VERSION 5.8 ;
BUSBITCHARS "[]" ;
DIVIDERCHAR "/" ;
UNITS
    DATABASE MICRONS 1000 ;
END UNITS

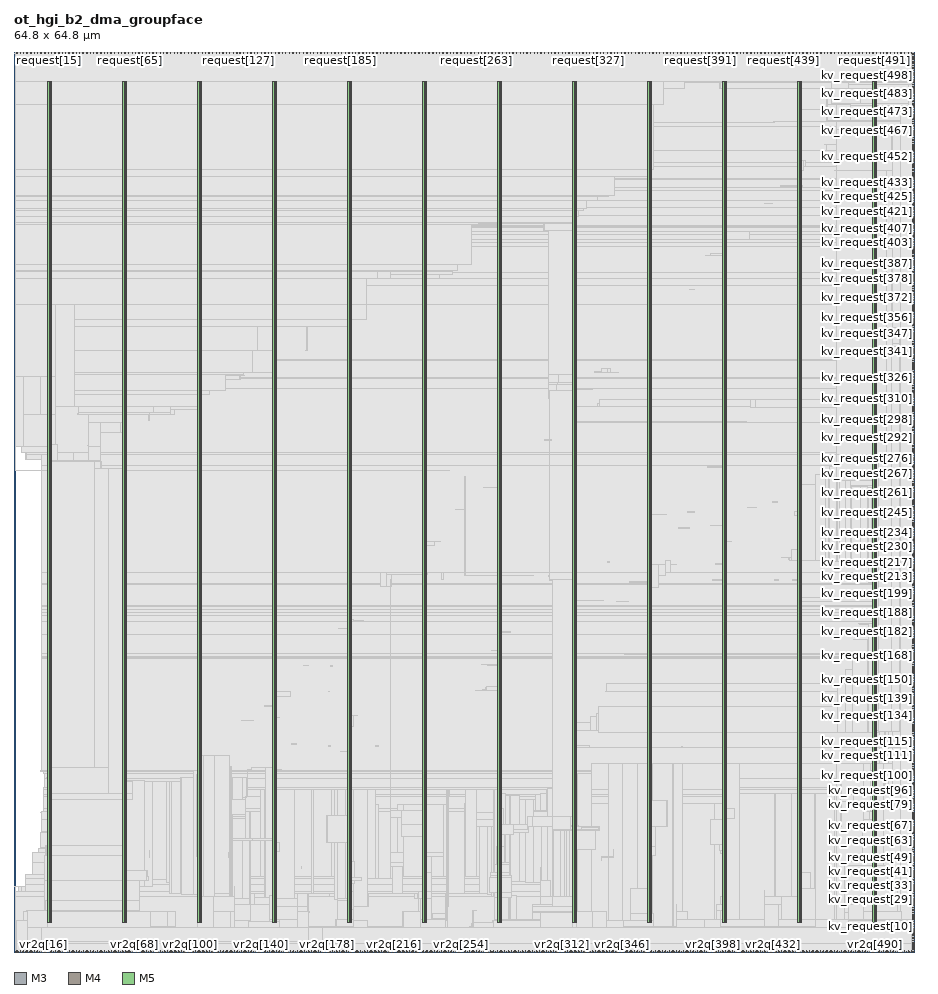
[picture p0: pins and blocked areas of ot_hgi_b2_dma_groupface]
MACRO ot_hgi_b2_dma_groupface
  FOREIGN ot_hgi_b2_dma_groupface 0 0 ;
  CLASS BLOCK ;
  SIZE 64.8 BY 64.8 ;
  PIN clk
    DIRECTION INPUT ;
    USE SIGNAL ;
    PORT
      LAYER M3 ;
        RECT  0.072 64.762 0.09 64.8 ;
    END
  END clk
  PIN kv_request[0]
    DIRECTION INPUT ;
    USE SIGNAL ;
    PORT
      LAYER M4 ;
        RECT  64.716 0.048 64.8 0.072 ;
    END
  END kv_request[0]
  PIN kv_request[100]
    DIRECTION INPUT ;
    USE SIGNAL ;
    PORT
      LAYER M4 ;
        RECT  64.716 12.72 64.8 12.744 ;
    END
  END kv_request[100]
  PIN kv_request[101]
    DIRECTION INPUT ;
    USE SIGNAL ;
    PORT
      LAYER M4 ;
        RECT  64.716 12.816 64.8 12.84 ;
    END
  END kv_request[101]
  PIN kv_request[102]
    DIRECTION INPUT ;
    USE SIGNAL ;
    PORT
      LAYER M4 ;
        RECT  64.716 12.96 64.8 12.984 ;
    END
  END kv_request[102]
  PIN kv_request[103]
    DIRECTION INPUT ;
    USE SIGNAL ;
    PORT
      LAYER M4 ;
        RECT  64.716 13.104 64.8 13.128 ;
    END
  END kv_request[103]
  PIN kv_request[104]
    DIRECTION INPUT ;
    USE SIGNAL ;
    PORT
      LAYER M4 ;
        RECT  64.716 13.2 64.8 13.224 ;
    END
  END kv_request[104]
  PIN kv_request[105]
    DIRECTION INPUT ;
    USE SIGNAL ;
    PORT
      LAYER M4 ;
        RECT  64.716 13.344 64.8 13.368 ;
    END
  END kv_request[105]
  PIN kv_request[106]
    DIRECTION INPUT ;
    USE SIGNAL ;
    PORT
      LAYER M4 ;
        RECT  64.716 13.488 64.8 13.512 ;
    END
  END kv_request[106]
  PIN kv_request[107]
    DIRECTION INPUT ;
    USE SIGNAL ;
    PORT
      LAYER M4 ;
        RECT  64.716 13.584 64.8 13.608 ;
    END
  END kv_request[107]
  PIN kv_request[108]
    DIRECTION INPUT ;
    USE SIGNAL ;
    PORT
      LAYER M4 ;
        RECT  64.716 13.728 64.8 13.752 ;
    END
  END kv_request[108]
  PIN kv_request[109]
    DIRECTION INPUT ;
    USE SIGNAL ;
    PORT
      LAYER M4 ;
        RECT  64.716 13.824 64.8 13.848 ;
    END
  END kv_request[109]
  PIN kv_request[10]
    DIRECTION INPUT ;
    USE SIGNAL ;
    PORT
      LAYER M4 ;
        RECT  64.716 1.296 64.8 1.32 ;
    END
  END kv_request[10]
  PIN kv_request[110]
    DIRECTION INPUT ;
    USE SIGNAL ;
    PORT
      LAYER M4 ;
        RECT  64.716 13.968 64.8 13.992 ;
    END
  END kv_request[110]
  PIN kv_request[111]
    DIRECTION INPUT ;
    USE SIGNAL ;
    PORT
      LAYER M4 ;
        RECT  64.716 14.112 64.8 14.136 ;
    END
  END kv_request[111]
  PIN kv_request[112]
    DIRECTION INPUT ;
    USE SIGNAL ;
    PORT
      LAYER M4 ;
        RECT  64.716 14.208 64.8 14.232 ;
    END
  END kv_request[112]
  PIN kv_request[113]
    DIRECTION INPUT ;
    USE SIGNAL ;
    PORT
      LAYER M4 ;
        RECT  64.716 14.352 64.8 14.376 ;
    END
  END kv_request[113]
  PIN kv_request[114]
    DIRECTION INPUT ;
    USE SIGNAL ;
    PORT
      LAYER M4 ;
        RECT  64.716 14.496 64.8 14.52 ;
    END
  END kv_request[114]
  PIN kv_request[115]
    DIRECTION INPUT ;
    USE SIGNAL ;
    PORT
      LAYER M4 ;
        RECT  64.716 14.592 64.8 14.616 ;
    END
  END kv_request[115]
  PIN kv_request[116]
    DIRECTION INPUT ;
    USE SIGNAL ;
    PORT
      LAYER M4 ;
        RECT  64.716 14.736 64.8 14.76 ;
    END
  END kv_request[116]
  PIN kv_request[117]
    DIRECTION INPUT ;
    USE SIGNAL ;
    PORT
      LAYER M4 ;
        RECT  64.716 14.88 64.8 14.904 ;
    END
  END kv_request[117]
  PIN kv_request[118]
    DIRECTION INPUT ;
    USE SIGNAL ;
    PORT
      LAYER M4 ;
        RECT  64.716 14.976 64.8 15 ;
    END
  END kv_request[118]
  PIN kv_request[119]
    DIRECTION INPUT ;
    USE SIGNAL ;
    PORT
      LAYER M4 ;
        RECT  64.716 15.12 64.8 15.144 ;
    END
  END kv_request[119]
  PIN kv_request[11]
    DIRECTION INPUT ;
    USE SIGNAL ;
    PORT
      LAYER M4 ;
        RECT  64.716 1.44 64.8 1.464 ;
    END
  END kv_request[11]
  PIN kv_request[120]
    DIRECTION INPUT ;
    USE SIGNAL ;
    PORT
      LAYER M4 ;
        RECT  64.716 15.216 64.8 15.24 ;
    END
  END kv_request[120]
  PIN kv_request[121]
    DIRECTION INPUT ;
    USE SIGNAL ;
    PORT
      LAYER M4 ;
        RECT  64.716 15.36 64.8 15.384 ;
    END
  END kv_request[121]
  PIN kv_request[122]
    DIRECTION INPUT ;
    USE SIGNAL ;
    PORT
      LAYER M4 ;
        RECT  64.716 15.504 64.8 15.528 ;
    END
  END kv_request[122]
  PIN kv_request[123]
    DIRECTION INPUT ;
    USE SIGNAL ;
    PORT
      LAYER M4 ;
        RECT  64.716 15.6 64.8 15.624 ;
    END
  END kv_request[123]
  PIN kv_request[124]
    DIRECTION INPUT ;
    USE SIGNAL ;
    PORT
      LAYER M4 ;
        RECT  64.716 15.744 64.8 15.768 ;
    END
  END kv_request[124]
  PIN kv_request[125]
    DIRECTION INPUT ;
    USE SIGNAL ;
    PORT
      LAYER M4 ;
        RECT  64.716 15.888 64.8 15.912 ;
    END
  END kv_request[125]
  PIN kv_request[126]
    DIRECTION INPUT ;
    USE SIGNAL ;
    PORT
      LAYER M4 ;
        RECT  64.716 15.984 64.8 16.008 ;
    END
  END kv_request[126]
  PIN kv_request[127]
    DIRECTION INPUT ;
    USE SIGNAL ;
    PORT
      LAYER M4 ;
        RECT  64.716 16.128 64.8 16.152 ;
    END
  END kv_request[127]
  PIN kv_request[128]
    DIRECTION INPUT ;
    USE SIGNAL ;
    PORT
      LAYER M4 ;
        RECT  64.716 16.272 64.8 16.296 ;
    END
  END kv_request[128]
  PIN kv_request[129]
    DIRECTION INPUT ;
    USE SIGNAL ;
    PORT
      LAYER M4 ;
        RECT  64.716 16.368 64.8 16.392 ;
    END
  END kv_request[129]
  PIN kv_request[12]
    DIRECTION INPUT ;
    USE SIGNAL ;
    PORT
      LAYER M4 ;
        RECT  64.716 1.584 64.8 1.608 ;
    END
  END kv_request[12]
  PIN kv_request[130]
    DIRECTION INPUT ;
    USE SIGNAL ;
    PORT
      LAYER M4 ;
        RECT  64.716 16.512 64.8 16.536 ;
    END
  END kv_request[130]
  PIN kv_request[131]
    DIRECTION INPUT ;
    USE SIGNAL ;
    PORT
      LAYER M4 ;
        RECT  64.716 16.608 64.8 16.632 ;
    END
  END kv_request[131]
  PIN kv_request[132]
    DIRECTION INPUT ;
    USE SIGNAL ;
    PORT
      LAYER M4 ;
        RECT  64.716 16.752 64.8 16.776 ;
    END
  END kv_request[132]
  PIN kv_request[133]
    DIRECTION INPUT ;
    USE SIGNAL ;
    PORT
      LAYER M4 ;
        RECT  64.716 16.896 64.8 16.92 ;
    END
  END kv_request[133]
  PIN kv_request[134]
    DIRECTION INPUT ;
    USE SIGNAL ;
    PORT
      LAYER M4 ;
        RECT  64.716 16.992 64.8 17.016 ;
    END
  END kv_request[134]
  PIN kv_request[135]
    DIRECTION INPUT ;
    USE SIGNAL ;
    PORT
      LAYER M4 ;
        RECT  64.716 17.136 64.8 17.16 ;
    END
  END kv_request[135]
  PIN kv_request[136]
    DIRECTION INPUT ;
    USE SIGNAL ;
    PORT
      LAYER M4 ;
        RECT  64.716 17.28 64.8 17.304 ;
    END
  END kv_request[136]
  PIN kv_request[137]
    DIRECTION INPUT ;
    USE SIGNAL ;
    PORT
      LAYER M4 ;
        RECT  64.716 17.376 64.8 17.4 ;
    END
  END kv_request[137]
  PIN kv_request[138]
    DIRECTION INPUT ;
    USE SIGNAL ;
    PORT
      LAYER M4 ;
        RECT  64.716 17.52 64.8 17.544 ;
    END
  END kv_request[138]
  PIN kv_request[139]
    DIRECTION INPUT ;
    USE SIGNAL ;
    PORT
      LAYER M4 ;
        RECT  64.716 17.664 64.8 17.688 ;
    END
  END kv_request[139]
  PIN kv_request[13]
    DIRECTION INPUT ;
    USE SIGNAL ;
    PORT
      LAYER M4 ;
        RECT  64.716 1.68 64.8 1.704 ;
    END
  END kv_request[13]
  PIN kv_request[140]
    DIRECTION INPUT ;
    USE SIGNAL ;
    PORT
      LAYER M4 ;
        RECT  64.716 17.76 64.8 17.784 ;
    END
  END kv_request[140]
  PIN kv_request[141]
    DIRECTION INPUT ;
    USE SIGNAL ;
    PORT
      LAYER M4 ;
        RECT  64.716 17.904 64.8 17.928 ;
    END
  END kv_request[141]
  PIN kv_request[142]
    DIRECTION INPUT ;
    USE SIGNAL ;
    PORT
      LAYER M4 ;
        RECT  64.716 18 64.8 18.024 ;
    END
  END kv_request[142]
  PIN kv_request[143]
    DIRECTION INPUT ;
    USE SIGNAL ;
    PORT
      LAYER M4 ;
        RECT  64.716 18.144 64.8 18.168 ;
    END
  END kv_request[143]
  PIN kv_request[144]
    DIRECTION INPUT ;
    USE SIGNAL ;
    PORT
      LAYER M4 ;
        RECT  64.716 18.288 64.8 18.312 ;
    END
  END kv_request[144]
  PIN kv_request[145]
    DIRECTION INPUT ;
    USE SIGNAL ;
    PORT
      LAYER M4 ;
        RECT  64.716 18.384 64.8 18.408 ;
    END
  END kv_request[145]
  PIN kv_request[146]
    DIRECTION INPUT ;
    USE SIGNAL ;
    PORT
      LAYER M4 ;
        RECT  64.716 18.528 64.8 18.552 ;
    END
  END kv_request[146]
  PIN kv_request[147]
    DIRECTION INPUT ;
    USE SIGNAL ;
    PORT
      LAYER M4 ;
        RECT  64.716 18.672 64.8 18.696 ;
    END
  END kv_request[147]
  PIN kv_request[148]
    DIRECTION INPUT ;
    USE SIGNAL ;
    PORT
      LAYER M4 ;
        RECT  64.716 18.768 64.8 18.792 ;
    END
  END kv_request[148]
  PIN kv_request[149]
    DIRECTION INPUT ;
    USE SIGNAL ;
    PORT
      LAYER M4 ;
        RECT  64.716 18.912 64.8 18.936 ;
    END
  END kv_request[149]
  PIN kv_request[14]
    DIRECTION INPUT ;
    USE SIGNAL ;
    PORT
      LAYER M4 ;
        RECT  64.716 1.824 64.8 1.848 ;
    END
  END kv_request[14]
  PIN kv_request[150]
    DIRECTION INPUT ;
    USE SIGNAL ;
    PORT
      LAYER M4 ;
        RECT  64.716 19.056 64.8 19.08 ;
    END
  END kv_request[150]
  PIN kv_request[151]
    DIRECTION INPUT ;
    USE SIGNAL ;
    PORT
      LAYER M4 ;
        RECT  64.716 19.152 64.8 19.176 ;
    END
  END kv_request[151]
  PIN kv_request[152]
    DIRECTION INPUT ;
    USE SIGNAL ;
    PORT
      LAYER M4 ;
        RECT  64.716 19.296 64.8 19.32 ;
    END
  END kv_request[152]
  PIN kv_request[153]
    DIRECTION INPUT ;
    USE SIGNAL ;
    PORT
      LAYER M4 ;
        RECT  64.716 19.392 64.8 19.416 ;
    END
  END kv_request[153]
  PIN kv_request[154]
    DIRECTION INPUT ;
    USE SIGNAL ;
    PORT
      LAYER M4 ;
        RECT  64.716 19.536 64.8 19.56 ;
    END
  END kv_request[154]
  PIN kv_request[155]
    DIRECTION INPUT ;
    USE SIGNAL ;
    PORT
      LAYER M4 ;
        RECT  64.716 19.68 64.8 19.704 ;
    END
  END kv_request[155]
  PIN kv_request[156]
    DIRECTION INPUT ;
    USE SIGNAL ;
    PORT
      LAYER M4 ;
        RECT  64.716 19.776 64.8 19.8 ;
    END
  END kv_request[156]
  PIN kv_request[157]
    DIRECTION INPUT ;
    USE SIGNAL ;
    PORT
      LAYER M4 ;
        RECT  64.716 19.92 64.8 19.944 ;
    END
  END kv_request[157]
  PIN kv_request[158]
    DIRECTION INPUT ;
    USE SIGNAL ;
    PORT
      LAYER M4 ;
        RECT  64.716 20.064 64.8 20.088 ;
    END
  END kv_request[158]
  PIN kv_request[159]
    DIRECTION INPUT ;
    USE SIGNAL ;
    PORT
      LAYER M4 ;
        RECT  64.716 20.16 64.8 20.184 ;
    END
  END kv_request[159]
  PIN kv_request[15]
    DIRECTION INPUT ;
    USE SIGNAL ;
    PORT
      LAYER M4 ;
        RECT  64.716 1.968 64.8 1.992 ;
    END
  END kv_request[15]
  PIN kv_request[160]
    DIRECTION INPUT ;
    USE SIGNAL ;
    PORT
      LAYER M4 ;
        RECT  64.716 20.304 64.8 20.328 ;
    END
  END kv_request[160]
  PIN kv_request[161]
    DIRECTION INPUT ;
    USE SIGNAL ;
    PORT
      LAYER M4 ;
        RECT  64.716 20.448 64.8 20.472 ;
    END
  END kv_request[161]
  PIN kv_request[162]
    DIRECTION INPUT ;
    USE SIGNAL ;
    PORT
      LAYER M4 ;
        RECT  64.716 20.544 64.8 20.568 ;
    END
  END kv_request[162]
  PIN kv_request[163]
    DIRECTION INPUT ;
    USE SIGNAL ;
    PORT
      LAYER M4 ;
        RECT  64.716 20.688 64.8 20.712 ;
    END
  END kv_request[163]
  PIN kv_request[164]
    DIRECTION INPUT ;
    USE SIGNAL ;
    PORT
      LAYER M4 ;
        RECT  64.716 20.832 64.8 20.856 ;
    END
  END kv_request[164]
  PIN kv_request[165]
    DIRECTION INPUT ;
    USE SIGNAL ;
    PORT
      LAYER M4 ;
        RECT  64.716 20.928 64.8 20.952 ;
    END
  END kv_request[165]
  PIN kv_request[166]
    DIRECTION INPUT ;
    USE SIGNAL ;
    PORT
      LAYER M4 ;
        RECT  64.716 21.072 64.8 21.096 ;
    END
  END kv_request[166]
  PIN kv_request[167]
    DIRECTION INPUT ;
    USE SIGNAL ;
    PORT
      LAYER M4 ;
        RECT  64.716 21.168 64.8 21.192 ;
    END
  END kv_request[167]
  PIN kv_request[168]
    DIRECTION INPUT ;
    USE SIGNAL ;
    PORT
      LAYER M4 ;
        RECT  64.716 21.312 64.8 21.336 ;
    END
  END kv_request[168]
  PIN kv_request[169]
    DIRECTION INPUT ;
    USE SIGNAL ;
    PORT
      LAYER M4 ;
        RECT  64.716 21.456 64.8 21.48 ;
    END
  END kv_request[169]
  PIN kv_request[16]
    DIRECTION INPUT ;
    USE SIGNAL ;
    PORT
      LAYER M4 ;
        RECT  64.716 2.064 64.8 2.088 ;
    END
  END kv_request[16]
  PIN kv_request[170]
    DIRECTION INPUT ;
    USE SIGNAL ;
    PORT
      LAYER M4 ;
        RECT  64.716 21.552 64.8 21.576 ;
    END
  END kv_request[170]
  PIN kv_request[171]
    DIRECTION INPUT ;
    USE SIGNAL ;
    PORT
      LAYER M4 ;
        RECT  64.716 21.696 64.8 21.72 ;
    END
  END kv_request[171]
  PIN kv_request[172]
    DIRECTION INPUT ;
    USE SIGNAL ;
    PORT
      LAYER M4 ;
        RECT  64.716 21.84 64.8 21.864 ;
    END
  END kv_request[172]
  PIN kv_request[173]
    DIRECTION INPUT ;
    USE SIGNAL ;
    PORT
      LAYER M4 ;
        RECT  64.716 21.936 64.8 21.96 ;
    END
  END kv_request[173]
  PIN kv_request[174]
    DIRECTION INPUT ;
    USE SIGNAL ;
    PORT
      LAYER M4 ;
        RECT  64.716 22.08 64.8 22.104 ;
    END
  END kv_request[174]
  PIN kv_request[175]
    DIRECTION INPUT ;
    USE SIGNAL ;
    PORT
      LAYER M4 ;
        RECT  64.716 22.224 64.8 22.248 ;
    END
  END kv_request[175]
  PIN kv_request[176]
    DIRECTION INPUT ;
    USE SIGNAL ;
    PORT
      LAYER M4 ;
        RECT  64.716 22.32 64.8 22.344 ;
    END
  END kv_request[176]
  PIN kv_request[177]
    DIRECTION INPUT ;
    USE SIGNAL ;
    PORT
      LAYER M4 ;
        RECT  64.716 22.464 64.8 22.488 ;
    END
  END kv_request[177]
  PIN kv_request[178]
    DIRECTION INPUT ;
    USE SIGNAL ;
    PORT
      LAYER M4 ;
        RECT  64.716 22.56 64.8 22.584 ;
    END
  END kv_request[178]
  PIN kv_request[179]
    DIRECTION INPUT ;
    USE SIGNAL ;
    PORT
      LAYER M4 ;
        RECT  64.716 22.704 64.8 22.728 ;
    END
  END kv_request[179]
  PIN kv_request[17]
    DIRECTION INPUT ;
    USE SIGNAL ;
    PORT
      LAYER M4 ;
        RECT  64.716 2.208 64.8 2.232 ;
    END
  END kv_request[17]
  PIN kv_request[180]
    DIRECTION INPUT ;
    USE SIGNAL ;
    PORT
      LAYER M4 ;
        RECT  64.716 22.848 64.8 22.872 ;
    END
  END kv_request[180]
  PIN kv_request[181]
    DIRECTION INPUT ;
    USE SIGNAL ;
    PORT
      LAYER M4 ;
        RECT  64.716 22.944 64.8 22.968 ;
    END
  END kv_request[181]
  PIN kv_request[182]
    DIRECTION INPUT ;
    USE SIGNAL ;
    PORT
      LAYER M4 ;
        RECT  64.716 23.088 64.8 23.112 ;
    END
  END kv_request[182]
  PIN kv_request[183]
    DIRECTION INPUT ;
    USE SIGNAL ;
    PORT
      LAYER M4 ;
        RECT  64.716 23.232 64.8 23.256 ;
    END
  END kv_request[183]
  PIN kv_request[184]
    DIRECTION INPUT ;
    USE SIGNAL ;
    PORT
      LAYER M4 ;
        RECT  64.716 23.328 64.8 23.352 ;
    END
  END kv_request[184]
  PIN kv_request[185]
    DIRECTION INPUT ;
    USE SIGNAL ;
    PORT
      LAYER M4 ;
        RECT  64.716 23.472 64.8 23.496 ;
    END
  END kv_request[185]
  PIN kv_request[186]
    DIRECTION INPUT ;
    USE SIGNAL ;
    PORT
      LAYER M4 ;
        RECT  64.716 23.616 64.8 23.64 ;
    END
  END kv_request[186]
  PIN kv_request[187]
    DIRECTION INPUT ;
    USE SIGNAL ;
    PORT
      LAYER M4 ;
        RECT  64.716 23.712 64.8 23.736 ;
    END
  END kv_request[187]
  PIN kv_request[188]
    DIRECTION INPUT ;
    USE SIGNAL ;
    PORT
      LAYER M4 ;
        RECT  64.716 23.856 64.8 23.88 ;
    END
  END kv_request[188]
  PIN kv_request[189]
    DIRECTION INPUT ;
    USE SIGNAL ;
    PORT
      LAYER M4 ;
        RECT  64.716 23.952 64.8 23.976 ;
    END
  END kv_request[189]
  PIN kv_request[18]
    DIRECTION INPUT ;
    USE SIGNAL ;
    PORT
      LAYER M4 ;
        RECT  64.716 2.352 64.8 2.376 ;
    END
  END kv_request[18]
  PIN kv_request[190]
    DIRECTION INPUT ;
    USE SIGNAL ;
    PORT
      LAYER M4 ;
        RECT  64.716 24.096 64.8 24.12 ;
    END
  END kv_request[190]
  PIN kv_request[191]
    DIRECTION INPUT ;
    USE SIGNAL ;
    PORT
      LAYER M4 ;
        RECT  64.716 24.24 64.8 24.264 ;
    END
  END kv_request[191]
  PIN kv_request[192]
    DIRECTION INPUT ;
    USE SIGNAL ;
    PORT
      LAYER M4 ;
        RECT  64.716 24.336 64.8 24.36 ;
    END
  END kv_request[192]
  PIN kv_request[193]
    DIRECTION INPUT ;
    USE SIGNAL ;
    PORT
      LAYER M4 ;
        RECT  64.716 24.48 64.8 24.504 ;
    END
  END kv_request[193]
  PIN kv_request[194]
    DIRECTION INPUT ;
    USE SIGNAL ;
    PORT
      LAYER M4 ;
        RECT  64.716 24.624 64.8 24.648 ;
    END
  END kv_request[194]
  PIN kv_request[195]
    DIRECTION INPUT ;
    USE SIGNAL ;
    PORT
      LAYER M4 ;
        RECT  64.716 24.72 64.8 24.744 ;
    END
  END kv_request[195]
  PIN kv_request[196]
    DIRECTION INPUT ;
    USE SIGNAL ;
    PORT
      LAYER M4 ;
        RECT  64.716 24.864 64.8 24.888 ;
    END
  END kv_request[196]
  PIN kv_request[197]
    DIRECTION INPUT ;
    USE SIGNAL ;
    PORT
      LAYER M4 ;
        RECT  64.716 25.008 64.8 25.032 ;
    END
  END kv_request[197]
  PIN kv_request[198]
    DIRECTION INPUT ;
    USE SIGNAL ;
    PORT
      LAYER M4 ;
        RECT  64.716 25.104 64.8 25.128 ;
    END
  END kv_request[198]
  PIN kv_request[199]
    DIRECTION INPUT ;
    USE SIGNAL ;
    PORT
      LAYER M4 ;
        RECT  64.716 25.248 64.8 25.272 ;
    END
  END kv_request[199]
  PIN kv_request[19]
    DIRECTION INPUT ;
    USE SIGNAL ;
    PORT
      LAYER M4 ;
        RECT  64.716 2.448 64.8 2.472 ;
    END
  END kv_request[19]
  PIN kv_request[1]
    DIRECTION INPUT ;
    USE SIGNAL ;
    PORT
      LAYER M4 ;
        RECT  64.716 0.192 64.8 0.216 ;
    END
  END kv_request[1]
  PIN kv_request[200]
    DIRECTION INPUT ;
    USE SIGNAL ;
    PORT
      LAYER M4 ;
        RECT  64.716 25.344 64.8 25.368 ;
    END
  END kv_request[200]
  PIN kv_request[201]
    DIRECTION INPUT ;
    USE SIGNAL ;
    PORT
      LAYER M4 ;
        RECT  64.716 25.488 64.8 25.512 ;
    END
  END kv_request[201]
  PIN kv_request[202]
    DIRECTION INPUT ;
    USE SIGNAL ;
    PORT
      LAYER M4 ;
        RECT  64.716 25.632 64.8 25.656 ;
    END
  END kv_request[202]
  PIN kv_request[203]
    DIRECTION INPUT ;
    USE SIGNAL ;
    PORT
      LAYER M4 ;
        RECT  64.716 25.728 64.8 25.752 ;
    END
  END kv_request[203]
  PIN kv_request[204]
    DIRECTION INPUT ;
    USE SIGNAL ;
    PORT
      LAYER M4 ;
        RECT  64.716 25.872 64.8 25.896 ;
    END
  END kv_request[204]
  PIN kv_request[205]
    DIRECTION INPUT ;
    USE SIGNAL ;
    PORT
      LAYER M4 ;
        RECT  64.716 26.016 64.8 26.04 ;
    END
  END kv_request[205]
  PIN kv_request[206]
    DIRECTION INPUT ;
    USE SIGNAL ;
    PORT
      LAYER M4 ;
        RECT  64.716 26.112 64.8 26.136 ;
    END
  END kv_request[206]
  PIN kv_request[207]
    DIRECTION INPUT ;
    USE SIGNAL ;
    PORT
      LAYER M4 ;
        RECT  64.716 26.256 64.8 26.28 ;
    END
  END kv_request[207]
  PIN kv_request[208]
    DIRECTION INPUT ;
    USE SIGNAL ;
    PORT
      LAYER M4 ;
        RECT  64.716 26.4 64.8 26.424 ;
    END
  END kv_request[208]
  PIN kv_request[209]
    DIRECTION INPUT ;
    USE SIGNAL ;
    PORT
      LAYER M4 ;
        RECT  64.716 26.496 64.8 26.52 ;
    END
  END kv_request[209]
  PIN kv_request[20]
    DIRECTION INPUT ;
    USE SIGNAL ;
    PORT
      LAYER M4 ;
        RECT  64.716 2.592 64.8 2.616 ;
    END
  END kv_request[20]
  PIN kv_request[210]
    DIRECTION INPUT ;
    USE SIGNAL ;
    PORT
      LAYER M4 ;
        RECT  64.716 26.64 64.8 26.664 ;
    END
  END kv_request[210]
  PIN kv_request[211]
    DIRECTION INPUT ;
    USE SIGNAL ;
    PORT
      LAYER M4 ;
        RECT  64.716 26.736 64.8 26.76 ;
    END
  END kv_request[211]
  PIN kv_request[212]
    DIRECTION INPUT ;
    USE SIGNAL ;
    PORT
      LAYER M4 ;
        RECT  64.716 26.88 64.8 26.904 ;
    END
  END kv_request[212]
  PIN kv_request[213]
    DIRECTION INPUT ;
    USE SIGNAL ;
    PORT
      LAYER M4 ;
        RECT  64.716 27.024 64.8 27.048 ;
    END
  END kv_request[213]
  PIN kv_request[214]
    DIRECTION INPUT ;
    USE SIGNAL ;
    PORT
      LAYER M4 ;
        RECT  64.716 27.12 64.8 27.144 ;
    END
  END kv_request[214]
  PIN kv_request[215]
    DIRECTION INPUT ;
    USE SIGNAL ;
    PORT
      LAYER M4 ;
        RECT  64.716 27.264 64.8 27.288 ;
    END
  END kv_request[215]
  PIN kv_request[216]
    DIRECTION INPUT ;
    USE SIGNAL ;
    PORT
      LAYER M4 ;
        RECT  64.716 27.408 64.8 27.432 ;
    END
  END kv_request[216]
  PIN kv_request[217]
    DIRECTION INPUT ;
    USE SIGNAL ;
    PORT
      LAYER M4 ;
        RECT  64.716 27.504 64.8 27.528 ;
    END
  END kv_request[217]
  PIN kv_request[218]
    DIRECTION INPUT ;
    USE SIGNAL ;
    PORT
      LAYER M4 ;
        RECT  64.716 27.648 64.8 27.672 ;
    END
  END kv_request[218]
  PIN kv_request[219]
    DIRECTION INPUT ;
    USE SIGNAL ;
    PORT
      LAYER M4 ;
        RECT  64.716 27.792 64.8 27.816 ;
    END
  END kv_request[219]
  PIN kv_request[21]
    DIRECTION INPUT ;
    USE SIGNAL ;
    PORT
      LAYER M4 ;
        RECT  64.716 2.688 64.8 2.712 ;
    END
  END kv_request[21]
  PIN kv_request[220]
    DIRECTION INPUT ;
    USE SIGNAL ;
    PORT
      LAYER M4 ;
        RECT  64.716 27.888 64.8 27.912 ;
    END
  END kv_request[220]
  PIN kv_request[221]
    DIRECTION INPUT ;
    USE SIGNAL ;
    PORT
      LAYER M4 ;
        RECT  64.716 28.032 64.8 28.056 ;
    END
  END kv_request[221]
  PIN kv_request[222]
    DIRECTION INPUT ;
    USE SIGNAL ;
    PORT
      LAYER M4 ;
        RECT  64.716 28.128 64.8 28.152 ;
    END
  END kv_request[222]
  PIN kv_request[223]
    DIRECTION INPUT ;
    USE SIGNAL ;
    PORT
      LAYER M4 ;
        RECT  64.716 28.272 64.8 28.296 ;
    END
  END kv_request[223]
  PIN kv_request[224]
    DIRECTION INPUT ;
    USE SIGNAL ;
    PORT
      LAYER M4 ;
        RECT  64.716 28.416 64.8 28.44 ;
    END
  END kv_request[224]
  PIN kv_request[225]
    DIRECTION INPUT ;
    USE SIGNAL ;
    PORT
      LAYER M4 ;
        RECT  64.716 28.512 64.8 28.536 ;
    END
  END kv_request[225]
  PIN kv_request[226]
    DIRECTION INPUT ;
    USE SIGNAL ;
    PORT
      LAYER M4 ;
        RECT  64.716 28.656 64.8 28.68 ;
    END
  END kv_request[226]
  PIN kv_request[227]
    DIRECTION INPUT ;
    USE SIGNAL ;
    PORT
      LAYER M4 ;
        RECT  64.716 28.8 64.8 28.824 ;
    END
  END kv_request[227]
  PIN kv_request[228]
    DIRECTION INPUT ;
    USE SIGNAL ;
    PORT
      LAYER M4 ;
        RECT  64.716 28.896 64.8 28.92 ;
    END
  END kv_request[228]
  PIN kv_request[229]
    DIRECTION INPUT ;
    USE SIGNAL ;
    PORT
      LAYER M4 ;
        RECT  64.716 29.04 64.8 29.064 ;
    END
  END kv_request[229]
  PIN kv_request[22]
    DIRECTION INPUT ;
    USE SIGNAL ;
    PORT
      LAYER M4 ;
        RECT  64.716 2.832 64.8 2.856 ;
    END
  END kv_request[22]
  PIN kv_request[230]
    DIRECTION INPUT ;
    USE SIGNAL ;
    PORT
      LAYER M4 ;
        RECT  64.716 29.184 64.8 29.208 ;
    END
  END kv_request[230]
  PIN kv_request[231]
    DIRECTION INPUT ;
    USE SIGNAL ;
    PORT
      LAYER M4 ;
        RECT  64.716 29.28 64.8 29.304 ;
    END
  END kv_request[231]
  PIN kv_request[232]
    DIRECTION INPUT ;
    USE SIGNAL ;
    PORT
      LAYER M4 ;
        RECT  64.716 29.424 64.8 29.448 ;
    END
  END kv_request[232]
  PIN kv_request[233]
    DIRECTION INPUT ;
    USE SIGNAL ;
    PORT
      LAYER M4 ;
        RECT  64.716 29.52 64.8 29.544 ;
    END
  END kv_request[233]
  PIN kv_request[234]
    DIRECTION INPUT ;
    USE SIGNAL ;
    PORT
      LAYER M4 ;
        RECT  64.716 29.664 64.8 29.688 ;
    END
  END kv_request[234]
  PIN kv_request[235]
    DIRECTION INPUT ;
    USE SIGNAL ;
    PORT
      LAYER M4 ;
        RECT  64.716 29.808 64.8 29.832 ;
    END
  END kv_request[235]
  PIN kv_request[236]
    DIRECTION INPUT ;
    USE SIGNAL ;
    PORT
      LAYER M4 ;
        RECT  64.716 29.904 64.8 29.928 ;
    END
  END kv_request[236]
  PIN kv_request[237]
    DIRECTION INPUT ;
    USE SIGNAL ;
    PORT
      LAYER M4 ;
        RECT  64.716 30.048 64.8 30.072 ;
    END
  END kv_request[237]
  PIN kv_request[238]
    DIRECTION INPUT ;
    USE SIGNAL ;
    PORT
      LAYER M4 ;
        RECT  64.716 30.192 64.8 30.216 ;
    END
  END kv_request[238]
  PIN kv_request[239]
    DIRECTION INPUT ;
    USE SIGNAL ;
    PORT
      LAYER M4 ;
        RECT  64.716 30.288 64.8 30.312 ;
    END
  END kv_request[239]
  PIN kv_request[23]
    DIRECTION INPUT ;
    USE SIGNAL ;
    PORT
      LAYER M4 ;
        RECT  64.716 2.976 64.8 3 ;
    END
  END kv_request[23]
  PIN kv_request[240]
    DIRECTION INPUT ;
    USE SIGNAL ;
    PORT
      LAYER M4 ;
        RECT  64.716 30.432 64.8 30.456 ;
    END
  END kv_request[240]
  PIN kv_request[241]
    DIRECTION INPUT ;
    USE SIGNAL ;
    PORT
      LAYER M4 ;
        RECT  64.716 30.576 64.8 30.6 ;
    END
  END kv_request[241]
  PIN kv_request[242]
    DIRECTION INPUT ;
    USE SIGNAL ;
    PORT
      LAYER M4 ;
        RECT  64.716 30.672 64.8 30.696 ;
    END
  END kv_request[242]
  PIN kv_request[243]
    DIRECTION INPUT ;
    USE SIGNAL ;
    PORT
      LAYER M4 ;
        RECT  64.716 30.816 64.8 30.84 ;
    END
  END kv_request[243]
  PIN kv_request[244]
    DIRECTION INPUT ;
    USE SIGNAL ;
    PORT
      LAYER M4 ;
        RECT  64.716 30.912 64.8 30.936 ;
    END
  END kv_request[244]
  PIN kv_request[245]
    DIRECTION INPUT ;
    USE SIGNAL ;
    PORT
      LAYER M4 ;
        RECT  64.716 31.056 64.8 31.08 ;
    END
  END kv_request[245]
  PIN kv_request[246]
    DIRECTION INPUT ;
    USE SIGNAL ;
    PORT
      LAYER M4 ;
        RECT  64.716 31.2 64.8 31.224 ;
    END
  END kv_request[246]
  PIN kv_request[247]
    DIRECTION INPUT ;
    USE SIGNAL ;
    PORT
      LAYER M4 ;
        RECT  64.716 31.296 64.8 31.32 ;
    END
  END kv_request[247]
  PIN kv_request[248]
    DIRECTION INPUT ;
    USE SIGNAL ;
    PORT
      LAYER M4 ;
        RECT  64.716 31.44 64.8 31.464 ;
    END
  END kv_request[248]
  PIN kv_request[249]
    DIRECTION INPUT ;
    USE SIGNAL ;
    PORT
      LAYER M4 ;
        RECT  64.716 31.584 64.8 31.608 ;
    END
  END kv_request[249]
  PIN kv_request[24]
    DIRECTION INPUT ;
    USE SIGNAL ;
    PORT
      LAYER M4 ;
        RECT  64.716 3.072 64.8 3.096 ;
    END
  END kv_request[24]
  PIN kv_request[250]
    DIRECTION INPUT ;
    USE SIGNAL ;
    PORT
      LAYER M4 ;
        RECT  64.716 31.68 64.8 31.704 ;
    END
  END kv_request[250]
  PIN kv_request[251]
    DIRECTION INPUT ;
    USE SIGNAL ;
    PORT
      LAYER M4 ;
        RECT  64.716 31.824 64.8 31.848 ;
    END
  END kv_request[251]
  PIN kv_request[252]
    DIRECTION INPUT ;
    USE SIGNAL ;
    PORT
      LAYER M4 ;
        RECT  64.716 31.968 64.8 31.992 ;
    END
  END kv_request[252]
  PIN kv_request[253]
    DIRECTION INPUT ;
    USE SIGNAL ;
    PORT
      LAYER M4 ;
        RECT  64.716 32.064 64.8 32.088 ;
    END
  END kv_request[253]
  PIN kv_request[254]
    DIRECTION INPUT ;
    USE SIGNAL ;
    PORT
      LAYER M4 ;
        RECT  64.716 32.208 64.8 32.232 ;
    END
  END kv_request[254]
  PIN kv_request[255]
    DIRECTION INPUT ;
    USE SIGNAL ;
    PORT
      LAYER M4 ;
        RECT  64.716 32.304 64.8 32.328 ;
    END
  END kv_request[255]
  PIN kv_request[256]
    DIRECTION INPUT ;
    USE SIGNAL ;
    PORT
      LAYER M4 ;
        RECT  64.716 32.448 64.8 32.472 ;
    END
  END kv_request[256]
  PIN kv_request[257]
    DIRECTION INPUT ;
    USE SIGNAL ;
    PORT
      LAYER M4 ;
        RECT  64.716 32.592 64.8 32.616 ;
    END
  END kv_request[257]
  PIN kv_request[258]
    DIRECTION INPUT ;
    USE SIGNAL ;
    PORT
      LAYER M4 ;
        RECT  64.716 32.688 64.8 32.712 ;
    END
  END kv_request[258]
  PIN kv_request[259]
    DIRECTION INPUT ;
    USE SIGNAL ;
    PORT
      LAYER M4 ;
        RECT  64.716 32.832 64.8 32.856 ;
    END
  END kv_request[259]
  PIN kv_request[25]
    DIRECTION INPUT ;
    USE SIGNAL ;
    PORT
      LAYER M4 ;
        RECT  64.716 3.216 64.8 3.24 ;
    END
  END kv_request[25]
  PIN kv_request[260]
    DIRECTION INPUT ;
    USE SIGNAL ;
    PORT
      LAYER M4 ;
        RECT  64.716 32.976 64.8 33 ;
    END
  END kv_request[260]
  PIN kv_request[261]
    DIRECTION INPUT ;
    USE SIGNAL ;
    PORT
      LAYER M4 ;
        RECT  64.716 33.072 64.8 33.096 ;
    END
  END kv_request[261]
  PIN kv_request[262]
    DIRECTION INPUT ;
    USE SIGNAL ;
    PORT
      LAYER M4 ;
        RECT  64.716 33.216 64.8 33.24 ;
    END
  END kv_request[262]
  PIN kv_request[263]
    DIRECTION INPUT ;
    USE SIGNAL ;
    PORT
      LAYER M4 ;
        RECT  64.716 33.36 64.8 33.384 ;
    END
  END kv_request[263]
  PIN kv_request[264]
    DIRECTION INPUT ;
    USE SIGNAL ;
    PORT
      LAYER M4 ;
        RECT  64.716 33.456 64.8 33.48 ;
    END
  END kv_request[264]
  PIN kv_request[265]
    DIRECTION INPUT ;
    USE SIGNAL ;
    PORT
      LAYER M4 ;
        RECT  64.716 33.6 64.8 33.624 ;
    END
  END kv_request[265]
  PIN kv_request[266]
    DIRECTION INPUT ;
    USE SIGNAL ;
    PORT
      LAYER M4 ;
        RECT  64.716 33.696 64.8 33.72 ;
    END
  END kv_request[266]
  PIN kv_request[267]
    DIRECTION INPUT ;
    USE SIGNAL ;
    PORT
      LAYER M4 ;
        RECT  64.716 33.84 64.8 33.864 ;
    END
  END kv_request[267]
  PIN kv_request[268]
    DIRECTION INPUT ;
    USE SIGNAL ;
    PORT
      LAYER M4 ;
        RECT  64.716 33.984 64.8 34.008 ;
    END
  END kv_request[268]
  PIN kv_request[269]
    DIRECTION INPUT ;
    USE SIGNAL ;
    PORT
      LAYER M4 ;
        RECT  64.716 34.08 64.8 34.104 ;
    END
  END kv_request[269]
  PIN kv_request[26]
    DIRECTION INPUT ;
    USE SIGNAL ;
    PORT
      LAYER M4 ;
        RECT  64.716 3.36 64.8 3.384 ;
    END
  END kv_request[26]
  PIN kv_request[270]
    DIRECTION INPUT ;
    USE SIGNAL ;
    PORT
      LAYER M4 ;
        RECT  64.716 34.224 64.8 34.248 ;
    END
  END kv_request[270]
  PIN kv_request[271]
    DIRECTION INPUT ;
    USE SIGNAL ;
    PORT
      LAYER M4 ;
        RECT  64.716 34.368 64.8 34.392 ;
    END
  END kv_request[271]
  PIN kv_request[272]
    DIRECTION INPUT ;
    USE SIGNAL ;
    PORT
      LAYER M4 ;
        RECT  64.716 34.464 64.8 34.488 ;
    END
  END kv_request[272]
  PIN kv_request[273]
    DIRECTION INPUT ;
    USE SIGNAL ;
    PORT
      LAYER M4 ;
        RECT  64.716 34.608 64.8 34.632 ;
    END
  END kv_request[273]
  PIN kv_request[274]
    DIRECTION INPUT ;
    USE SIGNAL ;
    PORT
      LAYER M4 ;
        RECT  64.716 34.752 64.8 34.776 ;
    END
  END kv_request[274]
  PIN kv_request[275]
    DIRECTION INPUT ;
    USE SIGNAL ;
    PORT
      LAYER M4 ;
        RECT  64.716 34.848 64.8 34.872 ;
    END
  END kv_request[275]
  PIN kv_request[276]
    DIRECTION INPUT ;
    USE SIGNAL ;
    PORT
      LAYER M4 ;
        RECT  64.716 34.992 64.8 35.016 ;
    END
  END kv_request[276]
  PIN kv_request[277]
    DIRECTION INPUT ;
    USE SIGNAL ;
    PORT
      LAYER M4 ;
        RECT  64.716 35.088 64.8 35.112 ;
    END
  END kv_request[277]
  PIN kv_request[278]
    DIRECTION INPUT ;
    USE SIGNAL ;
    PORT
      LAYER M4 ;
        RECT  64.716 35.232 64.8 35.256 ;
    END
  END kv_request[278]
  PIN kv_request[279]
    DIRECTION INPUT ;
    USE SIGNAL ;
    PORT
      LAYER M4 ;
        RECT  64.716 35.376 64.8 35.4 ;
    END
  END kv_request[279]
  PIN kv_request[27]
    DIRECTION INPUT ;
    USE SIGNAL ;
    PORT
      LAYER M4 ;
        RECT  64.716 3.456 64.8 3.48 ;
    END
  END kv_request[27]
  PIN kv_request[280]
    DIRECTION INPUT ;
    USE SIGNAL ;
    PORT
      LAYER M4 ;
        RECT  64.716 35.472 64.8 35.496 ;
    END
  END kv_request[280]
  PIN kv_request[281]
    DIRECTION INPUT ;
    USE SIGNAL ;
    PORT
      LAYER M4 ;
        RECT  64.716 35.616 64.8 35.64 ;
    END
  END kv_request[281]
  PIN kv_request[282]
    DIRECTION INPUT ;
    USE SIGNAL ;
    PORT
      LAYER M4 ;
        RECT  64.716 35.76 64.8 35.784 ;
    END
  END kv_request[282]
  PIN kv_request[283]
    DIRECTION INPUT ;
    USE SIGNAL ;
    PORT
      LAYER M4 ;
        RECT  64.716 35.856 64.8 35.88 ;
    END
  END kv_request[283]
  PIN kv_request[284]
    DIRECTION INPUT ;
    USE SIGNAL ;
    PORT
      LAYER M4 ;
        RECT  64.716 36 64.8 36.024 ;
    END
  END kv_request[284]
  PIN kv_request[285]
    DIRECTION INPUT ;
    USE SIGNAL ;
    PORT
      LAYER M4 ;
        RECT  64.716 36.144 64.8 36.168 ;
    END
  END kv_request[285]
  PIN kv_request[286]
    DIRECTION INPUT ;
    USE SIGNAL ;
    PORT
      LAYER M4 ;
        RECT  64.716 36.24 64.8 36.264 ;
    END
  END kv_request[286]
  PIN kv_request[287]
    DIRECTION INPUT ;
    USE SIGNAL ;
    PORT
      LAYER M4 ;
        RECT  64.716 36.384 64.8 36.408 ;
    END
  END kv_request[287]
  PIN kv_request[288]
    DIRECTION INPUT ;
    USE SIGNAL ;
    PORT
      LAYER M4 ;
        RECT  64.716 36.48 64.8 36.504 ;
    END
  END kv_request[288]
  PIN kv_request[289]
    DIRECTION INPUT ;
    USE SIGNAL ;
    PORT
      LAYER M4 ;
        RECT  64.716 36.624 64.8 36.648 ;
    END
  END kv_request[289]
  PIN kv_request[28]
    DIRECTION INPUT ;
    USE SIGNAL ;
    PORT
      LAYER M4 ;
        RECT  64.716 3.6 64.8 3.624 ;
    END
  END kv_request[28]
  PIN kv_request[290]
    DIRECTION INPUT ;
    USE SIGNAL ;
    PORT
      LAYER M4 ;
        RECT  64.716 36.768 64.8 36.792 ;
    END
  END kv_request[290]
  PIN kv_request[291]
    DIRECTION INPUT ;
    USE SIGNAL ;
    PORT
      LAYER M4 ;
        RECT  64.716 36.864 64.8 36.888 ;
    END
  END kv_request[291]
  PIN kv_request[292]
    DIRECTION INPUT ;
    USE SIGNAL ;
    PORT
      LAYER M4 ;
        RECT  64.716 37.008 64.8 37.032 ;
    END
  END kv_request[292]
  PIN kv_request[293]
    DIRECTION INPUT ;
    USE SIGNAL ;
    PORT
      LAYER M4 ;
        RECT  64.716 37.152 64.8 37.176 ;
    END
  END kv_request[293]
  PIN kv_request[294]
    DIRECTION INPUT ;
    USE SIGNAL ;
    PORT
      LAYER M4 ;
        RECT  64.716 37.248 64.8 37.272 ;
    END
  END kv_request[294]
  PIN kv_request[295]
    DIRECTION INPUT ;
    USE SIGNAL ;
    PORT
      LAYER M4 ;
        RECT  64.716 37.392 64.8 37.416 ;
    END
  END kv_request[295]
  PIN kv_request[296]
    DIRECTION INPUT ;
    USE SIGNAL ;
    PORT
      LAYER M4 ;
        RECT  64.716 37.536 64.8 37.56 ;
    END
  END kv_request[296]
  PIN kv_request[297]
    DIRECTION INPUT ;
    USE SIGNAL ;
    PORT
      LAYER M4 ;
        RECT  64.716 37.632 64.8 37.656 ;
    END
  END kv_request[297]
  PIN kv_request[298]
    DIRECTION INPUT ;
    USE SIGNAL ;
    PORT
      LAYER M4 ;
        RECT  64.716 37.776 64.8 37.8 ;
    END
  END kv_request[298]
  PIN kv_request[299]
    DIRECTION INPUT ;
    USE SIGNAL ;
    PORT
      LAYER M4 ;
        RECT  64.716 37.872 64.8 37.896 ;
    END
  END kv_request[299]
  PIN kv_request[29]
    DIRECTION INPUT ;
    USE SIGNAL ;
    PORT
      LAYER M4 ;
        RECT  64.716 3.744 64.8 3.768 ;
    END
  END kv_request[29]
  PIN kv_request[2]
    DIRECTION INPUT ;
    USE SIGNAL ;
    PORT
      LAYER M4 ;
        RECT  64.716 0.288 64.8 0.312 ;
    END
  END kv_request[2]
  PIN kv_request[300]
    DIRECTION INPUT ;
    USE SIGNAL ;
    PORT
      LAYER M4 ;
        RECT  64.716 38.016 64.8 38.04 ;
    END
  END kv_request[300]
  PIN kv_request[301]
    DIRECTION INPUT ;
    USE SIGNAL ;
    PORT
      LAYER M4 ;
        RECT  64.716 38.16 64.8 38.184 ;
    END
  END kv_request[301]
  PIN kv_request[302]
    DIRECTION INPUT ;
    USE SIGNAL ;
    PORT
      LAYER M4 ;
        RECT  64.716 38.256 64.8 38.28 ;
    END
  END kv_request[302]
  PIN kv_request[303]
    DIRECTION INPUT ;
    USE SIGNAL ;
    PORT
      LAYER M4 ;
        RECT  64.716 38.4 64.8 38.424 ;
    END
  END kv_request[303]
  PIN kv_request[304]
    DIRECTION INPUT ;
    USE SIGNAL ;
    PORT
      LAYER M4 ;
        RECT  64.716 38.544 64.8 38.568 ;
    END
  END kv_request[304]
  PIN kv_request[305]
    DIRECTION INPUT ;
    USE SIGNAL ;
    PORT
      LAYER M4 ;
        RECT  64.716 38.64 64.8 38.664 ;
    END
  END kv_request[305]
  PIN kv_request[306]
    DIRECTION INPUT ;
    USE SIGNAL ;
    PORT
      LAYER M4 ;
        RECT  64.716 38.784 64.8 38.808 ;
    END
  END kv_request[306]
  PIN kv_request[307]
    DIRECTION INPUT ;
    USE SIGNAL ;
    PORT
      LAYER M4 ;
        RECT  64.716 38.928 64.8 38.952 ;
    END
  END kv_request[307]
  PIN kv_request[308]
    DIRECTION INPUT ;
    USE SIGNAL ;
    PORT
      LAYER M4 ;
        RECT  64.716 39.024 64.8 39.048 ;
    END
  END kv_request[308]
  PIN kv_request[309]
    DIRECTION INPUT ;
    USE SIGNAL ;
    PORT
      LAYER M4 ;
        RECT  64.716 39.168 64.8 39.192 ;
    END
  END kv_request[309]
  PIN kv_request[30]
    DIRECTION INPUT ;
    USE SIGNAL ;
    PORT
      LAYER M4 ;
        RECT  64.716 3.84 64.8 3.864 ;
    END
  END kv_request[30]
  PIN kv_request[310]
    DIRECTION INPUT ;
    USE SIGNAL ;
    PORT
      LAYER M4 ;
        RECT  64.716 39.264 64.8 39.288 ;
    END
  END kv_request[310]
  PIN kv_request[311]
    DIRECTION INPUT ;
    USE SIGNAL ;
    PORT
      LAYER M4 ;
        RECT  64.716 39.408 64.8 39.432 ;
    END
  END kv_request[311]
  PIN kv_request[312]
    DIRECTION INPUT ;
    USE SIGNAL ;
    PORT
      LAYER M4 ;
        RECT  64.716 39.552 64.8 39.576 ;
    END
  END kv_request[312]
  PIN kv_request[313]
    DIRECTION INPUT ;
    USE SIGNAL ;
    PORT
      LAYER M4 ;
        RECT  64.716 39.648 64.8 39.672 ;
    END
  END kv_request[313]
  PIN kv_request[314]
    DIRECTION INPUT ;
    USE SIGNAL ;
    PORT
      LAYER M4 ;
        RECT  64.716 39.792 64.8 39.816 ;
    END
  END kv_request[314]
  PIN kv_request[315]
    DIRECTION INPUT ;
    USE SIGNAL ;
    PORT
      LAYER M4 ;
        RECT  64.716 39.936 64.8 39.96 ;
    END
  END kv_request[315]
  PIN kv_request[316]
    DIRECTION INPUT ;
    USE SIGNAL ;
    PORT
      LAYER M4 ;
        RECT  64.716 40.032 64.8 40.056 ;
    END
  END kv_request[316]
  PIN kv_request[317]
    DIRECTION INPUT ;
    USE SIGNAL ;
    PORT
      LAYER M4 ;
        RECT  64.716 40.176 64.8 40.2 ;
    END
  END kv_request[317]
  PIN kv_request[318]
    DIRECTION INPUT ;
    USE SIGNAL ;
    PORT
      LAYER M4 ;
        RECT  64.716 40.32 64.8 40.344 ;
    END
  END kv_request[318]
  PIN kv_request[319]
    DIRECTION INPUT ;
    USE SIGNAL ;
    PORT
      LAYER M4 ;
        RECT  64.716 40.416 64.8 40.44 ;
    END
  END kv_request[319]
  PIN kv_request[31]
    DIRECTION INPUT ;
    USE SIGNAL ;
    PORT
      LAYER M4 ;
        RECT  64.716 3.984 64.8 4.008 ;
    END
  END kv_request[31]
  PIN kv_request[320]
    DIRECTION INPUT ;
    USE SIGNAL ;
    PORT
      LAYER M4 ;
        RECT  64.716 40.56 64.8 40.584 ;
    END
  END kv_request[320]
  PIN kv_request[321]
    DIRECTION INPUT ;
    USE SIGNAL ;
    PORT
      LAYER M4 ;
        RECT  64.716 40.656 64.8 40.68 ;
    END
  END kv_request[321]
  PIN kv_request[322]
    DIRECTION INPUT ;
    USE SIGNAL ;
    PORT
      LAYER M4 ;
        RECT  64.716 40.8 64.8 40.824 ;
    END
  END kv_request[322]
  PIN kv_request[323]
    DIRECTION INPUT ;
    USE SIGNAL ;
    PORT
      LAYER M4 ;
        RECT  64.716 40.944 64.8 40.968 ;
    END
  END kv_request[323]
  PIN kv_request[324]
    DIRECTION INPUT ;
    USE SIGNAL ;
    PORT
      LAYER M4 ;
        RECT  64.716 41.04 64.8 41.064 ;
    END
  END kv_request[324]
  PIN kv_request[325]
    DIRECTION INPUT ;
    USE SIGNAL ;
    PORT
      LAYER M4 ;
        RECT  64.716 41.184 64.8 41.208 ;
    END
  END kv_request[325]
  PIN kv_request[326]
    DIRECTION INPUT ;
    USE SIGNAL ;
    PORT
      LAYER M4 ;
        RECT  64.716 41.328 64.8 41.352 ;
    END
  END kv_request[326]
  PIN kv_request[327]
    DIRECTION INPUT ;
    USE SIGNAL ;
    PORT
      LAYER M4 ;
        RECT  64.716 41.424 64.8 41.448 ;
    END
  END kv_request[327]
  PIN kv_request[328]
    DIRECTION INPUT ;
    USE SIGNAL ;
    PORT
      LAYER M4 ;
        RECT  64.716 41.568 64.8 41.592 ;
    END
  END kv_request[328]
  PIN kv_request[329]
    DIRECTION INPUT ;
    USE SIGNAL ;
    PORT
      LAYER M4 ;
        RECT  64.716 41.712 64.8 41.736 ;
    END
  END kv_request[329]
  PIN kv_request[32]
    DIRECTION INPUT ;
    USE SIGNAL ;
    PORT
      LAYER M4 ;
        RECT  64.716 4.08 64.8 4.104 ;
    END
  END kv_request[32]
  PIN kv_request[330]
    DIRECTION INPUT ;
    USE SIGNAL ;
    PORT
      LAYER M4 ;
        RECT  64.716 41.808 64.8 41.832 ;
    END
  END kv_request[330]
  PIN kv_request[331]
    DIRECTION INPUT ;
    USE SIGNAL ;
    PORT
      LAYER M4 ;
        RECT  64.716 41.952 64.8 41.976 ;
    END
  END kv_request[331]
  PIN kv_request[332]
    DIRECTION INPUT ;
    USE SIGNAL ;
    PORT
      LAYER M4 ;
        RECT  64.716 42.048 64.8 42.072 ;
    END
  END kv_request[332]
  PIN kv_request[333]
    DIRECTION INPUT ;
    USE SIGNAL ;
    PORT
      LAYER M4 ;
        RECT  64.716 42.192 64.8 42.216 ;
    END
  END kv_request[333]
  PIN kv_request[334]
    DIRECTION INPUT ;
    USE SIGNAL ;
    PORT
      LAYER M4 ;
        RECT  64.716 42.336 64.8 42.36 ;
    END
  END kv_request[334]
  PIN kv_request[335]
    DIRECTION INPUT ;
    USE SIGNAL ;
    PORT
      LAYER M4 ;
        RECT  64.716 42.432 64.8 42.456 ;
    END
  END kv_request[335]
  PIN kv_request[336]
    DIRECTION INPUT ;
    USE SIGNAL ;
    PORT
      LAYER M4 ;
        RECT  64.716 42.576 64.8 42.6 ;
    END
  END kv_request[336]
  PIN kv_request[337]
    DIRECTION INPUT ;
    USE SIGNAL ;
    PORT
      LAYER M4 ;
        RECT  64.716 42.72 64.8 42.744 ;
    END
  END kv_request[337]
  PIN kv_request[338]
    DIRECTION INPUT ;
    USE SIGNAL ;
    PORT
      LAYER M4 ;
        RECT  64.716 42.816 64.8 42.84 ;
    END
  END kv_request[338]
  PIN kv_request[339]
    DIRECTION INPUT ;
    USE SIGNAL ;
    PORT
      LAYER M4 ;
        RECT  64.716 42.96 64.8 42.984 ;
    END
  END kv_request[339]
  PIN kv_request[33]
    DIRECTION INPUT ;
    USE SIGNAL ;
    PORT
      LAYER M4 ;
        RECT  64.716 4.224 64.8 4.248 ;
    END
  END kv_request[33]
  PIN kv_request[340]
    DIRECTION INPUT ;
    USE SIGNAL ;
    PORT
      LAYER M4 ;
        RECT  64.716 43.104 64.8 43.128 ;
    END
  END kv_request[340]
  PIN kv_request[341]
    DIRECTION INPUT ;
    USE SIGNAL ;
    PORT
      LAYER M4 ;
        RECT  64.716 43.2 64.8 43.224 ;
    END
  END kv_request[341]
  PIN kv_request[342]
    DIRECTION INPUT ;
    USE SIGNAL ;
    PORT
      LAYER M4 ;
        RECT  64.716 43.344 64.8 43.368 ;
    END
  END kv_request[342]
  PIN kv_request[343]
    DIRECTION INPUT ;
    USE SIGNAL ;
    PORT
      LAYER M4 ;
        RECT  64.716 43.44 64.8 43.464 ;
    END
  END kv_request[343]
  PIN kv_request[344]
    DIRECTION INPUT ;
    USE SIGNAL ;
    PORT
      LAYER M4 ;
        RECT  64.716 43.584 64.8 43.608 ;
    END
  END kv_request[344]
  PIN kv_request[345]
    DIRECTION INPUT ;
    USE SIGNAL ;
    PORT
      LAYER M4 ;
        RECT  64.716 43.728 64.8 43.752 ;
    END
  END kv_request[345]
  PIN kv_request[346]
    DIRECTION INPUT ;
    USE SIGNAL ;
    PORT
      LAYER M4 ;
        RECT  64.716 43.824 64.8 43.848 ;
    END
  END kv_request[346]
  PIN kv_request[347]
    DIRECTION INPUT ;
    USE SIGNAL ;
    PORT
      LAYER M4 ;
        RECT  64.716 43.968 64.8 43.992 ;
    END
  END kv_request[347]
  PIN kv_request[348]
    DIRECTION INPUT ;
    USE SIGNAL ;
    PORT
      LAYER M4 ;
        RECT  64.716 44.112 64.8 44.136 ;
    END
  END kv_request[348]
  PIN kv_request[349]
    DIRECTION INPUT ;
    USE SIGNAL ;
    PORT
      LAYER M4 ;
        RECT  64.716 44.208 64.8 44.232 ;
    END
  END kv_request[349]
  PIN kv_request[34]
    DIRECTION INPUT ;
    USE SIGNAL ;
    PORT
      LAYER M4 ;
        RECT  64.716 4.368 64.8 4.392 ;
    END
  END kv_request[34]
  PIN kv_request[350]
    DIRECTION INPUT ;
    USE SIGNAL ;
    PORT
      LAYER M4 ;
        RECT  64.716 44.352 64.8 44.376 ;
    END
  END kv_request[350]
  PIN kv_request[351]
    DIRECTION INPUT ;
    USE SIGNAL ;
    PORT
      LAYER M4 ;
        RECT  64.716 44.496 64.8 44.52 ;
    END
  END kv_request[351]
  PIN kv_request[352]
    DIRECTION INPUT ;
    USE SIGNAL ;
    PORT
      LAYER M4 ;
        RECT  64.716 44.592 64.8 44.616 ;
    END
  END kv_request[352]
  PIN kv_request[353]
    DIRECTION INPUT ;
    USE SIGNAL ;
    PORT
      LAYER M4 ;
        RECT  64.716 44.736 64.8 44.76 ;
    END
  END kv_request[353]
  PIN kv_request[354]
    DIRECTION INPUT ;
    USE SIGNAL ;
    PORT
      LAYER M4 ;
        RECT  64.716 44.832 64.8 44.856 ;
    END
  END kv_request[354]
  PIN kv_request[355]
    DIRECTION INPUT ;
    USE SIGNAL ;
    PORT
      LAYER M4 ;
        RECT  64.716 44.976 64.8 45 ;
    END
  END kv_request[355]
  PIN kv_request[356]
    DIRECTION INPUT ;
    USE SIGNAL ;
    PORT
      LAYER M4 ;
        RECT  64.716 45.12 64.8 45.144 ;
    END
  END kv_request[356]
  PIN kv_request[357]
    DIRECTION INPUT ;
    USE SIGNAL ;
    PORT
      LAYER M4 ;
        RECT  64.716 45.216 64.8 45.24 ;
    END
  END kv_request[357]
  PIN kv_request[358]
    DIRECTION INPUT ;
    USE SIGNAL ;
    PORT
      LAYER M4 ;
        RECT  64.716 45.36 64.8 45.384 ;
    END
  END kv_request[358]
  PIN kv_request[359]
    DIRECTION INPUT ;
    USE SIGNAL ;
    PORT
      LAYER M4 ;
        RECT  64.716 45.504 64.8 45.528 ;
    END
  END kv_request[359]
  PIN kv_request[35]
    DIRECTION INPUT ;
    USE SIGNAL ;
    PORT
      LAYER M4 ;
        RECT  64.716 4.464 64.8 4.488 ;
    END
  END kv_request[35]
  PIN kv_request[360]
    DIRECTION INPUT ;
    USE SIGNAL ;
    PORT
      LAYER M4 ;
        RECT  64.716 45.6 64.8 45.624 ;
    END
  END kv_request[360]
  PIN kv_request[361]
    DIRECTION INPUT ;
    USE SIGNAL ;
    PORT
      LAYER M4 ;
        RECT  64.716 45.744 64.8 45.768 ;
    END
  END kv_request[361]
  PIN kv_request[362]
    DIRECTION INPUT ;
    USE SIGNAL ;
    PORT
      LAYER M4 ;
        RECT  64.716 45.888 64.8 45.912 ;
    END
  END kv_request[362]
  PIN kv_request[363]
    DIRECTION INPUT ;
    USE SIGNAL ;
    PORT
      LAYER M4 ;
        RECT  64.716 45.984 64.8 46.008 ;
    END
  END kv_request[363]
  PIN kv_request[364]
    DIRECTION INPUT ;
    USE SIGNAL ;
    PORT
      LAYER M4 ;
        RECT  64.716 46.128 64.8 46.152 ;
    END
  END kv_request[364]
  PIN kv_request[365]
    DIRECTION INPUT ;
    USE SIGNAL ;
    PORT
      LAYER M4 ;
        RECT  64.716 46.224 64.8 46.248 ;
    END
  END kv_request[365]
  PIN kv_request[366]
    DIRECTION INPUT ;
    USE SIGNAL ;
    PORT
      LAYER M4 ;
        RECT  64.716 46.368 64.8 46.392 ;
    END
  END kv_request[366]
  PIN kv_request[367]
    DIRECTION INPUT ;
    USE SIGNAL ;
    PORT
      LAYER M4 ;
        RECT  64.716 46.512 64.8 46.536 ;
    END
  END kv_request[367]
  PIN kv_request[368]
    DIRECTION INPUT ;
    USE SIGNAL ;
    PORT
      LAYER M4 ;
        RECT  64.716 46.608 64.8 46.632 ;
    END
  END kv_request[368]
  PIN kv_request[369]
    DIRECTION INPUT ;
    USE SIGNAL ;
    PORT
      LAYER M4 ;
        RECT  64.716 46.752 64.8 46.776 ;
    END
  END kv_request[369]
  PIN kv_request[36]
    DIRECTION INPUT ;
    USE SIGNAL ;
    PORT
      LAYER M4 ;
        RECT  64.716 4.608 64.8 4.632 ;
    END
  END kv_request[36]
  PIN kv_request[370]
    DIRECTION INPUT ;
    USE SIGNAL ;
    PORT
      LAYER M4 ;
        RECT  64.716 46.896 64.8 46.92 ;
    END
  END kv_request[370]
  PIN kv_request[371]
    DIRECTION INPUT ;
    USE SIGNAL ;
    PORT
      LAYER M4 ;
        RECT  64.716 46.992 64.8 47.016 ;
    END
  END kv_request[371]
  PIN kv_request[372]
    DIRECTION INPUT ;
    USE SIGNAL ;
    PORT
      LAYER M4 ;
        RECT  64.716 47.136 64.8 47.16 ;
    END
  END kv_request[372]
  PIN kv_request[373]
    DIRECTION INPUT ;
    USE SIGNAL ;
    PORT
      LAYER M4 ;
        RECT  64.716 47.28 64.8 47.304 ;
    END
  END kv_request[373]
  PIN kv_request[374]
    DIRECTION INPUT ;
    USE SIGNAL ;
    PORT
      LAYER M4 ;
        RECT  64.716 47.376 64.8 47.4 ;
    END
  END kv_request[374]
  PIN kv_request[375]
    DIRECTION INPUT ;
    USE SIGNAL ;
    PORT
      LAYER M4 ;
        RECT  64.716 47.52 64.8 47.544 ;
    END
  END kv_request[375]
  PIN kv_request[376]
    DIRECTION INPUT ;
    USE SIGNAL ;
    PORT
      LAYER M4 ;
        RECT  64.716 47.616 64.8 47.64 ;
    END
  END kv_request[376]
  PIN kv_request[377]
    DIRECTION INPUT ;
    USE SIGNAL ;
    PORT
      LAYER M4 ;
        RECT  64.716 47.76 64.8 47.784 ;
    END
  END kv_request[377]
  PIN kv_request[378]
    DIRECTION INPUT ;
    USE SIGNAL ;
    PORT
      LAYER M4 ;
        RECT  64.716 47.904 64.8 47.928 ;
    END
  END kv_request[378]
  PIN kv_request[379]
    DIRECTION INPUT ;
    USE SIGNAL ;
    PORT
      LAYER M4 ;
        RECT  64.716 48 64.8 48.024 ;
    END
  END kv_request[379]
  PIN kv_request[37]
    DIRECTION INPUT ;
    USE SIGNAL ;
    PORT
      LAYER M4 ;
        RECT  64.716 4.752 64.8 4.776 ;
    END
  END kv_request[37]
  PIN kv_request[380]
    DIRECTION INPUT ;
    USE SIGNAL ;
    PORT
      LAYER M4 ;
        RECT  64.716 48.144 64.8 48.168 ;
    END
  END kv_request[380]
  PIN kv_request[381]
    DIRECTION INPUT ;
    USE SIGNAL ;
    PORT
      LAYER M4 ;
        RECT  64.716 48.288 64.8 48.312 ;
    END
  END kv_request[381]
  PIN kv_request[382]
    DIRECTION INPUT ;
    USE SIGNAL ;
    PORT
      LAYER M4 ;
        RECT  64.716 48.384 64.8 48.408 ;
    END
  END kv_request[382]
  PIN kv_request[383]
    DIRECTION INPUT ;
    USE SIGNAL ;
    PORT
      LAYER M4 ;
        RECT  64.716 48.528 64.8 48.552 ;
    END
  END kv_request[383]
  PIN kv_request[384]
    DIRECTION INPUT ;
    USE SIGNAL ;
    PORT
      LAYER M4 ;
        RECT  64.716 48.672 64.8 48.696 ;
    END
  END kv_request[384]
  PIN kv_request[385]
    DIRECTION INPUT ;
    USE SIGNAL ;
    PORT
      LAYER M4 ;
        RECT  64.716 48.768 64.8 48.792 ;
    END
  END kv_request[385]
  PIN kv_request[386]
    DIRECTION INPUT ;
    USE SIGNAL ;
    PORT
      LAYER M4 ;
        RECT  64.716 48.912 64.8 48.936 ;
    END
  END kv_request[386]
  PIN kv_request[387]
    DIRECTION INPUT ;
    USE SIGNAL ;
    PORT
      LAYER M4 ;
        RECT  64.716 49.008 64.8 49.032 ;
    END
  END kv_request[387]
  PIN kv_request[388]
    DIRECTION INPUT ;
    USE SIGNAL ;
    PORT
      LAYER M4 ;
        RECT  64.716 49.152 64.8 49.176 ;
    END
  END kv_request[388]
  PIN kv_request[389]
    DIRECTION INPUT ;
    USE SIGNAL ;
    PORT
      LAYER M4 ;
        RECT  64.716 49.296 64.8 49.32 ;
    END
  END kv_request[389]
  PIN kv_request[38]
    DIRECTION INPUT ;
    USE SIGNAL ;
    PORT
      LAYER M4 ;
        RECT  64.716 4.848 64.8 4.872 ;
    END
  END kv_request[38]
  PIN kv_request[390]
    DIRECTION INPUT ;
    USE SIGNAL ;
    PORT
      LAYER M4 ;
        RECT  64.716 49.392 64.8 49.416 ;
    END
  END kv_request[390]
  PIN kv_request[391]
    DIRECTION INPUT ;
    USE SIGNAL ;
    PORT
      LAYER M4 ;
        RECT  64.716 49.536 64.8 49.56 ;
    END
  END kv_request[391]
  PIN kv_request[392]
    DIRECTION INPUT ;
    USE SIGNAL ;
    PORT
      LAYER M4 ;
        RECT  64.716 49.68 64.8 49.704 ;
    END
  END kv_request[392]
  PIN kv_request[393]
    DIRECTION INPUT ;
    USE SIGNAL ;
    PORT
      LAYER M4 ;
        RECT  64.716 49.776 64.8 49.8 ;
    END
  END kv_request[393]
  PIN kv_request[394]
    DIRECTION INPUT ;
    USE SIGNAL ;
    PORT
      LAYER M4 ;
        RECT  64.716 49.92 64.8 49.944 ;
    END
  END kv_request[394]
  PIN kv_request[395]
    DIRECTION INPUT ;
    USE SIGNAL ;
    PORT
      LAYER M4 ;
        RECT  64.716 50.064 64.8 50.088 ;
    END
  END kv_request[395]
  PIN kv_request[396]
    DIRECTION INPUT ;
    USE SIGNAL ;
    PORT
      LAYER M4 ;
        RECT  64.716 50.16 64.8 50.184 ;
    END
  END kv_request[396]
  PIN kv_request[397]
    DIRECTION INPUT ;
    USE SIGNAL ;
    PORT
      LAYER M4 ;
        RECT  64.716 50.304 64.8 50.328 ;
    END
  END kv_request[397]
  PIN kv_request[398]
    DIRECTION INPUT ;
    USE SIGNAL ;
    PORT
      LAYER M4 ;
        RECT  64.716 50.4 64.8 50.424 ;
    END
  END kv_request[398]
  PIN kv_request[399]
    DIRECTION INPUT ;
    USE SIGNAL ;
    PORT
      LAYER M4 ;
        RECT  64.716 50.544 64.8 50.568 ;
    END
  END kv_request[399]
  PIN kv_request[39]
    DIRECTION INPUT ;
    USE SIGNAL ;
    PORT
      LAYER M4 ;
        RECT  64.716 4.992 64.8 5.016 ;
    END
  END kv_request[39]
  PIN kv_request[3]
    DIRECTION INPUT ;
    USE SIGNAL ;
    PORT
      LAYER M4 ;
        RECT  64.716 0.432 64.8 0.456 ;
    END
  END kv_request[3]
  PIN kv_request[400]
    DIRECTION INPUT ;
    USE SIGNAL ;
    PORT
      LAYER M4 ;
        RECT  64.716 50.688 64.8 50.712 ;
    END
  END kv_request[400]
  PIN kv_request[401]
    DIRECTION INPUT ;
    USE SIGNAL ;
    PORT
      LAYER M4 ;
        RECT  64.716 50.784 64.8 50.808 ;
    END
  END kv_request[401]
  PIN kv_request[402]
    DIRECTION INPUT ;
    USE SIGNAL ;
    PORT
      LAYER M4 ;
        RECT  64.716 50.928 64.8 50.952 ;
    END
  END kv_request[402]
  PIN kv_request[403]
    DIRECTION INPUT ;
    USE SIGNAL ;
    PORT
      LAYER M4 ;
        RECT  64.716 51.072 64.8 51.096 ;
    END
  END kv_request[403]
  PIN kv_request[404]
    DIRECTION INPUT ;
    USE SIGNAL ;
    PORT
      LAYER M4 ;
        RECT  64.716 51.168 64.8 51.192 ;
    END
  END kv_request[404]
  PIN kv_request[405]
    DIRECTION INPUT ;
    USE SIGNAL ;
    PORT
      LAYER M4 ;
        RECT  64.716 51.312 64.8 51.336 ;
    END
  END kv_request[405]
  PIN kv_request[406]
    DIRECTION INPUT ;
    USE SIGNAL ;
    PORT
      LAYER M4 ;
        RECT  64.716 51.456 64.8 51.48 ;
    END
  END kv_request[406]
  PIN kv_request[407]
    DIRECTION INPUT ;
    USE SIGNAL ;
    PORT
      LAYER M4 ;
        RECT  64.716 51.552 64.8 51.576 ;
    END
  END kv_request[407]
  PIN kv_request[408]
    DIRECTION INPUT ;
    USE SIGNAL ;
    PORT
      LAYER M4 ;
        RECT  64.716 51.696 64.8 51.72 ;
    END
  END kv_request[408]
  PIN kv_request[409]
    DIRECTION INPUT ;
    USE SIGNAL ;
    PORT
      LAYER M4 ;
        RECT  64.716 51.792 64.8 51.816 ;
    END
  END kv_request[409]
  PIN kv_request[40]
    DIRECTION INPUT ;
    USE SIGNAL ;
    PORT
      LAYER M4 ;
        RECT  64.716 5.136 64.8 5.16 ;
    END
  END kv_request[40]
  PIN kv_request[410]
    DIRECTION INPUT ;
    USE SIGNAL ;
    PORT
      LAYER M4 ;
        RECT  64.716 51.936 64.8 51.96 ;
    END
  END kv_request[410]
  PIN kv_request[411]
    DIRECTION INPUT ;
    USE SIGNAL ;
    PORT
      LAYER M4 ;
        RECT  64.716 52.08 64.8 52.104 ;
    END
  END kv_request[411]
  PIN kv_request[412]
    DIRECTION INPUT ;
    USE SIGNAL ;
    PORT
      LAYER M4 ;
        RECT  64.716 52.176 64.8 52.2 ;
    END
  END kv_request[412]
  PIN kv_request[413]
    DIRECTION INPUT ;
    USE SIGNAL ;
    PORT
      LAYER M4 ;
        RECT  64.716 52.32 64.8 52.344 ;
    END
  END kv_request[413]
  PIN kv_request[414]
    DIRECTION INPUT ;
    USE SIGNAL ;
    PORT
      LAYER M4 ;
        RECT  64.716 52.464 64.8 52.488 ;
    END
  END kv_request[414]
  PIN kv_request[415]
    DIRECTION INPUT ;
    USE SIGNAL ;
    PORT
      LAYER M4 ;
        RECT  64.716 52.56 64.8 52.584 ;
    END
  END kv_request[415]
  PIN kv_request[416]
    DIRECTION INPUT ;
    USE SIGNAL ;
    PORT
      LAYER M4 ;
        RECT  64.716 52.704 64.8 52.728 ;
    END
  END kv_request[416]
  PIN kv_request[417]
    DIRECTION INPUT ;
    USE SIGNAL ;
    PORT
      LAYER M4 ;
        RECT  64.716 52.848 64.8 52.872 ;
    END
  END kv_request[417]
  PIN kv_request[418]
    DIRECTION INPUT ;
    USE SIGNAL ;
    PORT
      LAYER M4 ;
        RECT  64.716 52.944 64.8 52.968 ;
    END
  END kv_request[418]
  PIN kv_request[419]
    DIRECTION INPUT ;
    USE SIGNAL ;
    PORT
      LAYER M4 ;
        RECT  64.716 53.088 64.8 53.112 ;
    END
  END kv_request[419]
  PIN kv_request[41]
    DIRECTION INPUT ;
    USE SIGNAL ;
    PORT
      LAYER M4 ;
        RECT  64.716 5.232 64.8 5.256 ;
    END
  END kv_request[41]
  PIN kv_request[420]
    DIRECTION INPUT ;
    USE SIGNAL ;
    PORT
      LAYER M4 ;
        RECT  64.716 53.232 64.8 53.256 ;
    END
  END kv_request[420]
  PIN kv_request[421]
    DIRECTION INPUT ;
    USE SIGNAL ;
    PORT
      LAYER M4 ;
        RECT  64.716 53.328 64.8 53.352 ;
    END
  END kv_request[421]
  PIN kv_request[422]
    DIRECTION INPUT ;
    USE SIGNAL ;
    PORT
      LAYER M4 ;
        RECT  64.716 53.472 64.8 53.496 ;
    END
  END kv_request[422]
  PIN kv_request[423]
    DIRECTION INPUT ;
    USE SIGNAL ;
    PORT
      LAYER M4 ;
        RECT  64.716 53.568 64.8 53.592 ;
    END
  END kv_request[423]
  PIN kv_request[424]
    DIRECTION INPUT ;
    USE SIGNAL ;
    PORT
      LAYER M4 ;
        RECT  64.716 53.712 64.8 53.736 ;
    END
  END kv_request[424]
  PIN kv_request[425]
    DIRECTION INPUT ;
    USE SIGNAL ;
    PORT
      LAYER M4 ;
        RECT  64.716 53.856 64.8 53.88 ;
    END
  END kv_request[425]
  PIN kv_request[426]
    DIRECTION INPUT ;
    USE SIGNAL ;
    PORT
      LAYER M4 ;
        RECT  64.716 53.952 64.8 53.976 ;
    END
  END kv_request[426]
  PIN kv_request[427]
    DIRECTION INPUT ;
    USE SIGNAL ;
    PORT
      LAYER M4 ;
        RECT  64.716 54.096 64.8 54.12 ;
    END
  END kv_request[427]
  PIN kv_request[428]
    DIRECTION INPUT ;
    USE SIGNAL ;
    PORT
      LAYER M4 ;
        RECT  64.716 54.24 64.8 54.264 ;
    END
  END kv_request[428]
  PIN kv_request[429]
    DIRECTION INPUT ;
    USE SIGNAL ;
    PORT
      LAYER M4 ;
        RECT  64.716 54.336 64.8 54.36 ;
    END
  END kv_request[429]
  PIN kv_request[42]
    DIRECTION INPUT ;
    USE SIGNAL ;
    PORT
      LAYER M4 ;
        RECT  64.716 5.376 64.8 5.4 ;
    END
  END kv_request[42]
  PIN kv_request[430]
    DIRECTION INPUT ;
    USE SIGNAL ;
    PORT
      LAYER M4 ;
        RECT  64.716 54.48 64.8 54.504 ;
    END
  END kv_request[430]
  PIN kv_request[431]
    DIRECTION INPUT ;
    USE SIGNAL ;
    PORT
      LAYER M4 ;
        RECT  64.716 54.624 64.8 54.648 ;
    END
  END kv_request[431]
  PIN kv_request[432]
    DIRECTION INPUT ;
    USE SIGNAL ;
    PORT
      LAYER M4 ;
        RECT  64.716 54.72 64.8 54.744 ;
    END
  END kv_request[432]
  PIN kv_request[433]
    DIRECTION INPUT ;
    USE SIGNAL ;
    PORT
      LAYER M4 ;
        RECT  64.716 54.864 64.8 54.888 ;
    END
  END kv_request[433]
  PIN kv_request[434]
    DIRECTION INPUT ;
    USE SIGNAL ;
    PORT
      LAYER M4 ;
        RECT  64.716 54.96 64.8 54.984 ;
    END
  END kv_request[434]
  PIN kv_request[435]
    DIRECTION INPUT ;
    USE SIGNAL ;
    PORT
      LAYER M4 ;
        RECT  64.716 55.104 64.8 55.128 ;
    END
  END kv_request[435]
  PIN kv_request[436]
    DIRECTION INPUT ;
    USE SIGNAL ;
    PORT
      LAYER M4 ;
        RECT  64.716 55.248 64.8 55.272 ;
    END
  END kv_request[436]
  PIN kv_request[437]
    DIRECTION INPUT ;
    USE SIGNAL ;
    PORT
      LAYER M4 ;
        RECT  64.716 55.344 64.8 55.368 ;
    END
  END kv_request[437]
  PIN kv_request[438]
    DIRECTION INPUT ;
    USE SIGNAL ;
    PORT
      LAYER M4 ;
        RECT  64.716 55.488 64.8 55.512 ;
    END
  END kv_request[438]
  PIN kv_request[439]
    DIRECTION INPUT ;
    USE SIGNAL ;
    PORT
      LAYER M4 ;
        RECT  64.716 55.632 64.8 55.656 ;
    END
  END kv_request[439]
  PIN kv_request[43]
    DIRECTION INPUT ;
    USE SIGNAL ;
    PORT
      LAYER M4 ;
        RECT  64.716 5.472 64.8 5.496 ;
    END
  END kv_request[43]
  PIN kv_request[440]
    DIRECTION INPUT ;
    USE SIGNAL ;
    PORT
      LAYER M4 ;
        RECT  64.716 55.728 64.8 55.752 ;
    END
  END kv_request[440]
  PIN kv_request[441]
    DIRECTION INPUT ;
    USE SIGNAL ;
    PORT
      LAYER M4 ;
        RECT  64.716 55.872 64.8 55.896 ;
    END
  END kv_request[441]
  PIN kv_request[442]
    DIRECTION INPUT ;
    USE SIGNAL ;
    PORT
      LAYER M4 ;
        RECT  64.716 56.016 64.8 56.04 ;
    END
  END kv_request[442]
  PIN kv_request[443]
    DIRECTION INPUT ;
    USE SIGNAL ;
    PORT
      LAYER M4 ;
        RECT  64.716 56.112 64.8 56.136 ;
    END
  END kv_request[443]
  PIN kv_request[444]
    DIRECTION INPUT ;
    USE SIGNAL ;
    PORT
      LAYER M4 ;
        RECT  64.716 56.256 64.8 56.28 ;
    END
  END kv_request[444]
  PIN kv_request[445]
    DIRECTION INPUT ;
    USE SIGNAL ;
    PORT
      LAYER M4 ;
        RECT  64.716 56.352 64.8 56.376 ;
    END
  END kv_request[445]
  PIN kv_request[446]
    DIRECTION INPUT ;
    USE SIGNAL ;
    PORT
      LAYER M4 ;
        RECT  64.716 56.496 64.8 56.52 ;
    END
  END kv_request[446]
  PIN kv_request[447]
    DIRECTION INPUT ;
    USE SIGNAL ;
    PORT
      LAYER M4 ;
        RECT  64.716 56.64 64.8 56.664 ;
    END
  END kv_request[447]
  PIN kv_request[448]
    DIRECTION INPUT ;
    USE SIGNAL ;
    PORT
      LAYER M4 ;
        RECT  64.716 56.736 64.8 56.76 ;
    END
  END kv_request[448]
  PIN kv_request[449]
    DIRECTION INPUT ;
    USE SIGNAL ;
    PORT
      LAYER M4 ;
        RECT  64.716 56.88 64.8 56.904 ;
    END
  END kv_request[449]
  PIN kv_request[44]
    DIRECTION INPUT ;
    USE SIGNAL ;
    PORT
      LAYER M4 ;
        RECT  64.716 5.616 64.8 5.64 ;
    END
  END kv_request[44]
  PIN kv_request[450]
    DIRECTION INPUT ;
    USE SIGNAL ;
    PORT
      LAYER M4 ;
        RECT  64.716 57.024 64.8 57.048 ;
    END
  END kv_request[450]
  PIN kv_request[451]
    DIRECTION INPUT ;
    USE SIGNAL ;
    PORT
      LAYER M4 ;
        RECT  64.716 57.12 64.8 57.144 ;
    END
  END kv_request[451]
  PIN kv_request[452]
    DIRECTION INPUT ;
    USE SIGNAL ;
    PORT
      LAYER M4 ;
        RECT  64.716 57.264 64.8 57.288 ;
    END
  END kv_request[452]
  PIN kv_request[453]
    DIRECTION INPUT ;
    USE SIGNAL ;
    PORT
      LAYER M4 ;
        RECT  64.716 57.408 64.8 57.432 ;
    END
  END kv_request[453]
  PIN kv_request[454]
    DIRECTION INPUT ;
    USE SIGNAL ;
    PORT
      LAYER M4 ;
        RECT  64.716 57.504 64.8 57.528 ;
    END
  END kv_request[454]
  PIN kv_request[455]
    DIRECTION INPUT ;
    USE SIGNAL ;
    PORT
      LAYER M4 ;
        RECT  64.716 57.648 64.8 57.672 ;
    END
  END kv_request[455]
  PIN kv_request[456]
    DIRECTION INPUT ;
    USE SIGNAL ;
    PORT
      LAYER M4 ;
        RECT  64.716 57.744 64.8 57.768 ;
    END
  END kv_request[456]
  PIN kv_request[457]
    DIRECTION INPUT ;
    USE SIGNAL ;
    PORT
      LAYER M4 ;
        RECT  64.716 57.888 64.8 57.912 ;
    END
  END kv_request[457]
  PIN kv_request[458]
    DIRECTION INPUT ;
    USE SIGNAL ;
    PORT
      LAYER M4 ;
        RECT  64.716 58.032 64.8 58.056 ;
    END
  END kv_request[458]
  PIN kv_request[459]
    DIRECTION INPUT ;
    USE SIGNAL ;
    PORT
      LAYER M4 ;
        RECT  64.716 58.128 64.8 58.152 ;
    END
  END kv_request[459]
  PIN kv_request[45]
    DIRECTION INPUT ;
    USE SIGNAL ;
    PORT
      LAYER M4 ;
        RECT  64.716 5.76 64.8 5.784 ;
    END
  END kv_request[45]
  PIN kv_request[460]
    DIRECTION INPUT ;
    USE SIGNAL ;
    PORT
      LAYER M4 ;
        RECT  64.716 58.272 64.8 58.296 ;
    END
  END kv_request[460]
  PIN kv_request[461]
    DIRECTION INPUT ;
    USE SIGNAL ;
    PORT
      LAYER M4 ;
        RECT  64.716 58.416 64.8 58.44 ;
    END
  END kv_request[461]
  PIN kv_request[462]
    DIRECTION INPUT ;
    USE SIGNAL ;
    PORT
      LAYER M4 ;
        RECT  64.716 58.512 64.8 58.536 ;
    END
  END kv_request[462]
  PIN kv_request[463]
    DIRECTION INPUT ;
    USE SIGNAL ;
    PORT
      LAYER M4 ;
        RECT  64.716 58.656 64.8 58.68 ;
    END
  END kv_request[463]
  PIN kv_request[464]
    DIRECTION INPUT ;
    USE SIGNAL ;
    PORT
      LAYER M4 ;
        RECT  64.716 58.8 64.8 58.824 ;
    END
  END kv_request[464]
  PIN kv_request[465]
    DIRECTION INPUT ;
    USE SIGNAL ;
    PORT
      LAYER M4 ;
        RECT  64.716 58.896 64.8 58.92 ;
    END
  END kv_request[465]
  PIN kv_request[466]
    DIRECTION INPUT ;
    USE SIGNAL ;
    PORT
      LAYER M4 ;
        RECT  64.716 59.04 64.8 59.064 ;
    END
  END kv_request[466]
  PIN kv_request[467]
    DIRECTION INPUT ;
    USE SIGNAL ;
    PORT
      LAYER M4 ;
        RECT  64.716 59.136 64.8 59.16 ;
    END
  END kv_request[467]
  PIN kv_request[468]
    DIRECTION INPUT ;
    USE SIGNAL ;
    PORT
      LAYER M4 ;
        RECT  64.716 59.28 64.8 59.304 ;
    END
  END kv_request[468]
  PIN kv_request[469]
    DIRECTION INPUT ;
    USE SIGNAL ;
    PORT
      LAYER M4 ;
        RECT  64.716 59.424 64.8 59.448 ;
    END
  END kv_request[469]
  PIN kv_request[46]
    DIRECTION INPUT ;
    USE SIGNAL ;
    PORT
      LAYER M4 ;
        RECT  64.716 5.856 64.8 5.88 ;
    END
  END kv_request[46]
  PIN kv_request[470]
    DIRECTION INPUT ;
    USE SIGNAL ;
    PORT
      LAYER M4 ;
        RECT  64.716 59.52 64.8 59.544 ;
    END
  END kv_request[470]
  PIN kv_request[471]
    DIRECTION INPUT ;
    USE SIGNAL ;
    PORT
      LAYER M4 ;
        RECT  64.716 59.664 64.8 59.688 ;
    END
  END kv_request[471]
  PIN kv_request[472]
    DIRECTION INPUT ;
    USE SIGNAL ;
    PORT
      LAYER M4 ;
        RECT  64.716 59.808 64.8 59.832 ;
    END
  END kv_request[472]
  PIN kv_request[473]
    DIRECTION INPUT ;
    USE SIGNAL ;
    PORT
      LAYER M4 ;
        RECT  64.716 59.904 64.8 59.928 ;
    END
  END kv_request[473]
  PIN kv_request[474]
    DIRECTION INPUT ;
    USE SIGNAL ;
    PORT
      LAYER M4 ;
        RECT  64.716 60.048 64.8 60.072 ;
    END
  END kv_request[474]
  PIN kv_request[475]
    DIRECTION INPUT ;
    USE SIGNAL ;
    PORT
      LAYER M4 ;
        RECT  64.716 60.192 64.8 60.216 ;
    END
  END kv_request[475]
  PIN kv_request[476]
    DIRECTION INPUT ;
    USE SIGNAL ;
    PORT
      LAYER M4 ;
        RECT  64.716 60.288 64.8 60.312 ;
    END
  END kv_request[476]
  PIN kv_request[477]
    DIRECTION INPUT ;
    USE SIGNAL ;
    PORT
      LAYER M4 ;
        RECT  64.716 60.432 64.8 60.456 ;
    END
  END kv_request[477]
  PIN kv_request[478]
    DIRECTION INPUT ;
    USE SIGNAL ;
    PORT
      LAYER M4 ;
        RECT  64.716 60.528 64.8 60.552 ;
    END
  END kv_request[478]
  PIN kv_request[479]
    DIRECTION INPUT ;
    USE SIGNAL ;
    PORT
      LAYER M4 ;
        RECT  64.716 60.672 64.8 60.696 ;
    END
  END kv_request[479]
  PIN kv_request[47]
    DIRECTION INPUT ;
    USE SIGNAL ;
    PORT
      LAYER M4 ;
        RECT  64.716 6 64.8 6.024 ;
    END
  END kv_request[47]
  PIN kv_request[480]
    DIRECTION INPUT ;
    USE SIGNAL ;
    PORT
      LAYER M4 ;
        RECT  64.716 60.816 64.8 60.84 ;
    END
  END kv_request[480]
  PIN kv_request[481]
    DIRECTION INPUT ;
    USE SIGNAL ;
    PORT
      LAYER M4 ;
        RECT  64.716 60.912 64.8 60.936 ;
    END
  END kv_request[481]
  PIN kv_request[482]
    DIRECTION INPUT ;
    USE SIGNAL ;
    PORT
      LAYER M4 ;
        RECT  64.716 61.056 64.8 61.08 ;
    END
  END kv_request[482]
  PIN kv_request[483]
    DIRECTION INPUT ;
    USE SIGNAL ;
    PORT
      LAYER M4 ;
        RECT  64.716 61.2 64.8 61.224 ;
    END
  END kv_request[483]
  PIN kv_request[484]
    DIRECTION INPUT ;
    USE SIGNAL ;
    PORT
      LAYER M4 ;
        RECT  64.716 61.296 64.8 61.32 ;
    END
  END kv_request[484]
  PIN kv_request[485]
    DIRECTION INPUT ;
    USE SIGNAL ;
    PORT
      LAYER M4 ;
        RECT  64.716 61.44 64.8 61.464 ;
    END
  END kv_request[485]
  PIN kv_request[486]
    DIRECTION INPUT ;
    USE SIGNAL ;
    PORT
      LAYER M4 ;
        RECT  64.716 61.584 64.8 61.608 ;
    END
  END kv_request[486]
  PIN kv_request[487]
    DIRECTION INPUT ;
    USE SIGNAL ;
    PORT
      LAYER M4 ;
        RECT  64.716 61.68 64.8 61.704 ;
    END
  END kv_request[487]
  PIN kv_request[488]
    DIRECTION INPUT ;
    USE SIGNAL ;
    PORT
      LAYER M4 ;
        RECT  64.716 61.824 64.8 61.848 ;
    END
  END kv_request[488]
  PIN kv_request[489]
    DIRECTION INPUT ;
    USE SIGNAL ;
    PORT
      LAYER M4 ;
        RECT  64.716 61.92 64.8 61.944 ;
    END
  END kv_request[489]
  PIN kv_request[48]
    DIRECTION INPUT ;
    USE SIGNAL ;
    PORT
      LAYER M4 ;
        RECT  64.716 6.144 64.8 6.168 ;
    END
  END kv_request[48]
  PIN kv_request[490]
    DIRECTION INPUT ;
    USE SIGNAL ;
    PORT
      LAYER M4 ;
        RECT  64.716 62.064 64.8 62.088 ;
    END
  END kv_request[490]
  PIN kv_request[491]
    DIRECTION INPUT ;
    USE SIGNAL ;
    PORT
      LAYER M4 ;
        RECT  64.716 62.208 64.8 62.232 ;
    END
  END kv_request[491]
  PIN kv_request[492]
    DIRECTION INPUT ;
    USE SIGNAL ;
    PORT
      LAYER M4 ;
        RECT  64.716 62.304 64.8 62.328 ;
    END
  END kv_request[492]
  PIN kv_request[493]
    DIRECTION INPUT ;
    USE SIGNAL ;
    PORT
      LAYER M4 ;
        RECT  64.716 62.448 64.8 62.472 ;
    END
  END kv_request[493]
  PIN kv_request[494]
    DIRECTION INPUT ;
    USE SIGNAL ;
    PORT
      LAYER M4 ;
        RECT  64.716 62.592 64.8 62.616 ;
    END
  END kv_request[494]
  PIN kv_request[495]
    DIRECTION INPUT ;
    USE SIGNAL ;
    PORT
      LAYER M4 ;
        RECT  64.716 62.688 64.8 62.712 ;
    END
  END kv_request[495]
  PIN kv_request[496]
    DIRECTION INPUT ;
    USE SIGNAL ;
    PORT
      LAYER M4 ;
        RECT  64.716 62.832 64.8 62.856 ;
    END
  END kv_request[496]
  PIN kv_request[497]
    DIRECTION INPUT ;
    USE SIGNAL ;
    PORT
      LAYER M4 ;
        RECT  64.716 62.976 64.8 63 ;
    END
  END kv_request[497]
  PIN kv_request[498]
    DIRECTION INPUT ;
    USE SIGNAL ;
    PORT
      LAYER M4 ;
        RECT  64.716 63.072 64.8 63.096 ;
    END
  END kv_request[498]
  PIN kv_request[499]
    DIRECTION INPUT ;
    USE SIGNAL ;
    PORT
      LAYER M4 ;
        RECT  64.716 63.216 64.8 63.24 ;
    END
  END kv_request[499]
  PIN kv_request[49]
    DIRECTION INPUT ;
    USE SIGNAL ;
    PORT
      LAYER M4 ;
        RECT  64.716 6.24 64.8 6.264 ;
    END
  END kv_request[49]
  PIN kv_request[4]
    DIRECTION INPUT ;
    USE SIGNAL ;
    PORT
      LAYER M4 ;
        RECT  64.716 0.576 64.8 0.6 ;
    END
  END kv_request[4]
  PIN kv_request[500]
    DIRECTION INPUT ;
    USE SIGNAL ;
    PORT
      LAYER M4 ;
        RECT  64.716 63.312 64.8 63.336 ;
    END
  END kv_request[500]
  PIN kv_request[501]
    DIRECTION INPUT ;
    USE SIGNAL ;
    PORT
      LAYER M4 ;
        RECT  64.716 63.456 64.8 63.48 ;
    END
  END kv_request[501]
  PIN kv_request[502]
    DIRECTION INPUT ;
    USE SIGNAL ;
    PORT
      LAYER M4 ;
        RECT  64.716 63.6 64.8 63.624 ;
    END
  END kv_request[502]
  PIN kv_request[503]
    DIRECTION INPUT ;
    USE SIGNAL ;
    PORT
      LAYER M4 ;
        RECT  64.716 63.696 64.8 63.72 ;
    END
  END kv_request[503]
  PIN kv_request[504]
    DIRECTION INPUT ;
    USE SIGNAL ;
    PORT
      LAYER M4 ;
        RECT  64.716 63.84 64.8 63.864 ;
    END
  END kv_request[504]
  PIN kv_request[505]
    DIRECTION INPUT ;
    USE SIGNAL ;
    PORT
      LAYER M4 ;
        RECT  64.716 63.984 64.8 64.008 ;
    END
  END kv_request[505]
  PIN kv_request[506]
    DIRECTION INPUT ;
    USE SIGNAL ;
    PORT
      LAYER M4 ;
        RECT  64.716 64.08 64.8 64.104 ;
    END
  END kv_request[506]
  PIN kv_request[507]
    DIRECTION INPUT ;
    USE SIGNAL ;
    PORT
      LAYER M4 ;
        RECT  64.716 64.224 64.8 64.248 ;
    END
  END kv_request[507]
  PIN kv_request[508]
    DIRECTION INPUT ;
    USE SIGNAL ;
    PORT
      LAYER M4 ;
        RECT  64.716 64.368 64.8 64.392 ;
    END
  END kv_request[508]
  PIN kv_request[509]
    DIRECTION INPUT ;
    USE SIGNAL ;
    PORT
      LAYER M4 ;
        RECT  64.716 64.464 64.8 64.488 ;
    END
  END kv_request[509]
  PIN kv_request[50]
    DIRECTION INPUT ;
    USE SIGNAL ;
    PORT
      LAYER M4 ;
        RECT  64.716 6.384 64.8 6.408 ;
    END
  END kv_request[50]
  PIN kv_request[510]
    DIRECTION INPUT ;
    USE SIGNAL ;
    PORT
      LAYER M4 ;
        RECT  64.716 64.608 64.8 64.632 ;
    END
  END kv_request[510]
  PIN kv_request[511]
    DIRECTION INPUT ;
    USE SIGNAL ;
    PORT
      LAYER M4 ;
        RECT  64.716 64.704 64.8 64.728 ;
    END
  END kv_request[511]
  PIN kv_request[51]
    DIRECTION INPUT ;
    USE SIGNAL ;
    PORT
      LAYER M4 ;
        RECT  64.716 6.528 64.8 6.552 ;
    END
  END kv_request[51]
  PIN kv_request[52]
    DIRECTION INPUT ;
    USE SIGNAL ;
    PORT
      LAYER M4 ;
        RECT  64.716 6.624 64.8 6.648 ;
    END
  END kv_request[52]
  PIN kv_request[53]
    DIRECTION INPUT ;
    USE SIGNAL ;
    PORT
      LAYER M4 ;
        RECT  64.716 6.768 64.8 6.792 ;
    END
  END kv_request[53]
  PIN kv_request[54]
    DIRECTION INPUT ;
    USE SIGNAL ;
    PORT
      LAYER M4 ;
        RECT  64.716 6.864 64.8 6.888 ;
    END
  END kv_request[54]
  PIN kv_request[55]
    DIRECTION INPUT ;
    USE SIGNAL ;
    PORT
      LAYER M4 ;
        RECT  64.716 7.008 64.8 7.032 ;
    END
  END kv_request[55]
  PIN kv_request[56]
    DIRECTION INPUT ;
    USE SIGNAL ;
    PORT
      LAYER M4 ;
        RECT  64.716 7.152 64.8 7.176 ;
    END
  END kv_request[56]
  PIN kv_request[57]
    DIRECTION INPUT ;
    USE SIGNAL ;
    PORT
      LAYER M4 ;
        RECT  64.716 7.248 64.8 7.272 ;
    END
  END kv_request[57]
  PIN kv_request[58]
    DIRECTION INPUT ;
    USE SIGNAL ;
    PORT
      LAYER M4 ;
        RECT  64.716 7.392 64.8 7.416 ;
    END
  END kv_request[58]
  PIN kv_request[59]
    DIRECTION INPUT ;
    USE SIGNAL ;
    PORT
      LAYER M4 ;
        RECT  64.716 7.536 64.8 7.56 ;
    END
  END kv_request[59]
  PIN kv_request[5]
    DIRECTION INPUT ;
    USE SIGNAL ;
    PORT
      LAYER M4 ;
        RECT  64.716 0.672 64.8 0.696 ;
    END
  END kv_request[5]
  PIN kv_request[60]
    DIRECTION INPUT ;
    USE SIGNAL ;
    PORT
      LAYER M4 ;
        RECT  64.716 7.632 64.8 7.656 ;
    END
  END kv_request[60]
  PIN kv_request[61]
    DIRECTION INPUT ;
    USE SIGNAL ;
    PORT
      LAYER M4 ;
        RECT  64.716 7.776 64.8 7.8 ;
    END
  END kv_request[61]
  PIN kv_request[62]
    DIRECTION INPUT ;
    USE SIGNAL ;
    PORT
      LAYER M4 ;
        RECT  64.716 7.92 64.8 7.944 ;
    END
  END kv_request[62]
  PIN kv_request[63]
    DIRECTION INPUT ;
    USE SIGNAL ;
    PORT
      LAYER M4 ;
        RECT  64.716 8.016 64.8 8.04 ;
    END
  END kv_request[63]
  PIN kv_request[64]
    DIRECTION INPUT ;
    USE SIGNAL ;
    PORT
      LAYER M4 ;
        RECT  64.716 8.16 64.8 8.184 ;
    END
  END kv_request[64]
  PIN kv_request[65]
    DIRECTION INPUT ;
    USE SIGNAL ;
    PORT
      LAYER M4 ;
        RECT  64.716 8.256 64.8 8.28 ;
    END
  END kv_request[65]
  PIN kv_request[66]
    DIRECTION INPUT ;
    USE SIGNAL ;
    PORT
      LAYER M4 ;
        RECT  64.716 8.4 64.8 8.424 ;
    END
  END kv_request[66]
  PIN kv_request[67]
    DIRECTION INPUT ;
    USE SIGNAL ;
    PORT
      LAYER M4 ;
        RECT  64.716 8.544 64.8 8.568 ;
    END
  END kv_request[67]
  PIN kv_request[68]
    DIRECTION INPUT ;
    USE SIGNAL ;
    PORT
      LAYER M4 ;
        RECT  64.716 8.64 64.8 8.664 ;
    END
  END kv_request[68]
  PIN kv_request[69]
    DIRECTION INPUT ;
    USE SIGNAL ;
    PORT
      LAYER M4 ;
        RECT  64.716 8.784 64.8 8.808 ;
    END
  END kv_request[69]
  PIN kv_request[6]
    DIRECTION INPUT ;
    USE SIGNAL ;
    PORT
      LAYER M4 ;
        RECT  64.716 0.816 64.8 0.84 ;
    END
  END kv_request[6]
  PIN kv_request[70]
    DIRECTION INPUT ;
    USE SIGNAL ;
    PORT
      LAYER M4 ;
        RECT  64.716 8.928 64.8 8.952 ;
    END
  END kv_request[70]
  PIN kv_request[71]
    DIRECTION INPUT ;
    USE SIGNAL ;
    PORT
      LAYER M4 ;
        RECT  64.716 9.024 64.8 9.048 ;
    END
  END kv_request[71]
  PIN kv_request[72]
    DIRECTION INPUT ;
    USE SIGNAL ;
    PORT
      LAYER M4 ;
        RECT  64.716 9.168 64.8 9.192 ;
    END
  END kv_request[72]
  PIN kv_request[73]
    DIRECTION INPUT ;
    USE SIGNAL ;
    PORT
      LAYER M4 ;
        RECT  64.716 9.312 64.8 9.336 ;
    END
  END kv_request[73]
  PIN kv_request[74]
    DIRECTION INPUT ;
    USE SIGNAL ;
    PORT
      LAYER M4 ;
        RECT  64.716 9.408 64.8 9.432 ;
    END
  END kv_request[74]
  PIN kv_request[75]
    DIRECTION INPUT ;
    USE SIGNAL ;
    PORT
      LAYER M4 ;
        RECT  64.716 9.552 64.8 9.576 ;
    END
  END kv_request[75]
  PIN kv_request[76]
    DIRECTION INPUT ;
    USE SIGNAL ;
    PORT
      LAYER M4 ;
        RECT  64.716 9.648 64.8 9.672 ;
    END
  END kv_request[76]
  PIN kv_request[77]
    DIRECTION INPUT ;
    USE SIGNAL ;
    PORT
      LAYER M4 ;
        RECT  64.716 9.792 64.8 9.816 ;
    END
  END kv_request[77]
  PIN kv_request[78]
    DIRECTION INPUT ;
    USE SIGNAL ;
    PORT
      LAYER M4 ;
        RECT  64.716 9.936 64.8 9.96 ;
    END
  END kv_request[78]
  PIN kv_request[79]
    DIRECTION INPUT ;
    USE SIGNAL ;
    PORT
      LAYER M4 ;
        RECT  64.716 10.032 64.8 10.056 ;
    END
  END kv_request[79]
  PIN kv_request[7]
    DIRECTION INPUT ;
    USE SIGNAL ;
    PORT
      LAYER M4 ;
        RECT  64.716 0.96 64.8 0.984 ;
    END
  END kv_request[7]
  PIN kv_request[80]
    DIRECTION INPUT ;
    USE SIGNAL ;
    PORT
      LAYER M4 ;
        RECT  64.716 10.176 64.8 10.2 ;
    END
  END kv_request[80]
  PIN kv_request[81]
    DIRECTION INPUT ;
    USE SIGNAL ;
    PORT
      LAYER M4 ;
        RECT  64.716 10.32 64.8 10.344 ;
    END
  END kv_request[81]
  PIN kv_request[82]
    DIRECTION INPUT ;
    USE SIGNAL ;
    PORT
      LAYER M4 ;
        RECT  64.716 10.416 64.8 10.44 ;
    END
  END kv_request[82]
  PIN kv_request[83]
    DIRECTION INPUT ;
    USE SIGNAL ;
    PORT
      LAYER M4 ;
        RECT  64.716 10.56 64.8 10.584 ;
    END
  END kv_request[83]
  PIN kv_request[84]
    DIRECTION INPUT ;
    USE SIGNAL ;
    PORT
      LAYER M4 ;
        RECT  64.716 10.704 64.8 10.728 ;
    END
  END kv_request[84]
  PIN kv_request[85]
    DIRECTION INPUT ;
    USE SIGNAL ;
    PORT
      LAYER M4 ;
        RECT  64.716 10.8 64.8 10.824 ;
    END
  END kv_request[85]
  PIN kv_request[86]
    DIRECTION INPUT ;
    USE SIGNAL ;
    PORT
      LAYER M4 ;
        RECT  64.716 10.944 64.8 10.968 ;
    END
  END kv_request[86]
  PIN kv_request[87]
    DIRECTION INPUT ;
    USE SIGNAL ;
    PORT
      LAYER M4 ;
        RECT  64.716 11.04 64.8 11.064 ;
    END
  END kv_request[87]
  PIN kv_request[88]
    DIRECTION INPUT ;
    USE SIGNAL ;
    PORT
      LAYER M4 ;
        RECT  64.716 11.184 64.8 11.208 ;
    END
  END kv_request[88]
  PIN kv_request[89]
    DIRECTION INPUT ;
    USE SIGNAL ;
    PORT
      LAYER M4 ;
        RECT  64.716 11.328 64.8 11.352 ;
    END
  END kv_request[89]
  PIN kv_request[8]
    DIRECTION INPUT ;
    USE SIGNAL ;
    PORT
      LAYER M4 ;
        RECT  64.716 1.056 64.8 1.08 ;
    END
  END kv_request[8]
  PIN kv_request[90]
    DIRECTION INPUT ;
    USE SIGNAL ;
    PORT
      LAYER M4 ;
        RECT  64.716 11.424 64.8 11.448 ;
    END
  END kv_request[90]
  PIN kv_request[91]
    DIRECTION INPUT ;
    USE SIGNAL ;
    PORT
      LAYER M4 ;
        RECT  64.716 11.568 64.8 11.592 ;
    END
  END kv_request[91]
  PIN kv_request[92]
    DIRECTION INPUT ;
    USE SIGNAL ;
    PORT
      LAYER M4 ;
        RECT  64.716 11.712 64.8 11.736 ;
    END
  END kv_request[92]
  PIN kv_request[93]
    DIRECTION INPUT ;
    USE SIGNAL ;
    PORT
      LAYER M4 ;
        RECT  64.716 11.808 64.8 11.832 ;
    END
  END kv_request[93]
  PIN kv_request[94]
    DIRECTION INPUT ;
    USE SIGNAL ;
    PORT
      LAYER M4 ;
        RECT  64.716 11.952 64.8 11.976 ;
    END
  END kv_request[94]
  PIN kv_request[95]
    DIRECTION INPUT ;
    USE SIGNAL ;
    PORT
      LAYER M4 ;
        RECT  64.716 12.096 64.8 12.12 ;
    END
  END kv_request[95]
  PIN kv_request[96]
    DIRECTION INPUT ;
    USE SIGNAL ;
    PORT
      LAYER M4 ;
        RECT  64.716 12.192 64.8 12.216 ;
    END
  END kv_request[96]
  PIN kv_request[97]
    DIRECTION INPUT ;
    USE SIGNAL ;
    PORT
      LAYER M4 ;
        RECT  64.716 12.336 64.8 12.36 ;
    END
  END kv_request[97]
  PIN kv_request[98]
    DIRECTION INPUT ;
    USE SIGNAL ;
    PORT
      LAYER M4 ;
        RECT  64.716 12.432 64.8 12.456 ;
    END
  END kv_request[98]
  PIN kv_request[99]
    DIRECTION INPUT ;
    USE SIGNAL ;
    PORT
      LAYER M4 ;
        RECT  64.716 12.576 64.8 12.6 ;
    END
  END kv_request[99]
  PIN kv_request[9]
    DIRECTION INPUT ;
    USE SIGNAL ;
    PORT
      LAYER M4 ;
        RECT  64.716 1.2 64.8 1.224 ;
    END
  END kv_request[9]
  PIN request[0]
    DIRECTION INPUT ;
    USE SIGNAL ;
    PORT
      LAYER M5 ;
        RECT  0.192 64.716 0.216 64.8 ;
    END
  END request[0]
  PIN request[100]
    DIRECTION INPUT ;
    USE SIGNAL ;
    PORT
      LAYER M5 ;
        RECT  12.768 64.716 12.792 64.8 ;
    END
  END request[100]
  PIN request[101]
    DIRECTION INPUT ;
    USE SIGNAL ;
    PORT
      LAYER M3 ;
        RECT  12.888 64.762 12.906 64.8 ;
    END
  END request[101]
  PIN request[102]
    DIRECTION INPUT ;
    USE SIGNAL ;
    PORT
      LAYER M5 ;
        RECT  13.008 64.716 13.032 64.8 ;
    END
  END request[102]
  PIN request[103]
    DIRECTION INPUT ;
    USE SIGNAL ;
    PORT
      LAYER M3 ;
        RECT  13.14 64.762 13.158 64.8 ;
    END
  END request[103]
  PIN request[104]
    DIRECTION INPUT ;
    USE SIGNAL ;
    PORT
      LAYER M5 ;
        RECT  13.248 64.716 13.272 64.8 ;
    END
  END request[104]
  PIN request[105]
    DIRECTION INPUT ;
    USE SIGNAL ;
    PORT
      LAYER M3 ;
        RECT  13.392 64.762 13.41 64.8 ;
    END
  END request[105]
  PIN request[106]
    DIRECTION INPUT ;
    USE SIGNAL ;
    PORT
      LAYER M5 ;
        RECT  13.536 64.716 13.56 64.8 ;
    END
  END request[106]
  PIN request[107]
    DIRECTION INPUT ;
    USE SIGNAL ;
    PORT
      LAYER M3 ;
        RECT  13.644 64.762 13.662 64.8 ;
    END
  END request[107]
  PIN request[108]
    DIRECTION INPUT ;
    USE SIGNAL ;
    PORT
      LAYER M5 ;
        RECT  13.776 64.716 13.8 64.8 ;
    END
  END request[108]
  PIN request[109]
    DIRECTION INPUT ;
    USE SIGNAL ;
    PORT
      LAYER M3 ;
        RECT  13.896 64.762 13.914 64.8 ;
    END
  END request[109]
  PIN request[10]
    DIRECTION INPUT ;
    USE SIGNAL ;
    PORT
      LAYER M5 ;
        RECT  1.44 64.716 1.464 64.8 ;
    END
  END request[10]
  PIN request[110]
    DIRECTION INPUT ;
    USE SIGNAL ;
    PORT
      LAYER M5 ;
        RECT  14.016 64.716 14.04 64.8 ;
    END
  END request[110]
  PIN request[111]
    DIRECTION INPUT ;
    USE SIGNAL ;
    PORT
      LAYER M3 ;
        RECT  14.148 64.762 14.166 64.8 ;
    END
  END request[111]
  PIN request[112]
    DIRECTION INPUT ;
    USE SIGNAL ;
    PORT
      LAYER M5 ;
        RECT  14.256 64.716 14.28 64.8 ;
    END
  END request[112]
  PIN request[113]
    DIRECTION INPUT ;
    USE SIGNAL ;
    PORT
      LAYER M3 ;
        RECT  14.4 64.762 14.418 64.8 ;
    END
  END request[113]
  PIN request[114]
    DIRECTION INPUT ;
    USE SIGNAL ;
    PORT
      LAYER M5 ;
        RECT  14.544 64.716 14.568 64.8 ;
    END
  END request[114]
  PIN request[115]
    DIRECTION INPUT ;
    USE SIGNAL ;
    PORT
      LAYER M3 ;
        RECT  14.652 64.762 14.67 64.8 ;
    END
  END request[115]
  PIN request[116]
    DIRECTION INPUT ;
    USE SIGNAL ;
    PORT
      LAYER M5 ;
        RECT  14.784 64.716 14.808 64.8 ;
    END
  END request[116]
  PIN request[117]
    DIRECTION INPUT ;
    USE SIGNAL ;
    PORT
      LAYER M3 ;
        RECT  14.904 64.762 14.922 64.8 ;
    END
  END request[117]
  PIN request[118]
    DIRECTION INPUT ;
    USE SIGNAL ;
    PORT
      LAYER M5 ;
        RECT  15.024 64.716 15.048 64.8 ;
    END
  END request[118]
  PIN request[119]
    DIRECTION INPUT ;
    USE SIGNAL ;
    PORT
      LAYER M3 ;
        RECT  15.156 64.762 15.174 64.8 ;
    END
  END request[119]
  PIN request[11]
    DIRECTION INPUT ;
    USE SIGNAL ;
    PORT
      LAYER M3 ;
        RECT  1.548 64.762 1.566 64.8 ;
    END
  END request[11]
  PIN request[120]
    DIRECTION INPUT ;
    USE SIGNAL ;
    PORT
      LAYER M5 ;
        RECT  15.264 64.716 15.288 64.8 ;
    END
  END request[120]
  PIN request[121]
    DIRECTION INPUT ;
    USE SIGNAL ;
    PORT
      LAYER M3 ;
        RECT  15.408 64.762 15.426 64.8 ;
    END
  END request[121]
  PIN request[122]
    DIRECTION INPUT ;
    USE SIGNAL ;
    PORT
      LAYER M5 ;
        RECT  15.504 64.716 15.528 64.8 ;
    END
  END request[122]
  PIN request[123]
    DIRECTION INPUT ;
    USE SIGNAL ;
    PORT
      LAYER M3 ;
        RECT  15.66 64.762 15.678 64.8 ;
    END
  END request[123]
  PIN request[124]
    DIRECTION INPUT ;
    USE SIGNAL ;
    PORT
      LAYER M5 ;
        RECT  15.792 64.716 15.816 64.8 ;
    END
  END request[124]
  PIN request[125]
    DIRECTION INPUT ;
    USE SIGNAL ;
    PORT
      LAYER M3 ;
        RECT  15.912 64.762 15.93 64.8 ;
    END
  END request[125]
  PIN request[126]
    DIRECTION INPUT ;
    USE SIGNAL ;
    PORT
      LAYER M5 ;
        RECT  16.032 64.716 16.056 64.8 ;
    END
  END request[126]
  PIN request[127]
    DIRECTION INPUT ;
    USE SIGNAL ;
    PORT
      LAYER M3 ;
        RECT  16.164 64.762 16.182 64.8 ;
    END
  END request[127]
  PIN request[128]
    DIRECTION INPUT ;
    USE SIGNAL ;
    PORT
      LAYER M5 ;
        RECT  16.272 64.716 16.296 64.8 ;
    END
  END request[128]
  PIN request[129]
    DIRECTION INPUT ;
    USE SIGNAL ;
    PORT
      LAYER M3 ;
        RECT  16.416 64.762 16.434 64.8 ;
    END
  END request[129]
  PIN request[12]
    DIRECTION INPUT ;
    USE SIGNAL ;
    PORT
      LAYER M5 ;
        RECT  1.68 64.716 1.704 64.8 ;
    END
  END request[12]
  PIN request[130]
    DIRECTION INPUT ;
    USE SIGNAL ;
    PORT
      LAYER M5 ;
        RECT  16.512 64.716 16.536 64.8 ;
    END
  END request[130]
  PIN request[131]
    DIRECTION INPUT ;
    USE SIGNAL ;
    PORT
      LAYER M3 ;
        RECT  16.668 64.762 16.686 64.8 ;
    END
  END request[131]
  PIN request[132]
    DIRECTION INPUT ;
    USE SIGNAL ;
    PORT
      LAYER M5 ;
        RECT  16.8 64.716 16.824 64.8 ;
    END
  END request[132]
  PIN request[133]
    DIRECTION INPUT ;
    USE SIGNAL ;
    PORT
      LAYER M3 ;
        RECT  16.92 64.762 16.938 64.8 ;
    END
  END request[133]
  PIN request[134]
    DIRECTION INPUT ;
    USE SIGNAL ;
    PORT
      LAYER M5 ;
        RECT  17.04 64.716 17.064 64.8 ;
    END
  END request[134]
  PIN request[135]
    DIRECTION INPUT ;
    USE SIGNAL ;
    PORT
      LAYER M3 ;
        RECT  17.172 64.762 17.19 64.8 ;
    END
  END request[135]
  PIN request[136]
    DIRECTION INPUT ;
    USE SIGNAL ;
    PORT
      LAYER M5 ;
        RECT  17.28 64.716 17.304 64.8 ;
    END
  END request[136]
  PIN request[137]
    DIRECTION INPUT ;
    USE SIGNAL ;
    PORT
      LAYER M3 ;
        RECT  17.424 64.762 17.442 64.8 ;
    END
  END request[137]
  PIN request[138]
    DIRECTION INPUT ;
    USE SIGNAL ;
    PORT
      LAYER M5 ;
        RECT  17.52 64.716 17.544 64.8 ;
    END
  END request[138]
  PIN request[139]
    DIRECTION INPUT ;
    USE SIGNAL ;
    PORT
      LAYER M3 ;
        RECT  17.676 64.762 17.694 64.8 ;
    END
  END request[139]
  PIN request[13]
    DIRECTION INPUT ;
    USE SIGNAL ;
    PORT
      LAYER M3 ;
        RECT  1.8 64.762 1.818 64.8 ;
    END
  END request[13]
  PIN request[140]
    DIRECTION INPUT ;
    USE SIGNAL ;
    PORT
      LAYER M5 ;
        RECT  17.808 64.716 17.832 64.8 ;
    END
  END request[140]
  PIN request[141]
    DIRECTION INPUT ;
    USE SIGNAL ;
    PORT
      LAYER M3 ;
        RECT  17.928 64.762 17.946 64.8 ;
    END
  END request[141]
  PIN request[142]
    DIRECTION INPUT ;
    USE SIGNAL ;
    PORT
      LAYER M5 ;
        RECT  18.048 64.716 18.072 64.8 ;
    END
  END request[142]
  PIN request[143]
    DIRECTION INPUT ;
    USE SIGNAL ;
    PORT
      LAYER M3 ;
        RECT  18.18 64.762 18.198 64.8 ;
    END
  END request[143]
  PIN request[144]
    DIRECTION INPUT ;
    USE SIGNAL ;
    PORT
      LAYER M5 ;
        RECT  18.288 64.716 18.312 64.8 ;
    END
  END request[144]
  PIN request[145]
    DIRECTION INPUT ;
    USE SIGNAL ;
    PORT
      LAYER M3 ;
        RECT  18.432 64.762 18.45 64.8 ;
    END
  END request[145]
  PIN request[146]
    DIRECTION INPUT ;
    USE SIGNAL ;
    PORT
      LAYER M5 ;
        RECT  18.528 64.716 18.552 64.8 ;
    END
  END request[146]
  PIN request[147]
    DIRECTION INPUT ;
    USE SIGNAL ;
    PORT
      LAYER M3 ;
        RECT  18.684 64.762 18.702 64.8 ;
    END
  END request[147]
  PIN request[148]
    DIRECTION INPUT ;
    USE SIGNAL ;
    PORT
      LAYER M5 ;
        RECT  18.816 64.716 18.84 64.8 ;
    END
  END request[148]
  PIN request[149]
    DIRECTION INPUT ;
    USE SIGNAL ;
    PORT
      LAYER M3 ;
        RECT  18.936 64.762 18.954 64.8 ;
    END
  END request[149]
  PIN request[14]
    DIRECTION INPUT ;
    USE SIGNAL ;
    PORT
      LAYER M5 ;
        RECT  1.92 64.716 1.944 64.8 ;
    END
  END request[14]
  PIN request[150]
    DIRECTION INPUT ;
    USE SIGNAL ;
    PORT
      LAYER M5 ;
        RECT  19.056 64.716 19.08 64.8 ;
    END
  END request[150]
  PIN request[151]
    DIRECTION INPUT ;
    USE SIGNAL ;
    PORT
      LAYER M3 ;
        RECT  19.188 64.762 19.206 64.8 ;
    END
  END request[151]
  PIN request[152]
    DIRECTION INPUT ;
    USE SIGNAL ;
    PORT
      LAYER M5 ;
        RECT  19.296 64.716 19.32 64.8 ;
    END
  END request[152]
  PIN request[153]
    DIRECTION INPUT ;
    USE SIGNAL ;
    PORT
      LAYER M3 ;
        RECT  19.44 64.762 19.458 64.8 ;
    END
  END request[153]
  PIN request[154]
    DIRECTION INPUT ;
    USE SIGNAL ;
    PORT
      LAYER M5 ;
        RECT  19.536 64.716 19.56 64.8 ;
    END
  END request[154]
  PIN request[155]
    DIRECTION INPUT ;
    USE SIGNAL ;
    PORT
      LAYER M3 ;
        RECT  19.692 64.762 19.71 64.8 ;
    END
  END request[155]
  PIN request[156]
    DIRECTION INPUT ;
    USE SIGNAL ;
    PORT
      LAYER M5 ;
        RECT  19.824 64.716 19.848 64.8 ;
    END
  END request[156]
  PIN request[157]
    DIRECTION INPUT ;
    USE SIGNAL ;
    PORT
      LAYER M3 ;
        RECT  19.944 64.762 19.962 64.8 ;
    END
  END request[157]
  PIN request[158]
    DIRECTION INPUT ;
    USE SIGNAL ;
    PORT
      LAYER M5 ;
        RECT  20.064 64.716 20.088 64.8 ;
    END
  END request[158]
  PIN request[159]
    DIRECTION INPUT ;
    USE SIGNAL ;
    PORT
      LAYER M3 ;
        RECT  20.196 64.762 20.214 64.8 ;
    END
  END request[159]
  PIN request[15]
    DIRECTION INPUT ;
    USE SIGNAL ;
    PORT
      LAYER M3 ;
        RECT  2.052 64.762 2.07 64.8 ;
    END
  END request[15]
  PIN request[160]
    DIRECTION INPUT ;
    USE SIGNAL ;
    PORT
      LAYER M5 ;
        RECT  20.304 64.716 20.328 64.8 ;
    END
  END request[160]
  PIN request[161]
    DIRECTION INPUT ;
    USE SIGNAL ;
    PORT
      LAYER M3 ;
        RECT  20.448 64.762 20.466 64.8 ;
    END
  END request[161]
  PIN request[162]
    DIRECTION INPUT ;
    USE SIGNAL ;
    PORT
      LAYER M5 ;
        RECT  20.544 64.716 20.568 64.8 ;
    END
  END request[162]
  PIN request[163]
    DIRECTION INPUT ;
    USE SIGNAL ;
    PORT
      LAYER M3 ;
        RECT  20.7 64.762 20.718 64.8 ;
    END
  END request[163]
  PIN request[164]
    DIRECTION INPUT ;
    USE SIGNAL ;
    PORT
      LAYER M5 ;
        RECT  20.832 64.716 20.856 64.8 ;
    END
  END request[164]
  PIN request[165]
    DIRECTION INPUT ;
    USE SIGNAL ;
    PORT
      LAYER M3 ;
        RECT  20.952 64.762 20.97 64.8 ;
    END
  END request[165]
  PIN request[166]
    DIRECTION INPUT ;
    USE SIGNAL ;
    PORT
      LAYER M5 ;
        RECT  21.072 64.716 21.096 64.8 ;
    END
  END request[166]
  PIN request[167]
    DIRECTION INPUT ;
    USE SIGNAL ;
    PORT
      LAYER M3 ;
        RECT  21.204 64.762 21.222 64.8 ;
    END
  END request[167]
  PIN request[168]
    DIRECTION INPUT ;
    USE SIGNAL ;
    PORT
      LAYER M5 ;
        RECT  21.312 64.716 21.336 64.8 ;
    END
  END request[168]
  PIN request[169]
    DIRECTION INPUT ;
    USE SIGNAL ;
    PORT
      LAYER M3 ;
        RECT  21.456 64.762 21.474 64.8 ;
    END
  END request[169]
  PIN request[16]
    DIRECTION INPUT ;
    USE SIGNAL ;
    PORT
      LAYER M5 ;
        RECT  2.208 64.716 2.232 64.8 ;
    END
  END request[16]
  PIN request[170]
    DIRECTION INPUT ;
    USE SIGNAL ;
    PORT
      LAYER M5 ;
        RECT  21.552 64.716 21.576 64.8 ;
    END
  END request[170]
  PIN request[171]
    DIRECTION INPUT ;
    USE SIGNAL ;
    PORT
      LAYER M3 ;
        RECT  21.708 64.762 21.726 64.8 ;
    END
  END request[171]
  PIN request[172]
    DIRECTION INPUT ;
    USE SIGNAL ;
    PORT
      LAYER M5 ;
        RECT  21.84 64.716 21.864 64.8 ;
    END
  END request[172]
  PIN request[173]
    DIRECTION INPUT ;
    USE SIGNAL ;
    PORT
      LAYER M3 ;
        RECT  21.96 64.762 21.978 64.8 ;
    END
  END request[173]
  PIN request[174]
    DIRECTION INPUT ;
    USE SIGNAL ;
    PORT
      LAYER M5 ;
        RECT  22.08 64.716 22.104 64.8 ;
    END
  END request[174]
  PIN request[175]
    DIRECTION INPUT ;
    USE SIGNAL ;
    PORT
      LAYER M3 ;
        RECT  22.212 64.762 22.23 64.8 ;
    END
  END request[175]
  PIN request[176]
    DIRECTION INPUT ;
    USE SIGNAL ;
    PORT
      LAYER M5 ;
        RECT  22.32 64.716 22.344 64.8 ;
    END
  END request[176]
  PIN request[177]
    DIRECTION INPUT ;
    USE SIGNAL ;
    PORT
      LAYER M3 ;
        RECT  22.464 64.762 22.482 64.8 ;
    END
  END request[177]
  PIN request[178]
    DIRECTION INPUT ;
    USE SIGNAL ;
    PORT
      LAYER M5 ;
        RECT  22.56 64.716 22.584 64.8 ;
    END
  END request[178]
  PIN request[179]
    DIRECTION INPUT ;
    USE SIGNAL ;
    PORT
      LAYER M3 ;
        RECT  22.716 64.762 22.734 64.8 ;
    END
  END request[179]
  PIN request[17]
    DIRECTION INPUT ;
    USE SIGNAL ;
    PORT
      LAYER M3 ;
        RECT  2.304 64.762 2.322 64.8 ;
    END
  END request[17]
  PIN request[180]
    DIRECTION INPUT ;
    USE SIGNAL ;
    PORT
      LAYER M5 ;
        RECT  22.848 64.716 22.872 64.8 ;
    END
  END request[180]
  PIN request[181]
    DIRECTION INPUT ;
    USE SIGNAL ;
    PORT
      LAYER M3 ;
        RECT  22.968 64.762 22.986 64.8 ;
    END
  END request[181]
  PIN request[182]
    DIRECTION INPUT ;
    USE SIGNAL ;
    PORT
      LAYER M5 ;
        RECT  23.088 64.716 23.112 64.8 ;
    END
  END request[182]
  PIN request[183]
    DIRECTION INPUT ;
    USE SIGNAL ;
    PORT
      LAYER M3 ;
        RECT  23.22 64.762 23.238 64.8 ;
    END
  END request[183]
  PIN request[184]
    DIRECTION INPUT ;
    USE SIGNAL ;
    PORT
      LAYER M5 ;
        RECT  23.328 64.716 23.352 64.8 ;
    END
  END request[184]
  PIN request[185]
    DIRECTION INPUT ;
    USE SIGNAL ;
    PORT
      LAYER M3 ;
        RECT  23.472 64.762 23.49 64.8 ;
    END
  END request[185]
  PIN request[186]
    DIRECTION INPUT ;
    USE SIGNAL ;
    PORT
      LAYER M5 ;
        RECT  23.568 64.716 23.592 64.8 ;
    END
  END request[186]
  PIN request[187]
    DIRECTION INPUT ;
    USE SIGNAL ;
    PORT
      LAYER M3 ;
        RECT  23.724 64.762 23.742 64.8 ;
    END
  END request[187]
  PIN request[188]
    DIRECTION INPUT ;
    USE SIGNAL ;
    PORT
      LAYER M5 ;
        RECT  23.856 64.716 23.88 64.8 ;
    END
  END request[188]
  PIN request[189]
    DIRECTION INPUT ;
    USE SIGNAL ;
    PORT
      LAYER M3 ;
        RECT  23.976 64.762 23.994 64.8 ;
    END
  END request[189]
  PIN request[18]
    DIRECTION INPUT ;
    USE SIGNAL ;
    PORT
      LAYER M5 ;
        RECT  2.448 64.716 2.472 64.8 ;
    END
  END request[18]
  PIN request[190]
    DIRECTION INPUT ;
    USE SIGNAL ;
    PORT
      LAYER M5 ;
        RECT  24.096 64.716 24.12 64.8 ;
    END
  END request[190]
  PIN request[191]
    DIRECTION INPUT ;
    USE SIGNAL ;
    PORT
      LAYER M3 ;
        RECT  24.228 64.762 24.246 64.8 ;
    END
  END request[191]
  PIN request[192]
    DIRECTION INPUT ;
    USE SIGNAL ;
    PORT
      LAYER M5 ;
        RECT  24.336 64.716 24.36 64.8 ;
    END
  END request[192]
  PIN request[193]
    DIRECTION INPUT ;
    USE SIGNAL ;
    PORT
      LAYER M3 ;
        RECT  24.48 64.762 24.498 64.8 ;
    END
  END request[193]
  PIN request[194]
    DIRECTION INPUT ;
    USE SIGNAL ;
    PORT
      LAYER M5 ;
        RECT  24.576 64.716 24.6 64.8 ;
    END
  END request[194]
  PIN request[195]
    DIRECTION INPUT ;
    USE SIGNAL ;
    PORT
      LAYER M3 ;
        RECT  24.732 64.762 24.75 64.8 ;
    END
  END request[195]
  PIN request[196]
    DIRECTION INPUT ;
    USE SIGNAL ;
    PORT
      LAYER M5 ;
        RECT  24.816 64.716 24.84 64.8 ;
    END
  END request[196]
  PIN request[197]
    DIRECTION INPUT ;
    USE SIGNAL ;
    PORT
      LAYER M3 ;
        RECT  24.984 64.762 25.002 64.8 ;
    END
  END request[197]
  PIN request[198]
    DIRECTION INPUT ;
    USE SIGNAL ;
    PORT
      LAYER M5 ;
        RECT  25.104 64.716 25.128 64.8 ;
    END
  END request[198]
  PIN request[199]
    DIRECTION INPUT ;
    USE SIGNAL ;
    PORT
      LAYER M3 ;
        RECT  25.236 64.762 25.254 64.8 ;
    END
  END request[199]
  PIN request[19]
    DIRECTION INPUT ;
    USE SIGNAL ;
    PORT
      LAYER M3 ;
        RECT  2.556 64.762 2.574 64.8 ;
    END
  END request[19]
  PIN request[1]
    DIRECTION INPUT ;
    USE SIGNAL ;
    PORT
      LAYER M3 ;
        RECT  0.324 64.762 0.342 64.8 ;
    END
  END request[1]
  PIN request[200]
    DIRECTION INPUT ;
    USE SIGNAL ;
    PORT
      LAYER M5 ;
        RECT  25.344 64.716 25.368 64.8 ;
    END
  END request[200]
  PIN request[201]
    DIRECTION INPUT ;
    USE SIGNAL ;
    PORT
      LAYER M3 ;
        RECT  25.488 64.762 25.506 64.8 ;
    END
  END request[201]
  PIN request[202]
    DIRECTION INPUT ;
    USE SIGNAL ;
    PORT
      LAYER M5 ;
        RECT  25.584 64.716 25.608 64.8 ;
    END
  END request[202]
  PIN request[203]
    DIRECTION INPUT ;
    USE SIGNAL ;
    PORT
      LAYER M3 ;
        RECT  25.74 64.762 25.758 64.8 ;
    END
  END request[203]
  PIN request[204]
    DIRECTION INPUT ;
    USE SIGNAL ;
    PORT
      LAYER M5 ;
        RECT  25.824 64.716 25.848 64.8 ;
    END
  END request[204]
  PIN request[205]
    DIRECTION INPUT ;
    USE SIGNAL ;
    PORT
      LAYER M3 ;
        RECT  25.992 64.762 26.01 64.8 ;
    END
  END request[205]
  PIN request[206]
    DIRECTION INPUT ;
    USE SIGNAL ;
    PORT
      LAYER M5 ;
        RECT  26.112 64.716 26.136 64.8 ;
    END
  END request[206]
  PIN request[207]
    DIRECTION INPUT ;
    USE SIGNAL ;
    PORT
      LAYER M3 ;
        RECT  26.244 64.762 26.262 64.8 ;
    END
  END request[207]
  PIN request[208]
    DIRECTION INPUT ;
    USE SIGNAL ;
    PORT
      LAYER M5 ;
        RECT  26.352 64.716 26.376 64.8 ;
    END
  END request[208]
  PIN request[209]
    DIRECTION INPUT ;
    USE SIGNAL ;
    PORT
      LAYER M3 ;
        RECT  26.46 64.762 26.478 64.8 ;
    END
  END request[209]
  PIN request[20]
    DIRECTION INPUT ;
    USE SIGNAL ;
    PORT
      LAYER M5 ;
        RECT  2.688 64.716 2.712 64.8 ;
    END
  END request[20]
  PIN request[210]
    DIRECTION INPUT ;
    USE SIGNAL ;
    PORT
      LAYER M5 ;
        RECT  26.592 64.716 26.616 64.8 ;
    END
  END request[210]
  PIN request[211]
    DIRECTION INPUT ;
    USE SIGNAL ;
    PORT
      LAYER M3 ;
        RECT  26.712 64.762 26.73 64.8 ;
    END
  END request[211]
  PIN request[212]
    DIRECTION INPUT ;
    USE SIGNAL ;
    PORT
      LAYER M5 ;
        RECT  26.832 64.716 26.856 64.8 ;
    END
  END request[212]
  PIN request[213]
    DIRECTION INPUT ;
    USE SIGNAL ;
    PORT
      LAYER M3 ;
        RECT  26.964 64.762 26.982 64.8 ;
    END
  END request[213]
  PIN request[214]
    DIRECTION INPUT ;
    USE SIGNAL ;
    PORT
      LAYER M5 ;
        RECT  27.12 64.716 27.144 64.8 ;
    END
  END request[214]
  PIN request[215]
    DIRECTION INPUT ;
    USE SIGNAL ;
    PORT
      LAYER M3 ;
        RECT  27.216 64.762 27.234 64.8 ;
    END
  END request[215]
  PIN request[216]
    DIRECTION INPUT ;
    USE SIGNAL ;
    PORT
      LAYER M5 ;
        RECT  27.36 64.716 27.384 64.8 ;
    END
  END request[216]
  PIN request[217]
    DIRECTION INPUT ;
    USE SIGNAL ;
    PORT
      LAYER M3 ;
        RECT  27.468 64.762 27.486 64.8 ;
    END
  END request[217]
  PIN request[218]
    DIRECTION INPUT ;
    USE SIGNAL ;
    PORT
      LAYER M5 ;
        RECT  27.6 64.716 27.624 64.8 ;
    END
  END request[218]
  PIN request[219]
    DIRECTION INPUT ;
    USE SIGNAL ;
    PORT
      LAYER M3 ;
        RECT  27.72 64.762 27.738 64.8 ;
    END
  END request[219]
  PIN request[21]
    DIRECTION INPUT ;
    USE SIGNAL ;
    PORT
      LAYER M3 ;
        RECT  2.808 64.762 2.826 64.8 ;
    END
  END request[21]
  PIN request[220]
    DIRECTION INPUT ;
    USE SIGNAL ;
    PORT
      LAYER M5 ;
        RECT  27.84 64.716 27.864 64.8 ;
    END
  END request[220]
  PIN request[221]
    DIRECTION INPUT ;
    USE SIGNAL ;
    PORT
      LAYER M3 ;
        RECT  27.972 64.762 27.99 64.8 ;
    END
  END request[221]
  PIN request[222]
    DIRECTION INPUT ;
    USE SIGNAL ;
    PORT
      LAYER M5 ;
        RECT  28.128 64.716 28.152 64.8 ;
    END
  END request[222]
  PIN request[223]
    DIRECTION INPUT ;
    USE SIGNAL ;
    PORT
      LAYER M3 ;
        RECT  28.224 64.762 28.242 64.8 ;
    END
  END request[223]
  PIN request[224]
    DIRECTION INPUT ;
    USE SIGNAL ;
    PORT
      LAYER M5 ;
        RECT  28.368 64.716 28.392 64.8 ;
    END
  END request[224]
  PIN request[225]
    DIRECTION INPUT ;
    USE SIGNAL ;
    PORT
      LAYER M3 ;
        RECT  28.476 64.762 28.494 64.8 ;
    END
  END request[225]
  PIN request[226]
    DIRECTION INPUT ;
    USE SIGNAL ;
    PORT
      LAYER M5 ;
        RECT  28.608 64.716 28.632 64.8 ;
    END
  END request[226]
  PIN request[227]
    DIRECTION INPUT ;
    USE SIGNAL ;
    PORT
      LAYER M3 ;
        RECT  28.728 64.762 28.746 64.8 ;
    END
  END request[227]
  PIN request[228]
    DIRECTION INPUT ;
    USE SIGNAL ;
    PORT
      LAYER M5 ;
        RECT  28.848 64.716 28.872 64.8 ;
    END
  END request[228]
  PIN request[229]
    DIRECTION INPUT ;
    USE SIGNAL ;
    PORT
      LAYER M3 ;
        RECT  28.98 64.762 28.998 64.8 ;
    END
  END request[229]
  PIN request[22]
    DIRECTION INPUT ;
    USE SIGNAL ;
    PORT
      LAYER M5 ;
        RECT  2.928 64.716 2.952 64.8 ;
    END
  END request[22]
  PIN request[230]
    DIRECTION INPUT ;
    USE SIGNAL ;
    PORT
      LAYER M5 ;
        RECT  29.136 64.716 29.16 64.8 ;
    END
  END request[230]
  PIN request[231]
    DIRECTION INPUT ;
    USE SIGNAL ;
    PORT
      LAYER M3 ;
        RECT  29.232 64.762 29.25 64.8 ;
    END
  END request[231]
  PIN request[232]
    DIRECTION INPUT ;
    USE SIGNAL ;
    PORT
      LAYER M5 ;
        RECT  29.376 64.716 29.4 64.8 ;
    END
  END request[232]
  PIN request[233]
    DIRECTION INPUT ;
    USE SIGNAL ;
    PORT
      LAYER M3 ;
        RECT  29.484 64.762 29.502 64.8 ;
    END
  END request[233]
  PIN request[234]
    DIRECTION INPUT ;
    USE SIGNAL ;
    PORT
      LAYER M5 ;
        RECT  29.616 64.716 29.64 64.8 ;
    END
  END request[234]
  PIN request[235]
    DIRECTION INPUT ;
    USE SIGNAL ;
    PORT
      LAYER M3 ;
        RECT  29.736 64.762 29.754 64.8 ;
    END
  END request[235]
  PIN request[236]
    DIRECTION INPUT ;
    USE SIGNAL ;
    PORT
      LAYER M5 ;
        RECT  29.856 64.716 29.88 64.8 ;
    END
  END request[236]
  PIN request[237]
    DIRECTION INPUT ;
    USE SIGNAL ;
    PORT
      LAYER M3 ;
        RECT  29.988 64.762 30.006 64.8 ;
    END
  END request[237]
  PIN request[238]
    DIRECTION INPUT ;
    USE SIGNAL ;
    PORT
      LAYER M5 ;
        RECT  30.144 64.716 30.168 64.8 ;
    END
  END request[238]
  PIN request[239]
    DIRECTION INPUT ;
    USE SIGNAL ;
    PORT
      LAYER M3 ;
        RECT  30.24 64.762 30.258 64.8 ;
    END
  END request[239]
  PIN request[23]
    DIRECTION INPUT ;
    USE SIGNAL ;
    PORT
      LAYER M3 ;
        RECT  3.06 64.762 3.078 64.8 ;
    END
  END request[23]
  PIN request[240]
    DIRECTION INPUT ;
    USE SIGNAL ;
    PORT
      LAYER M5 ;
        RECT  30.384 64.716 30.408 64.8 ;
    END
  END request[240]
  PIN request[241]
    DIRECTION INPUT ;
    USE SIGNAL ;
    PORT
      LAYER M3 ;
        RECT  30.492 64.762 30.51 64.8 ;
    END
  END request[241]
  PIN request[242]
    DIRECTION INPUT ;
    USE SIGNAL ;
    PORT
      LAYER M5 ;
        RECT  30.624 64.716 30.648 64.8 ;
    END
  END request[242]
  PIN request[243]
    DIRECTION INPUT ;
    USE SIGNAL ;
    PORT
      LAYER M3 ;
        RECT  30.744 64.762 30.762 64.8 ;
    END
  END request[243]
  PIN request[244]
    DIRECTION INPUT ;
    USE SIGNAL ;
    PORT
      LAYER M5 ;
        RECT  30.864 64.716 30.888 64.8 ;
    END
  END request[244]
  PIN request[245]
    DIRECTION INPUT ;
    USE SIGNAL ;
    PORT
      LAYER M3 ;
        RECT  30.996 64.762 31.014 64.8 ;
    END
  END request[245]
  PIN request[246]
    DIRECTION INPUT ;
    USE SIGNAL ;
    PORT
      LAYER M5 ;
        RECT  31.152 64.716 31.176 64.8 ;
    END
  END request[246]
  PIN request[247]
    DIRECTION INPUT ;
    USE SIGNAL ;
    PORT
      LAYER M3 ;
        RECT  31.248 64.762 31.266 64.8 ;
    END
  END request[247]
  PIN request[248]
    DIRECTION INPUT ;
    USE SIGNAL ;
    PORT
      LAYER M5 ;
        RECT  31.392 64.716 31.416 64.8 ;
    END
  END request[248]
  PIN request[249]
    DIRECTION INPUT ;
    USE SIGNAL ;
    PORT
      LAYER M3 ;
        RECT  31.5 64.762 31.518 64.8 ;
    END
  END request[249]
  PIN request[24]
    DIRECTION INPUT ;
    USE SIGNAL ;
    PORT
      LAYER M5 ;
        RECT  3.216 64.716 3.24 64.8 ;
    END
  END request[24]
  PIN request[250]
    DIRECTION INPUT ;
    USE SIGNAL ;
    PORT
      LAYER M5 ;
        RECT  31.632 64.716 31.656 64.8 ;
    END
  END request[250]
  PIN request[251]
    DIRECTION INPUT ;
    USE SIGNAL ;
    PORT
      LAYER M3 ;
        RECT  31.752 64.762 31.77 64.8 ;
    END
  END request[251]
  PIN request[252]
    DIRECTION INPUT ;
    USE SIGNAL ;
    PORT
      LAYER M5 ;
        RECT  31.872 64.716 31.896 64.8 ;
    END
  END request[252]
  PIN request[253]
    DIRECTION INPUT ;
    USE SIGNAL ;
    PORT
      LAYER M3 ;
        RECT  32.004 64.762 32.022 64.8 ;
    END
  END request[253]
  PIN request[254]
    DIRECTION INPUT ;
    USE SIGNAL ;
    PORT
      LAYER M5 ;
        RECT  32.16 64.716 32.184 64.8 ;
    END
  END request[254]
  PIN request[255]
    DIRECTION INPUT ;
    USE SIGNAL ;
    PORT
      LAYER M3 ;
        RECT  32.256 64.762 32.274 64.8 ;
    END
  END request[255]
  PIN request[256]
    DIRECTION INPUT ;
    USE SIGNAL ;
    PORT
      LAYER M5 ;
        RECT  32.4 64.716 32.424 64.8 ;
    END
  END request[256]
  PIN request[257]
    DIRECTION INPUT ;
    USE SIGNAL ;
    PORT
      LAYER M3 ;
        RECT  32.508 64.762 32.526 64.8 ;
    END
  END request[257]
  PIN request[258]
    DIRECTION INPUT ;
    USE SIGNAL ;
    PORT
      LAYER M5 ;
        RECT  32.64 64.716 32.664 64.8 ;
    END
  END request[258]
  PIN request[259]
    DIRECTION INPUT ;
    USE SIGNAL ;
    PORT
      LAYER M3 ;
        RECT  32.76 64.762 32.778 64.8 ;
    END
  END request[259]
  PIN request[25]
    DIRECTION INPUT ;
    USE SIGNAL ;
    PORT
      LAYER M3 ;
        RECT  3.312 64.762 3.33 64.8 ;
    END
  END request[25]
  PIN request[260]
    DIRECTION INPUT ;
    USE SIGNAL ;
    PORT
      LAYER M5 ;
        RECT  32.88 64.716 32.904 64.8 ;
    END
  END request[260]
  PIN request[261]
    DIRECTION INPUT ;
    USE SIGNAL ;
    PORT
      LAYER M3 ;
        RECT  33.012 64.762 33.03 64.8 ;
    END
  END request[261]
  PIN request[262]
    DIRECTION INPUT ;
    USE SIGNAL ;
    PORT
      LAYER M5 ;
        RECT  33.12 64.716 33.144 64.8 ;
    END
  END request[262]
  PIN request[263]
    DIRECTION INPUT ;
    USE SIGNAL ;
    PORT
      LAYER M3 ;
        RECT  33.264 64.762 33.282 64.8 ;
    END
  END request[263]
  PIN request[264]
    DIRECTION INPUT ;
    USE SIGNAL ;
    PORT
      LAYER M5 ;
        RECT  33.408 64.716 33.432 64.8 ;
    END
  END request[264]
  PIN request[265]
    DIRECTION INPUT ;
    USE SIGNAL ;
    PORT
      LAYER M3 ;
        RECT  33.516 64.762 33.534 64.8 ;
    END
  END request[265]
  PIN request[266]
    DIRECTION INPUT ;
    USE SIGNAL ;
    PORT
      LAYER M5 ;
        RECT  33.648 64.716 33.672 64.8 ;
    END
  END request[266]
  PIN request[267]
    DIRECTION INPUT ;
    USE SIGNAL ;
    PORT
      LAYER M3 ;
        RECT  33.768 64.762 33.786 64.8 ;
    END
  END request[267]
  PIN request[268]
    DIRECTION INPUT ;
    USE SIGNAL ;
    PORT
      LAYER M5 ;
        RECT  33.888 64.716 33.912 64.8 ;
    END
  END request[268]
  PIN request[269]
    DIRECTION INPUT ;
    USE SIGNAL ;
    PORT
      LAYER M3 ;
        RECT  34.02 64.762 34.038 64.8 ;
    END
  END request[269]
  PIN request[26]
    DIRECTION INPUT ;
    USE SIGNAL ;
    PORT
      LAYER M5 ;
        RECT  3.456 64.716 3.48 64.8 ;
    END
  END request[26]
  PIN request[270]
    DIRECTION INPUT ;
    USE SIGNAL ;
    PORT
      LAYER M5 ;
        RECT  34.128 64.716 34.152 64.8 ;
    END
  END request[270]
  PIN request[271]
    DIRECTION INPUT ;
    USE SIGNAL ;
    PORT
      LAYER M3 ;
        RECT  34.272 64.762 34.29 64.8 ;
    END
  END request[271]
  PIN request[272]
    DIRECTION INPUT ;
    USE SIGNAL ;
    PORT
      LAYER M5 ;
        RECT  34.416 64.716 34.44 64.8 ;
    END
  END request[272]
  PIN request[273]
    DIRECTION INPUT ;
    USE SIGNAL ;
    PORT
      LAYER M3 ;
        RECT  34.524 64.762 34.542 64.8 ;
    END
  END request[273]
  PIN request[274]
    DIRECTION INPUT ;
    USE SIGNAL ;
    PORT
      LAYER M5 ;
        RECT  34.656 64.716 34.68 64.8 ;
    END
  END request[274]
  PIN request[275]
    DIRECTION INPUT ;
    USE SIGNAL ;
    PORT
      LAYER M3 ;
        RECT  34.776 64.762 34.794 64.8 ;
    END
  END request[275]
  PIN request[276]
    DIRECTION INPUT ;
    USE SIGNAL ;
    PORT
      LAYER M5 ;
        RECT  34.896 64.716 34.92 64.8 ;
    END
  END request[276]
  PIN request[277]
    DIRECTION INPUT ;
    USE SIGNAL ;
    PORT
      LAYER M3 ;
        RECT  35.028 64.762 35.046 64.8 ;
    END
  END request[277]
  PIN request[278]
    DIRECTION INPUT ;
    USE SIGNAL ;
    PORT
      LAYER M5 ;
        RECT  35.136 64.716 35.16 64.8 ;
    END
  END request[278]
  PIN request[279]
    DIRECTION INPUT ;
    USE SIGNAL ;
    PORT
      LAYER M3 ;
        RECT  35.28 64.762 35.298 64.8 ;
    END
  END request[279]
  PIN request[27]
    DIRECTION INPUT ;
    USE SIGNAL ;
    PORT
      LAYER M3 ;
        RECT  3.564 64.762 3.582 64.8 ;
    END
  END request[27]
  PIN request[280]
    DIRECTION INPUT ;
    USE SIGNAL ;
    PORT
      LAYER M5 ;
        RECT  35.424 64.716 35.448 64.8 ;
    END
  END request[280]
  PIN request[281]
    DIRECTION INPUT ;
    USE SIGNAL ;
    PORT
      LAYER M3 ;
        RECT  35.532 64.762 35.55 64.8 ;
    END
  END request[281]
  PIN request[282]
    DIRECTION INPUT ;
    USE SIGNAL ;
    PORT
      LAYER M5 ;
        RECT  35.664 64.716 35.688 64.8 ;
    END
  END request[282]
  PIN request[283]
    DIRECTION INPUT ;
    USE SIGNAL ;
    PORT
      LAYER M3 ;
        RECT  35.784 64.762 35.802 64.8 ;
    END
  END request[283]
  PIN request[284]
    DIRECTION INPUT ;
    USE SIGNAL ;
    PORT
      LAYER M5 ;
        RECT  35.904 64.716 35.928 64.8 ;
    END
  END request[284]
  PIN request[285]
    DIRECTION INPUT ;
    USE SIGNAL ;
    PORT
      LAYER M3 ;
        RECT  36.036 64.762 36.054 64.8 ;
    END
  END request[285]
  PIN request[286]
    DIRECTION INPUT ;
    USE SIGNAL ;
    PORT
      LAYER M5 ;
        RECT  36.144 64.716 36.168 64.8 ;
    END
  END request[286]
  PIN request[287]
    DIRECTION INPUT ;
    USE SIGNAL ;
    PORT
      LAYER M3 ;
        RECT  36.288 64.762 36.306 64.8 ;
    END
  END request[287]
  PIN request[288]
    DIRECTION INPUT ;
    USE SIGNAL ;
    PORT
      LAYER M5 ;
        RECT  36.432 64.716 36.456 64.8 ;
    END
  END request[288]
  PIN request[289]
    DIRECTION INPUT ;
    USE SIGNAL ;
    PORT
      LAYER M3 ;
        RECT  36.54 64.762 36.558 64.8 ;
    END
  END request[289]
  PIN request[28]
    DIRECTION INPUT ;
    USE SIGNAL ;
    PORT
      LAYER M5 ;
        RECT  3.696 64.716 3.72 64.8 ;
    END
  END request[28]
  PIN request[290]
    DIRECTION INPUT ;
    USE SIGNAL ;
    PORT
      LAYER M5 ;
        RECT  36.672 64.716 36.696 64.8 ;
    END
  END request[290]
  PIN request[291]
    DIRECTION INPUT ;
    USE SIGNAL ;
    PORT
      LAYER M3 ;
        RECT  36.792 64.762 36.81 64.8 ;
    END
  END request[291]
  PIN request[292]
    DIRECTION INPUT ;
    USE SIGNAL ;
    PORT
      LAYER M5 ;
        RECT  36.912 64.716 36.936 64.8 ;
    END
  END request[292]
  PIN request[293]
    DIRECTION INPUT ;
    USE SIGNAL ;
    PORT
      LAYER M3 ;
        RECT  37.044 64.762 37.062 64.8 ;
    END
  END request[293]
  PIN request[294]
    DIRECTION INPUT ;
    USE SIGNAL ;
    PORT
      LAYER M5 ;
        RECT  37.152 64.716 37.176 64.8 ;
    END
  END request[294]
  PIN request[295]
    DIRECTION INPUT ;
    USE SIGNAL ;
    PORT
      LAYER M3 ;
        RECT  37.296 64.762 37.314 64.8 ;
    END
  END request[295]
  PIN request[296]
    DIRECTION INPUT ;
    USE SIGNAL ;
    PORT
      LAYER M5 ;
        RECT  37.44 64.716 37.464 64.8 ;
    END
  END request[296]
  PIN request[297]
    DIRECTION INPUT ;
    USE SIGNAL ;
    PORT
      LAYER M3 ;
        RECT  37.548 64.762 37.566 64.8 ;
    END
  END request[297]
  PIN request[298]
    DIRECTION INPUT ;
    USE SIGNAL ;
    PORT
      LAYER M5 ;
        RECT  37.68 64.716 37.704 64.8 ;
    END
  END request[298]
  PIN request[299]
    DIRECTION INPUT ;
    USE SIGNAL ;
    PORT
      LAYER M3 ;
        RECT  37.8 64.762 37.818 64.8 ;
    END
  END request[299]
  PIN request[29]
    DIRECTION INPUT ;
    USE SIGNAL ;
    PORT
      LAYER M3 ;
        RECT  3.816 64.762 3.834 64.8 ;
    END
  END request[29]
  PIN request[2]
    DIRECTION INPUT ;
    USE SIGNAL ;
    PORT
      LAYER M5 ;
        RECT  0.432 64.716 0.456 64.8 ;
    END
  END request[2]
  PIN request[300]
    DIRECTION INPUT ;
    USE SIGNAL ;
    PORT
      LAYER M5 ;
        RECT  37.92 64.716 37.944 64.8 ;
    END
  END request[300]
  PIN request[301]
    DIRECTION INPUT ;
    USE SIGNAL ;
    PORT
      LAYER M3 ;
        RECT  38.052 64.762 38.07 64.8 ;
    END
  END request[301]
  PIN request[302]
    DIRECTION INPUT ;
    USE SIGNAL ;
    PORT
      LAYER M5 ;
        RECT  38.16 64.716 38.184 64.8 ;
    END
  END request[302]
  PIN request[303]
    DIRECTION INPUT ;
    USE SIGNAL ;
    PORT
      LAYER M3 ;
        RECT  38.304 64.762 38.322 64.8 ;
    END
  END request[303]
  PIN request[304]
    DIRECTION INPUT ;
    USE SIGNAL ;
    PORT
      LAYER M5 ;
        RECT  38.448 64.716 38.472 64.8 ;
    END
  END request[304]
  PIN request[305]
    DIRECTION INPUT ;
    USE SIGNAL ;
    PORT
      LAYER M3 ;
        RECT  38.556 64.762 38.574 64.8 ;
    END
  END request[305]
  PIN request[306]
    DIRECTION INPUT ;
    USE SIGNAL ;
    PORT
      LAYER M5 ;
        RECT  38.688 64.716 38.712 64.8 ;
    END
  END request[306]
  PIN request[307]
    DIRECTION INPUT ;
    USE SIGNAL ;
    PORT
      LAYER M3 ;
        RECT  38.808 64.762 38.826 64.8 ;
    END
  END request[307]
  PIN request[308]
    DIRECTION INPUT ;
    USE SIGNAL ;
    PORT
      LAYER M5 ;
        RECT  38.928 64.716 38.952 64.8 ;
    END
  END request[308]
  PIN request[309]
    DIRECTION INPUT ;
    USE SIGNAL ;
    PORT
      LAYER M3 ;
        RECT  39.06 64.762 39.078 64.8 ;
    END
  END request[309]
  PIN request[30]
    DIRECTION INPUT ;
    USE SIGNAL ;
    PORT
      LAYER M5 ;
        RECT  3.936 64.716 3.96 64.8 ;
    END
  END request[30]
  PIN request[310]
    DIRECTION INPUT ;
    USE SIGNAL ;
    PORT
      LAYER M5 ;
        RECT  39.168 64.716 39.192 64.8 ;
    END
  END request[310]
  PIN request[311]
    DIRECTION INPUT ;
    USE SIGNAL ;
    PORT
      LAYER M3 ;
        RECT  39.312 64.762 39.33 64.8 ;
    END
  END request[311]
  PIN request[312]
    DIRECTION INPUT ;
    USE SIGNAL ;
    PORT
      LAYER M5 ;
        RECT  39.456 64.716 39.48 64.8 ;
    END
  END request[312]
  PIN request[313]
    DIRECTION INPUT ;
    USE SIGNAL ;
    PORT
      LAYER M3 ;
        RECT  39.564 64.762 39.582 64.8 ;
    END
  END request[313]
  PIN request[314]
    DIRECTION INPUT ;
    USE SIGNAL ;
    PORT
      LAYER M5 ;
        RECT  39.696 64.716 39.72 64.8 ;
    END
  END request[314]
  PIN request[315]
    DIRECTION INPUT ;
    USE SIGNAL ;
    PORT
      LAYER M3 ;
        RECT  39.816 64.762 39.834 64.8 ;
    END
  END request[315]
  PIN request[316]
    DIRECTION INPUT ;
    USE SIGNAL ;
    PORT
      LAYER M5 ;
        RECT  39.936 64.716 39.96 64.8 ;
    END
  END request[316]
  PIN request[317]
    DIRECTION INPUT ;
    USE SIGNAL ;
    PORT
      LAYER M3 ;
        RECT  40.068 64.762 40.086 64.8 ;
    END
  END request[317]
  PIN request[318]
    DIRECTION INPUT ;
    USE SIGNAL ;
    PORT
      LAYER M5 ;
        RECT  40.176 64.716 40.2 64.8 ;
    END
  END request[318]
  PIN request[319]
    DIRECTION INPUT ;
    USE SIGNAL ;
    PORT
      LAYER M3 ;
        RECT  40.32 64.762 40.338 64.8 ;
    END
  END request[319]
  PIN request[31]
    DIRECTION INPUT ;
    USE SIGNAL ;
    PORT
      LAYER M3 ;
        RECT  4.068 64.762 4.086 64.8 ;
    END
  END request[31]
  PIN request[320]
    DIRECTION INPUT ;
    USE SIGNAL ;
    PORT
      LAYER M5 ;
        RECT  40.464 64.716 40.488 64.8 ;
    END
  END request[320]
  PIN request[321]
    DIRECTION INPUT ;
    USE SIGNAL ;
    PORT
      LAYER M3 ;
        RECT  40.572 64.762 40.59 64.8 ;
    END
  END request[321]
  PIN request[322]
    DIRECTION INPUT ;
    USE SIGNAL ;
    PORT
      LAYER M5 ;
        RECT  40.704 64.716 40.728 64.8 ;
    END
  END request[322]
  PIN request[323]
    DIRECTION INPUT ;
    USE SIGNAL ;
    PORT
      LAYER M3 ;
        RECT  40.824 64.762 40.842 64.8 ;
    END
  END request[323]
  PIN request[324]
    DIRECTION INPUT ;
    USE SIGNAL ;
    PORT
      LAYER M5 ;
        RECT  40.944 64.716 40.968 64.8 ;
    END
  END request[324]
  PIN request[325]
    DIRECTION INPUT ;
    USE SIGNAL ;
    PORT
      LAYER M3 ;
        RECT  41.076 64.762 41.094 64.8 ;
    END
  END request[325]
  PIN request[326]
    DIRECTION INPUT ;
    USE SIGNAL ;
    PORT
      LAYER M5 ;
        RECT  41.184 64.716 41.208 64.8 ;
    END
  END request[326]
  PIN request[327]
    DIRECTION INPUT ;
    USE SIGNAL ;
    PORT
      LAYER M3 ;
        RECT  41.328 64.762 41.346 64.8 ;
    END
  END request[327]
  PIN request[328]
    DIRECTION INPUT ;
    USE SIGNAL ;
    PORT
      LAYER M5 ;
        RECT  41.424 64.716 41.448 64.8 ;
    END
  END request[328]
  PIN request[329]
    DIRECTION INPUT ;
    USE SIGNAL ;
    PORT
      LAYER M3 ;
        RECT  41.58 64.762 41.598 64.8 ;
    END
  END request[329]
  PIN request[32]
    DIRECTION INPUT ;
    USE SIGNAL ;
    PORT
      LAYER M5 ;
        RECT  4.224 64.716 4.248 64.8 ;
    END
  END request[32]
  PIN request[330]
    DIRECTION INPUT ;
    USE SIGNAL ;
    PORT
      LAYER M5 ;
        RECT  41.712 64.716 41.736 64.8 ;
    END
  END request[330]
  PIN request[331]
    DIRECTION INPUT ;
    USE SIGNAL ;
    PORT
      LAYER M3 ;
        RECT  41.832 64.762 41.85 64.8 ;
    END
  END request[331]
  PIN request[332]
    DIRECTION INPUT ;
    USE SIGNAL ;
    PORT
      LAYER M5 ;
        RECT  41.952 64.716 41.976 64.8 ;
    END
  END request[332]
  PIN request[333]
    DIRECTION INPUT ;
    USE SIGNAL ;
    PORT
      LAYER M3 ;
        RECT  42.084 64.762 42.102 64.8 ;
    END
  END request[333]
  PIN request[334]
    DIRECTION INPUT ;
    USE SIGNAL ;
    PORT
      LAYER M5 ;
        RECT  42.192 64.716 42.216 64.8 ;
    END
  END request[334]
  PIN request[335]
    DIRECTION INPUT ;
    USE SIGNAL ;
    PORT
      LAYER M3 ;
        RECT  42.336 64.762 42.354 64.8 ;
    END
  END request[335]
  PIN request[336]
    DIRECTION INPUT ;
    USE SIGNAL ;
    PORT
      LAYER M5 ;
        RECT  42.432 64.716 42.456 64.8 ;
    END
  END request[336]
  PIN request[337]
    DIRECTION INPUT ;
    USE SIGNAL ;
    PORT
      LAYER M3 ;
        RECT  42.588 64.762 42.606 64.8 ;
    END
  END request[337]
  PIN request[338]
    DIRECTION INPUT ;
    USE SIGNAL ;
    PORT
      LAYER M5 ;
        RECT  42.72 64.716 42.744 64.8 ;
    END
  END request[338]
  PIN request[339]
    DIRECTION INPUT ;
    USE SIGNAL ;
    PORT
      LAYER M3 ;
        RECT  42.84 64.762 42.858 64.8 ;
    END
  END request[339]
  PIN request[33]
    DIRECTION INPUT ;
    USE SIGNAL ;
    PORT
      LAYER M3 ;
        RECT  4.32 64.762 4.338 64.8 ;
    END
  END request[33]
  PIN request[340]
    DIRECTION INPUT ;
    USE SIGNAL ;
    PORT
      LAYER M5 ;
        RECT  42.96 64.716 42.984 64.8 ;
    END
  END request[340]
  PIN request[341]
    DIRECTION INPUT ;
    USE SIGNAL ;
    PORT
      LAYER M3 ;
        RECT  43.092 64.762 43.11 64.8 ;
    END
  END request[341]
  PIN request[342]
    DIRECTION INPUT ;
    USE SIGNAL ;
    PORT
      LAYER M5 ;
        RECT  43.2 64.716 43.224 64.8 ;
    END
  END request[342]
  PIN request[343]
    DIRECTION INPUT ;
    USE SIGNAL ;
    PORT
      LAYER M3 ;
        RECT  43.344 64.762 43.362 64.8 ;
    END
  END request[343]
  PIN request[344]
    DIRECTION INPUT ;
    USE SIGNAL ;
    PORT
      LAYER M5 ;
        RECT  43.44 64.716 43.464 64.8 ;
    END
  END request[344]
  PIN request[345]
    DIRECTION INPUT ;
    USE SIGNAL ;
    PORT
      LAYER M3 ;
        RECT  43.596 64.762 43.614 64.8 ;
    END
  END request[345]
  PIN request[346]
    DIRECTION INPUT ;
    USE SIGNAL ;
    PORT
      LAYER M5 ;
        RECT  43.728 64.716 43.752 64.8 ;
    END
  END request[346]
  PIN request[347]
    DIRECTION INPUT ;
    USE SIGNAL ;
    PORT
      LAYER M3 ;
        RECT  43.848 64.762 43.866 64.8 ;
    END
  END request[347]
  PIN request[348]
    DIRECTION INPUT ;
    USE SIGNAL ;
    PORT
      LAYER M5 ;
        RECT  43.968 64.716 43.992 64.8 ;
    END
  END request[348]
  PIN request[349]
    DIRECTION INPUT ;
    USE SIGNAL ;
    PORT
      LAYER M3 ;
        RECT  44.1 64.762 44.118 64.8 ;
    END
  END request[349]
  PIN request[34]
    DIRECTION INPUT ;
    USE SIGNAL ;
    PORT
      LAYER M5 ;
        RECT  4.464 64.716 4.488 64.8 ;
    END
  END request[34]
  PIN request[350]
    DIRECTION INPUT ;
    USE SIGNAL ;
    PORT
      LAYER M5 ;
        RECT  44.208 64.716 44.232 64.8 ;
    END
  END request[350]
  PIN request[351]
    DIRECTION INPUT ;
    USE SIGNAL ;
    PORT
      LAYER M3 ;
        RECT  44.352 64.762 44.37 64.8 ;
    END
  END request[351]
  PIN request[352]
    DIRECTION INPUT ;
    USE SIGNAL ;
    PORT
      LAYER M5 ;
        RECT  44.448 64.716 44.472 64.8 ;
    END
  END request[352]
  PIN request[353]
    DIRECTION INPUT ;
    USE SIGNAL ;
    PORT
      LAYER M3 ;
        RECT  44.604 64.762 44.622 64.8 ;
    END
  END request[353]
  PIN request[354]
    DIRECTION INPUT ;
    USE SIGNAL ;
    PORT
      LAYER M5 ;
        RECT  44.736 64.716 44.76 64.8 ;
    END
  END request[354]
  PIN request[355]
    DIRECTION INPUT ;
    USE SIGNAL ;
    PORT
      LAYER M3 ;
        RECT  44.856 64.762 44.874 64.8 ;
    END
  END request[355]
  PIN request[356]
    DIRECTION INPUT ;
    USE SIGNAL ;
    PORT
      LAYER M5 ;
        RECT  44.976 64.716 45 64.8 ;
    END
  END request[356]
  PIN request[357]
    DIRECTION INPUT ;
    USE SIGNAL ;
    PORT
      LAYER M3 ;
        RECT  45.108 64.762 45.126 64.8 ;
    END
  END request[357]
  PIN request[358]
    DIRECTION INPUT ;
    USE SIGNAL ;
    PORT
      LAYER M5 ;
        RECT  45.216 64.716 45.24 64.8 ;
    END
  END request[358]
  PIN request[359]
    DIRECTION INPUT ;
    USE SIGNAL ;
    PORT
      LAYER M3 ;
        RECT  45.36 64.762 45.378 64.8 ;
    END
  END request[359]
  PIN request[35]
    DIRECTION INPUT ;
    USE SIGNAL ;
    PORT
      LAYER M3 ;
        RECT  4.572 64.762 4.59 64.8 ;
    END
  END request[35]
  PIN request[360]
    DIRECTION INPUT ;
    USE SIGNAL ;
    PORT
      LAYER M5 ;
        RECT  45.456 64.716 45.48 64.8 ;
    END
  END request[360]
  PIN request[361]
    DIRECTION INPUT ;
    USE SIGNAL ;
    PORT
      LAYER M3 ;
        RECT  45.612 64.762 45.63 64.8 ;
    END
  END request[361]
  PIN request[362]
    DIRECTION INPUT ;
    USE SIGNAL ;
    PORT
      LAYER M5 ;
        RECT  45.744 64.716 45.768 64.8 ;
    END
  END request[362]
  PIN request[363]
    DIRECTION INPUT ;
    USE SIGNAL ;
    PORT
      LAYER M3 ;
        RECT  45.864 64.762 45.882 64.8 ;
    END
  END request[363]
  PIN request[364]
    DIRECTION INPUT ;
    USE SIGNAL ;
    PORT
      LAYER M5 ;
        RECT  45.984 64.716 46.008 64.8 ;
    END
  END request[364]
  PIN request[365]
    DIRECTION INPUT ;
    USE SIGNAL ;
    PORT
      LAYER M3 ;
        RECT  46.116 64.762 46.134 64.8 ;
    END
  END request[365]
  PIN request[366]
    DIRECTION INPUT ;
    USE SIGNAL ;
    PORT
      LAYER M5 ;
        RECT  46.224 64.716 46.248 64.8 ;
    END
  END request[366]
  PIN request[367]
    DIRECTION INPUT ;
    USE SIGNAL ;
    PORT
      LAYER M3 ;
        RECT  46.368 64.762 46.386 64.8 ;
    END
  END request[367]
  PIN request[368]
    DIRECTION INPUT ;
    USE SIGNAL ;
    PORT
      LAYER M5 ;
        RECT  46.464 64.716 46.488 64.8 ;
    END
  END request[368]
  PIN request[369]
    DIRECTION INPUT ;
    USE SIGNAL ;
    PORT
      LAYER M3 ;
        RECT  46.62 64.762 46.638 64.8 ;
    END
  END request[369]
  PIN request[36]
    DIRECTION INPUT ;
    USE SIGNAL ;
    PORT
      LAYER M5 ;
        RECT  4.704 64.716 4.728 64.8 ;
    END
  END request[36]
  PIN request[370]
    DIRECTION INPUT ;
    USE SIGNAL ;
    PORT
      LAYER M5 ;
        RECT  46.752 64.716 46.776 64.8 ;
    END
  END request[370]
  PIN request[371]
    DIRECTION INPUT ;
    USE SIGNAL ;
    PORT
      LAYER M3 ;
        RECT  46.872 64.762 46.89 64.8 ;
    END
  END request[371]
  PIN request[372]
    DIRECTION INPUT ;
    USE SIGNAL ;
    PORT
      LAYER M5 ;
        RECT  46.992 64.716 47.016 64.8 ;
    END
  END request[372]
  PIN request[373]
    DIRECTION INPUT ;
    USE SIGNAL ;
    PORT
      LAYER M3 ;
        RECT  47.124 64.762 47.142 64.8 ;
    END
  END request[373]
  PIN request[374]
    DIRECTION INPUT ;
    USE SIGNAL ;
    PORT
      LAYER M5 ;
        RECT  47.232 64.716 47.256 64.8 ;
    END
  END request[374]
  PIN request[375]
    DIRECTION INPUT ;
    USE SIGNAL ;
    PORT
      LAYER M3 ;
        RECT  47.376 64.762 47.394 64.8 ;
    END
  END request[375]
  PIN request[376]
    DIRECTION INPUT ;
    USE SIGNAL ;
    PORT
      LAYER M5 ;
        RECT  47.472 64.716 47.496 64.8 ;
    END
  END request[376]
  PIN request[377]
    DIRECTION INPUT ;
    USE SIGNAL ;
    PORT
      LAYER M3 ;
        RECT  47.628 64.762 47.646 64.8 ;
    END
  END request[377]
  PIN request[378]
    DIRECTION INPUT ;
    USE SIGNAL ;
    PORT
      LAYER M5 ;
        RECT  47.76 64.716 47.784 64.8 ;
    END
  END request[378]
  PIN request[379]
    DIRECTION INPUT ;
    USE SIGNAL ;
    PORT
      LAYER M3 ;
        RECT  47.88 64.762 47.898 64.8 ;
    END
  END request[379]
  PIN request[37]
    DIRECTION INPUT ;
    USE SIGNAL ;
    PORT
      LAYER M3 ;
        RECT  4.824 64.762 4.842 64.8 ;
    END
  END request[37]
  PIN request[380]
    DIRECTION INPUT ;
    USE SIGNAL ;
    PORT
      LAYER M5 ;
        RECT  48 64.716 48.024 64.8 ;
    END
  END request[380]
  PIN request[381]
    DIRECTION INPUT ;
    USE SIGNAL ;
    PORT
      LAYER M3 ;
        RECT  48.132 64.762 48.15 64.8 ;
    END
  END request[381]
  PIN request[382]
    DIRECTION INPUT ;
    USE SIGNAL ;
    PORT
      LAYER M5 ;
        RECT  48.24 64.716 48.264 64.8 ;
    END
  END request[382]
  PIN request[383]
    DIRECTION INPUT ;
    USE SIGNAL ;
    PORT
      LAYER M3 ;
        RECT  48.384 64.762 48.402 64.8 ;
    END
  END request[383]
  PIN request[384]
    DIRECTION INPUT ;
    USE SIGNAL ;
    PORT
      LAYER M5 ;
        RECT  48.48 64.716 48.504 64.8 ;
    END
  END request[384]
  PIN request[385]
    DIRECTION INPUT ;
    USE SIGNAL ;
    PORT
      LAYER M3 ;
        RECT  48.636 64.762 48.654 64.8 ;
    END
  END request[385]
  PIN request[386]
    DIRECTION INPUT ;
    USE SIGNAL ;
    PORT
      LAYER M5 ;
        RECT  48.768 64.716 48.792 64.8 ;
    END
  END request[386]
  PIN request[387]
    DIRECTION INPUT ;
    USE SIGNAL ;
    PORT
      LAYER M3 ;
        RECT  48.888 64.762 48.906 64.8 ;
    END
  END request[387]
  PIN request[388]
    DIRECTION INPUT ;
    USE SIGNAL ;
    PORT
      LAYER M5 ;
        RECT  49.008 64.716 49.032 64.8 ;
    END
  END request[388]
  PIN request[389]
    DIRECTION INPUT ;
    USE SIGNAL ;
    PORT
      LAYER M3 ;
        RECT  49.14 64.762 49.158 64.8 ;
    END
  END request[389]
  PIN request[38]
    DIRECTION INPUT ;
    USE SIGNAL ;
    PORT
      LAYER M5 ;
        RECT  4.944 64.716 4.968 64.8 ;
    END
  END request[38]
  PIN request[390]
    DIRECTION INPUT ;
    USE SIGNAL ;
    PORT
      LAYER M5 ;
        RECT  49.248 64.716 49.272 64.8 ;
    END
  END request[390]
  PIN request[391]
    DIRECTION INPUT ;
    USE SIGNAL ;
    PORT
      LAYER M3 ;
        RECT  49.392 64.762 49.41 64.8 ;
    END
  END request[391]
  PIN request[392]
    DIRECTION INPUT ;
    USE SIGNAL ;
    PORT
      LAYER M5 ;
        RECT  49.488 64.716 49.512 64.8 ;
    END
  END request[392]
  PIN request[393]
    DIRECTION INPUT ;
    USE SIGNAL ;
    PORT
      LAYER M3 ;
        RECT  49.644 64.762 49.662 64.8 ;
    END
  END request[393]
  PIN request[394]
    DIRECTION INPUT ;
    USE SIGNAL ;
    PORT
      LAYER M5 ;
        RECT  49.776 64.716 49.8 64.8 ;
    END
  END request[394]
  PIN request[395]
    DIRECTION INPUT ;
    USE SIGNAL ;
    PORT
      LAYER M3 ;
        RECT  49.896 64.762 49.914 64.8 ;
    END
  END request[395]
  PIN request[396]
    DIRECTION INPUT ;
    USE SIGNAL ;
    PORT
      LAYER M5 ;
        RECT  50.016 64.716 50.04 64.8 ;
    END
  END request[396]
  PIN request[397]
    DIRECTION INPUT ;
    USE SIGNAL ;
    PORT
      LAYER M3 ;
        RECT  50.148 64.762 50.166 64.8 ;
    END
  END request[397]
  PIN request[398]
    DIRECTION INPUT ;
    USE SIGNAL ;
    PORT
      LAYER M5 ;
        RECT  50.256 64.716 50.28 64.8 ;
    END
  END request[398]
  PIN request[399]
    DIRECTION INPUT ;
    USE SIGNAL ;
    PORT
      LAYER M3 ;
        RECT  50.4 64.762 50.418 64.8 ;
    END
  END request[399]
  PIN request[39]
    DIRECTION INPUT ;
    USE SIGNAL ;
    PORT
      LAYER M3 ;
        RECT  5.076 64.762 5.094 64.8 ;
    END
  END request[39]
  PIN request[3]
    DIRECTION INPUT ;
    USE SIGNAL ;
    PORT
      LAYER M3 ;
        RECT  0.54 64.762 0.558 64.8 ;
    END
  END request[3]
  PIN request[400]
    DIRECTION INPUT ;
    USE SIGNAL ;
    PORT
      LAYER M5 ;
        RECT  50.496 64.716 50.52 64.8 ;
    END
  END request[400]
  PIN request[401]
    DIRECTION INPUT ;
    USE SIGNAL ;
    PORT
      LAYER M3 ;
        RECT  50.652 64.762 50.67 64.8 ;
    END
  END request[401]
  PIN request[402]
    DIRECTION INPUT ;
    USE SIGNAL ;
    PORT
      LAYER M5 ;
        RECT  50.736 64.716 50.76 64.8 ;
    END
  END request[402]
  PIN request[403]
    DIRECTION INPUT ;
    USE SIGNAL ;
    PORT
      LAYER M3 ;
        RECT  50.904 64.762 50.922 64.8 ;
    END
  END request[403]
  PIN request[404]
    DIRECTION INPUT ;
    USE SIGNAL ;
    PORT
      LAYER M5 ;
        RECT  51.024 64.716 51.048 64.8 ;
    END
  END request[404]
  PIN request[405]
    DIRECTION INPUT ;
    USE SIGNAL ;
    PORT
      LAYER M3 ;
        RECT  51.156 64.762 51.174 64.8 ;
    END
  END request[405]
  PIN request[406]
    DIRECTION INPUT ;
    USE SIGNAL ;
    PORT
      LAYER M5 ;
        RECT  51.264 64.716 51.288 64.8 ;
    END
  END request[406]
  PIN request[407]
    DIRECTION INPUT ;
    USE SIGNAL ;
    PORT
      LAYER M3 ;
        RECT  51.408 64.762 51.426 64.8 ;
    END
  END request[407]
  PIN request[408]
    DIRECTION INPUT ;
    USE SIGNAL ;
    PORT
      LAYER M5 ;
        RECT  51.504 64.716 51.528 64.8 ;
    END
  END request[408]
  PIN request[409]
    DIRECTION INPUT ;
    USE SIGNAL ;
    PORT
      LAYER M3 ;
        RECT  51.66 64.762 51.678 64.8 ;
    END
  END request[409]
  PIN request[40]
    DIRECTION INPUT ;
    USE SIGNAL ;
    PORT
      LAYER M5 ;
        RECT  5.232 64.716 5.256 64.8 ;
    END
  END request[40]
  PIN request[410]
    DIRECTION INPUT ;
    USE SIGNAL ;
    PORT
      LAYER M5 ;
        RECT  51.744 64.716 51.768 64.8 ;
    END
  END request[410]
  PIN request[411]
    DIRECTION INPUT ;
    USE SIGNAL ;
    PORT
      LAYER M3 ;
        RECT  51.912 64.762 51.93 64.8 ;
    END
  END request[411]
  PIN request[412]
    DIRECTION INPUT ;
    USE SIGNAL ;
    PORT
      LAYER M5 ;
        RECT  52.032 64.716 52.056 64.8 ;
    END
  END request[412]
  PIN request[413]
    DIRECTION INPUT ;
    USE SIGNAL ;
    PORT
      LAYER M3 ;
        RECT  52.164 64.762 52.182 64.8 ;
    END
  END request[413]
  PIN request[414]
    DIRECTION INPUT ;
    USE SIGNAL ;
    PORT
      LAYER M5 ;
        RECT  52.272 64.716 52.296 64.8 ;
    END
  END request[414]
  PIN request[415]
    DIRECTION INPUT ;
    USE SIGNAL ;
    PORT
      LAYER M3 ;
        RECT  52.38 64.762 52.398 64.8 ;
    END
  END request[415]
  PIN request[416]
    DIRECTION INPUT ;
    USE SIGNAL ;
    PORT
      LAYER M5 ;
        RECT  52.512 64.716 52.536 64.8 ;
    END
  END request[416]
  PIN request[417]
    DIRECTION INPUT ;
    USE SIGNAL ;
    PORT
      LAYER M3 ;
        RECT  52.632 64.762 52.65 64.8 ;
    END
  END request[417]
  PIN request[418]
    DIRECTION INPUT ;
    USE SIGNAL ;
    PORT
      LAYER M5 ;
        RECT  52.752 64.716 52.776 64.8 ;
    END
  END request[418]
  PIN request[419]
    DIRECTION INPUT ;
    USE SIGNAL ;
    PORT
      LAYER M3 ;
        RECT  52.884 64.762 52.902 64.8 ;
    END
  END request[419]
  PIN request[41]
    DIRECTION INPUT ;
    USE SIGNAL ;
    PORT
      LAYER M3 ;
        RECT  5.328 64.762 5.346 64.8 ;
    END
  END request[41]
  PIN request[420]
    DIRECTION INPUT ;
    USE SIGNAL ;
    PORT
      LAYER M5 ;
        RECT  53.04 64.716 53.064 64.8 ;
    END
  END request[420]
  PIN request[421]
    DIRECTION INPUT ;
    USE SIGNAL ;
    PORT
      LAYER M3 ;
        RECT  53.136 64.762 53.154 64.8 ;
    END
  END request[421]
  PIN request[422]
    DIRECTION INPUT ;
    USE SIGNAL ;
    PORT
      LAYER M5 ;
        RECT  53.28 64.716 53.304 64.8 ;
    END
  END request[422]
  PIN request[423]
    DIRECTION INPUT ;
    USE SIGNAL ;
    PORT
      LAYER M3 ;
        RECT  53.388 64.762 53.406 64.8 ;
    END
  END request[423]
  PIN request[424]
    DIRECTION INPUT ;
    USE SIGNAL ;
    PORT
      LAYER M5 ;
        RECT  53.52 64.716 53.544 64.8 ;
    END
  END request[424]
  PIN request[425]
    DIRECTION INPUT ;
    USE SIGNAL ;
    PORT
      LAYER M3 ;
        RECT  53.64 64.762 53.658 64.8 ;
    END
  END request[425]
  PIN request[426]
    DIRECTION INPUT ;
    USE SIGNAL ;
    PORT
      LAYER M5 ;
        RECT  53.76 64.716 53.784 64.8 ;
    END
  END request[426]
  PIN request[427]
    DIRECTION INPUT ;
    USE SIGNAL ;
    PORT
      LAYER M3 ;
        RECT  53.892 64.762 53.91 64.8 ;
    END
  END request[427]
  PIN request[428]
    DIRECTION INPUT ;
    USE SIGNAL ;
    PORT
      LAYER M5 ;
        RECT  54.048 64.716 54.072 64.8 ;
    END
  END request[428]
  PIN request[429]
    DIRECTION INPUT ;
    USE SIGNAL ;
    PORT
      LAYER M3 ;
        RECT  54.144 64.762 54.162 64.8 ;
    END
  END request[429]
  PIN request[42]
    DIRECTION INPUT ;
    USE SIGNAL ;
    PORT
      LAYER M5 ;
        RECT  5.472 64.716 5.496 64.8 ;
    END
  END request[42]
  PIN request[430]
    DIRECTION INPUT ;
    USE SIGNAL ;
    PORT
      LAYER M5 ;
        RECT  54.288 64.716 54.312 64.8 ;
    END
  END request[430]
  PIN request[431]
    DIRECTION INPUT ;
    USE SIGNAL ;
    PORT
      LAYER M3 ;
        RECT  54.396 64.762 54.414 64.8 ;
    END
  END request[431]
  PIN request[432]
    DIRECTION INPUT ;
    USE SIGNAL ;
    PORT
      LAYER M5 ;
        RECT  54.528 64.716 54.552 64.8 ;
    END
  END request[432]
  PIN request[433]
    DIRECTION INPUT ;
    USE SIGNAL ;
    PORT
      LAYER M3 ;
        RECT  54.648 64.762 54.666 64.8 ;
    END
  END request[433]
  PIN request[434]
    DIRECTION INPUT ;
    USE SIGNAL ;
    PORT
      LAYER M5 ;
        RECT  54.768 64.716 54.792 64.8 ;
    END
  END request[434]
  PIN request[435]
    DIRECTION INPUT ;
    USE SIGNAL ;
    PORT
      LAYER M3 ;
        RECT  54.9 64.762 54.918 64.8 ;
    END
  END request[435]
  PIN request[436]
    DIRECTION INPUT ;
    USE SIGNAL ;
    PORT
      LAYER M5 ;
        RECT  55.056 64.716 55.08 64.8 ;
    END
  END request[436]
  PIN request[437]
    DIRECTION INPUT ;
    USE SIGNAL ;
    PORT
      LAYER M3 ;
        RECT  55.152 64.762 55.17 64.8 ;
    END
  END request[437]
  PIN request[438]
    DIRECTION INPUT ;
    USE SIGNAL ;
    PORT
      LAYER M5 ;
        RECT  55.296 64.716 55.32 64.8 ;
    END
  END request[438]
  PIN request[439]
    DIRECTION INPUT ;
    USE SIGNAL ;
    PORT
      LAYER M3 ;
        RECT  55.404 64.762 55.422 64.8 ;
    END
  END request[439]
  PIN request[43]
    DIRECTION INPUT ;
    USE SIGNAL ;
    PORT
      LAYER M3 ;
        RECT  5.58 64.762 5.598 64.8 ;
    END
  END request[43]
  PIN request[440]
    DIRECTION INPUT ;
    USE SIGNAL ;
    PORT
      LAYER M5 ;
        RECT  55.536 64.716 55.56 64.8 ;
    END
  END request[440]
  PIN request[441]
    DIRECTION INPUT ;
    USE SIGNAL ;
    PORT
      LAYER M3 ;
        RECT  55.656 64.762 55.674 64.8 ;
    END
  END request[441]
  PIN request[442]
    DIRECTION INPUT ;
    USE SIGNAL ;
    PORT
      LAYER M5 ;
        RECT  55.776 64.716 55.8 64.8 ;
    END
  END request[442]
  PIN request[443]
    DIRECTION INPUT ;
    USE SIGNAL ;
    PORT
      LAYER M3 ;
        RECT  55.908 64.762 55.926 64.8 ;
    END
  END request[443]
  PIN request[444]
    DIRECTION INPUT ;
    USE SIGNAL ;
    PORT
      LAYER M5 ;
        RECT  56.064 64.716 56.088 64.8 ;
    END
  END request[444]
  PIN request[445]
    DIRECTION INPUT ;
    USE SIGNAL ;
    PORT
      LAYER M3 ;
        RECT  56.16 64.762 56.178 64.8 ;
    END
  END request[445]
  PIN request[446]
    DIRECTION INPUT ;
    USE SIGNAL ;
    PORT
      LAYER M5 ;
        RECT  56.304 64.716 56.328 64.8 ;
    END
  END request[446]
  PIN request[447]
    DIRECTION INPUT ;
    USE SIGNAL ;
    PORT
      LAYER M3 ;
        RECT  56.412 64.762 56.43 64.8 ;
    END
  END request[447]
  PIN request[448]
    DIRECTION INPUT ;
    USE SIGNAL ;
    PORT
      LAYER M5 ;
        RECT  56.544 64.716 56.568 64.8 ;
    END
  END request[448]
  PIN request[449]
    DIRECTION INPUT ;
    USE SIGNAL ;
    PORT
      LAYER M3 ;
        RECT  56.664 64.762 56.682 64.8 ;
    END
  END request[449]
  PIN request[44]
    DIRECTION INPUT ;
    USE SIGNAL ;
    PORT
      LAYER M5 ;
        RECT  5.712 64.716 5.736 64.8 ;
    END
  END request[44]
  PIN request[450]
    DIRECTION INPUT ;
    USE SIGNAL ;
    PORT
      LAYER M5 ;
        RECT  56.784 64.716 56.808 64.8 ;
    END
  END request[450]
  PIN request[451]
    DIRECTION INPUT ;
    USE SIGNAL ;
    PORT
      LAYER M3 ;
        RECT  56.916 64.762 56.934 64.8 ;
    END
  END request[451]
  PIN request[452]
    DIRECTION INPUT ;
    USE SIGNAL ;
    PORT
      LAYER M5 ;
        RECT  57.072 64.716 57.096 64.8 ;
    END
  END request[452]
  PIN request[453]
    DIRECTION INPUT ;
    USE SIGNAL ;
    PORT
      LAYER M3 ;
        RECT  57.168 64.762 57.186 64.8 ;
    END
  END request[453]
  PIN request[454]
    DIRECTION INPUT ;
    USE SIGNAL ;
    PORT
      LAYER M5 ;
        RECT  57.312 64.716 57.336 64.8 ;
    END
  END request[454]
  PIN request[455]
    DIRECTION INPUT ;
    USE SIGNAL ;
    PORT
      LAYER M3 ;
        RECT  57.42 64.762 57.438 64.8 ;
    END
  END request[455]
  PIN request[456]
    DIRECTION INPUT ;
    USE SIGNAL ;
    PORT
      LAYER M5 ;
        RECT  57.552 64.716 57.576 64.8 ;
    END
  END request[456]
  PIN request[457]
    DIRECTION INPUT ;
    USE SIGNAL ;
    PORT
      LAYER M3 ;
        RECT  57.672 64.762 57.69 64.8 ;
    END
  END request[457]
  PIN request[458]
    DIRECTION INPUT ;
    USE SIGNAL ;
    PORT
      LAYER M5 ;
        RECT  57.792 64.716 57.816 64.8 ;
    END
  END request[458]
  PIN request[459]
    DIRECTION INPUT ;
    USE SIGNAL ;
    PORT
      LAYER M3 ;
        RECT  57.924 64.762 57.942 64.8 ;
    END
  END request[459]
  PIN request[45]
    DIRECTION INPUT ;
    USE SIGNAL ;
    PORT
      LAYER M3 ;
        RECT  5.832 64.762 5.85 64.8 ;
    END
  END request[45]
  PIN request[460]
    DIRECTION INPUT ;
    USE SIGNAL ;
    PORT
      LAYER M5 ;
        RECT  58.08 64.716 58.104 64.8 ;
    END
  END request[460]
  PIN request[461]
    DIRECTION INPUT ;
    USE SIGNAL ;
    PORT
      LAYER M3 ;
        RECT  58.176 64.762 58.194 64.8 ;
    END
  END request[461]
  PIN request[462]
    DIRECTION INPUT ;
    USE SIGNAL ;
    PORT
      LAYER M5 ;
        RECT  58.32 64.716 58.344 64.8 ;
    END
  END request[462]
  PIN request[463]
    DIRECTION INPUT ;
    USE SIGNAL ;
    PORT
      LAYER M3 ;
        RECT  58.428 64.762 58.446 64.8 ;
    END
  END request[463]
  PIN request[464]
    DIRECTION INPUT ;
    USE SIGNAL ;
    PORT
      LAYER M5 ;
        RECT  58.56 64.716 58.584 64.8 ;
    END
  END request[464]
  PIN request[465]
    DIRECTION INPUT ;
    USE SIGNAL ;
    PORT
      LAYER M3 ;
        RECT  58.68 64.762 58.698 64.8 ;
    END
  END request[465]
  PIN request[466]
    DIRECTION INPUT ;
    USE SIGNAL ;
    PORT
      LAYER M5 ;
        RECT  58.8 64.716 58.824 64.8 ;
    END
  END request[466]
  PIN request[467]
    DIRECTION INPUT ;
    USE SIGNAL ;
    PORT
      LAYER M3 ;
        RECT  58.932 64.762 58.95 64.8 ;
    END
  END request[467]
  PIN request[468]
    DIRECTION INPUT ;
    USE SIGNAL ;
    PORT
      LAYER M5 ;
        RECT  59.04 64.716 59.064 64.8 ;
    END
  END request[468]
  PIN request[469]
    DIRECTION INPUT ;
    USE SIGNAL ;
    PORT
      LAYER M3 ;
        RECT  59.184 64.762 59.202 64.8 ;
    END
  END request[469]
  PIN request[46]
    DIRECTION INPUT ;
    USE SIGNAL ;
    PORT
      LAYER M5 ;
        RECT  5.952 64.716 5.976 64.8 ;
    END
  END request[46]
  PIN request[470]
    DIRECTION INPUT ;
    USE SIGNAL ;
    PORT
      LAYER M5 ;
        RECT  59.328 64.716 59.352 64.8 ;
    END
  END request[470]
  PIN request[471]
    DIRECTION INPUT ;
    USE SIGNAL ;
    PORT
      LAYER M3 ;
        RECT  59.436 64.762 59.454 64.8 ;
    END
  END request[471]
  PIN request[472]
    DIRECTION INPUT ;
    USE SIGNAL ;
    PORT
      LAYER M5 ;
        RECT  59.568 64.716 59.592 64.8 ;
    END
  END request[472]
  PIN request[473]
    DIRECTION INPUT ;
    USE SIGNAL ;
    PORT
      LAYER M3 ;
        RECT  59.688 64.762 59.706 64.8 ;
    END
  END request[473]
  PIN request[474]
    DIRECTION INPUT ;
    USE SIGNAL ;
    PORT
      LAYER M5 ;
        RECT  59.808 64.716 59.832 64.8 ;
    END
  END request[474]
  PIN request[475]
    DIRECTION INPUT ;
    USE SIGNAL ;
    PORT
      LAYER M3 ;
        RECT  59.94 64.762 59.958 64.8 ;
    END
  END request[475]
  PIN request[476]
    DIRECTION INPUT ;
    USE SIGNAL ;
    PORT
      LAYER M5 ;
        RECT  60.048 64.716 60.072 64.8 ;
    END
  END request[476]
  PIN request[477]
    DIRECTION INPUT ;
    USE SIGNAL ;
    PORT
      LAYER M3 ;
        RECT  60.192 64.762 60.21 64.8 ;
    END
  END request[477]
  PIN request[478]
    DIRECTION INPUT ;
    USE SIGNAL ;
    PORT
      LAYER M5 ;
        RECT  60.336 64.716 60.36 64.8 ;
    END
  END request[478]
  PIN request[479]
    DIRECTION INPUT ;
    USE SIGNAL ;
    PORT
      LAYER M3 ;
        RECT  60.444 64.762 60.462 64.8 ;
    END
  END request[479]
  PIN request[47]
    DIRECTION INPUT ;
    USE SIGNAL ;
    PORT
      LAYER M3 ;
        RECT  6.084 64.762 6.102 64.8 ;
    END
  END request[47]
  PIN request[480]
    DIRECTION INPUT ;
    USE SIGNAL ;
    PORT
      LAYER M5 ;
        RECT  60.576 64.716 60.6 64.8 ;
    END
  END request[480]
  PIN request[481]
    DIRECTION INPUT ;
    USE SIGNAL ;
    PORT
      LAYER M3 ;
        RECT  60.696 64.762 60.714 64.8 ;
    END
  END request[481]
  PIN request[482]
    DIRECTION INPUT ;
    USE SIGNAL ;
    PORT
      LAYER M5 ;
        RECT  60.816 64.716 60.84 64.8 ;
    END
  END request[482]
  PIN request[483]
    DIRECTION INPUT ;
    USE SIGNAL ;
    PORT
      LAYER M3 ;
        RECT  60.948 64.762 60.966 64.8 ;
    END
  END request[483]
  PIN request[484]
    DIRECTION INPUT ;
    USE SIGNAL ;
    PORT
      LAYER M5 ;
        RECT  61.056 64.716 61.08 64.8 ;
    END
  END request[484]
  PIN request[485]
    DIRECTION INPUT ;
    USE SIGNAL ;
    PORT
      LAYER M3 ;
        RECT  61.2 64.762 61.218 64.8 ;
    END
  END request[485]
  PIN request[486]
    DIRECTION INPUT ;
    USE SIGNAL ;
    PORT
      LAYER M5 ;
        RECT  61.344 64.716 61.368 64.8 ;
    END
  END request[486]
  PIN request[487]
    DIRECTION INPUT ;
    USE SIGNAL ;
    PORT
      LAYER M3 ;
        RECT  61.452 64.762 61.47 64.8 ;
    END
  END request[487]
  PIN request[488]
    DIRECTION INPUT ;
    USE SIGNAL ;
    PORT
      LAYER M5 ;
        RECT  61.584 64.716 61.608 64.8 ;
    END
  END request[488]
  PIN request[489]
    DIRECTION INPUT ;
    USE SIGNAL ;
    PORT
      LAYER M3 ;
        RECT  61.704 64.762 61.722 64.8 ;
    END
  END request[489]
  PIN request[48]
    DIRECTION INPUT ;
    USE SIGNAL ;
    PORT
      LAYER M5 ;
        RECT  6.24 64.716 6.264 64.8 ;
    END
  END request[48]
  PIN request[490]
    DIRECTION INPUT ;
    USE SIGNAL ;
    PORT
      LAYER M5 ;
        RECT  61.824 64.716 61.848 64.8 ;
    END
  END request[490]
  PIN request[491]
    DIRECTION INPUT ;
    USE SIGNAL ;
    PORT
      LAYER M3 ;
        RECT  61.956 64.762 61.974 64.8 ;
    END
  END request[491]
  PIN request[492]
    DIRECTION INPUT ;
    USE SIGNAL ;
    PORT
      LAYER M5 ;
        RECT  62.064 64.716 62.088 64.8 ;
    END
  END request[492]
  PIN request[493]
    DIRECTION INPUT ;
    USE SIGNAL ;
    PORT
      LAYER M3 ;
        RECT  62.208 64.762 62.226 64.8 ;
    END
  END request[493]
  PIN request[494]
    DIRECTION INPUT ;
    USE SIGNAL ;
    PORT
      LAYER M5 ;
        RECT  62.352 64.716 62.376 64.8 ;
    END
  END request[494]
  PIN request[495]
    DIRECTION INPUT ;
    USE SIGNAL ;
    PORT
      LAYER M3 ;
        RECT  62.46 64.762 62.478 64.8 ;
    END
  END request[495]
  PIN request[496]
    DIRECTION INPUT ;
    USE SIGNAL ;
    PORT
      LAYER M5 ;
        RECT  62.592 64.716 62.616 64.8 ;
    END
  END request[496]
  PIN request[497]
    DIRECTION INPUT ;
    USE SIGNAL ;
    PORT
      LAYER M3 ;
        RECT  62.712 64.762 62.73 64.8 ;
    END
  END request[497]
  PIN request[498]
    DIRECTION INPUT ;
    USE SIGNAL ;
    PORT
      LAYER M5 ;
        RECT  62.832 64.716 62.856 64.8 ;
    END
  END request[498]
  PIN request[499]
    DIRECTION INPUT ;
    USE SIGNAL ;
    PORT
      LAYER M3 ;
        RECT  62.964 64.762 62.982 64.8 ;
    END
  END request[499]
  PIN request[49]
    DIRECTION INPUT ;
    USE SIGNAL ;
    PORT
      LAYER M3 ;
        RECT  6.336 64.762 6.354 64.8 ;
    END
  END request[49]
  PIN request[4]
    DIRECTION INPUT ;
    USE SIGNAL ;
    PORT
      LAYER M5 ;
        RECT  0.672 64.716 0.696 64.8 ;
    END
  END request[4]
  PIN request[500]
    DIRECTION INPUT ;
    USE SIGNAL ;
    PORT
      LAYER M5 ;
        RECT  63.072 64.716 63.096 64.8 ;
    END
  END request[500]
  PIN request[501]
    DIRECTION INPUT ;
    USE SIGNAL ;
    PORT
      LAYER M3 ;
        RECT  63.216 64.762 63.234 64.8 ;
    END
  END request[501]
  PIN request[502]
    DIRECTION INPUT ;
    USE SIGNAL ;
    PORT
      LAYER M5 ;
        RECT  63.36 64.716 63.384 64.8 ;
    END
  END request[502]
  PIN request[503]
    DIRECTION INPUT ;
    USE SIGNAL ;
    PORT
      LAYER M3 ;
        RECT  63.468 64.762 63.486 64.8 ;
    END
  END request[503]
  PIN request[504]
    DIRECTION INPUT ;
    USE SIGNAL ;
    PORT
      LAYER M5 ;
        RECT  63.6 64.716 63.624 64.8 ;
    END
  END request[504]
  PIN request[505]
    DIRECTION INPUT ;
    USE SIGNAL ;
    PORT
      LAYER M3 ;
        RECT  63.72 64.762 63.738 64.8 ;
    END
  END request[505]
  PIN request[506]
    DIRECTION INPUT ;
    USE SIGNAL ;
    PORT
      LAYER M5 ;
        RECT  63.84 64.716 63.864 64.8 ;
    END
  END request[506]
  PIN request[507]
    DIRECTION INPUT ;
    USE SIGNAL ;
    PORT
      LAYER M3 ;
        RECT  63.972 64.762 63.99 64.8 ;
    END
  END request[507]
  PIN request[508]
    DIRECTION INPUT ;
    USE SIGNAL ;
    PORT
      LAYER M5 ;
        RECT  64.08 64.716 64.104 64.8 ;
    END
  END request[508]
  PIN request[509]
    DIRECTION INPUT ;
    USE SIGNAL ;
    PORT
      LAYER M3 ;
        RECT  64.224 64.762 64.242 64.8 ;
    END
  END request[509]
  PIN request[50]
    DIRECTION INPUT ;
    USE SIGNAL ;
    PORT
      LAYER M5 ;
        RECT  6.48 64.716 6.504 64.8 ;
    END
  END request[50]
  PIN request[510]
    DIRECTION INPUT ;
    USE SIGNAL ;
    PORT
      LAYER M5 ;
        RECT  64.368 64.716 64.392 64.8 ;
    END
  END request[510]
  PIN request[511]
    DIRECTION INPUT ;
    USE SIGNAL ;
    PORT
      LAYER M3 ;
        RECT  64.476 64.762 64.494 64.8 ;
    END
  END request[511]
  PIN request[512]
    DIRECTION INPUT ;
    USE SIGNAL ;
    PORT
      LAYER M5 ;
        RECT  64.608 64.716 64.632 64.8 ;
    END
  END request[512]
  PIN request[51]
    DIRECTION INPUT ;
    USE SIGNAL ;
    PORT
      LAYER M3 ;
        RECT  6.588 64.762 6.606 64.8 ;
    END
  END request[51]
  PIN request[52]
    DIRECTION INPUT ;
    USE SIGNAL ;
    PORT
      LAYER M5 ;
        RECT  6.72 64.716 6.744 64.8 ;
    END
  END request[52]
  PIN request[53]
    DIRECTION INPUT ;
    USE SIGNAL ;
    PORT
      LAYER M3 ;
        RECT  6.84 64.762 6.858 64.8 ;
    END
  END request[53]
  PIN request[54]
    DIRECTION INPUT ;
    USE SIGNAL ;
    PORT
      LAYER M5 ;
        RECT  6.96 64.716 6.984 64.8 ;
    END
  END request[54]
  PIN request[55]
    DIRECTION INPUT ;
    USE SIGNAL ;
    PORT
      LAYER M3 ;
        RECT  7.092 64.762 7.11 64.8 ;
    END
  END request[55]
  PIN request[56]
    DIRECTION INPUT ;
    USE SIGNAL ;
    PORT
      LAYER M5 ;
        RECT  7.2 64.716 7.224 64.8 ;
    END
  END request[56]
  PIN request[57]
    DIRECTION INPUT ;
    USE SIGNAL ;
    PORT
      LAYER M3 ;
        RECT  7.344 64.762 7.362 64.8 ;
    END
  END request[57]
  PIN request[58]
    DIRECTION INPUT ;
    USE SIGNAL ;
    PORT
      LAYER M5 ;
        RECT  7.488 64.716 7.512 64.8 ;
    END
  END request[58]
  PIN request[59]
    DIRECTION INPUT ;
    USE SIGNAL ;
    PORT
      LAYER M3 ;
        RECT  7.596 64.762 7.614 64.8 ;
    END
  END request[59]
  PIN request[5]
    DIRECTION INPUT ;
    USE SIGNAL ;
    PORT
      LAYER M3 ;
        RECT  0.792 64.762 0.81 64.8 ;
    END
  END request[5]
  PIN request[60]
    DIRECTION INPUT ;
    USE SIGNAL ;
    PORT
      LAYER M5 ;
        RECT  7.728 64.716 7.752 64.8 ;
    END
  END request[60]
  PIN request[61]
    DIRECTION INPUT ;
    USE SIGNAL ;
    PORT
      LAYER M3 ;
        RECT  7.848 64.762 7.866 64.8 ;
    END
  END request[61]
  PIN request[62]
    DIRECTION INPUT ;
    USE SIGNAL ;
    PORT
      LAYER M5 ;
        RECT  7.968 64.716 7.992 64.8 ;
    END
  END request[62]
  PIN request[63]
    DIRECTION INPUT ;
    USE SIGNAL ;
    PORT
      LAYER M3 ;
        RECT  8.1 64.762 8.118 64.8 ;
    END
  END request[63]
  PIN request[64]
    DIRECTION INPUT ;
    USE SIGNAL ;
    PORT
      LAYER M5 ;
        RECT  8.208 64.716 8.232 64.8 ;
    END
  END request[64]
  PIN request[65]
    DIRECTION INPUT ;
    USE SIGNAL ;
    PORT
      LAYER M3 ;
        RECT  8.352 64.762 8.37 64.8 ;
    END
  END request[65]
  PIN request[66]
    DIRECTION INPUT ;
    USE SIGNAL ;
    PORT
      LAYER M5 ;
        RECT  8.496 64.716 8.52 64.8 ;
    END
  END request[66]
  PIN request[67]
    DIRECTION INPUT ;
    USE SIGNAL ;
    PORT
      LAYER M3 ;
        RECT  8.604 64.762 8.622 64.8 ;
    END
  END request[67]
  PIN request[68]
    DIRECTION INPUT ;
    USE SIGNAL ;
    PORT
      LAYER M5 ;
        RECT  8.736 64.716 8.76 64.8 ;
    END
  END request[68]
  PIN request[69]
    DIRECTION INPUT ;
    USE SIGNAL ;
    PORT
      LAYER M3 ;
        RECT  8.856 64.762 8.874 64.8 ;
    END
  END request[69]
  PIN request[6]
    DIRECTION INPUT ;
    USE SIGNAL ;
    PORT
      LAYER M5 ;
        RECT  0.912 64.716 0.936 64.8 ;
    END
  END request[6]
  PIN request[70]
    DIRECTION INPUT ;
    USE SIGNAL ;
    PORT
      LAYER M5 ;
        RECT  8.976 64.716 9 64.8 ;
    END
  END request[70]
  PIN request[71]
    DIRECTION INPUT ;
    USE SIGNAL ;
    PORT
      LAYER M3 ;
        RECT  9.108 64.762 9.126 64.8 ;
    END
  END request[71]
  PIN request[72]
    DIRECTION INPUT ;
    USE SIGNAL ;
    PORT
      LAYER M5 ;
        RECT  9.216 64.716 9.24 64.8 ;
    END
  END request[72]
  PIN request[73]
    DIRECTION INPUT ;
    USE SIGNAL ;
    PORT
      LAYER M3 ;
        RECT  9.36 64.762 9.378 64.8 ;
    END
  END request[73]
  PIN request[74]
    DIRECTION INPUT ;
    USE SIGNAL ;
    PORT
      LAYER M5 ;
        RECT  9.504 64.716 9.528 64.8 ;
    END
  END request[74]
  PIN request[75]
    DIRECTION INPUT ;
    USE SIGNAL ;
    PORT
      LAYER M3 ;
        RECT  9.612 64.762 9.63 64.8 ;
    END
  END request[75]
  PIN request[76]
    DIRECTION INPUT ;
    USE SIGNAL ;
    PORT
      LAYER M5 ;
        RECT  9.744 64.716 9.768 64.8 ;
    END
  END request[76]
  PIN request[77]
    DIRECTION INPUT ;
    USE SIGNAL ;
    PORT
      LAYER M3 ;
        RECT  9.864 64.762 9.882 64.8 ;
    END
  END request[77]
  PIN request[78]
    DIRECTION INPUT ;
    USE SIGNAL ;
    PORT
      LAYER M5 ;
        RECT  9.984 64.716 10.008 64.8 ;
    END
  END request[78]
  PIN request[79]
    DIRECTION INPUT ;
    USE SIGNAL ;
    PORT
      LAYER M3 ;
        RECT  10.116 64.762 10.134 64.8 ;
    END
  END request[79]
  PIN request[7]
    DIRECTION INPUT ;
    USE SIGNAL ;
    PORT
      LAYER M3 ;
        RECT  1.044 64.762 1.062 64.8 ;
    END
  END request[7]
  PIN request[80]
    DIRECTION INPUT ;
    USE SIGNAL ;
    PORT
      LAYER M5 ;
        RECT  10.224 64.716 10.248 64.8 ;
    END
  END request[80]
  PIN request[81]
    DIRECTION INPUT ;
    USE SIGNAL ;
    PORT
      LAYER M3 ;
        RECT  10.368 64.762 10.386 64.8 ;
    END
  END request[81]
  PIN request[82]
    DIRECTION INPUT ;
    USE SIGNAL ;
    PORT
      LAYER M5 ;
        RECT  10.512 64.716 10.536 64.8 ;
    END
  END request[82]
  PIN request[83]
    DIRECTION INPUT ;
    USE SIGNAL ;
    PORT
      LAYER M3 ;
        RECT  10.62 64.762 10.638 64.8 ;
    END
  END request[83]
  PIN request[84]
    DIRECTION INPUT ;
    USE SIGNAL ;
    PORT
      LAYER M5 ;
        RECT  10.752 64.716 10.776 64.8 ;
    END
  END request[84]
  PIN request[85]
    DIRECTION INPUT ;
    USE SIGNAL ;
    PORT
      LAYER M3 ;
        RECT  10.872 64.762 10.89 64.8 ;
    END
  END request[85]
  PIN request[86]
    DIRECTION INPUT ;
    USE SIGNAL ;
    PORT
      LAYER M5 ;
        RECT  10.992 64.716 11.016 64.8 ;
    END
  END request[86]
  PIN request[87]
    DIRECTION INPUT ;
    USE SIGNAL ;
    PORT
      LAYER M3 ;
        RECT  11.124 64.762 11.142 64.8 ;
    END
  END request[87]
  PIN request[88]
    DIRECTION INPUT ;
    USE SIGNAL ;
    PORT
      LAYER M5 ;
        RECT  11.232 64.716 11.256 64.8 ;
    END
  END request[88]
  PIN request[89]
    DIRECTION INPUT ;
    USE SIGNAL ;
    PORT
      LAYER M3 ;
        RECT  11.376 64.762 11.394 64.8 ;
    END
  END request[89]
  PIN request[8]
    DIRECTION INPUT ;
    USE SIGNAL ;
    PORT
      LAYER M5 ;
        RECT  1.2 64.716 1.224 64.8 ;
    END
  END request[8]
  PIN request[90]
    DIRECTION INPUT ;
    USE SIGNAL ;
    PORT
      LAYER M5 ;
        RECT  11.52 64.716 11.544 64.8 ;
    END
  END request[90]
  PIN request[91]
    DIRECTION INPUT ;
    USE SIGNAL ;
    PORT
      LAYER M3 ;
        RECT  11.628 64.762 11.646 64.8 ;
    END
  END request[91]
  PIN request[92]
    DIRECTION INPUT ;
    USE SIGNAL ;
    PORT
      LAYER M5 ;
        RECT  11.76 64.716 11.784 64.8 ;
    END
  END request[92]
  PIN request[93]
    DIRECTION INPUT ;
    USE SIGNAL ;
    PORT
      LAYER M3 ;
        RECT  11.88 64.762 11.898 64.8 ;
    END
  END request[93]
  PIN request[94]
    DIRECTION INPUT ;
    USE SIGNAL ;
    PORT
      LAYER M5 ;
        RECT  12 64.716 12.024 64.8 ;
    END
  END request[94]
  PIN request[95]
    DIRECTION INPUT ;
    USE SIGNAL ;
    PORT
      LAYER M3 ;
        RECT  12.132 64.762 12.15 64.8 ;
    END
  END request[95]
  PIN request[96]
    DIRECTION INPUT ;
    USE SIGNAL ;
    PORT
      LAYER M5 ;
        RECT  12.24 64.716 12.264 64.8 ;
    END
  END request[96]
  PIN request[97]
    DIRECTION INPUT ;
    USE SIGNAL ;
    PORT
      LAYER M3 ;
        RECT  12.384 64.762 12.402 64.8 ;
    END
  END request[97]
  PIN request[98]
    DIRECTION INPUT ;
    USE SIGNAL ;
    PORT
      LAYER M5 ;
        RECT  12.528 64.716 12.552 64.8 ;
    END
  END request[98]
  PIN request[99]
    DIRECTION INPUT ;
    USE SIGNAL ;
    PORT
      LAYER M3 ;
        RECT  12.636 64.762 12.654 64.8 ;
    END
  END request[99]
  PIN request[9]
    DIRECTION INPUT ;
    USE SIGNAL ;
    PORT
      LAYER M3 ;
        RECT  1.296 64.762 1.314 64.8 ;
    END
  END request[9]
  PIN rst_n
    DIRECTION INPUT ;
    USE SIGNAL ;
    PORT
      LAYER M3 ;
        RECT  64.728 64.762 64.746 64.8 ;
    END
  END rst_n
  PIN vr2q[0]
    DIRECTION OUTPUT ;
    USE SIGNAL ;
    PORT
      LAYER M3 ;
        RECT  0.072 0 0.09 0.038 ;
    END
  END vr2q[0]
  PIN vr2q[100]
    DIRECTION OUTPUT ;
    USE SIGNAL ;
    PORT
      LAYER M3 ;
        RECT  12.672 0 12.69 0.038 ;
    END
  END vr2q[100]
  PIN vr2q[101]
    DIRECTION OUTPUT ;
    USE SIGNAL ;
    PORT
      LAYER M5 ;
        RECT  12.816 0 12.84 0.084 ;
    END
  END vr2q[101]
  PIN vr2q[102]
    DIRECTION OUTPUT ;
    USE SIGNAL ;
    PORT
      LAYER M3 ;
        RECT  12.924 0 12.942 0.038 ;
    END
  END vr2q[102]
  PIN vr2q[103]
    DIRECTION OUTPUT ;
    USE SIGNAL ;
    PORT
      LAYER M5 ;
        RECT  13.056 0 13.08 0.084 ;
    END
  END vr2q[103]
  PIN vr2q[104]
    DIRECTION OUTPUT ;
    USE SIGNAL ;
    PORT
      LAYER M3 ;
        RECT  13.176 0 13.194 0.038 ;
    END
  END vr2q[104]
  PIN vr2q[105]
    DIRECTION OUTPUT ;
    USE SIGNAL ;
    PORT
      LAYER M5 ;
        RECT  13.296 0 13.32 0.084 ;
    END
  END vr2q[105]
  PIN vr2q[106]
    DIRECTION OUTPUT ;
    USE SIGNAL ;
    PORT
      LAYER M3 ;
        RECT  13.428 0 13.446 0.038 ;
    END
  END vr2q[106]
  PIN vr2q[107]
    DIRECTION OUTPUT ;
    USE SIGNAL ;
    PORT
      LAYER M5 ;
        RECT  13.584 0 13.608 0.084 ;
    END
  END vr2q[107]
  PIN vr2q[108]
    DIRECTION OUTPUT ;
    USE SIGNAL ;
    PORT
      LAYER M3 ;
        RECT  13.68 0 13.698 0.038 ;
    END
  END vr2q[108]
  PIN vr2q[109]
    DIRECTION OUTPUT ;
    USE SIGNAL ;
    PORT
      LAYER M5 ;
        RECT  13.824 0 13.848 0.084 ;
    END
  END vr2q[109]
  PIN vr2q[10]
    DIRECTION OUTPUT ;
    USE SIGNAL ;
    PORT
      LAYER M3 ;
        RECT  1.332 0 1.35 0.038 ;
    END
  END vr2q[10]
  PIN vr2q[110]
    DIRECTION OUTPUT ;
    USE SIGNAL ;
    PORT
      LAYER M3 ;
        RECT  13.932 0 13.95 0.038 ;
    END
  END vr2q[110]
  PIN vr2q[111]
    DIRECTION OUTPUT ;
    USE SIGNAL ;
    PORT
      LAYER M5 ;
        RECT  14.064 0 14.088 0.084 ;
    END
  END vr2q[111]
  PIN vr2q[112]
    DIRECTION OUTPUT ;
    USE SIGNAL ;
    PORT
      LAYER M3 ;
        RECT  14.22 0 14.238 0.038 ;
    END
  END vr2q[112]
  PIN vr2q[113]
    DIRECTION OUTPUT ;
    USE SIGNAL ;
    PORT
      LAYER M5 ;
        RECT  14.304 0 14.328 0.084 ;
    END
  END vr2q[113]
  PIN vr2q[114]
    DIRECTION OUTPUT ;
    USE SIGNAL ;
    PORT
      LAYER M3 ;
        RECT  14.472 0 14.49 0.038 ;
    END
  END vr2q[114]
  PIN vr2q[115]
    DIRECTION OUTPUT ;
    USE SIGNAL ;
    PORT
      LAYER M5 ;
        RECT  14.592 0 14.616 0.084 ;
    END
  END vr2q[115]
  PIN vr2q[116]
    DIRECTION OUTPUT ;
    USE SIGNAL ;
    PORT
      LAYER M3 ;
        RECT  14.724 0 14.742 0.038 ;
    END
  END vr2q[116]
  PIN vr2q[117]
    DIRECTION OUTPUT ;
    USE SIGNAL ;
    PORT
      LAYER M5 ;
        RECT  14.832 0 14.856 0.084 ;
    END
  END vr2q[117]
  PIN vr2q[118]
    DIRECTION OUTPUT ;
    USE SIGNAL ;
    PORT
      LAYER M3 ;
        RECT  14.976 0 14.994 0.038 ;
    END
  END vr2q[118]
  PIN vr2q[119]
    DIRECTION OUTPUT ;
    USE SIGNAL ;
    PORT
      LAYER M5 ;
        RECT  15.072 0 15.096 0.084 ;
    END
  END vr2q[119]
  PIN vr2q[11]
    DIRECTION OUTPUT ;
    USE SIGNAL ;
    PORT
      LAYER M5 ;
        RECT  1.44 0 1.464 0.084 ;
    END
  END vr2q[11]
  PIN vr2q[120]
    DIRECTION OUTPUT ;
    USE SIGNAL ;
    PORT
      LAYER M3 ;
        RECT  15.228 0 15.246 0.038 ;
    END
  END vr2q[120]
  PIN vr2q[121]
    DIRECTION OUTPUT ;
    USE SIGNAL ;
    PORT
      LAYER M5 ;
        RECT  15.312 0 15.336 0.084 ;
    END
  END vr2q[121]
  PIN vr2q[122]
    DIRECTION OUTPUT ;
    USE SIGNAL ;
    PORT
      LAYER M3 ;
        RECT  15.48 0 15.498 0.038 ;
    END
  END vr2q[122]
  PIN vr2q[123]
    DIRECTION OUTPUT ;
    USE SIGNAL ;
    PORT
      LAYER M5 ;
        RECT  15.6 0 15.624 0.084 ;
    END
  END vr2q[123]
  PIN vr2q[124]
    DIRECTION OUTPUT ;
    USE SIGNAL ;
    PORT
      LAYER M3 ;
        RECT  15.732 0 15.75 0.038 ;
    END
  END vr2q[124]
  PIN vr2q[125]
    DIRECTION OUTPUT ;
    USE SIGNAL ;
    PORT
      LAYER M5 ;
        RECT  15.84 0 15.864 0.084 ;
    END
  END vr2q[125]
  PIN vr2q[126]
    DIRECTION OUTPUT ;
    USE SIGNAL ;
    PORT
      LAYER M3 ;
        RECT  15.984 0 16.002 0.038 ;
    END
  END vr2q[126]
  PIN vr2q[127]
    DIRECTION OUTPUT ;
    USE SIGNAL ;
    PORT
      LAYER M5 ;
        RECT  16.08 0 16.104 0.084 ;
    END
  END vr2q[127]
  PIN vr2q[128]
    DIRECTION OUTPUT ;
    USE SIGNAL ;
    PORT
      LAYER M3 ;
        RECT  16.236 0 16.254 0.038 ;
    END
  END vr2q[128]
  PIN vr2q[129]
    DIRECTION OUTPUT ;
    USE SIGNAL ;
    PORT
      LAYER M5 ;
        RECT  16.368 0 16.392 0.084 ;
    END
  END vr2q[129]
  PIN vr2q[12]
    DIRECTION OUTPUT ;
    USE SIGNAL ;
    PORT
      LAYER M3 ;
        RECT  1.584 0 1.602 0.038 ;
    END
  END vr2q[12]
  PIN vr2q[130]
    DIRECTION OUTPUT ;
    USE SIGNAL ;
    PORT
      LAYER M3 ;
        RECT  16.488 0 16.506 0.038 ;
    END
  END vr2q[130]
  PIN vr2q[131]
    DIRECTION OUTPUT ;
    USE SIGNAL ;
    PORT
      LAYER M5 ;
        RECT  16.608 0 16.632 0.084 ;
    END
  END vr2q[131]
  PIN vr2q[132]
    DIRECTION OUTPUT ;
    USE SIGNAL ;
    PORT
      LAYER M3 ;
        RECT  16.74 0 16.758 0.038 ;
    END
  END vr2q[132]
  PIN vr2q[133]
    DIRECTION OUTPUT ;
    USE SIGNAL ;
    PORT
      LAYER M5 ;
        RECT  16.848 0 16.872 0.084 ;
    END
  END vr2q[133]
  PIN vr2q[134]
    DIRECTION OUTPUT ;
    USE SIGNAL ;
    PORT
      LAYER M3 ;
        RECT  16.992 0 17.01 0.038 ;
    END
  END vr2q[134]
  PIN vr2q[135]
    DIRECTION OUTPUT ;
    USE SIGNAL ;
    PORT
      LAYER M5 ;
        RECT  17.088 0 17.112 0.084 ;
    END
  END vr2q[135]
  PIN vr2q[136]
    DIRECTION OUTPUT ;
    USE SIGNAL ;
    PORT
      LAYER M3 ;
        RECT  17.244 0 17.262 0.038 ;
    END
  END vr2q[136]
  PIN vr2q[137]
    DIRECTION OUTPUT ;
    USE SIGNAL ;
    PORT
      LAYER M5 ;
        RECT  17.376 0 17.4 0.084 ;
    END
  END vr2q[137]
  PIN vr2q[138]
    DIRECTION OUTPUT ;
    USE SIGNAL ;
    PORT
      LAYER M3 ;
        RECT  17.496 0 17.514 0.038 ;
    END
  END vr2q[138]
  PIN vr2q[139]
    DIRECTION OUTPUT ;
    USE SIGNAL ;
    PORT
      LAYER M5 ;
        RECT  17.616 0 17.64 0.084 ;
    END
  END vr2q[139]
  PIN vr2q[13]
    DIRECTION OUTPUT ;
    USE SIGNAL ;
    PORT
      LAYER M5 ;
        RECT  1.68 0 1.704 0.084 ;
    END
  END vr2q[13]
  PIN vr2q[140]
    DIRECTION OUTPUT ;
    USE SIGNAL ;
    PORT
      LAYER M3 ;
        RECT  17.748 0 17.766 0.038 ;
    END
  END vr2q[140]
  PIN vr2q[141]
    DIRECTION OUTPUT ;
    USE SIGNAL ;
    PORT
      LAYER M5 ;
        RECT  17.856 0 17.88 0.084 ;
    END
  END vr2q[141]
  PIN vr2q[142]
    DIRECTION OUTPUT ;
    USE SIGNAL ;
    PORT
      LAYER M3 ;
        RECT  18 0 18.018 0.038 ;
    END
  END vr2q[142]
  PIN vr2q[143]
    DIRECTION OUTPUT ;
    USE SIGNAL ;
    PORT
      LAYER M5 ;
        RECT  18.096 0 18.12 0.084 ;
    END
  END vr2q[143]
  PIN vr2q[144]
    DIRECTION OUTPUT ;
    USE SIGNAL ;
    PORT
      LAYER M3 ;
        RECT  18.252 0 18.27 0.038 ;
    END
  END vr2q[144]
  PIN vr2q[145]
    DIRECTION OUTPUT ;
    USE SIGNAL ;
    PORT
      LAYER M5 ;
        RECT  18.384 0 18.408 0.084 ;
    END
  END vr2q[145]
  PIN vr2q[146]
    DIRECTION OUTPUT ;
    USE SIGNAL ;
    PORT
      LAYER M3 ;
        RECT  18.504 0 18.522 0.038 ;
    END
  END vr2q[146]
  PIN vr2q[147]
    DIRECTION OUTPUT ;
    USE SIGNAL ;
    PORT
      LAYER M5 ;
        RECT  18.624 0 18.648 0.084 ;
    END
  END vr2q[147]
  PIN vr2q[148]
    DIRECTION OUTPUT ;
    USE SIGNAL ;
    PORT
      LAYER M3 ;
        RECT  18.756 0 18.774 0.038 ;
    END
  END vr2q[148]
  PIN vr2q[149]
    DIRECTION OUTPUT ;
    USE SIGNAL ;
    PORT
      LAYER M5 ;
        RECT  18.864 0 18.888 0.084 ;
    END
  END vr2q[149]
  PIN vr2q[14]
    DIRECTION OUTPUT ;
    USE SIGNAL ;
    PORT
      LAYER M3 ;
        RECT  1.836 0 1.854 0.038 ;
    END
  END vr2q[14]
  PIN vr2q[150]
    DIRECTION OUTPUT ;
    USE SIGNAL ;
    PORT
      LAYER M3 ;
        RECT  19.008 0 19.026 0.038 ;
    END
  END vr2q[150]
  PIN vr2q[151]
    DIRECTION OUTPUT ;
    USE SIGNAL ;
    PORT
      LAYER M5 ;
        RECT  19.104 0 19.128 0.084 ;
    END
  END vr2q[151]
  PIN vr2q[152]
    DIRECTION OUTPUT ;
    USE SIGNAL ;
    PORT
      LAYER M3 ;
        RECT  19.26 0 19.278 0.038 ;
    END
  END vr2q[152]
  PIN vr2q[153]
    DIRECTION OUTPUT ;
    USE SIGNAL ;
    PORT
      LAYER M5 ;
        RECT  19.392 0 19.416 0.084 ;
    END
  END vr2q[153]
  PIN vr2q[154]
    DIRECTION OUTPUT ;
    USE SIGNAL ;
    PORT
      LAYER M3 ;
        RECT  19.512 0 19.53 0.038 ;
    END
  END vr2q[154]
  PIN vr2q[155]
    DIRECTION OUTPUT ;
    USE SIGNAL ;
    PORT
      LAYER M5 ;
        RECT  19.632 0 19.656 0.084 ;
    END
  END vr2q[155]
  PIN vr2q[156]
    DIRECTION OUTPUT ;
    USE SIGNAL ;
    PORT
      LAYER M3 ;
        RECT  19.764 0 19.782 0.038 ;
    END
  END vr2q[156]
  PIN vr2q[157]
    DIRECTION OUTPUT ;
    USE SIGNAL ;
    PORT
      LAYER M5 ;
        RECT  19.872 0 19.896 0.084 ;
    END
  END vr2q[157]
  PIN vr2q[158]
    DIRECTION OUTPUT ;
    USE SIGNAL ;
    PORT
      LAYER M3 ;
        RECT  20.016 0 20.034 0.038 ;
    END
  END vr2q[158]
  PIN vr2q[159]
    DIRECTION OUTPUT ;
    USE SIGNAL ;
    PORT
      LAYER M5 ;
        RECT  20.112 0 20.136 0.084 ;
    END
  END vr2q[159]
  PIN vr2q[15]
    DIRECTION OUTPUT ;
    USE SIGNAL ;
    PORT
      LAYER M5 ;
        RECT  1.968 0 1.992 0.084 ;
    END
  END vr2q[15]
  PIN vr2q[160]
    DIRECTION OUTPUT ;
    USE SIGNAL ;
    PORT
      LAYER M3 ;
        RECT  20.268 0 20.286 0.038 ;
    END
  END vr2q[160]
  PIN vr2q[161]
    DIRECTION OUTPUT ;
    USE SIGNAL ;
    PORT
      LAYER M5 ;
        RECT  20.4 0 20.424 0.084 ;
    END
  END vr2q[161]
  PIN vr2q[162]
    DIRECTION OUTPUT ;
    USE SIGNAL ;
    PORT
      LAYER M3 ;
        RECT  20.52 0 20.538 0.038 ;
    END
  END vr2q[162]
  PIN vr2q[163]
    DIRECTION OUTPUT ;
    USE SIGNAL ;
    PORT
      LAYER M5 ;
        RECT  20.64 0 20.664 0.084 ;
    END
  END vr2q[163]
  PIN vr2q[164]
    DIRECTION OUTPUT ;
    USE SIGNAL ;
    PORT
      LAYER M3 ;
        RECT  20.772 0 20.79 0.038 ;
    END
  END vr2q[164]
  PIN vr2q[165]
    DIRECTION OUTPUT ;
    USE SIGNAL ;
    PORT
      LAYER M5 ;
        RECT  20.88 0 20.904 0.084 ;
    END
  END vr2q[165]
  PIN vr2q[166]
    DIRECTION OUTPUT ;
    USE SIGNAL ;
    PORT
      LAYER M3 ;
        RECT  21.024 0 21.042 0.038 ;
    END
  END vr2q[166]
  PIN vr2q[167]
    DIRECTION OUTPUT ;
    USE SIGNAL ;
    PORT
      LAYER M5 ;
        RECT  21.168 0 21.192 0.084 ;
    END
  END vr2q[167]
  PIN vr2q[168]
    DIRECTION OUTPUT ;
    USE SIGNAL ;
    PORT
      LAYER M3 ;
        RECT  21.276 0 21.294 0.038 ;
    END
  END vr2q[168]
  PIN vr2q[169]
    DIRECTION OUTPUT ;
    USE SIGNAL ;
    PORT
      LAYER M5 ;
        RECT  21.408 0 21.432 0.084 ;
    END
  END vr2q[169]
  PIN vr2q[16]
    DIRECTION OUTPUT ;
    USE SIGNAL ;
    PORT
      LAYER M3 ;
        RECT  2.088 0 2.106 0.038 ;
    END
  END vr2q[16]
  PIN vr2q[170]
    DIRECTION OUTPUT ;
    USE SIGNAL ;
    PORT
      LAYER M3 ;
        RECT  21.528 0 21.546 0.038 ;
    END
  END vr2q[170]
  PIN vr2q[171]
    DIRECTION OUTPUT ;
    USE SIGNAL ;
    PORT
      LAYER M5 ;
        RECT  21.648 0 21.672 0.084 ;
    END
  END vr2q[171]
  PIN vr2q[172]
    DIRECTION OUTPUT ;
    USE SIGNAL ;
    PORT
      LAYER M3 ;
        RECT  21.78 0 21.798 0.038 ;
    END
  END vr2q[172]
  PIN vr2q[173]
    DIRECTION OUTPUT ;
    USE SIGNAL ;
    PORT
      LAYER M5 ;
        RECT  21.888 0 21.912 0.084 ;
    END
  END vr2q[173]
  PIN vr2q[174]
    DIRECTION OUTPUT ;
    USE SIGNAL ;
    PORT
      LAYER M3 ;
        RECT  22.032 0 22.05 0.038 ;
    END
  END vr2q[174]
  PIN vr2q[175]
    DIRECTION OUTPUT ;
    USE SIGNAL ;
    PORT
      LAYER M5 ;
        RECT  22.176 0 22.2 0.084 ;
    END
  END vr2q[175]
  PIN vr2q[176]
    DIRECTION OUTPUT ;
    USE SIGNAL ;
    PORT
      LAYER M3 ;
        RECT  22.284 0 22.302 0.038 ;
    END
  END vr2q[176]
  PIN vr2q[177]
    DIRECTION OUTPUT ;
    USE SIGNAL ;
    PORT
      LAYER M5 ;
        RECT  22.416 0 22.44 0.084 ;
    END
  END vr2q[177]
  PIN vr2q[178]
    DIRECTION OUTPUT ;
    USE SIGNAL ;
    PORT
      LAYER M3 ;
        RECT  22.536 0 22.554 0.038 ;
    END
  END vr2q[178]
  PIN vr2q[179]
    DIRECTION OUTPUT ;
    USE SIGNAL ;
    PORT
      LAYER M5 ;
        RECT  22.656 0 22.68 0.084 ;
    END
  END vr2q[179]
  PIN vr2q[17]
    DIRECTION OUTPUT ;
    USE SIGNAL ;
    PORT
      LAYER M5 ;
        RECT  2.208 0 2.232 0.084 ;
    END
  END vr2q[17]
  PIN vr2q[180]
    DIRECTION OUTPUT ;
    USE SIGNAL ;
    PORT
      LAYER M3 ;
        RECT  22.788 0 22.806 0.038 ;
    END
  END vr2q[180]
  PIN vr2q[181]
    DIRECTION OUTPUT ;
    USE SIGNAL ;
    PORT
      LAYER M5 ;
        RECT  22.896 0 22.92 0.084 ;
    END
  END vr2q[181]
  PIN vr2q[182]
    DIRECTION OUTPUT ;
    USE SIGNAL ;
    PORT
      LAYER M3 ;
        RECT  23.04 0 23.058 0.038 ;
    END
  END vr2q[182]
  PIN vr2q[183]
    DIRECTION OUTPUT ;
    USE SIGNAL ;
    PORT
      LAYER M5 ;
        RECT  23.184 0 23.208 0.084 ;
    END
  END vr2q[183]
  PIN vr2q[184]
    DIRECTION OUTPUT ;
    USE SIGNAL ;
    PORT
      LAYER M3 ;
        RECT  23.292 0 23.31 0.038 ;
    END
  END vr2q[184]
  PIN vr2q[185]
    DIRECTION OUTPUT ;
    USE SIGNAL ;
    PORT
      LAYER M5 ;
        RECT  23.424 0 23.448 0.084 ;
    END
  END vr2q[185]
  PIN vr2q[186]
    DIRECTION OUTPUT ;
    USE SIGNAL ;
    PORT
      LAYER M3 ;
        RECT  23.544 0 23.562 0.038 ;
    END
  END vr2q[186]
  PIN vr2q[187]
    DIRECTION OUTPUT ;
    USE SIGNAL ;
    PORT
      LAYER M5 ;
        RECT  23.664 0 23.688 0.084 ;
    END
  END vr2q[187]
  PIN vr2q[188]
    DIRECTION OUTPUT ;
    USE SIGNAL ;
    PORT
      LAYER M3 ;
        RECT  23.796 0 23.814 0.038 ;
    END
  END vr2q[188]
  PIN vr2q[189]
    DIRECTION OUTPUT ;
    USE SIGNAL ;
    PORT
      LAYER M5 ;
        RECT  23.904 0 23.928 0.084 ;
    END
  END vr2q[189]
  PIN vr2q[18]
    DIRECTION OUTPUT ;
    USE SIGNAL ;
    PORT
      LAYER M3 ;
        RECT  2.34 0 2.358 0.038 ;
    END
  END vr2q[18]
  PIN vr2q[190]
    DIRECTION OUTPUT ;
    USE SIGNAL ;
    PORT
      LAYER M3 ;
        RECT  24.048 0 24.066 0.038 ;
    END
  END vr2q[190]
  PIN vr2q[191]
    DIRECTION OUTPUT ;
    USE SIGNAL ;
    PORT
      LAYER M5 ;
        RECT  24.192 0 24.216 0.084 ;
    END
  END vr2q[191]
  PIN vr2q[192]
    DIRECTION OUTPUT ;
    USE SIGNAL ;
    PORT
      LAYER M3 ;
        RECT  24.3 0 24.318 0.038 ;
    END
  END vr2q[192]
  PIN vr2q[193]
    DIRECTION OUTPUT ;
    USE SIGNAL ;
    PORT
      LAYER M5 ;
        RECT  24.432 0 24.456 0.084 ;
    END
  END vr2q[193]
  PIN vr2q[194]
    DIRECTION OUTPUT ;
    USE SIGNAL ;
    PORT
      LAYER M3 ;
        RECT  24.552 0 24.57 0.038 ;
    END
  END vr2q[194]
  PIN vr2q[195]
    DIRECTION OUTPUT ;
    USE SIGNAL ;
    PORT
      LAYER M5 ;
        RECT  24.672 0 24.696 0.084 ;
    END
  END vr2q[195]
  PIN vr2q[196]
    DIRECTION OUTPUT ;
    USE SIGNAL ;
    PORT
      LAYER M3 ;
        RECT  24.804 0 24.822 0.038 ;
    END
  END vr2q[196]
  PIN vr2q[197]
    DIRECTION OUTPUT ;
    USE SIGNAL ;
    PORT
      LAYER M5 ;
        RECT  24.912 0 24.936 0.084 ;
    END
  END vr2q[197]
  PIN vr2q[198]
    DIRECTION OUTPUT ;
    USE SIGNAL ;
    PORT
      LAYER M3 ;
        RECT  25.056 0 25.074 0.038 ;
    END
  END vr2q[198]
  PIN vr2q[199]
    DIRECTION OUTPUT ;
    USE SIGNAL ;
    PORT
      LAYER M5 ;
        RECT  25.2 0 25.224 0.084 ;
    END
  END vr2q[199]
  PIN vr2q[19]
    DIRECTION OUTPUT ;
    USE SIGNAL ;
    PORT
      LAYER M5 ;
        RECT  2.448 0 2.472 0.084 ;
    END
  END vr2q[19]
  PIN vr2q[1]
    DIRECTION OUTPUT ;
    USE SIGNAL ;
    PORT
      LAYER M5 ;
        RECT  0.192 0 0.216 0.084 ;
    END
  END vr2q[1]
  PIN vr2q[200]
    DIRECTION OUTPUT ;
    USE SIGNAL ;
    PORT
      LAYER M3 ;
        RECT  25.308 0 25.326 0.038 ;
    END
  END vr2q[200]
  PIN vr2q[201]
    DIRECTION OUTPUT ;
    USE SIGNAL ;
    PORT
      LAYER M5 ;
        RECT  25.44 0 25.464 0.084 ;
    END
  END vr2q[201]
  PIN vr2q[202]
    DIRECTION OUTPUT ;
    USE SIGNAL ;
    PORT
      LAYER M3 ;
        RECT  25.56 0 25.578 0.038 ;
    END
  END vr2q[202]
  PIN vr2q[203]
    DIRECTION OUTPUT ;
    USE SIGNAL ;
    PORT
      LAYER M5 ;
        RECT  25.68 0 25.704 0.084 ;
    END
  END vr2q[203]
  PIN vr2q[204]
    DIRECTION OUTPUT ;
    USE SIGNAL ;
    PORT
      LAYER M3 ;
        RECT  25.812 0 25.83 0.038 ;
    END
  END vr2q[204]
  PIN vr2q[205]
    DIRECTION OUTPUT ;
    USE SIGNAL ;
    PORT
      LAYER M5 ;
        RECT  25.968 0 25.992 0.084 ;
    END
  END vr2q[205]
  PIN vr2q[206]
    DIRECTION OUTPUT ;
    USE SIGNAL ;
    PORT
      LAYER M3 ;
        RECT  26.064 0 26.082 0.038 ;
    END
  END vr2q[206]
  PIN vr2q[207]
    DIRECTION OUTPUT ;
    USE SIGNAL ;
    PORT
      LAYER M5 ;
        RECT  26.208 0 26.232 0.084 ;
    END
  END vr2q[207]
  PIN vr2q[208]
    DIRECTION OUTPUT ;
    USE SIGNAL ;
    PORT
      LAYER M3 ;
        RECT  26.316 0 26.334 0.038 ;
    END
  END vr2q[208]
  PIN vr2q[209]
    DIRECTION OUTPUT ;
    USE SIGNAL ;
    PORT
      LAYER M5 ;
        RECT  26.448 0 26.472 0.084 ;
    END
  END vr2q[209]
  PIN vr2q[20]
    DIRECTION OUTPUT ;
    USE SIGNAL ;
    PORT
      LAYER M3 ;
        RECT  2.592 0 2.61 0.038 ;
    END
  END vr2q[20]
  PIN vr2q[210]
    DIRECTION OUTPUT ;
    USE SIGNAL ;
    PORT
      LAYER M3 ;
        RECT  26.568 0 26.586 0.038 ;
    END
  END vr2q[210]
  PIN vr2q[211]
    DIRECTION OUTPUT ;
    USE SIGNAL ;
    PORT
      LAYER M5 ;
        RECT  26.688 0 26.712 0.084 ;
    END
  END vr2q[211]
  PIN vr2q[212]
    DIRECTION OUTPUT ;
    USE SIGNAL ;
    PORT
      LAYER M3 ;
        RECT  26.82 0 26.838 0.038 ;
    END
  END vr2q[212]
  PIN vr2q[213]
    DIRECTION OUTPUT ;
    USE SIGNAL ;
    PORT
      LAYER M5 ;
        RECT  26.976 0 27 0.084 ;
    END
  END vr2q[213]
  PIN vr2q[214]
    DIRECTION OUTPUT ;
    USE SIGNAL ;
    PORT
      LAYER M3 ;
        RECT  27.072 0 27.09 0.038 ;
    END
  END vr2q[214]
  PIN vr2q[215]
    DIRECTION OUTPUT ;
    USE SIGNAL ;
    PORT
      LAYER M5 ;
        RECT  27.216 0 27.24 0.084 ;
    END
  END vr2q[215]
  PIN vr2q[216]
    DIRECTION OUTPUT ;
    USE SIGNAL ;
    PORT
      LAYER M3 ;
        RECT  27.324 0 27.342 0.038 ;
    END
  END vr2q[216]
  PIN vr2q[217]
    DIRECTION OUTPUT ;
    USE SIGNAL ;
    PORT
      LAYER M5 ;
        RECT  27.456 0 27.48 0.084 ;
    END
  END vr2q[217]
  PIN vr2q[218]
    DIRECTION OUTPUT ;
    USE SIGNAL ;
    PORT
      LAYER M3 ;
        RECT  27.576 0 27.594 0.038 ;
    END
  END vr2q[218]
  PIN vr2q[219]
    DIRECTION OUTPUT ;
    USE SIGNAL ;
    PORT
      LAYER M5 ;
        RECT  27.696 0 27.72 0.084 ;
    END
  END vr2q[219]
  PIN vr2q[21]
    DIRECTION OUTPUT ;
    USE SIGNAL ;
    PORT
      LAYER M5 ;
        RECT  2.688 0 2.712 0.084 ;
    END
  END vr2q[21]
  PIN vr2q[220]
    DIRECTION OUTPUT ;
    USE SIGNAL ;
    PORT
      LAYER M3 ;
        RECT  27.828 0 27.846 0.038 ;
    END
  END vr2q[220]
  PIN vr2q[221]
    DIRECTION OUTPUT ;
    USE SIGNAL ;
    PORT
      LAYER M5 ;
        RECT  27.984 0 28.008 0.084 ;
    END
  END vr2q[221]
  PIN vr2q[222]
    DIRECTION OUTPUT ;
    USE SIGNAL ;
    PORT
      LAYER M3 ;
        RECT  28.08 0 28.098 0.038 ;
    END
  END vr2q[222]
  PIN vr2q[223]
    DIRECTION OUTPUT ;
    USE SIGNAL ;
    PORT
      LAYER M5 ;
        RECT  28.224 0 28.248 0.084 ;
    END
  END vr2q[223]
  PIN vr2q[224]
    DIRECTION OUTPUT ;
    USE SIGNAL ;
    PORT
      LAYER M3 ;
        RECT  28.332 0 28.35 0.038 ;
    END
  END vr2q[224]
  PIN vr2q[225]
    DIRECTION OUTPUT ;
    USE SIGNAL ;
    PORT
      LAYER M5 ;
        RECT  28.464 0 28.488 0.084 ;
    END
  END vr2q[225]
  PIN vr2q[226]
    DIRECTION OUTPUT ;
    USE SIGNAL ;
    PORT
      LAYER M3 ;
        RECT  28.62 0 28.638 0.038 ;
    END
  END vr2q[226]
  PIN vr2q[227]
    DIRECTION OUTPUT ;
    USE SIGNAL ;
    PORT
      LAYER M5 ;
        RECT  28.704 0 28.728 0.084 ;
    END
  END vr2q[227]
  PIN vr2q[228]
    DIRECTION OUTPUT ;
    USE SIGNAL ;
    PORT
      LAYER M3 ;
        RECT  28.872 0 28.89 0.038 ;
    END
  END vr2q[228]
  PIN vr2q[229]
    DIRECTION OUTPUT ;
    USE SIGNAL ;
    PORT
      LAYER M5 ;
        RECT  28.992 0 29.016 0.084 ;
    END
  END vr2q[229]
  PIN vr2q[22]
    DIRECTION OUTPUT ;
    USE SIGNAL ;
    PORT
      LAYER M3 ;
        RECT  2.844 0 2.862 0.038 ;
    END
  END vr2q[22]
  PIN vr2q[230]
    DIRECTION OUTPUT ;
    USE SIGNAL ;
    PORT
      LAYER M3 ;
        RECT  29.124 0 29.142 0.038 ;
    END
  END vr2q[230]
  PIN vr2q[231]
    DIRECTION OUTPUT ;
    USE SIGNAL ;
    PORT
      LAYER M5 ;
        RECT  29.232 0 29.256 0.084 ;
    END
  END vr2q[231]
  PIN vr2q[232]
    DIRECTION OUTPUT ;
    USE SIGNAL ;
    PORT
      LAYER M3 ;
        RECT  29.376 0 29.394 0.038 ;
    END
  END vr2q[232]
  PIN vr2q[233]
    DIRECTION OUTPUT ;
    USE SIGNAL ;
    PORT
      LAYER M5 ;
        RECT  29.472 0 29.496 0.084 ;
    END
  END vr2q[233]
  PIN vr2q[234]
    DIRECTION OUTPUT ;
    USE SIGNAL ;
    PORT
      LAYER M3 ;
        RECT  29.628 0 29.646 0.038 ;
    END
  END vr2q[234]
  PIN vr2q[235]
    DIRECTION OUTPUT ;
    USE SIGNAL ;
    PORT
      LAYER M5 ;
        RECT  29.712 0 29.736 0.084 ;
    END
  END vr2q[235]
  PIN vr2q[236]
    DIRECTION OUTPUT ;
    USE SIGNAL ;
    PORT
      LAYER M3 ;
        RECT  29.88 0 29.898 0.038 ;
    END
  END vr2q[236]
  PIN vr2q[237]
    DIRECTION OUTPUT ;
    USE SIGNAL ;
    PORT
      LAYER M5 ;
        RECT  30 0 30.024 0.084 ;
    END
  END vr2q[237]
  PIN vr2q[238]
    DIRECTION OUTPUT ;
    USE SIGNAL ;
    PORT
      LAYER M3 ;
        RECT  30.132 0 30.15 0.038 ;
    END
  END vr2q[238]
  PIN vr2q[239]
    DIRECTION OUTPUT ;
    USE SIGNAL ;
    PORT
      LAYER M5 ;
        RECT  30.24 0 30.264 0.084 ;
    END
  END vr2q[239]
  PIN vr2q[23]
    DIRECTION OUTPUT ;
    USE SIGNAL ;
    PORT
      LAYER M5 ;
        RECT  2.976 0 3 0.084 ;
    END
  END vr2q[23]
  PIN vr2q[240]
    DIRECTION OUTPUT ;
    USE SIGNAL ;
    PORT
      LAYER M3 ;
        RECT  30.384 0 30.402 0.038 ;
    END
  END vr2q[240]
  PIN vr2q[241]
    DIRECTION OUTPUT ;
    USE SIGNAL ;
    PORT
      LAYER M5 ;
        RECT  30.48 0 30.504 0.084 ;
    END
  END vr2q[241]
  PIN vr2q[242]
    DIRECTION OUTPUT ;
    USE SIGNAL ;
    PORT
      LAYER M3 ;
        RECT  30.636 0 30.654 0.038 ;
    END
  END vr2q[242]
  PIN vr2q[243]
    DIRECTION OUTPUT ;
    USE SIGNAL ;
    PORT
      LAYER M5 ;
        RECT  30.768 0 30.792 0.084 ;
    END
  END vr2q[243]
  PIN vr2q[244]
    DIRECTION OUTPUT ;
    USE SIGNAL ;
    PORT
      LAYER M3 ;
        RECT  30.888 0 30.906 0.038 ;
    END
  END vr2q[244]
  PIN vr2q[245]
    DIRECTION OUTPUT ;
    USE SIGNAL ;
    PORT
      LAYER M5 ;
        RECT  31.008 0 31.032 0.084 ;
    END
  END vr2q[245]
  PIN vr2q[246]
    DIRECTION OUTPUT ;
    USE SIGNAL ;
    PORT
      LAYER M3 ;
        RECT  31.14 0 31.158 0.038 ;
    END
  END vr2q[246]
  PIN vr2q[247]
    DIRECTION OUTPUT ;
    USE SIGNAL ;
    PORT
      LAYER M5 ;
        RECT  31.248 0 31.272 0.084 ;
    END
  END vr2q[247]
  PIN vr2q[248]
    DIRECTION OUTPUT ;
    USE SIGNAL ;
    PORT
      LAYER M3 ;
        RECT  31.392 0 31.41 0.038 ;
    END
  END vr2q[248]
  PIN vr2q[249]
    DIRECTION OUTPUT ;
    USE SIGNAL ;
    PORT
      LAYER M5 ;
        RECT  31.488 0 31.512 0.084 ;
    END
  END vr2q[249]
  PIN vr2q[24]
    DIRECTION OUTPUT ;
    USE SIGNAL ;
    PORT
      LAYER M3 ;
        RECT  3.096 0 3.114 0.038 ;
    END
  END vr2q[24]
  PIN vr2q[250]
    DIRECTION OUTPUT ;
    USE SIGNAL ;
    PORT
      LAYER M3 ;
        RECT  31.644 0 31.662 0.038 ;
    END
  END vr2q[250]
  PIN vr2q[251]
    DIRECTION OUTPUT ;
    USE SIGNAL ;
    PORT
      LAYER M5 ;
        RECT  31.776 0 31.8 0.084 ;
    END
  END vr2q[251]
  PIN vr2q[252]
    DIRECTION OUTPUT ;
    USE SIGNAL ;
    PORT
      LAYER M3 ;
        RECT  31.896 0 31.914 0.038 ;
    END
  END vr2q[252]
  PIN vr2q[253]
    DIRECTION OUTPUT ;
    USE SIGNAL ;
    PORT
      LAYER M5 ;
        RECT  32.016 0 32.04 0.084 ;
    END
  END vr2q[253]
  PIN vr2q[254]
    DIRECTION OUTPUT ;
    USE SIGNAL ;
    PORT
      LAYER M3 ;
        RECT  32.148 0 32.166 0.038 ;
    END
  END vr2q[254]
  PIN vr2q[255]
    DIRECTION OUTPUT ;
    USE SIGNAL ;
    PORT
      LAYER M5 ;
        RECT  32.256 0 32.28 0.084 ;
    END
  END vr2q[255]
  PIN vr2q[256]
    DIRECTION OUTPUT ;
    USE SIGNAL ;
    PORT
      LAYER M3 ;
        RECT  32.4 0 32.418 0.038 ;
    END
  END vr2q[256]
  PIN vr2q[257]
    DIRECTION OUTPUT ;
    USE SIGNAL ;
    PORT
      LAYER M5 ;
        RECT  32.496 0 32.52 0.084 ;
    END
  END vr2q[257]
  PIN vr2q[258]
    DIRECTION OUTPUT ;
    USE SIGNAL ;
    PORT
      LAYER M3 ;
        RECT  32.652 0 32.67 0.038 ;
    END
  END vr2q[258]
  PIN vr2q[259]
    DIRECTION OUTPUT ;
    USE SIGNAL ;
    PORT
      LAYER M5 ;
        RECT  32.784 0 32.808 0.084 ;
    END
  END vr2q[259]
  PIN vr2q[25]
    DIRECTION OUTPUT ;
    USE SIGNAL ;
    PORT
      LAYER M5 ;
        RECT  3.216 0 3.24 0.084 ;
    END
  END vr2q[25]
  PIN vr2q[260]
    DIRECTION OUTPUT ;
    USE SIGNAL ;
    PORT
      LAYER M3 ;
        RECT  32.904 0 32.922 0.038 ;
    END
  END vr2q[260]
  PIN vr2q[261]
    DIRECTION OUTPUT ;
    USE SIGNAL ;
    PORT
      LAYER M5 ;
        RECT  33.024 0 33.048 0.084 ;
    END
  END vr2q[261]
  PIN vr2q[262]
    DIRECTION OUTPUT ;
    USE SIGNAL ;
    PORT
      LAYER M3 ;
        RECT  33.156 0 33.174 0.038 ;
    END
  END vr2q[262]
  PIN vr2q[263]
    DIRECTION OUTPUT ;
    USE SIGNAL ;
    PORT
      LAYER M5 ;
        RECT  33.264 0 33.288 0.084 ;
    END
  END vr2q[263]
  PIN vr2q[264]
    DIRECTION OUTPUT ;
    USE SIGNAL ;
    PORT
      LAYER M3 ;
        RECT  33.408 0 33.426 0.038 ;
    END
  END vr2q[264]
  PIN vr2q[265]
    DIRECTION OUTPUT ;
    USE SIGNAL ;
    PORT
      LAYER M5 ;
        RECT  33.504 0 33.528 0.084 ;
    END
  END vr2q[265]
  PIN vr2q[266]
    DIRECTION OUTPUT ;
    USE SIGNAL ;
    PORT
      LAYER M3 ;
        RECT  33.66 0 33.678 0.038 ;
    END
  END vr2q[266]
  PIN vr2q[267]
    DIRECTION OUTPUT ;
    USE SIGNAL ;
    PORT
      LAYER M5 ;
        RECT  33.792 0 33.816 0.084 ;
    END
  END vr2q[267]
  PIN vr2q[268]
    DIRECTION OUTPUT ;
    USE SIGNAL ;
    PORT
      LAYER M3 ;
        RECT  33.912 0 33.93 0.038 ;
    END
  END vr2q[268]
  PIN vr2q[269]
    DIRECTION OUTPUT ;
    USE SIGNAL ;
    PORT
      LAYER M5 ;
        RECT  34.032 0 34.056 0.084 ;
    END
  END vr2q[269]
  PIN vr2q[26]
    DIRECTION OUTPUT ;
    USE SIGNAL ;
    PORT
      LAYER M3 ;
        RECT  3.348 0 3.366 0.038 ;
    END
  END vr2q[26]
  PIN vr2q[270]
    DIRECTION OUTPUT ;
    USE SIGNAL ;
    PORT
      LAYER M3 ;
        RECT  34.164 0 34.182 0.038 ;
    END
  END vr2q[270]
  PIN vr2q[271]
    DIRECTION OUTPUT ;
    USE SIGNAL ;
    PORT
      LAYER M5 ;
        RECT  34.272 0 34.296 0.084 ;
    END
  END vr2q[271]
  PIN vr2q[272]
    DIRECTION OUTPUT ;
    USE SIGNAL ;
    PORT
      LAYER M3 ;
        RECT  34.416 0 34.434 0.038 ;
    END
  END vr2q[272]
  PIN vr2q[273]
    DIRECTION OUTPUT ;
    USE SIGNAL ;
    PORT
      LAYER M5 ;
        RECT  34.512 0 34.536 0.084 ;
    END
  END vr2q[273]
  PIN vr2q[274]
    DIRECTION OUTPUT ;
    USE SIGNAL ;
    PORT
      LAYER M3 ;
        RECT  34.668 0 34.686 0.038 ;
    END
  END vr2q[274]
  PIN vr2q[275]
    DIRECTION OUTPUT ;
    USE SIGNAL ;
    PORT
      LAYER M5 ;
        RECT  34.8 0 34.824 0.084 ;
    END
  END vr2q[275]
  PIN vr2q[276]
    DIRECTION OUTPUT ;
    USE SIGNAL ;
    PORT
      LAYER M3 ;
        RECT  34.92 0 34.938 0.038 ;
    END
  END vr2q[276]
  PIN vr2q[277]
    DIRECTION OUTPUT ;
    USE SIGNAL ;
    PORT
      LAYER M5 ;
        RECT  35.04 0 35.064 0.084 ;
    END
  END vr2q[277]
  PIN vr2q[278]
    DIRECTION OUTPUT ;
    USE SIGNAL ;
    PORT
      LAYER M3 ;
        RECT  35.172 0 35.19 0.038 ;
    END
  END vr2q[278]
  PIN vr2q[279]
    DIRECTION OUTPUT ;
    USE SIGNAL ;
    PORT
      LAYER M5 ;
        RECT  35.28 0 35.304 0.084 ;
    END
  END vr2q[279]
  PIN vr2q[27]
    DIRECTION OUTPUT ;
    USE SIGNAL ;
    PORT
      LAYER M5 ;
        RECT  3.456 0 3.48 0.084 ;
    END
  END vr2q[27]
  PIN vr2q[280]
    DIRECTION OUTPUT ;
    USE SIGNAL ;
    PORT
      LAYER M3 ;
        RECT  35.424 0 35.442 0.038 ;
    END
  END vr2q[280]
  PIN vr2q[281]
    DIRECTION OUTPUT ;
    USE SIGNAL ;
    PORT
      LAYER M5 ;
        RECT  35.568 0 35.592 0.084 ;
    END
  END vr2q[281]
  PIN vr2q[282]
    DIRECTION OUTPUT ;
    USE SIGNAL ;
    PORT
      LAYER M3 ;
        RECT  35.676 0 35.694 0.038 ;
    END
  END vr2q[282]
  PIN vr2q[283]
    DIRECTION OUTPUT ;
    USE SIGNAL ;
    PORT
      LAYER M5 ;
        RECT  35.808 0 35.832 0.084 ;
    END
  END vr2q[283]
  PIN vr2q[284]
    DIRECTION OUTPUT ;
    USE SIGNAL ;
    PORT
      LAYER M3 ;
        RECT  35.928 0 35.946 0.038 ;
    END
  END vr2q[284]
  PIN vr2q[285]
    DIRECTION OUTPUT ;
    USE SIGNAL ;
    PORT
      LAYER M5 ;
        RECT  36.048 0 36.072 0.084 ;
    END
  END vr2q[285]
  PIN vr2q[286]
    DIRECTION OUTPUT ;
    USE SIGNAL ;
    PORT
      LAYER M3 ;
        RECT  36.18 0 36.198 0.038 ;
    END
  END vr2q[286]
  PIN vr2q[287]
    DIRECTION OUTPUT ;
    USE SIGNAL ;
    PORT
      LAYER M5 ;
        RECT  36.288 0 36.312 0.084 ;
    END
  END vr2q[287]
  PIN vr2q[288]
    DIRECTION OUTPUT ;
    USE SIGNAL ;
    PORT
      LAYER M3 ;
        RECT  36.432 0 36.45 0.038 ;
    END
  END vr2q[288]
  PIN vr2q[289]
    DIRECTION OUTPUT ;
    USE SIGNAL ;
    PORT
      LAYER M5 ;
        RECT  36.576 0 36.6 0.084 ;
    END
  END vr2q[289]
  PIN vr2q[28]
    DIRECTION OUTPUT ;
    USE SIGNAL ;
    PORT
      LAYER M3 ;
        RECT  3.6 0 3.618 0.038 ;
    END
  END vr2q[28]
  PIN vr2q[290]
    DIRECTION OUTPUT ;
    USE SIGNAL ;
    PORT
      LAYER M3 ;
        RECT  36.684 0 36.702 0.038 ;
    END
  END vr2q[290]
  PIN vr2q[291]
    DIRECTION OUTPUT ;
    USE SIGNAL ;
    PORT
      LAYER M5 ;
        RECT  36.816 0 36.84 0.084 ;
    END
  END vr2q[291]
  PIN vr2q[292]
    DIRECTION OUTPUT ;
    USE SIGNAL ;
    PORT
      LAYER M3 ;
        RECT  36.936 0 36.954 0.038 ;
    END
  END vr2q[292]
  PIN vr2q[293]
    DIRECTION OUTPUT ;
    USE SIGNAL ;
    PORT
      LAYER M5 ;
        RECT  37.056 0 37.08 0.084 ;
    END
  END vr2q[293]
  PIN vr2q[294]
    DIRECTION OUTPUT ;
    USE SIGNAL ;
    PORT
      LAYER M3 ;
        RECT  37.188 0 37.206 0.038 ;
    END
  END vr2q[294]
  PIN vr2q[295]
    DIRECTION OUTPUT ;
    USE SIGNAL ;
    PORT
      LAYER M5 ;
        RECT  37.296 0 37.32 0.084 ;
    END
  END vr2q[295]
  PIN vr2q[296]
    DIRECTION OUTPUT ;
    USE SIGNAL ;
    PORT
      LAYER M3 ;
        RECT  37.44 0 37.458 0.038 ;
    END
  END vr2q[296]
  PIN vr2q[297]
    DIRECTION OUTPUT ;
    USE SIGNAL ;
    PORT
      LAYER M5 ;
        RECT  37.584 0 37.608 0.084 ;
    END
  END vr2q[297]
  PIN vr2q[298]
    DIRECTION OUTPUT ;
    USE SIGNAL ;
    PORT
      LAYER M3 ;
        RECT  37.692 0 37.71 0.038 ;
    END
  END vr2q[298]
  PIN vr2q[299]
    DIRECTION OUTPUT ;
    USE SIGNAL ;
    PORT
      LAYER M5 ;
        RECT  37.824 0 37.848 0.084 ;
    END
  END vr2q[299]
  PIN vr2q[29]
    DIRECTION OUTPUT ;
    USE SIGNAL ;
    PORT
      LAYER M5 ;
        RECT  3.696 0 3.72 0.084 ;
    END
  END vr2q[29]
  PIN vr2q[2]
    DIRECTION OUTPUT ;
    USE SIGNAL ;
    PORT
      LAYER M3 ;
        RECT  0.324 0 0.342 0.038 ;
    END
  END vr2q[2]
  PIN vr2q[300]
    DIRECTION OUTPUT ;
    USE SIGNAL ;
    PORT
      LAYER M3 ;
        RECT  37.944 0 37.962 0.038 ;
    END
  END vr2q[300]
  PIN vr2q[301]
    DIRECTION OUTPUT ;
    USE SIGNAL ;
    PORT
      LAYER M5 ;
        RECT  38.064 0 38.088 0.084 ;
    END
  END vr2q[301]
  PIN vr2q[302]
    DIRECTION OUTPUT ;
    USE SIGNAL ;
    PORT
      LAYER M3 ;
        RECT  38.196 0 38.214 0.038 ;
    END
  END vr2q[302]
  PIN vr2q[303]
    DIRECTION OUTPUT ;
    USE SIGNAL ;
    PORT
      LAYER M5 ;
        RECT  38.304 0 38.328 0.084 ;
    END
  END vr2q[303]
  PIN vr2q[304]
    DIRECTION OUTPUT ;
    USE SIGNAL ;
    PORT
      LAYER M3 ;
        RECT  38.448 0 38.466 0.038 ;
    END
  END vr2q[304]
  PIN vr2q[305]
    DIRECTION OUTPUT ;
    USE SIGNAL ;
    PORT
      LAYER M5 ;
        RECT  38.592 0 38.616 0.084 ;
    END
  END vr2q[305]
  PIN vr2q[306]
    DIRECTION OUTPUT ;
    USE SIGNAL ;
    PORT
      LAYER M3 ;
        RECT  38.7 0 38.718 0.038 ;
    END
  END vr2q[306]
  PIN vr2q[307]
    DIRECTION OUTPUT ;
    USE SIGNAL ;
    PORT
      LAYER M5 ;
        RECT  38.832 0 38.856 0.084 ;
    END
  END vr2q[307]
  PIN vr2q[308]
    DIRECTION OUTPUT ;
    USE SIGNAL ;
    PORT
      LAYER M3 ;
        RECT  38.952 0 38.97 0.038 ;
    END
  END vr2q[308]
  PIN vr2q[309]
    DIRECTION OUTPUT ;
    USE SIGNAL ;
    PORT
      LAYER M5 ;
        RECT  39.072 0 39.096 0.084 ;
    END
  END vr2q[309]
  PIN vr2q[30]
    DIRECTION OUTPUT ;
    USE SIGNAL ;
    PORT
      LAYER M3 ;
        RECT  3.852 0 3.87 0.038 ;
    END
  END vr2q[30]
  PIN vr2q[310]
    DIRECTION OUTPUT ;
    USE SIGNAL ;
    PORT
      LAYER M3 ;
        RECT  39.204 0 39.222 0.038 ;
    END
  END vr2q[310]
  PIN vr2q[311]
    DIRECTION OUTPUT ;
    USE SIGNAL ;
    PORT
      LAYER M5 ;
        RECT  39.312 0 39.336 0.084 ;
    END
  END vr2q[311]
  PIN vr2q[312]
    DIRECTION OUTPUT ;
    USE SIGNAL ;
    PORT
      LAYER M3 ;
        RECT  39.456 0 39.474 0.038 ;
    END
  END vr2q[312]
  PIN vr2q[313]
    DIRECTION OUTPUT ;
    USE SIGNAL ;
    PORT
      LAYER M5 ;
        RECT  39.6 0 39.624 0.084 ;
    END
  END vr2q[313]
  PIN vr2q[314]
    DIRECTION OUTPUT ;
    USE SIGNAL ;
    PORT
      LAYER M3 ;
        RECT  39.708 0 39.726 0.038 ;
    END
  END vr2q[314]
  PIN vr2q[315]
    DIRECTION OUTPUT ;
    USE SIGNAL ;
    PORT
      LAYER M5 ;
        RECT  39.84 0 39.864 0.084 ;
    END
  END vr2q[315]
  PIN vr2q[316]
    DIRECTION OUTPUT ;
    USE SIGNAL ;
    PORT
      LAYER M3 ;
        RECT  39.96 0 39.978 0.038 ;
    END
  END vr2q[316]
  PIN vr2q[317]
    DIRECTION OUTPUT ;
    USE SIGNAL ;
    PORT
      LAYER M5 ;
        RECT  40.08 0 40.104 0.084 ;
    END
  END vr2q[317]
  PIN vr2q[318]
    DIRECTION OUTPUT ;
    USE SIGNAL ;
    PORT
      LAYER M3 ;
        RECT  40.212 0 40.23 0.038 ;
    END
  END vr2q[318]
  PIN vr2q[319]
    DIRECTION OUTPUT ;
    USE SIGNAL ;
    PORT
      LAYER M5 ;
        RECT  40.368 0 40.392 0.084 ;
    END
  END vr2q[319]
  PIN vr2q[31]
    DIRECTION OUTPUT ;
    USE SIGNAL ;
    PORT
      LAYER M5 ;
        RECT  3.984 0 4.008 0.084 ;
    END
  END vr2q[31]
  PIN vr2q[320]
    DIRECTION OUTPUT ;
    USE SIGNAL ;
    PORT
      LAYER M3 ;
        RECT  40.464 0 40.482 0.038 ;
    END
  END vr2q[320]
  PIN vr2q[321]
    DIRECTION OUTPUT ;
    USE SIGNAL ;
    PORT
      LAYER M5 ;
        RECT  40.608 0 40.632 0.084 ;
    END
  END vr2q[321]
  PIN vr2q[322]
    DIRECTION OUTPUT ;
    USE SIGNAL ;
    PORT
      LAYER M3 ;
        RECT  40.716 0 40.734 0.038 ;
    END
  END vr2q[322]
  PIN vr2q[323]
    DIRECTION OUTPUT ;
    USE SIGNAL ;
    PORT
      LAYER M5 ;
        RECT  40.848 0 40.872 0.084 ;
    END
  END vr2q[323]
  PIN vr2q[324]
    DIRECTION OUTPUT ;
    USE SIGNAL ;
    PORT
      LAYER M3 ;
        RECT  40.968 0 40.986 0.038 ;
    END
  END vr2q[324]
  PIN vr2q[325]
    DIRECTION OUTPUT ;
    USE SIGNAL ;
    PORT
      LAYER M5 ;
        RECT  41.088 0 41.112 0.084 ;
    END
  END vr2q[325]
  PIN vr2q[326]
    DIRECTION OUTPUT ;
    USE SIGNAL ;
    PORT
      LAYER M3 ;
        RECT  41.22 0 41.238 0.038 ;
    END
  END vr2q[326]
  PIN vr2q[327]
    DIRECTION OUTPUT ;
    USE SIGNAL ;
    PORT
      LAYER M5 ;
        RECT  41.376 0 41.4 0.084 ;
    END
  END vr2q[327]
  PIN vr2q[328]
    DIRECTION OUTPUT ;
    USE SIGNAL ;
    PORT
      LAYER M3 ;
        RECT  41.472 0 41.49 0.038 ;
    END
  END vr2q[328]
  PIN vr2q[329]
    DIRECTION OUTPUT ;
    USE SIGNAL ;
    PORT
      LAYER M5 ;
        RECT  41.616 0 41.64 0.084 ;
    END
  END vr2q[329]
  PIN vr2q[32]
    DIRECTION OUTPUT ;
    USE SIGNAL ;
    PORT
      LAYER M3 ;
        RECT  4.104 0 4.122 0.038 ;
    END
  END vr2q[32]
  PIN vr2q[330]
    DIRECTION OUTPUT ;
    USE SIGNAL ;
    PORT
      LAYER M3 ;
        RECT  41.724 0 41.742 0.038 ;
    END
  END vr2q[330]
  PIN vr2q[331]
    DIRECTION OUTPUT ;
    USE SIGNAL ;
    PORT
      LAYER M5 ;
        RECT  41.856 0 41.88 0.084 ;
    END
  END vr2q[331]
  PIN vr2q[332]
    DIRECTION OUTPUT ;
    USE SIGNAL ;
    PORT
      LAYER M3 ;
        RECT  41.976 0 41.994 0.038 ;
    END
  END vr2q[332]
  PIN vr2q[333]
    DIRECTION OUTPUT ;
    USE SIGNAL ;
    PORT
      LAYER M5 ;
        RECT  42.096 0 42.12 0.084 ;
    END
  END vr2q[333]
  PIN vr2q[334]
    DIRECTION OUTPUT ;
    USE SIGNAL ;
    PORT
      LAYER M3 ;
        RECT  42.228 0 42.246 0.038 ;
    END
  END vr2q[334]
  PIN vr2q[335]
    DIRECTION OUTPUT ;
    USE SIGNAL ;
    PORT
      LAYER M5 ;
        RECT  42.384 0 42.408 0.084 ;
    END
  END vr2q[335]
  PIN vr2q[336]
    DIRECTION OUTPUT ;
    USE SIGNAL ;
    PORT
      LAYER M3 ;
        RECT  42.48 0 42.498 0.038 ;
    END
  END vr2q[336]
  PIN vr2q[337]
    DIRECTION OUTPUT ;
    USE SIGNAL ;
    PORT
      LAYER M5 ;
        RECT  42.624 0 42.648 0.084 ;
    END
  END vr2q[337]
  PIN vr2q[338]
    DIRECTION OUTPUT ;
    USE SIGNAL ;
    PORT
      LAYER M3 ;
        RECT  42.732 0 42.75 0.038 ;
    END
  END vr2q[338]
  PIN vr2q[339]
    DIRECTION OUTPUT ;
    USE SIGNAL ;
    PORT
      LAYER M5 ;
        RECT  42.864 0 42.888 0.084 ;
    END
  END vr2q[339]
  PIN vr2q[33]
    DIRECTION OUTPUT ;
    USE SIGNAL ;
    PORT
      LAYER M5 ;
        RECT  4.224 0 4.248 0.084 ;
    END
  END vr2q[33]
  PIN vr2q[340]
    DIRECTION OUTPUT ;
    USE SIGNAL ;
    PORT
      LAYER M3 ;
        RECT  43.02 0 43.038 0.038 ;
    END
  END vr2q[340]
  PIN vr2q[341]
    DIRECTION OUTPUT ;
    USE SIGNAL ;
    PORT
      LAYER M5 ;
        RECT  43.104 0 43.128 0.084 ;
    END
  END vr2q[341]
  PIN vr2q[342]
    DIRECTION OUTPUT ;
    USE SIGNAL ;
    PORT
      LAYER M3 ;
        RECT  43.272 0 43.29 0.038 ;
    END
  END vr2q[342]
  PIN vr2q[343]
    DIRECTION OUTPUT ;
    USE SIGNAL ;
    PORT
      LAYER M5 ;
        RECT  43.392 0 43.416 0.084 ;
    END
  END vr2q[343]
  PIN vr2q[344]
    DIRECTION OUTPUT ;
    USE SIGNAL ;
    PORT
      LAYER M3 ;
        RECT  43.524 0 43.542 0.038 ;
    END
  END vr2q[344]
  PIN vr2q[345]
    DIRECTION OUTPUT ;
    USE SIGNAL ;
    PORT
      LAYER M5 ;
        RECT  43.632 0 43.656 0.084 ;
    END
  END vr2q[345]
  PIN vr2q[346]
    DIRECTION OUTPUT ;
    USE SIGNAL ;
    PORT
      LAYER M3 ;
        RECT  43.776 0 43.794 0.038 ;
    END
  END vr2q[346]
  PIN vr2q[347]
    DIRECTION OUTPUT ;
    USE SIGNAL ;
    PORT
      LAYER M5 ;
        RECT  43.872 0 43.896 0.084 ;
    END
  END vr2q[347]
  PIN vr2q[348]
    DIRECTION OUTPUT ;
    USE SIGNAL ;
    PORT
      LAYER M3 ;
        RECT  44.028 0 44.046 0.038 ;
    END
  END vr2q[348]
  PIN vr2q[349]
    DIRECTION OUTPUT ;
    USE SIGNAL ;
    PORT
      LAYER M5 ;
        RECT  44.112 0 44.136 0.084 ;
    END
  END vr2q[349]
  PIN vr2q[34]
    DIRECTION OUTPUT ;
    USE SIGNAL ;
    PORT
      LAYER M3 ;
        RECT  4.356 0 4.374 0.038 ;
    END
  END vr2q[34]
  PIN vr2q[350]
    DIRECTION OUTPUT ;
    USE SIGNAL ;
    PORT
      LAYER M3 ;
        RECT  44.28 0 44.298 0.038 ;
    END
  END vr2q[350]
  PIN vr2q[351]
    DIRECTION OUTPUT ;
    USE SIGNAL ;
    PORT
      LAYER M5 ;
        RECT  44.4 0 44.424 0.084 ;
    END
  END vr2q[351]
  PIN vr2q[352]
    DIRECTION OUTPUT ;
    USE SIGNAL ;
    PORT
      LAYER M3 ;
        RECT  44.532 0 44.55 0.038 ;
    END
  END vr2q[352]
  PIN vr2q[353]
    DIRECTION OUTPUT ;
    USE SIGNAL ;
    PORT
      LAYER M5 ;
        RECT  44.64 0 44.664 0.084 ;
    END
  END vr2q[353]
  PIN vr2q[354]
    DIRECTION OUTPUT ;
    USE SIGNAL ;
    PORT
      LAYER M3 ;
        RECT  44.784 0 44.802 0.038 ;
    END
  END vr2q[354]
  PIN vr2q[355]
    DIRECTION OUTPUT ;
    USE SIGNAL ;
    PORT
      LAYER M5 ;
        RECT  44.88 0 44.904 0.084 ;
    END
  END vr2q[355]
  PIN vr2q[356]
    DIRECTION OUTPUT ;
    USE SIGNAL ;
    PORT
      LAYER M3 ;
        RECT  45.036 0 45.054 0.038 ;
    END
  END vr2q[356]
  PIN vr2q[357]
    DIRECTION OUTPUT ;
    USE SIGNAL ;
    PORT
      LAYER M5 ;
        RECT  45.168 0 45.192 0.084 ;
    END
  END vr2q[357]
  PIN vr2q[358]
    DIRECTION OUTPUT ;
    USE SIGNAL ;
    PORT
      LAYER M3 ;
        RECT  45.288 0 45.306 0.038 ;
    END
  END vr2q[358]
  PIN vr2q[359]
    DIRECTION OUTPUT ;
    USE SIGNAL ;
    PORT
      LAYER M5 ;
        RECT  45.408 0 45.432 0.084 ;
    END
  END vr2q[359]
  PIN vr2q[35]
    DIRECTION OUTPUT ;
    USE SIGNAL ;
    PORT
      LAYER M5 ;
        RECT  4.464 0 4.488 0.084 ;
    END
  END vr2q[35]
  PIN vr2q[360]
    DIRECTION OUTPUT ;
    USE SIGNAL ;
    PORT
      LAYER M3 ;
        RECT  45.54 0 45.558 0.038 ;
    END
  END vr2q[360]
  PIN vr2q[361]
    DIRECTION OUTPUT ;
    USE SIGNAL ;
    PORT
      LAYER M5 ;
        RECT  45.648 0 45.672 0.084 ;
    END
  END vr2q[361]
  PIN vr2q[362]
    DIRECTION OUTPUT ;
    USE SIGNAL ;
    PORT
      LAYER M3 ;
        RECT  45.792 0 45.81 0.038 ;
    END
  END vr2q[362]
  PIN vr2q[363]
    DIRECTION OUTPUT ;
    USE SIGNAL ;
    PORT
      LAYER M5 ;
        RECT  45.888 0 45.912 0.084 ;
    END
  END vr2q[363]
  PIN vr2q[364]
    DIRECTION OUTPUT ;
    USE SIGNAL ;
    PORT
      LAYER M3 ;
        RECT  46.044 0 46.062 0.038 ;
    END
  END vr2q[364]
  PIN vr2q[365]
    DIRECTION OUTPUT ;
    USE SIGNAL ;
    PORT
      LAYER M5 ;
        RECT  46.176 0 46.2 0.084 ;
    END
  END vr2q[365]
  PIN vr2q[366]
    DIRECTION OUTPUT ;
    USE SIGNAL ;
    PORT
      LAYER M3 ;
        RECT  46.296 0 46.314 0.038 ;
    END
  END vr2q[366]
  PIN vr2q[367]
    DIRECTION OUTPUT ;
    USE SIGNAL ;
    PORT
      LAYER M5 ;
        RECT  46.416 0 46.44 0.084 ;
    END
  END vr2q[367]
  PIN vr2q[368]
    DIRECTION OUTPUT ;
    USE SIGNAL ;
    PORT
      LAYER M3 ;
        RECT  46.548 0 46.566 0.038 ;
    END
  END vr2q[368]
  PIN vr2q[369]
    DIRECTION OUTPUT ;
    USE SIGNAL ;
    PORT
      LAYER M5 ;
        RECT  46.656 0 46.68 0.084 ;
    END
  END vr2q[369]
  PIN vr2q[36]
    DIRECTION OUTPUT ;
    USE SIGNAL ;
    PORT
      LAYER M3 ;
        RECT  4.608 0 4.626 0.038 ;
    END
  END vr2q[36]
  PIN vr2q[370]
    DIRECTION OUTPUT ;
    USE SIGNAL ;
    PORT
      LAYER M3 ;
        RECT  46.8 0 46.818 0.038 ;
    END
  END vr2q[370]
  PIN vr2q[371]
    DIRECTION OUTPUT ;
    USE SIGNAL ;
    PORT
      LAYER M5 ;
        RECT  46.896 0 46.92 0.084 ;
    END
  END vr2q[371]
  PIN vr2q[372]
    DIRECTION OUTPUT ;
    USE SIGNAL ;
    PORT
      LAYER M3 ;
        RECT  47.052 0 47.07 0.038 ;
    END
  END vr2q[372]
  PIN vr2q[373]
    DIRECTION OUTPUT ;
    USE SIGNAL ;
    PORT
      LAYER M5 ;
        RECT  47.184 0 47.208 0.084 ;
    END
  END vr2q[373]
  PIN vr2q[374]
    DIRECTION OUTPUT ;
    USE SIGNAL ;
    PORT
      LAYER M3 ;
        RECT  47.304 0 47.322 0.038 ;
    END
  END vr2q[374]
  PIN vr2q[375]
    DIRECTION OUTPUT ;
    USE SIGNAL ;
    PORT
      LAYER M5 ;
        RECT  47.424 0 47.448 0.084 ;
    END
  END vr2q[375]
  PIN vr2q[376]
    DIRECTION OUTPUT ;
    USE SIGNAL ;
    PORT
      LAYER M3 ;
        RECT  47.556 0 47.574 0.038 ;
    END
  END vr2q[376]
  PIN vr2q[377]
    DIRECTION OUTPUT ;
    USE SIGNAL ;
    PORT
      LAYER M5 ;
        RECT  47.664 0 47.688 0.084 ;
    END
  END vr2q[377]
  PIN vr2q[378]
    DIRECTION OUTPUT ;
    USE SIGNAL ;
    PORT
      LAYER M3 ;
        RECT  47.808 0 47.826 0.038 ;
    END
  END vr2q[378]
  PIN vr2q[379]
    DIRECTION OUTPUT ;
    USE SIGNAL ;
    PORT
      LAYER M5 ;
        RECT  47.904 0 47.928 0.084 ;
    END
  END vr2q[379]
  PIN vr2q[37]
    DIRECTION OUTPUT ;
    USE SIGNAL ;
    PORT
      LAYER M5 ;
        RECT  4.704 0 4.728 0.084 ;
    END
  END vr2q[37]
  PIN vr2q[380]
    DIRECTION OUTPUT ;
    USE SIGNAL ;
    PORT
      LAYER M3 ;
        RECT  48.06 0 48.078 0.038 ;
    END
  END vr2q[380]
  PIN vr2q[381]
    DIRECTION OUTPUT ;
    USE SIGNAL ;
    PORT
      LAYER M5 ;
        RECT  48.192 0 48.216 0.084 ;
    END
  END vr2q[381]
  PIN vr2q[382]
    DIRECTION OUTPUT ;
    USE SIGNAL ;
    PORT
      LAYER M3 ;
        RECT  48.312 0 48.33 0.038 ;
    END
  END vr2q[382]
  PIN vr2q[383]
    DIRECTION OUTPUT ;
    USE SIGNAL ;
    PORT
      LAYER M5 ;
        RECT  48.432 0 48.456 0.084 ;
    END
  END vr2q[383]
  PIN vr2q[384]
    DIRECTION OUTPUT ;
    USE SIGNAL ;
    PORT
      LAYER M3 ;
        RECT  48.564 0 48.582 0.038 ;
    END
  END vr2q[384]
  PIN vr2q[385]
    DIRECTION OUTPUT ;
    USE SIGNAL ;
    PORT
      LAYER M5 ;
        RECT  48.672 0 48.696 0.084 ;
    END
  END vr2q[385]
  PIN vr2q[386]
    DIRECTION OUTPUT ;
    USE SIGNAL ;
    PORT
      LAYER M3 ;
        RECT  48.816 0 48.834 0.038 ;
    END
  END vr2q[386]
  PIN vr2q[387]
    DIRECTION OUTPUT ;
    USE SIGNAL ;
    PORT
      LAYER M5 ;
        RECT  48.912 0 48.936 0.084 ;
    END
  END vr2q[387]
  PIN vr2q[388]
    DIRECTION OUTPUT ;
    USE SIGNAL ;
    PORT
      LAYER M3 ;
        RECT  49.068 0 49.086 0.038 ;
    END
  END vr2q[388]
  PIN vr2q[389]
    DIRECTION OUTPUT ;
    USE SIGNAL ;
    PORT
      LAYER M5 ;
        RECT  49.2 0 49.224 0.084 ;
    END
  END vr2q[389]
  PIN vr2q[38]
    DIRECTION OUTPUT ;
    USE SIGNAL ;
    PORT
      LAYER M3 ;
        RECT  4.86 0 4.878 0.038 ;
    END
  END vr2q[38]
  PIN vr2q[390]
    DIRECTION OUTPUT ;
    USE SIGNAL ;
    PORT
      LAYER M3 ;
        RECT  49.32 0 49.338 0.038 ;
    END
  END vr2q[390]
  PIN vr2q[391]
    DIRECTION OUTPUT ;
    USE SIGNAL ;
    PORT
      LAYER M5 ;
        RECT  49.44 0 49.464 0.084 ;
    END
  END vr2q[391]
  PIN vr2q[392]
    DIRECTION OUTPUT ;
    USE SIGNAL ;
    PORT
      LAYER M3 ;
        RECT  49.572 0 49.59 0.038 ;
    END
  END vr2q[392]
  PIN vr2q[393]
    DIRECTION OUTPUT ;
    USE SIGNAL ;
    PORT
      LAYER M5 ;
        RECT  49.68 0 49.704 0.084 ;
    END
  END vr2q[393]
  PIN vr2q[394]
    DIRECTION OUTPUT ;
    USE SIGNAL ;
    PORT
      LAYER M3 ;
        RECT  49.824 0 49.842 0.038 ;
    END
  END vr2q[394]
  PIN vr2q[395]
    DIRECTION OUTPUT ;
    USE SIGNAL ;
    PORT
      LAYER M5 ;
        RECT  49.968 0 49.992 0.084 ;
    END
  END vr2q[395]
  PIN vr2q[396]
    DIRECTION OUTPUT ;
    USE SIGNAL ;
    PORT
      LAYER M3 ;
        RECT  50.076 0 50.094 0.038 ;
    END
  END vr2q[396]
  PIN vr2q[397]
    DIRECTION OUTPUT ;
    USE SIGNAL ;
    PORT
      LAYER M5 ;
        RECT  50.208 0 50.232 0.084 ;
    END
  END vr2q[397]
  PIN vr2q[398]
    DIRECTION OUTPUT ;
    USE SIGNAL ;
    PORT
      LAYER M3 ;
        RECT  50.328 0 50.346 0.038 ;
    END
  END vr2q[398]
  PIN vr2q[399]
    DIRECTION OUTPUT ;
    USE SIGNAL ;
    PORT
      LAYER M5 ;
        RECT  50.448 0 50.472 0.084 ;
    END
  END vr2q[399]
  PIN vr2q[39]
    DIRECTION OUTPUT ;
    USE SIGNAL ;
    PORT
      LAYER M5 ;
        RECT  4.992 0 5.016 0.084 ;
    END
  END vr2q[39]
  PIN vr2q[3]
    DIRECTION OUTPUT ;
    USE SIGNAL ;
    PORT
      LAYER M5 ;
        RECT  0.432 0 0.456 0.084 ;
    END
  END vr2q[3]
  PIN vr2q[400]
    DIRECTION OUTPUT ;
    USE SIGNAL ;
    PORT
      LAYER M3 ;
        RECT  50.58 0 50.598 0.038 ;
    END
  END vr2q[400]
  PIN vr2q[401]
    DIRECTION OUTPUT ;
    USE SIGNAL ;
    PORT
      LAYER M5 ;
        RECT  50.688 0 50.712 0.084 ;
    END
  END vr2q[401]
  PIN vr2q[402]
    DIRECTION OUTPUT ;
    USE SIGNAL ;
    PORT
      LAYER M3 ;
        RECT  50.832 0 50.85 0.038 ;
    END
  END vr2q[402]
  PIN vr2q[403]
    DIRECTION OUTPUT ;
    USE SIGNAL ;
    PORT
      LAYER M5 ;
        RECT  50.976 0 51 0.084 ;
    END
  END vr2q[403]
  PIN vr2q[404]
    DIRECTION OUTPUT ;
    USE SIGNAL ;
    PORT
      LAYER M3 ;
        RECT  51.084 0 51.102 0.038 ;
    END
  END vr2q[404]
  PIN vr2q[405]
    DIRECTION OUTPUT ;
    USE SIGNAL ;
    PORT
      LAYER M5 ;
        RECT  51.216 0 51.24 0.084 ;
    END
  END vr2q[405]
  PIN vr2q[406]
    DIRECTION OUTPUT ;
    USE SIGNAL ;
    PORT
      LAYER M3 ;
        RECT  51.336 0 51.354 0.038 ;
    END
  END vr2q[406]
  PIN vr2q[407]
    DIRECTION OUTPUT ;
    USE SIGNAL ;
    PORT
      LAYER M5 ;
        RECT  51.456 0 51.48 0.084 ;
    END
  END vr2q[407]
  PIN vr2q[408]
    DIRECTION OUTPUT ;
    USE SIGNAL ;
    PORT
      LAYER M3 ;
        RECT  51.588 0 51.606 0.038 ;
    END
  END vr2q[408]
  PIN vr2q[409]
    DIRECTION OUTPUT ;
    USE SIGNAL ;
    PORT
      LAYER M5 ;
        RECT  51.696 0 51.72 0.084 ;
    END
  END vr2q[409]
  PIN vr2q[40]
    DIRECTION OUTPUT ;
    USE SIGNAL ;
    PORT
      LAYER M3 ;
        RECT  5.112 0 5.13 0.038 ;
    END
  END vr2q[40]
  PIN vr2q[410]
    DIRECTION OUTPUT ;
    USE SIGNAL ;
    PORT
      LAYER M3 ;
        RECT  51.84 0 51.858 0.038 ;
    END
  END vr2q[410]
  PIN vr2q[411]
    DIRECTION OUTPUT ;
    USE SIGNAL ;
    PORT
      LAYER M5 ;
        RECT  51.984 0 52.008 0.084 ;
    END
  END vr2q[411]
  PIN vr2q[412]
    DIRECTION OUTPUT ;
    USE SIGNAL ;
    PORT
      LAYER M3 ;
        RECT  52.092 0 52.11 0.038 ;
    END
  END vr2q[412]
  PIN vr2q[413]
    DIRECTION OUTPUT ;
    USE SIGNAL ;
    PORT
      LAYER M5 ;
        RECT  52.224 0 52.248 0.084 ;
    END
  END vr2q[413]
  PIN vr2q[414]
    DIRECTION OUTPUT ;
    USE SIGNAL ;
    PORT
      LAYER M3 ;
        RECT  52.344 0 52.362 0.038 ;
    END
  END vr2q[414]
  PIN vr2q[415]
    DIRECTION OUTPUT ;
    USE SIGNAL ;
    PORT
      LAYER M5 ;
        RECT  52.464 0 52.488 0.084 ;
    END
  END vr2q[415]
  PIN vr2q[416]
    DIRECTION OUTPUT ;
    USE SIGNAL ;
    PORT
      LAYER M3 ;
        RECT  52.596 0 52.614 0.038 ;
    END
  END vr2q[416]
  PIN vr2q[417]
    DIRECTION OUTPUT ;
    USE SIGNAL ;
    PORT
      LAYER M5 ;
        RECT  52.704 0 52.728 0.084 ;
    END
  END vr2q[417]
  PIN vr2q[418]
    DIRECTION OUTPUT ;
    USE SIGNAL ;
    PORT
      LAYER M3 ;
        RECT  52.848 0 52.866 0.038 ;
    END
  END vr2q[418]
  PIN vr2q[419]
    DIRECTION OUTPUT ;
    USE SIGNAL ;
    PORT
      LAYER M5 ;
        RECT  52.992 0 53.016 0.084 ;
    END
  END vr2q[419]
  PIN vr2q[41]
    DIRECTION OUTPUT ;
    USE SIGNAL ;
    PORT
      LAYER M5 ;
        RECT  5.232 0 5.256 0.084 ;
    END
  END vr2q[41]
  PIN vr2q[420]
    DIRECTION OUTPUT ;
    USE SIGNAL ;
    PORT
      LAYER M3 ;
        RECT  53.1 0 53.118 0.038 ;
    END
  END vr2q[420]
  PIN vr2q[421]
    DIRECTION OUTPUT ;
    USE SIGNAL ;
    PORT
      LAYER M5 ;
        RECT  53.232 0 53.256 0.084 ;
    END
  END vr2q[421]
  PIN vr2q[422]
    DIRECTION OUTPUT ;
    USE SIGNAL ;
    PORT
      LAYER M3 ;
        RECT  53.352 0 53.37 0.038 ;
    END
  END vr2q[422]
  PIN vr2q[423]
    DIRECTION OUTPUT ;
    USE SIGNAL ;
    PORT
      LAYER M5 ;
        RECT  53.472 0 53.496 0.084 ;
    END
  END vr2q[423]
  PIN vr2q[424]
    DIRECTION OUTPUT ;
    USE SIGNAL ;
    PORT
      LAYER M3 ;
        RECT  53.604 0 53.622 0.038 ;
    END
  END vr2q[424]
  PIN vr2q[425]
    DIRECTION OUTPUT ;
    USE SIGNAL ;
    PORT
      LAYER M5 ;
        RECT  53.712 0 53.736 0.084 ;
    END
  END vr2q[425]
  PIN vr2q[426]
    DIRECTION OUTPUT ;
    USE SIGNAL ;
    PORT
      LAYER M3 ;
        RECT  53.856 0 53.874 0.038 ;
    END
  END vr2q[426]
  PIN vr2q[427]
    DIRECTION OUTPUT ;
    USE SIGNAL ;
    PORT
      LAYER M5 ;
        RECT  54 0 54.024 0.084 ;
    END
  END vr2q[427]
  PIN vr2q[428]
    DIRECTION OUTPUT ;
    USE SIGNAL ;
    PORT
      LAYER M3 ;
        RECT  54.108 0 54.126 0.038 ;
    END
  END vr2q[428]
  PIN vr2q[429]
    DIRECTION OUTPUT ;
    USE SIGNAL ;
    PORT
      LAYER M5 ;
        RECT  54.24 0 54.264 0.084 ;
    END
  END vr2q[429]
  PIN vr2q[42]
    DIRECTION OUTPUT ;
    USE SIGNAL ;
    PORT
      LAYER M3 ;
        RECT  5.364 0 5.382 0.038 ;
    END
  END vr2q[42]
  PIN vr2q[430]
    DIRECTION OUTPUT ;
    USE SIGNAL ;
    PORT
      LAYER M3 ;
        RECT  54.36 0 54.378 0.038 ;
    END
  END vr2q[430]
  PIN vr2q[431]
    DIRECTION OUTPUT ;
    USE SIGNAL ;
    PORT
      LAYER M5 ;
        RECT  54.48 0 54.504 0.084 ;
    END
  END vr2q[431]
  PIN vr2q[432]
    DIRECTION OUTPUT ;
    USE SIGNAL ;
    PORT
      LAYER M3 ;
        RECT  54.612 0 54.63 0.038 ;
    END
  END vr2q[432]
  PIN vr2q[433]
    DIRECTION OUTPUT ;
    USE SIGNAL ;
    PORT
      LAYER M5 ;
        RECT  54.768 0 54.792 0.084 ;
    END
  END vr2q[433]
  PIN vr2q[434]
    DIRECTION OUTPUT ;
    USE SIGNAL ;
    PORT
      LAYER M3 ;
        RECT  54.864 0 54.882 0.038 ;
    END
  END vr2q[434]
  PIN vr2q[435]
    DIRECTION OUTPUT ;
    USE SIGNAL ;
    PORT
      LAYER M5 ;
        RECT  55.008 0 55.032 0.084 ;
    END
  END vr2q[435]
  PIN vr2q[436]
    DIRECTION OUTPUT ;
    USE SIGNAL ;
    PORT
      LAYER M3 ;
        RECT  55.116 0 55.134 0.038 ;
    END
  END vr2q[436]
  PIN vr2q[437]
    DIRECTION OUTPUT ;
    USE SIGNAL ;
    PORT
      LAYER M5 ;
        RECT  55.248 0 55.272 0.084 ;
    END
  END vr2q[437]
  PIN vr2q[438]
    DIRECTION OUTPUT ;
    USE SIGNAL ;
    PORT
      LAYER M3 ;
        RECT  55.368 0 55.386 0.038 ;
    END
  END vr2q[438]
  PIN vr2q[439]
    DIRECTION OUTPUT ;
    USE SIGNAL ;
    PORT
      LAYER M5 ;
        RECT  55.488 0 55.512 0.084 ;
    END
  END vr2q[439]
  PIN vr2q[43]
    DIRECTION OUTPUT ;
    USE SIGNAL ;
    PORT
      LAYER M5 ;
        RECT  5.472 0 5.496 0.084 ;
    END
  END vr2q[43]
  PIN vr2q[440]
    DIRECTION OUTPUT ;
    USE SIGNAL ;
    PORT
      LAYER M3 ;
        RECT  55.62 0 55.638 0.038 ;
    END
  END vr2q[440]
  PIN vr2q[441]
    DIRECTION OUTPUT ;
    USE SIGNAL ;
    PORT
      LAYER M5 ;
        RECT  55.776 0 55.8 0.084 ;
    END
  END vr2q[441]
  PIN vr2q[442]
    DIRECTION OUTPUT ;
    USE SIGNAL ;
    PORT
      LAYER M3 ;
        RECT  55.872 0 55.89 0.038 ;
    END
  END vr2q[442]
  PIN vr2q[443]
    DIRECTION OUTPUT ;
    USE SIGNAL ;
    PORT
      LAYER M5 ;
        RECT  56.016 0 56.04 0.084 ;
    END
  END vr2q[443]
  PIN vr2q[444]
    DIRECTION OUTPUT ;
    USE SIGNAL ;
    PORT
      LAYER M3 ;
        RECT  56.124 0 56.142 0.038 ;
    END
  END vr2q[444]
  PIN vr2q[445]
    DIRECTION OUTPUT ;
    USE SIGNAL ;
    PORT
      LAYER M5 ;
        RECT  56.256 0 56.28 0.084 ;
    END
  END vr2q[445]
  PIN vr2q[446]
    DIRECTION OUTPUT ;
    USE SIGNAL ;
    PORT
      LAYER M3 ;
        RECT  56.376 0 56.394 0.038 ;
    END
  END vr2q[446]
  PIN vr2q[447]
    DIRECTION OUTPUT ;
    USE SIGNAL ;
    PORT
      LAYER M5 ;
        RECT  56.496 0 56.52 0.084 ;
    END
  END vr2q[447]
  PIN vr2q[448]
    DIRECTION OUTPUT ;
    USE SIGNAL ;
    PORT
      LAYER M3 ;
        RECT  56.628 0 56.646 0.038 ;
    END
  END vr2q[448]
  PIN vr2q[449]
    DIRECTION OUTPUT ;
    USE SIGNAL ;
    PORT
      LAYER M5 ;
        RECT  56.784 0 56.808 0.084 ;
    END
  END vr2q[449]
  PIN vr2q[44]
    DIRECTION OUTPUT ;
    USE SIGNAL ;
    PORT
      LAYER M3 ;
        RECT  5.616 0 5.634 0.038 ;
    END
  END vr2q[44]
  PIN vr2q[450]
    DIRECTION OUTPUT ;
    USE SIGNAL ;
    PORT
      LAYER M3 ;
        RECT  56.88 0 56.898 0.038 ;
    END
  END vr2q[450]
  PIN vr2q[451]
    DIRECTION OUTPUT ;
    USE SIGNAL ;
    PORT
      LAYER M5 ;
        RECT  57.024 0 57.048 0.084 ;
    END
  END vr2q[451]
  PIN vr2q[452]
    DIRECTION OUTPUT ;
    USE SIGNAL ;
    PORT
      LAYER M3 ;
        RECT  57.132 0 57.15 0.038 ;
    END
  END vr2q[452]
  PIN vr2q[453]
    DIRECTION OUTPUT ;
    USE SIGNAL ;
    PORT
      LAYER M5 ;
        RECT  57.264 0 57.288 0.084 ;
    END
  END vr2q[453]
  PIN vr2q[454]
    DIRECTION OUTPUT ;
    USE SIGNAL ;
    PORT
      LAYER M3 ;
        RECT  57.42 0 57.438 0.038 ;
    END
  END vr2q[454]
  PIN vr2q[455]
    DIRECTION OUTPUT ;
    USE SIGNAL ;
    PORT
      LAYER M5 ;
        RECT  57.504 0 57.528 0.084 ;
    END
  END vr2q[455]
  PIN vr2q[456]
    DIRECTION OUTPUT ;
    USE SIGNAL ;
    PORT
      LAYER M3 ;
        RECT  57.672 0 57.69 0.038 ;
    END
  END vr2q[456]
  PIN vr2q[457]
    DIRECTION OUTPUT ;
    USE SIGNAL ;
    PORT
      LAYER M5 ;
        RECT  57.792 0 57.816 0.084 ;
    END
  END vr2q[457]
  PIN vr2q[458]
    DIRECTION OUTPUT ;
    USE SIGNAL ;
    PORT
      LAYER M3 ;
        RECT  57.924 0 57.942 0.038 ;
    END
  END vr2q[458]
  PIN vr2q[459]
    DIRECTION OUTPUT ;
    USE SIGNAL ;
    PORT
      LAYER M5 ;
        RECT  58.032 0 58.056 0.084 ;
    END
  END vr2q[459]
  PIN vr2q[45]
    DIRECTION OUTPUT ;
    USE SIGNAL ;
    PORT
      LAYER M5 ;
        RECT  5.712 0 5.736 0.084 ;
    END
  END vr2q[45]
  PIN vr2q[460]
    DIRECTION OUTPUT ;
    USE SIGNAL ;
    PORT
      LAYER M3 ;
        RECT  58.176 0 58.194 0.038 ;
    END
  END vr2q[460]
  PIN vr2q[461]
    DIRECTION OUTPUT ;
    USE SIGNAL ;
    PORT
      LAYER M5 ;
        RECT  58.272 0 58.296 0.084 ;
    END
  END vr2q[461]
  PIN vr2q[462]
    DIRECTION OUTPUT ;
    USE SIGNAL ;
    PORT
      LAYER M3 ;
        RECT  58.428 0 58.446 0.038 ;
    END
  END vr2q[462]
  PIN vr2q[463]
    DIRECTION OUTPUT ;
    USE SIGNAL ;
    PORT
      LAYER M5 ;
        RECT  58.512 0 58.536 0.084 ;
    END
  END vr2q[463]
  PIN vr2q[464]
    DIRECTION OUTPUT ;
    USE SIGNAL ;
    PORT
      LAYER M3 ;
        RECT  58.68 0 58.698 0.038 ;
    END
  END vr2q[464]
  PIN vr2q[465]
    DIRECTION OUTPUT ;
    USE SIGNAL ;
    PORT
      LAYER M5 ;
        RECT  58.8 0 58.824 0.084 ;
    END
  END vr2q[465]
  PIN vr2q[466]
    DIRECTION OUTPUT ;
    USE SIGNAL ;
    PORT
      LAYER M3 ;
        RECT  58.932 0 58.95 0.038 ;
    END
  END vr2q[466]
  PIN vr2q[467]
    DIRECTION OUTPUT ;
    USE SIGNAL ;
    PORT
      LAYER M5 ;
        RECT  59.04 0 59.064 0.084 ;
    END
  END vr2q[467]
  PIN vr2q[468]
    DIRECTION OUTPUT ;
    USE SIGNAL ;
    PORT
      LAYER M3 ;
        RECT  59.184 0 59.202 0.038 ;
    END
  END vr2q[468]
  PIN vr2q[469]
    DIRECTION OUTPUT ;
    USE SIGNAL ;
    PORT
      LAYER M5 ;
        RECT  59.28 0 59.304 0.084 ;
    END
  END vr2q[469]
  PIN vr2q[46]
    DIRECTION OUTPUT ;
    USE SIGNAL ;
    PORT
      LAYER M3 ;
        RECT  5.868 0 5.886 0.038 ;
    END
  END vr2q[46]
  PIN vr2q[470]
    DIRECTION OUTPUT ;
    USE SIGNAL ;
    PORT
      LAYER M3 ;
        RECT  59.436 0 59.454 0.038 ;
    END
  END vr2q[470]
  PIN vr2q[471]
    DIRECTION OUTPUT ;
    USE SIGNAL ;
    PORT
      LAYER M5 ;
        RECT  59.568 0 59.592 0.084 ;
    END
  END vr2q[471]
  PIN vr2q[472]
    DIRECTION OUTPUT ;
    USE SIGNAL ;
    PORT
      LAYER M3 ;
        RECT  59.688 0 59.706 0.038 ;
    END
  END vr2q[472]
  PIN vr2q[473]
    DIRECTION OUTPUT ;
    USE SIGNAL ;
    PORT
      LAYER M5 ;
        RECT  59.808 0 59.832 0.084 ;
    END
  END vr2q[473]
  PIN vr2q[474]
    DIRECTION OUTPUT ;
    USE SIGNAL ;
    PORT
      LAYER M3 ;
        RECT  59.94 0 59.958 0.038 ;
    END
  END vr2q[474]
  PIN vr2q[475]
    DIRECTION OUTPUT ;
    USE SIGNAL ;
    PORT
      LAYER M5 ;
        RECT  60.048 0 60.072 0.084 ;
    END
  END vr2q[475]
  PIN vr2q[476]
    DIRECTION OUTPUT ;
    USE SIGNAL ;
    PORT
      LAYER M3 ;
        RECT  60.192 0 60.21 0.038 ;
    END
  END vr2q[476]
  PIN vr2q[477]
    DIRECTION OUTPUT ;
    USE SIGNAL ;
    PORT
      LAYER M5 ;
        RECT  60.288 0 60.312 0.084 ;
    END
  END vr2q[477]
  PIN vr2q[478]
    DIRECTION OUTPUT ;
    USE SIGNAL ;
    PORT
      LAYER M3 ;
        RECT  60.444 0 60.462 0.038 ;
    END
  END vr2q[478]
  PIN vr2q[479]
    DIRECTION OUTPUT ;
    USE SIGNAL ;
    PORT
      LAYER M5 ;
        RECT  60.576 0 60.6 0.084 ;
    END
  END vr2q[479]
  PIN vr2q[47]
    DIRECTION OUTPUT ;
    USE SIGNAL ;
    PORT
      LAYER M5 ;
        RECT  6 0 6.024 0.084 ;
    END
  END vr2q[47]
  PIN vr2q[480]
    DIRECTION OUTPUT ;
    USE SIGNAL ;
    PORT
      LAYER M3 ;
        RECT  60.696 0 60.714 0.038 ;
    END
  END vr2q[480]
  PIN vr2q[481]
    DIRECTION OUTPUT ;
    USE SIGNAL ;
    PORT
      LAYER M5 ;
        RECT  60.816 0 60.84 0.084 ;
    END
  END vr2q[481]
  PIN vr2q[482]
    DIRECTION OUTPUT ;
    USE SIGNAL ;
    PORT
      LAYER M3 ;
        RECT  60.948 0 60.966 0.038 ;
    END
  END vr2q[482]
  PIN vr2q[483]
    DIRECTION OUTPUT ;
    USE SIGNAL ;
    PORT
      LAYER M5 ;
        RECT  61.056 0 61.08 0.084 ;
    END
  END vr2q[483]
  PIN vr2q[484]
    DIRECTION OUTPUT ;
    USE SIGNAL ;
    PORT
      LAYER M3 ;
        RECT  61.2 0 61.218 0.038 ;
    END
  END vr2q[484]
  PIN vr2q[485]
    DIRECTION OUTPUT ;
    USE SIGNAL ;
    PORT
      LAYER M5 ;
        RECT  61.296 0 61.32 0.084 ;
    END
  END vr2q[485]
  PIN vr2q[486]
    DIRECTION OUTPUT ;
    USE SIGNAL ;
    PORT
      LAYER M3 ;
        RECT  61.452 0 61.47 0.038 ;
    END
  END vr2q[486]
  PIN vr2q[487]
    DIRECTION OUTPUT ;
    USE SIGNAL ;
    PORT
      LAYER M5 ;
        RECT  61.584 0 61.608 0.084 ;
    END
  END vr2q[487]
  PIN vr2q[488]
    DIRECTION OUTPUT ;
    USE SIGNAL ;
    PORT
      LAYER M3 ;
        RECT  61.704 0 61.722 0.038 ;
    END
  END vr2q[488]
  PIN vr2q[489]
    DIRECTION OUTPUT ;
    USE SIGNAL ;
    PORT
      LAYER M5 ;
        RECT  61.824 0 61.848 0.084 ;
    END
  END vr2q[489]
  PIN vr2q[48]
    DIRECTION OUTPUT ;
    USE SIGNAL ;
    PORT
      LAYER M3 ;
        RECT  6.12 0 6.138 0.038 ;
    END
  END vr2q[48]
  PIN vr2q[490]
    DIRECTION OUTPUT ;
    USE SIGNAL ;
    PORT
      LAYER M3 ;
        RECT  61.956 0 61.974 0.038 ;
    END
  END vr2q[490]
  PIN vr2q[491]
    DIRECTION OUTPUT ;
    USE SIGNAL ;
    PORT
      LAYER M5 ;
        RECT  62.064 0 62.088 0.084 ;
    END
  END vr2q[491]
  PIN vr2q[492]
    DIRECTION OUTPUT ;
    USE SIGNAL ;
    PORT
      LAYER M3 ;
        RECT  62.208 0 62.226 0.038 ;
    END
  END vr2q[492]
  PIN vr2q[493]
    DIRECTION OUTPUT ;
    USE SIGNAL ;
    PORT
      LAYER M5 ;
        RECT  62.304 0 62.328 0.084 ;
    END
  END vr2q[493]
  PIN vr2q[494]
    DIRECTION OUTPUT ;
    USE SIGNAL ;
    PORT
      LAYER M3 ;
        RECT  62.46 0 62.478 0.038 ;
    END
  END vr2q[494]
  PIN vr2q[495]
    DIRECTION OUTPUT ;
    USE SIGNAL ;
    PORT
      LAYER M5 ;
        RECT  62.592 0 62.616 0.084 ;
    END
  END vr2q[495]
  PIN vr2q[496]
    DIRECTION OUTPUT ;
    USE SIGNAL ;
    PORT
      LAYER M3 ;
        RECT  62.712 0 62.73 0.038 ;
    END
  END vr2q[496]
  PIN vr2q[497]
    DIRECTION OUTPUT ;
    USE SIGNAL ;
    PORT
      LAYER M5 ;
        RECT  62.832 0 62.856 0.084 ;
    END
  END vr2q[497]
  PIN vr2q[498]
    DIRECTION OUTPUT ;
    USE SIGNAL ;
    PORT
      LAYER M3 ;
        RECT  62.964 0 62.982 0.038 ;
    END
  END vr2q[498]
  PIN vr2q[499]
    DIRECTION OUTPUT ;
    USE SIGNAL ;
    PORT
      LAYER M5 ;
        RECT  63.072 0 63.096 0.084 ;
    END
  END vr2q[499]
  PIN vr2q[49]
    DIRECTION OUTPUT ;
    USE SIGNAL ;
    PORT
      LAYER M5 ;
        RECT  6.24 0 6.264 0.084 ;
    END
  END vr2q[49]
  PIN vr2q[4]
    DIRECTION OUTPUT ;
    USE SIGNAL ;
    PORT
      LAYER M3 ;
        RECT  0.576 0 0.594 0.038 ;
    END
  END vr2q[4]
  PIN vr2q[500]
    DIRECTION OUTPUT ;
    USE SIGNAL ;
    PORT
      LAYER M3 ;
        RECT  63.216 0 63.234 0.038 ;
    END
  END vr2q[500]
  PIN vr2q[501]
    DIRECTION OUTPUT ;
    USE SIGNAL ;
    PORT
      LAYER M5 ;
        RECT  63.312 0 63.336 0.084 ;
    END
  END vr2q[501]
  PIN vr2q[502]
    DIRECTION OUTPUT ;
    USE SIGNAL ;
    PORT
      LAYER M3 ;
        RECT  63.468 0 63.486 0.038 ;
    END
  END vr2q[502]
  PIN vr2q[503]
    DIRECTION OUTPUT ;
    USE SIGNAL ;
    PORT
      LAYER M5 ;
        RECT  63.6 0 63.624 0.084 ;
    END
  END vr2q[503]
  PIN vr2q[504]
    DIRECTION OUTPUT ;
    USE SIGNAL ;
    PORT
      LAYER M3 ;
        RECT  63.72 0 63.738 0.038 ;
    END
  END vr2q[504]
  PIN vr2q[505]
    DIRECTION OUTPUT ;
    USE SIGNAL ;
    PORT
      LAYER M5 ;
        RECT  63.84 0 63.864 0.084 ;
    END
  END vr2q[505]
  PIN vr2q[506]
    DIRECTION OUTPUT ;
    USE SIGNAL ;
    PORT
      LAYER M3 ;
        RECT  63.972 0 63.99 0.038 ;
    END
  END vr2q[506]
  PIN vr2q[507]
    DIRECTION OUTPUT ;
    USE SIGNAL ;
    PORT
      LAYER M5 ;
        RECT  64.08 0 64.104 0.084 ;
    END
  END vr2q[507]
  PIN vr2q[508]
    DIRECTION OUTPUT ;
    USE SIGNAL ;
    PORT
      LAYER M3 ;
        RECT  64.224 0 64.242 0.038 ;
    END
  END vr2q[508]
  PIN vr2q[509]
    DIRECTION OUTPUT ;
    USE SIGNAL ;
    PORT
      LAYER M5 ;
        RECT  64.368 0 64.392 0.084 ;
    END
  END vr2q[509]
  PIN vr2q[50]
    DIRECTION OUTPUT ;
    USE SIGNAL ;
    PORT
      LAYER M3 ;
        RECT  6.372 0 6.39 0.038 ;
    END
  END vr2q[50]
  PIN vr2q[510]
    DIRECTION OUTPUT ;
    USE SIGNAL ;
    PORT
      LAYER M3 ;
        RECT  64.476 0 64.494 0.038 ;
    END
  END vr2q[510]
  PIN vr2q[511]
    DIRECTION OUTPUT ;
    USE SIGNAL ;
    PORT
      LAYER M5 ;
        RECT  64.608 0 64.632 0.084 ;
    END
  END vr2q[511]
  PIN vr2q[512]
    DIRECTION OUTPUT ;
    USE SIGNAL ;
    PORT
      LAYER M3 ;
        RECT  64.728 0 64.746 0.038 ;
    END
  END vr2q[512]
  PIN vr2q[51]
    DIRECTION OUTPUT ;
    USE SIGNAL ;
    PORT
      LAYER M5 ;
        RECT  6.48 0 6.504 0.084 ;
    END
  END vr2q[51]
  PIN vr2q[52]
    DIRECTION OUTPUT ;
    USE SIGNAL ;
    PORT
      LAYER M3 ;
        RECT  6.624 0 6.642 0.038 ;
    END
  END vr2q[52]
  PIN vr2q[53]
    DIRECTION OUTPUT ;
    USE SIGNAL ;
    PORT
      LAYER M5 ;
        RECT  6.768 0 6.792 0.084 ;
    END
  END vr2q[53]
  PIN vr2q[54]
    DIRECTION OUTPUT ;
    USE SIGNAL ;
    PORT
      LAYER M3 ;
        RECT  6.876 0 6.894 0.038 ;
    END
  END vr2q[54]
  PIN vr2q[55]
    DIRECTION OUTPUT ;
    USE SIGNAL ;
    PORT
      LAYER M5 ;
        RECT  7.008 0 7.032 0.084 ;
    END
  END vr2q[55]
  PIN vr2q[56]
    DIRECTION OUTPUT ;
    USE SIGNAL ;
    PORT
      LAYER M3 ;
        RECT  7.128 0 7.146 0.038 ;
    END
  END vr2q[56]
  PIN vr2q[57]
    DIRECTION OUTPUT ;
    USE SIGNAL ;
    PORT
      LAYER M5 ;
        RECT  7.248 0 7.272 0.084 ;
    END
  END vr2q[57]
  PIN vr2q[58]
    DIRECTION OUTPUT ;
    USE SIGNAL ;
    PORT
      LAYER M3 ;
        RECT  7.38 0 7.398 0.038 ;
    END
  END vr2q[58]
  PIN vr2q[59]
    DIRECTION OUTPUT ;
    USE SIGNAL ;
    PORT
      LAYER M5 ;
        RECT  7.488 0 7.512 0.084 ;
    END
  END vr2q[59]
  PIN vr2q[5]
    DIRECTION OUTPUT ;
    USE SIGNAL ;
    PORT
      LAYER M5 ;
        RECT  0.672 0 0.696 0.084 ;
    END
  END vr2q[5]
  PIN vr2q[60]
    DIRECTION OUTPUT ;
    USE SIGNAL ;
    PORT
      LAYER M3 ;
        RECT  7.632 0 7.65 0.038 ;
    END
  END vr2q[60]
  PIN vr2q[61]
    DIRECTION OUTPUT ;
    USE SIGNAL ;
    PORT
      LAYER M5 ;
        RECT  7.776 0 7.8 0.084 ;
    END
  END vr2q[61]
  PIN vr2q[62]
    DIRECTION OUTPUT ;
    USE SIGNAL ;
    PORT
      LAYER M3 ;
        RECT  7.884 0 7.902 0.038 ;
    END
  END vr2q[62]
  PIN vr2q[63]
    DIRECTION OUTPUT ;
    USE SIGNAL ;
    PORT
      LAYER M5 ;
        RECT  8.016 0 8.04 0.084 ;
    END
  END vr2q[63]
  PIN vr2q[64]
    DIRECTION OUTPUT ;
    USE SIGNAL ;
    PORT
      LAYER M3 ;
        RECT  8.136 0 8.154 0.038 ;
    END
  END vr2q[64]
  PIN vr2q[65]
    DIRECTION OUTPUT ;
    USE SIGNAL ;
    PORT
      LAYER M5 ;
        RECT  8.256 0 8.28 0.084 ;
    END
  END vr2q[65]
  PIN vr2q[66]
    DIRECTION OUTPUT ;
    USE SIGNAL ;
    PORT
      LAYER M3 ;
        RECT  8.388 0 8.406 0.038 ;
    END
  END vr2q[66]
  PIN vr2q[67]
    DIRECTION OUTPUT ;
    USE SIGNAL ;
    PORT
      LAYER M5 ;
        RECT  8.496 0 8.52 0.084 ;
    END
  END vr2q[67]
  PIN vr2q[68]
    DIRECTION OUTPUT ;
    USE SIGNAL ;
    PORT
      LAYER M3 ;
        RECT  8.64 0 8.658 0.038 ;
    END
  END vr2q[68]
  PIN vr2q[69]
    DIRECTION OUTPUT ;
    USE SIGNAL ;
    PORT
      LAYER M5 ;
        RECT  8.784 0 8.808 0.084 ;
    END
  END vr2q[69]
  PIN vr2q[6]
    DIRECTION OUTPUT ;
    USE SIGNAL ;
    PORT
      LAYER M3 ;
        RECT  0.828 0 0.846 0.038 ;
    END
  END vr2q[6]
  PIN vr2q[70]
    DIRECTION OUTPUT ;
    USE SIGNAL ;
    PORT
      LAYER M3 ;
        RECT  8.892 0 8.91 0.038 ;
    END
  END vr2q[70]
  PIN vr2q[71]
    DIRECTION OUTPUT ;
    USE SIGNAL ;
    PORT
      LAYER M5 ;
        RECT  9.024 0 9.048 0.084 ;
    END
  END vr2q[71]
  PIN vr2q[72]
    DIRECTION OUTPUT ;
    USE SIGNAL ;
    PORT
      LAYER M3 ;
        RECT  9.144 0 9.162 0.038 ;
    END
  END vr2q[72]
  PIN vr2q[73]
    DIRECTION OUTPUT ;
    USE SIGNAL ;
    PORT
      LAYER M5 ;
        RECT  9.264 0 9.288 0.084 ;
    END
  END vr2q[73]
  PIN vr2q[74]
    DIRECTION OUTPUT ;
    USE SIGNAL ;
    PORT
      LAYER M3 ;
        RECT  9.396 0 9.414 0.038 ;
    END
  END vr2q[74]
  PIN vr2q[75]
    DIRECTION OUTPUT ;
    USE SIGNAL ;
    PORT
      LAYER M5 ;
        RECT  9.504 0 9.528 0.084 ;
    END
  END vr2q[75]
  PIN vr2q[76]
    DIRECTION OUTPUT ;
    USE SIGNAL ;
    PORT
      LAYER M3 ;
        RECT  9.648 0 9.666 0.038 ;
    END
  END vr2q[76]
  PIN vr2q[77]
    DIRECTION OUTPUT ;
    USE SIGNAL ;
    PORT
      LAYER M5 ;
        RECT  9.792 0 9.816 0.084 ;
    END
  END vr2q[77]
  PIN vr2q[78]
    DIRECTION OUTPUT ;
    USE SIGNAL ;
    PORT
      LAYER M3 ;
        RECT  9.9 0 9.918 0.038 ;
    END
  END vr2q[78]
  PIN vr2q[79]
    DIRECTION OUTPUT ;
    USE SIGNAL ;
    PORT
      LAYER M5 ;
        RECT  10.032 0 10.056 0.084 ;
    END
  END vr2q[79]
  PIN vr2q[7]
    DIRECTION OUTPUT ;
    USE SIGNAL ;
    PORT
      LAYER M5 ;
        RECT  0.912 0 0.936 0.084 ;
    END
  END vr2q[7]
  PIN vr2q[80]
    DIRECTION OUTPUT ;
    USE SIGNAL ;
    PORT
      LAYER M3 ;
        RECT  10.152 0 10.17 0.038 ;
    END
  END vr2q[80]
  PIN vr2q[81]
    DIRECTION OUTPUT ;
    USE SIGNAL ;
    PORT
      LAYER M5 ;
        RECT  10.272 0 10.296 0.084 ;
    END
  END vr2q[81]
  PIN vr2q[82]
    DIRECTION OUTPUT ;
    USE SIGNAL ;
    PORT
      LAYER M3 ;
        RECT  10.404 0 10.422 0.038 ;
    END
  END vr2q[82]
  PIN vr2q[83]
    DIRECTION OUTPUT ;
    USE SIGNAL ;
    PORT
      LAYER M5 ;
        RECT  10.512 0 10.536 0.084 ;
    END
  END vr2q[83]
  PIN vr2q[84]
    DIRECTION OUTPUT ;
    USE SIGNAL ;
    PORT
      LAYER M3 ;
        RECT  10.656 0 10.674 0.038 ;
    END
  END vr2q[84]
  PIN vr2q[85]
    DIRECTION OUTPUT ;
    USE SIGNAL ;
    PORT
      LAYER M5 ;
        RECT  10.8 0 10.824 0.084 ;
    END
  END vr2q[85]
  PIN vr2q[86]
    DIRECTION OUTPUT ;
    USE SIGNAL ;
    PORT
      LAYER M3 ;
        RECT  10.908 0 10.926 0.038 ;
    END
  END vr2q[86]
  PIN vr2q[87]
    DIRECTION OUTPUT ;
    USE SIGNAL ;
    PORT
      LAYER M5 ;
        RECT  11.04 0 11.064 0.084 ;
    END
  END vr2q[87]
  PIN vr2q[88]
    DIRECTION OUTPUT ;
    USE SIGNAL ;
    PORT
      LAYER M3 ;
        RECT  11.16 0 11.178 0.038 ;
    END
  END vr2q[88]
  PIN vr2q[89]
    DIRECTION OUTPUT ;
    USE SIGNAL ;
    PORT
      LAYER M5 ;
        RECT  11.28 0 11.304 0.084 ;
    END
  END vr2q[89]
  PIN vr2q[8]
    DIRECTION OUTPUT ;
    USE SIGNAL ;
    PORT
      LAYER M3 ;
        RECT  1.08 0 1.098 0.038 ;
    END
  END vr2q[8]
  PIN vr2q[90]
    DIRECTION OUTPUT ;
    USE SIGNAL ;
    PORT
      LAYER M3 ;
        RECT  11.412 0 11.43 0.038 ;
    END
  END vr2q[90]
  PIN vr2q[91]
    DIRECTION OUTPUT ;
    USE SIGNAL ;
    PORT
      LAYER M5 ;
        RECT  11.568 0 11.592 0.084 ;
    END
  END vr2q[91]
  PIN vr2q[92]
    DIRECTION OUTPUT ;
    USE SIGNAL ;
    PORT
      LAYER M3 ;
        RECT  11.664 0 11.682 0.038 ;
    END
  END vr2q[92]
  PIN vr2q[93]
    DIRECTION OUTPUT ;
    USE SIGNAL ;
    PORT
      LAYER M5 ;
        RECT  11.808 0 11.832 0.084 ;
    END
  END vr2q[93]
  PIN vr2q[94]
    DIRECTION OUTPUT ;
    USE SIGNAL ;
    PORT
      LAYER M3 ;
        RECT  11.916 0 11.934 0.038 ;
    END
  END vr2q[94]
  PIN vr2q[95]
    DIRECTION OUTPUT ;
    USE SIGNAL ;
    PORT
      LAYER M5 ;
        RECT  12.048 0 12.072 0.084 ;
    END
  END vr2q[95]
  PIN vr2q[96]
    DIRECTION OUTPUT ;
    USE SIGNAL ;
    PORT
      LAYER M3 ;
        RECT  12.168 0 12.186 0.038 ;
    END
  END vr2q[96]
  PIN vr2q[97]
    DIRECTION OUTPUT ;
    USE SIGNAL ;
    PORT
      LAYER M5 ;
        RECT  12.288 0 12.312 0.084 ;
    END
  END vr2q[97]
  PIN vr2q[98]
    DIRECTION OUTPUT ;
    USE SIGNAL ;
    PORT
      LAYER M3 ;
        RECT  12.42 0 12.438 0.038 ;
    END
  END vr2q[98]
  PIN vr2q[99]
    DIRECTION OUTPUT ;
    USE SIGNAL ;
    PORT
      LAYER M5 ;
        RECT  12.576 0 12.6 0.084 ;
    END
  END vr2q[99]
  PIN vr2q[9]
    DIRECTION OUTPUT ;
    USE SIGNAL ;
    PORT
      LAYER M5 ;
        RECT  1.2 0 1.224 0.084 ;
    END
  END vr2q[9]
  PIN VDD
    DIRECTION INOUT ;
    USE POWER ;
    PORT
      LAYER M5 ;
        RECT  61.992 2.151 62.112 62.649 ;
        RECT  56.592 2.151 56.712 62.649 ;
        RECT  51.192 2.151 51.312 62.649 ;
        RECT  45.792 2.151 45.912 62.649 ;
        RECT  40.392 2.151 40.512 62.649 ;
        RECT  34.992 2.151 35.112 62.649 ;
        RECT  29.592 2.151 29.712 62.649 ;
        RECT  24.192 2.151 24.312 62.649 ;
        RECT  18.792 2.151 18.912 62.649 ;
        RECT  13.392 2.151 13.512 62.649 ;
        RECT  7.992 2.151 8.112 62.649 ;
        RECT  2.592 2.151 2.712 62.649 ;
    END
  END VDD
  PIN VSS
    DIRECTION INOUT ;
    USE GROUND ;
    PORT
      LAYER M5 ;
        RECT  61.8 2.137 61.92 62.663 ;
        RECT  56.4 2.137 56.52 62.663 ;
        RECT  51 2.137 51.12 62.663 ;
        RECT  45.6 2.137 45.72 62.663 ;
        RECT  40.2 2.137 40.32 62.663 ;
        RECT  34.8 2.137 34.92 62.663 ;
        RECT  29.4 2.137 29.52 62.663 ;
        RECT  24 2.137 24.12 62.663 ;
        RECT  18.6 2.137 18.72 62.663 ;
        RECT  13.2 2.137 13.32 62.663 ;
        RECT  7.8 2.137 7.92 62.663 ;
        RECT  2.4 2.137 2.52 62.663 ;
    END
  END VSS
  # OT_OBS_CLOSED layer=M5 d_um=1.536 added=98
  OBS
    LAYER RVTN ;
     RECT  2.16 2.16 62.64 2.295 ;
     RECT  2.16 2.565 62.64 2.835 ;
     RECT  2.16 3.105 62.64 3.375 ;
     RECT  2.16 3.645 62.64 3.915 ;
     RECT  2.16 4.185 62.64 4.455 ;
     RECT  2.16 4.725 62.64 4.995 ;
     RECT  2.16 5.265 62.64 5.535 ;
     RECT  2.16 5.805 62.64 6.075 ;
     RECT  2.16 6.345 62.64 6.615 ;
     RECT  2.16 6.885 62.64 7.155 ;
     RECT  2.16 7.425 62.64 7.695 ;
     RECT  2.16 7.965 62.64 8.235 ;
     RECT  2.16 8.505 62.64 8.775 ;
     RECT  2.16 9.045 62.64 9.315 ;
     RECT  2.16 9.585 62.64 9.855 ;
     RECT  2.16 10.125 62.64 10.395 ;
     RECT  2.16 10.665 62.64 10.935 ;
     RECT  2.16 11.205 62.64 11.475 ;
     RECT  2.16 11.745 62.64 12.015 ;
     RECT  2.16 12.285 62.64 12.555 ;
     RECT  2.16 12.825 62.64 13.095 ;
     RECT  2.16 13.365 62.64 13.635 ;
     RECT  2.16 13.905 62.64 14.175 ;
     RECT  2.16 14.445 62.64 14.715 ;
     RECT  2.16 14.985 62.64 15.255 ;
     RECT  2.16 15.525 62.64 15.795 ;
     RECT  2.16 16.065 62.64 16.335 ;
     RECT  2.16 16.605 62.64 16.875 ;
     RECT  2.16 17.145 62.64 17.415 ;
     RECT  2.16 17.685 62.64 17.955 ;
     RECT  2.16 18.225 62.64 18.495 ;
     RECT  2.16 18.765 62.64 19.035 ;
     RECT  2.16 19.305 62.64 19.575 ;
     RECT  2.16 19.845 62.64 20.115 ;
     RECT  2.16 20.385 62.64 20.655 ;
     RECT  2.16 20.925 62.64 21.195 ;
     RECT  2.16 21.465 62.64 21.735 ;
     RECT  2.16 22.005 62.64 22.275 ;
     RECT  2.16 22.545 62.64 22.815 ;
     RECT  2.16 23.085 62.64 23.355 ;
     RECT  2.16 23.625 62.64 23.895 ;
     RECT  2.16 24.165 62.64 24.435 ;
     RECT  2.16 24.705 62.64 24.975 ;
     RECT  2.16 25.245 62.64 25.515 ;
     RECT  2.16 25.785 62.64 26.055 ;
     RECT  2.16 26.325 62.64 26.595 ;
     RECT  2.16 26.865 62.64 27.135 ;
     RECT  2.16 27.405 62.64 27.675 ;
     RECT  2.16 27.945 62.64 28.215 ;
     RECT  2.16 28.485 62.64 28.755 ;
     RECT  2.16 29.025 62.64 29.295 ;
     RECT  2.16 29.565 62.64 29.835 ;
     RECT  2.16 30.105 62.64 30.375 ;
     RECT  2.16 30.645 62.64 30.915 ;
     RECT  2.16 31.185 62.64 31.455 ;
     RECT  2.16 31.725 62.64 31.995 ;
     RECT  2.16 32.265 62.64 32.535 ;
     RECT  2.16 32.805 62.64 33.075 ;
     RECT  2.16 33.345 62.64 33.615 ;
     RECT  2.16 33.885 62.64 34.155 ;
     RECT  2.16 34.425 62.64 34.695 ;
     RECT  2.16 34.965 62.64 35.235 ;
     RECT  2.16 35.505 62.64 35.775 ;
     RECT  2.16 36.045 62.64 36.315 ;
     RECT  2.16 36.585 62.64 36.855 ;
     RECT  2.16 37.125 62.64 37.395 ;
     RECT  2.16 37.665 62.64 37.935 ;
     RECT  2.16 38.205 62.64 38.475 ;
     RECT  2.16 38.745 62.64 39.015 ;
     RECT  2.16 39.285 62.64 39.555 ;
     RECT  2.16 39.825 62.64 40.095 ;
     RECT  2.16 40.365 62.64 40.635 ;
     RECT  2.16 40.905 62.64 41.175 ;
     RECT  2.16 41.445 62.64 41.715 ;
     RECT  2.16 41.985 62.64 42.255 ;
     RECT  2.16 42.525 62.64 42.795 ;
     RECT  2.16 43.065 62.64 43.335 ;
     RECT  2.16 43.605 62.64 43.875 ;
     RECT  2.16 44.145 62.64 44.415 ;
     RECT  2.16 44.685 62.64 44.955 ;
     RECT  2.16 45.225 62.64 45.495 ;
     RECT  2.16 45.765 62.64 46.035 ;
     RECT  2.16 46.305 62.64 46.575 ;
     RECT  2.16 46.845 62.64 47.115 ;
     RECT  2.16 47.385 62.64 47.655 ;
     RECT  2.16 47.925 62.64 48.195 ;
     RECT  2.16 48.465 62.64 48.735 ;
     RECT  2.16 49.005 62.64 49.275 ;
     RECT  2.16 49.545 62.64 49.815 ;
     RECT  2.16 50.085 62.64 50.355 ;
     RECT  2.16 50.625 62.64 50.895 ;
     RECT  2.16 51.165 62.64 51.435 ;
     RECT  2.16 51.705 62.64 51.975 ;
     RECT  2.16 52.245 62.64 52.515 ;
     RECT  2.16 52.785 62.64 53.055 ;
     RECT  2.16 53.325 62.64 53.595 ;
     RECT  2.16 53.865 62.64 54.135 ;
     RECT  2.16 54.405 62.64 54.675 ;
     RECT  2.16 54.945 62.64 55.215 ;
     RECT  2.16 55.485 62.64 55.755 ;
     RECT  2.16 56.025 62.64 56.295 ;
     RECT  2.16 56.565 62.64 56.835 ;
     RECT  2.16 57.105 62.64 57.375 ;
     RECT  2.16 57.645 62.64 57.915 ;
     RECT  2.16 58.185 62.64 58.455 ;
     RECT  2.16 58.725 62.64 58.995 ;
     RECT  2.16 59.265 62.64 59.535 ;
     RECT  2.16 59.805 62.64 60.075 ;
     RECT  2.16 60.345 62.64 60.615 ;
     RECT  2.16 60.885 62.64 61.155 ;
     RECT  2.16 61.425 62.64 61.695 ;
     RECT  2.16 61.965 62.64 62.235 ;
     RECT  2.16 62.505 62.64 62.64 ;
    LAYER RVTP ;
     RECT  2.16 2.295 62.64 2.565 ;
     RECT  2.16 2.835 62.64 3.105 ;
     RECT  2.16 3.375 62.64 3.645 ;
     RECT  2.16 3.915 62.64 4.185 ;
     RECT  2.16 4.455 62.64 4.725 ;
     RECT  2.16 4.995 62.64 5.265 ;
     RECT  2.16 5.535 62.64 5.805 ;
     RECT  2.16 6.075 62.64 6.345 ;
     RECT  2.16 6.615 62.64 6.885 ;
     RECT  2.16 7.155 62.64 7.425 ;
     RECT  2.16 7.695 62.64 7.965 ;
     RECT  2.16 8.235 62.64 8.505 ;
     RECT  2.16 8.775 62.64 9.045 ;
     RECT  2.16 9.315 62.64 9.585 ;
     RECT  2.16 9.855 62.64 10.125 ;
     RECT  2.16 10.395 62.64 10.665 ;
     RECT  2.16 10.935 62.64 11.205 ;
     RECT  2.16 11.475 62.64 11.745 ;
     RECT  2.16 12.015 62.64 12.285 ;
     RECT  2.16 12.555 62.64 12.825 ;
     RECT  2.16 13.095 62.64 13.365 ;
     RECT  2.16 13.635 62.64 13.905 ;
     RECT  2.16 14.175 62.64 14.445 ;
     RECT  2.16 14.715 62.64 14.985 ;
     RECT  2.16 15.255 62.64 15.525 ;
     RECT  2.16 15.795 62.64 16.065 ;
     RECT  2.16 16.335 62.64 16.605 ;
     RECT  2.16 16.875 62.64 17.145 ;
     RECT  2.16 17.415 62.64 17.685 ;
     RECT  2.16 17.955 62.64 18.225 ;
     RECT  2.16 18.495 62.64 18.765 ;
     RECT  2.16 19.035 62.64 19.305 ;
     RECT  2.16 19.575 62.64 19.845 ;
     RECT  2.16 20.115 62.64 20.385 ;
     RECT  2.16 20.655 62.64 20.925 ;
     RECT  2.16 21.195 62.64 21.465 ;
     RECT  2.16 21.735 62.64 22.005 ;
     RECT  2.16 22.275 62.64 22.545 ;
     RECT  2.16 22.815 62.64 23.085 ;
     RECT  2.16 23.355 62.64 23.625 ;
     RECT  2.16 23.895 62.64 24.165 ;
     RECT  2.16 24.435 62.64 24.705 ;
     RECT  2.16 24.975 62.64 25.245 ;
     RECT  2.16 25.515 62.64 25.785 ;
     RECT  2.16 26.055 62.64 26.325 ;
     RECT  2.16 26.595 62.64 26.865 ;
     RECT  2.16 27.135 62.64 27.405 ;
     RECT  2.16 27.675 62.64 27.945 ;
     RECT  2.16 28.215 62.64 28.485 ;
     RECT  2.16 28.755 62.64 29.025 ;
     RECT  2.16 29.295 62.64 29.565 ;
     RECT  2.16 29.835 62.64 30.105 ;
     RECT  2.16 30.375 62.64 30.645 ;
     RECT  2.16 30.915 62.64 31.185 ;
     RECT  2.16 31.455 62.64 31.725 ;
     RECT  2.16 31.995 62.64 32.265 ;
     RECT  2.16 32.535 62.64 32.805 ;
     RECT  2.16 33.075 62.64 33.345 ;
     RECT  2.16 33.615 62.64 33.885 ;
     RECT  2.16 34.155 62.64 34.425 ;
     RECT  2.16 34.695 62.64 34.965 ;
     RECT  2.16 35.235 62.64 35.505 ;
     RECT  2.16 35.775 62.64 36.045 ;
     RECT  2.16 36.315 62.64 36.585 ;
     RECT  2.16 36.855 62.64 37.125 ;
     RECT  2.16 37.395 62.64 37.665 ;
     RECT  2.16 37.935 62.64 38.205 ;
     RECT  2.16 38.475 62.64 38.745 ;
     RECT  2.16 39.015 62.64 39.285 ;
     RECT  2.16 39.555 62.64 39.825 ;
     RECT  2.16 40.095 62.64 40.365 ;
     RECT  2.16 40.635 62.64 40.905 ;
     RECT  2.16 41.175 62.64 41.445 ;
     RECT  2.16 41.715 62.64 41.985 ;
     RECT  2.16 42.255 62.64 42.525 ;
     RECT  2.16 42.795 62.64 43.065 ;
     RECT  2.16 43.335 62.64 43.605 ;
     RECT  2.16 43.875 62.64 44.145 ;
     RECT  2.16 44.415 62.64 44.685 ;
     RECT  2.16 44.955 62.64 45.225 ;
     RECT  2.16 45.495 62.64 45.765 ;
     RECT  2.16 46.035 62.64 46.305 ;
     RECT  2.16 46.575 62.64 46.845 ;
     RECT  2.16 47.115 62.64 47.385 ;
     RECT  2.16 47.655 62.64 47.925 ;
     RECT  2.16 48.195 62.64 48.465 ;
     RECT  2.16 48.735 62.64 49.005 ;
     RECT  2.16 49.275 62.64 49.545 ;
     RECT  2.16 49.815 62.64 50.085 ;
     RECT  2.16 50.355 62.64 50.625 ;
     RECT  2.16 50.895 62.64 51.165 ;
     RECT  2.16 51.435 62.64 51.705 ;
     RECT  2.16 51.975 62.64 52.245 ;
     RECT  2.16 52.515 62.64 52.785 ;
     RECT  2.16 53.055 62.64 53.325 ;
     RECT  2.16 53.595 62.64 53.865 ;
     RECT  2.16 54.135 62.64 54.405 ;
     RECT  2.16 54.675 62.64 54.945 ;
     RECT  2.16 55.215 62.64 55.485 ;
     RECT  2.16 55.755 62.64 56.025 ;
     RECT  2.16 56.295 62.64 56.565 ;
     RECT  2.16 56.835 62.64 57.105 ;
     RECT  2.16 57.375 62.64 57.645 ;
     RECT  2.16 57.915 62.64 58.185 ;
     RECT  2.16 58.455 62.64 58.725 ;
     RECT  2.16 58.995 62.64 59.265 ;
     RECT  2.16 59.535 62.64 59.805 ;
     RECT  2.16 60.075 62.64 60.345 ;
     RECT  2.16 60.615 62.64 60.885 ;
     RECT  2.16 61.155 62.64 61.425 ;
     RECT  2.16 61.695 62.64 61.965 ;
     RECT  2.16 62.235 62.64 62.505 ;
    LAYER M1 ;
     RECT  2.16 2.151 62.64 62.649 ;
    LAYER M2 ;
     RECT  0.067 4.698 0.319 4.716 ;
     RECT  0.319 4.356 0.571 4.716 ;
     RECT  0.535 35.982 0.823 36 ;
     RECT  0.319 63.864 0.851 63.882 ;
     RECT  0.823 35.982 0.859 36.648 ;
     RECT  0.571 3.618 0.931 4.716 ;
     RECT  0.787 43.65 1.543 43.668 ;
     RECT  1.327 7.128 1.579 7.146 ;
     RECT  1.039 46.782 1.687 46.8 ;
     RECT  0.931 3.186 1.723 4.716 ;
     RECT  0.823 5.544 1.723 5.562 ;
     RECT  1.579 6.516 1.759 7.146 ;
     RECT  1.795 39.6 1.939 39.618 ;
     RECT  1.903 8.586 1.975 8.604 ;
     RECT  1.975 8.586 2.011 8.694 ;
     RECT  1.939 10.062 2.011 10.08 ;
     RECT  1.975 17.658 2.011 17.676 ;
     RECT  1.975 41.526 2.011 41.544 ;
     RECT  1.723 2.646 2.047 5.562 ;
     RECT  1.759 6.516 2.047 7.416 ;
     RECT  2.011 8.586 2.047 10.08 ;
     RECT  1.939 39.024 2.047 39.618 ;
     RECT  2.047 38.556 2.083 39.618 ;
     RECT  1.939 13.032 2.119 13.05 ;
     RECT  2.047 8.478 2.155 10.08 ;
     RECT  2.047 2.196 2.16 7.416 ;
     RECT  2.155 8.478 2.16 10.494 ;
     RECT  2.119 11.826 2.16 11.844 ;
     RECT  2.119 12.87 2.16 13.05 ;
     RECT  2.047 13.95 2.16 13.968 ;
     RECT  2.083 15.03 2.16 15.048 ;
     RECT  2.011 17.658 2.16 18.216 ;
     RECT  0.859 35.442 2.16 36.648 ;
     RECT  2.083 38.556 2.16 40.122 ;
     RECT  2.011 41.526 2.16 41.814 ;
     RECT  1.543 43.308 2.16 43.668 ;
     RECT  1.291 45 2.16 45.018 ;
     RECT  1.687 46.782 2.16 47.448 ;
     RECT  2.083 0.036 2.839 0.054 ;
     RECT  2.803 64.521 2.939 64.539 ;
     RECT  2.839 0.036 3.083 0.126 ;
     RECT  2.16 2.151 3.379 62.649 ;
     RECT  3.379 2.106 3.451 62.649 ;
     RECT  3.451 2.07 3.983 62.649 ;
     RECT  3.983 2.106 4.559 62.649 ;
     RECT  3.083 0.036 4.855 0.054 ;
     RECT  4.855 0.036 5.135 0.198 ;
     RECT  4.819 63.864 5.387 63.882 ;
     RECT  5.135 0.036 5.459 0.054 ;
     RECT  4.559 2.151 6.727 62.649 ;
     RECT  7.447 0.108 7.627 0.126 ;
     RECT  6.727 2.106 7.771 62.649 ;
     RECT  7.771 2.106 7.871 62.73 ;
     RECT  7.627 0.036 7.907 0.126 ;
     RECT  7.871 2.106 8.131 62.649 ;
     RECT  7.907 0.036 8.519 0.054 ;
     RECT  9.391 0.036 9.535 0.054 ;
     RECT  8.131 1.728 9.535 62.649 ;
     RECT  9.535 1.152 9.635 62.649 ;
     RECT  9.535 0.036 9.671 0.126 ;
     RECT  9.635 1.728 9.671 62.649 ;
     RECT  10.471 1.152 10.507 1.17 ;
     RECT  10.507 1.152 10.571 1.242 ;
     RECT  10.571 1.224 10.751 1.242 ;
     RECT  9.671 2.106 11.407 62.649 ;
     RECT  11.407 1.728 11.507 62.649 ;
     RECT  9.671 0.036 11.759 0.054 ;
     RECT  11.507 2.106 11.795 62.649 ;
     RECT  11.731 1.152 11.939 1.206 ;
     RECT  11.939 1.152 13.019 1.17 ;
     RECT  12.811 0.036 13.423 0.054 ;
     RECT  13.423 0.036 13.559 0.126 ;
     RECT  13.559 0.108 13.595 0.126 ;
     RECT  13.639 64.521 13.775 64.539 ;
     RECT  13.855 1.224 13.927 1.242 ;
     RECT  13.927 1.152 14.243 1.242 ;
     RECT  11.795 2.151 14.467 62.649 ;
     RECT  14.467 1.728 14.567 62.649 ;
     RECT  15.223 1.152 15.323 1.17 ;
     RECT  15.907 64.674 16.043 64.692 ;
     RECT  17.563 63.864 17.699 63.882 ;
     RECT  16.591 1.152 17.879 1.17 ;
     RECT  17.923 64.674 18.059 64.692 ;
     RECT  14.567 2.151 18.571 62.649 ;
     RECT  18.571 2.151 18.707 62.73 ;
     RECT  16.231 0.036 18.779 0.054 ;
     RECT  18.707 2.151 19.363 62.649 ;
     RECT  19.507 0.036 19.679 0.054 ;
     RECT  19.759 1.152 19.831 1.242 ;
     RECT  19.363 2.106 19.831 62.649 ;
     RECT  19.831 1.152 20.183 62.649 ;
     RECT  20.183 1.152 20.651 1.17 ;
     RECT  20.183 2.106 21.019 62.649 ;
     RECT  21.019 1.728 21.479 62.649 ;
     RECT  20.515 0.036 21.551 0.054 ;
     RECT  21.479 2.106 21.623 62.649 ;
     RECT  22.675 0.036 23.063 0.054 ;
     RECT  23.791 0.036 24.683 0.054 ;
     RECT  21.623 2.151 25.483 62.649 ;
     RECT  25.807 1.152 26.051 1.17 ;
     RECT  28.111 1.152 28.283 1.17 ;
     RECT  26.311 0.036 28.355 0.054 ;
     RECT  25.483 2.151 28.615 62.73 ;
     RECT  28.615 1.728 29.003 62.73 ;
     RECT  29.191 1.224 29.291 1.242 ;
     RECT  29.003 2.151 29.579 62.73 ;
     RECT  29.767 0.036 30.407 0.054 ;
     RECT  30.055 1.152 30.443 1.17 ;
     RECT  31.135 0.036 31.603 0.054 ;
     RECT  31.603 0.036 31.739 0.126 ;
     RECT  31.739 0.108 31.919 0.126 ;
     RECT  32.503 64.674 32.639 64.692 ;
     RECT  31.495 1.152 32.783 1.17 ;
     RECT  32.647 0.036 33.035 0.054 ;
     RECT  29.579 2.151 33.115 62.649 ;
     RECT  33.115 2.106 33.223 62.649 ;
     RECT  33.223 2.106 33.403 62.73 ;
     RECT  34.015 1.152 34.087 1.17 ;
     RECT  33.403 2.034 34.151 62.73 ;
     RECT  34.087 1.152 34.187 1.242 ;
     RECT  34.187 1.152 34.547 1.17 ;
     RECT  33.907 0.036 34.691 0.054 ;
     RECT  34.151 2.106 34.915 62.73 ;
     RECT  34.915 1.728 35.375 62.73 ;
     RECT  35.375 2.106 35.555 62.73 ;
     RECT  35.555 2.106 35.591 62.649 ;
     RECT  35.671 1.152 35.807 1.17 ;
     RECT  35.591 2.151 36.283 62.649 ;
     RECT  36.283 2.151 36.887 62.73 ;
     RECT  36.887 2.151 37.903 62.649 ;
     RECT  37.795 64.674 37.931 64.692 ;
     RECT  37.903 2.106 38.507 62.649 ;
     RECT  35.419 0.036 39.299 0.054 ;
     RECT  37.111 0.846 39.775 0.864 ;
     RECT  39.775 0.576 39.983 0.864 ;
     RECT  38.507 2.151 40.207 62.649 ;
     RECT  40.207 1.728 40.315 62.649 ;
     RECT  40.315 1.728 40.451 62.73 ;
     RECT  40.451 1.728 40.883 62.649 ;
     RECT  40.459 0.036 41.495 0.054 ;
     RECT  40.883 2.106 42.683 62.649 ;
     RECT  42.583 64.674 42.719 64.692 ;
     RECT  42.683 2.151 44.455 62.649 ;
     RECT  44.455 2.106 45.491 62.649 ;
     RECT  45.491 2.151 45.607 62.649 ;
     RECT  45.607 2.151 46.031 62.73 ;
     RECT  45.031 0.036 46.039 0.054 ;
     RECT  39.983 0.846 46.039 0.864 ;
     RECT  46.039 0.036 46.175 0.864 ;
     RECT  46.175 0.846 46.291 0.864 ;
     RECT  46.291 0.846 46.643 1.17 ;
     RECT  46.643 0.846 48.127 0.864 ;
     RECT  48.127 0.846 48.983 1.17 ;
     RECT  46.031 2.151 49.135 62.649 ;
     RECT  46.175 0.036 50.027 0.054 ;
     RECT  50.827 0.036 50.927 0.054 ;
     RECT  49.135 2.151 51.079 62.73 ;
     RECT  51.079 1.728 51.791 62.73 ;
     RECT  51.791 2.151 52.403 62.73 ;
     RECT  52.403 2.151 53.131 62.649 ;
     RECT  53.131 2.151 53.267 62.766 ;
     RECT  52.591 0.036 53.375 0.054 ;
     RECT  53.267 2.151 54.139 62.73 ;
     RECT  54.139 2.106 54.455 62.73 ;
     RECT  54.455 2.151 56.875 62.73 ;
     RECT  56.623 0.036 56.975 0.054 ;
     RECT  56.875 1.728 57.191 62.73 ;
     RECT  57.191 2.151 58.135 62.73 ;
     RECT  58.135 2.106 58.315 62.73 ;
     RECT  58.171 0.036 58.343 0.054 ;
     RECT  58.315 2.106 58.451 62.802 ;
     RECT  58.451 2.106 58.459 62.73 ;
     RECT  58.459 1.728 58.703 62.73 ;
     RECT  58.703 2.151 59.819 62.73 ;
     RECT  59.359 0.036 60.143 0.054 ;
     RECT  59.819 2.151 60.619 62.694 ;
     RECT  60.619 2.151 60.971 62.73 ;
     RECT  48.983 0.846 61.051 0.864 ;
     RECT  61.051 0.846 61.187 1.17 ;
     RECT  60.971 2.151 61.411 62.649 ;
     RECT  61.411 2.106 61.583 62.649 ;
     RECT  61.627 64.746 61.663 64.764 ;
     RECT  61.583 2.151 61.699 62.649 ;
     RECT  61.051 0.036 61.727 0.054 ;
     RECT  61.663 64.674 61.727 64.764 ;
     RECT  61.727 64.674 61.979 64.692 ;
     RECT  61.699 2.151 62.64 62.694 ;
     RECT  62.64 23.022 62.699 28.278 ;
     RECT  62.64 40.608 62.699 62.694 ;
     RECT  62.699 23.832 62.735 24.93 ;
     RECT  62.64 2.304 62.771 22.23 ;
     RECT  62.771 2.304 62.879 4.374 ;
     RECT  62.455 0.036 62.951 0.054 ;
     RECT  62.771 5.166 62.951 22.23 ;
     RECT  62.735 24.336 63.239 24.93 ;
     RECT  62.64 30.384 63.239 32.022 ;
     RECT  62.879 2.304 63.275 4.248 ;
     RECT  62.951 7.47 63.275 22.23 ;
     RECT  63.239 24.336 63.275 24.894 ;
     RECT  63.239 30.42 63.275 32.022 ;
     RECT  62.699 41.346 63.275 41.904 ;
     RECT  62.699 42.696 63.275 46.53 ;
     RECT  62.699 47.43 63.275 62.694 ;
     RECT  63.275 22.212 63.311 22.23 ;
     RECT  63.275 48.672 63.311 62.694 ;
     RECT  63.311 54.684 63.491 62.694 ;
     RECT  63.491 54.684 63.599 62.568 ;
     RECT  62.951 5.166 63.743 6.642 ;
     RECT  63.599 54.684 63.743 62.496 ;
     RECT  63.499 64.746 63.743 64.764 ;
     RECT  63.275 2.304 63.851 3.744 ;
     RECT  63.275 19.782 63.851 20.88 ;
     RECT  63.275 24.642 63.851 24.66 ;
     RECT  62.699 25.83 63.851 28.278 ;
     RECT  63.275 30.888 63.851 32.022 ;
     RECT  62.64 36.018 63.851 37.116 ;
     RECT  62.64 37.98 63.851 38.97 ;
     RECT  63.275 41.886 63.851 41.904 ;
     RECT  63.275 42.732 63.851 46.53 ;
     RECT  63.311 48.672 63.851 53.928 ;
     RECT  63.743 54.684 63.851 60.948 ;
     RECT  63.275 7.47 63.887 18.72 ;
     RECT  63.851 19.782 63.887 19.8 ;
     RECT  63.851 27.18 63.887 28.044 ;
     RECT  63.851 42.732 63.887 42.75 ;
     RECT  63.851 49.752 63.887 53.928 ;
     RECT  63.851 54.99 63.887 55.512 ;
     RECT  63.851 56.304 63.887 60.678 ;
     RECT  63.887 7.47 63.923 15.822 ;
     RECT  63.923 11.178 63.959 15.822 ;
     RECT  63.887 55.026 63.959 55.044 ;
     RECT  63.887 56.304 63.995 60.372 ;
     RECT  63.743 61.74 63.995 62.496 ;
     RECT  63.995 61.74 64.247 61.758 ;
     RECT  63.851 2.88 64.499 3.744 ;
     RECT  62.64 34.938 64.507 34.956 ;
     RECT  63.851 38.682 64.571 38.97 ;
     RECT  62.64 29.304 64.615 29.556 ;
     RECT  62.64 33.12 64.615 33.138 ;
     RECT  64.507 34.434 64.615 34.956 ;
     RECT  63.851 36.018 64.615 36.036 ;
     RECT  63.995 56.304 64.615 60.03 ;
     RECT  64.499 2.88 64.643 2.898 ;
     RECT  64.543 19.656 64.643 19.674 ;
     RECT  64.499 3.726 64.679 3.744 ;
     RECT  63.923 7.47 64.679 10.152 ;
     RECT  63.959 11.178 64.679 12.384 ;
     RECT  63.959 13.302 64.679 15.822 ;
     RECT  64.615 33.12 64.679 36.036 ;
     RECT  64.507 40.338 64.679 40.356 ;
     RECT  63.887 50.562 64.679 53.928 ;
     RECT  64.615 55.656 64.679 60.03 ;
     RECT  61.187 0.846 64.715 0.864 ;
     RECT  63.743 5.31 64.715 6.642 ;
     RECT  64.679 8.514 64.715 10.152 ;
     RECT  64.679 11.178 64.715 11.574 ;
     RECT  64.679 12.33 64.715 12.348 ;
     RECT  64.679 13.338 64.715 15.75 ;
     RECT  63.887 16.776 64.715 18.72 ;
     RECT  64.615 23.706 64.715 23.724 ;
     RECT  64.615 25.326 64.715 25.344 ;
     RECT  63.851 26.262 64.715 26.28 ;
     RECT  63.887 27.918 64.715 27.936 ;
     RECT  64.615 29.196 64.715 29.556 ;
     RECT  63.851 31.122 64.715 31.14 ;
     RECT  64.679 33.12 64.715 33.714 ;
     RECT  64.679 34.506 64.715 36.036 ;
     RECT  63.851 37.062 64.715 37.08 ;
     RECT  64.571 38.682 64.715 38.7 ;
     RECT  63.851 44.082 64.715 46.53 ;
     RECT  63.275 47.43 64.715 47.448 ;
     RECT  63.851 48.978 64.715 48.996 ;
     RECT  64.679 50.562 64.715 53.892 ;
     RECT  64.679 55.656 64.715 56.862 ;
     RECT  64.679 57.888 64.715 57.978 ;
     RECT  64.679 59.04 64.715 60.03 ;
     RECT  64.715 5.706 64.751 5.724 ;
     RECT  64.715 60.012 64.751 60.03 ;
     RECT  64.687 64.602 64.787 64.62 ;
    LAYER M3 ;
     RECT  0.072 0.012 64.746 3.965 ;
     RECT  0.072 3.965 63.846 4.379 ;
     RECT  0.072 4.379 0.09 4.721 ;
     RECT  0.828 4.379 63.846 4.843 ;
     RECT  64.62 3.965 64.746 4.843 ;
     RECT  0.828 4.843 64.746 5.261 ;
     RECT  0.828 5.261 63.846 5.567 ;
     RECT  64.584 5.261 64.746 5.729 ;
     RECT  64.584 5.729 64.71 6.269 ;
     RECT  1.332 5.567 63.846 6.449 ;
     RECT  64.692 6.269 64.71 7.003 ;
     RECT  64.62 7.003 64.71 7.099 ;
     RECT  1.332 6.449 63.594 7.151 ;
     RECT  1.764 7.151 63.594 7.421 ;
     RECT  1.908 7.421 63.594 7.501 ;
     RECT  64.548 7.099 64.71 7.501 ;
     RECT  1.908 7.501 64.71 8.609 ;
     RECT  1.944 8.609 64.71 8.669 ;
     RECT  64.512 8.669 64.71 8.813 ;
     RECT  1.944 8.669 63.234 9.547 ;
     RECT  1.944 9.547 63.846 10.085 ;
     RECT  64.62 8.813 64.71 10.157 ;
     RECT  2.124 10.085 63.846 10.319 ;
     RECT  63.252 10.319 63.846 10.363 ;
     RECT  64.62 10.157 64.638 10.685 ;
     RECT  63.252 10.363 63.882 10.867 ;
     RECT  2.124 10.319 62.514 11.173 ;
     RECT  63.252 10.867 63.918 11.173 ;
     RECT  2.124 11.173 63.918 11.309 ;
     RECT  63.864 11.309 63.918 11.443 ;
     RECT  64.692 11.173 64.71 11.443 ;
     RECT  2.124 11.309 62.586 11.705 ;
     RECT  2.124 11.705 62.514 11.849 ;
     RECT  63.864 11.443 64.71 12.353 ;
     RECT  2.196 11.849 62.514 12.479 ;
     RECT  63.864 12.353 64.674 12.811 ;
     RECT  2.196 12.479 62.334 12.865 ;
     RECT  63.792 12.811 64.674 12.929 ;
     RECT  63.792 12.929 63.81 12.989 ;
     RECT  2.124 12.865 62.334 13.027 ;
     RECT  64.584 12.929 64.674 13.099 ;
     RECT  1.944 13.027 62.334 13.102 ;
     RECT  64.584 13.099 64.71 13.595 ;
     RECT  63.864 13.675 63.882 14.203 ;
     RECT  63.252 14.203 63.882 14.279 ;
     RECT  64.656 13.595 64.71 15.755 ;
     RECT  64.656 15.755 64.674 15.827 ;
     RECT  63.864 14.279 63.882 16.843 ;
     RECT  64.692 16.747 64.71 16.843 ;
     RECT  63.864 16.843 64.71 17.141 ;
     RECT  64.62 17.141 64.71 17.309 ;
     RECT  63.864 17.141 63.882 17.405 ;
     RECT  64.692 17.309 64.71 18.235 ;
     RECT  64.548 18.235 64.71 18.413 ;
     RECT  64.62 18.413 64.71 18.461 ;
     RECT  64.692 18.461 64.71 18.725 ;
     RECT  63.252 18.907 63.27 19.147 ;
     RECT  63.216 19.147 63.27 19.265 ;
     RECT  63.252 19.265 63.27 19.301 ;
     RECT  64.62 19.387 64.638 19.627 ;
     RECT  64.548 19.627 64.638 19.679 ;
     RECT  64.62 19.679 64.638 19.709 ;
     RECT  63.864 19.777 63.882 20.093 ;
     RECT  63.828 20.155 63.846 20.885 ;
     RECT  63.252 20.923 63.27 21.067 ;
     RECT  1.944 13.102 62.298 21.127 ;
     RECT  1.944 21.127 62.334 21.235 ;
     RECT  1.944 21.235 62.37 21.307 ;
     RECT  63.216 21.067 63.27 21.307 ;
     RECT  1.944 21.307 63.27 21.497 ;
     RECT  63.252 21.497 63.27 21.695 ;
     RECT  64.512 21.835 64.53 21.965 ;
     RECT  63.288 22.207 63.306 22.253 ;
     RECT  1.944 21.497 62.37 22.843 ;
     RECT  64.62 22.507 64.638 23.701 ;
     RECT  64.62 23.701 64.71 23.729 ;
     RECT  64.692 23.729 64.71 23.741 ;
     RECT  1.944 22.843 62.694 23.827 ;
     RECT  1.944 23.827 62.73 24.235 ;
     RECT  1.944 24.235 63.27 24.475 ;
     RECT  1.944 24.475 63.846 24.665 ;
     RECT  1.944 24.665 63.27 24.899 ;
     RECT  1.944 24.899 63.234 24.935 ;
     RECT  64.62 25.291 64.638 25.321 ;
     RECT  64.62 25.321 64.71 25.349 ;
     RECT  64.692 25.349 64.71 25.373 ;
     RECT  63.828 25.723 63.846 25.852 ;
     RECT  64.692 26.107 64.71 26.285 ;
     RECT  1.944 24.935 62.694 26.491 ;
     RECT  63.792 25.852 63.846 26.491 ;
     RECT  1.944 26.491 63.846 26.555 ;
     RECT  63.72 26.555 63.846 26.765 ;
     RECT  63.828 26.765 63.846 26.933 ;
     RECT  1.944 26.555 62.73 27.293 ;
     RECT  64.692 27.787 64.71 27.941 ;
     RECT  63.864 27.175 63.882 28.027 ;
     RECT  63.828 28.027 63.882 28.283 ;
     RECT  63.864 28.283 63.882 28.829 ;
     RECT  64.62 28.891 64.638 29.179 ;
     RECT  64.62 29.179 64.71 29.561 ;
     RECT  64.62 29.561 64.638 29.789 ;
     RECT  63.252 29.899 63.27 30.187 ;
     RECT  63.216 30.187 63.27 30.407 ;
     RECT  63.252 30.407 63.27 30.443 ;
     RECT  64.692 31.051 64.71 31.145 ;
     RECT  63.828 30.667 63.846 31.291 ;
     RECT  63.792 31.291 63.846 31.487 ;
     RECT  63.828 31.487 63.846 32.027 ;
     RECT  64.692 32.827 64.71 33.115 ;
     RECT  64.62 33.115 64.71 33.728 ;
     RECT  64.62 33.728 64.674 34.219 ;
     RECT  64.512 34.219 64.674 34.459 ;
     RECT  64.512 34.459 64.71 34.493 ;
     RECT  64.548 34.493 64.71 34.733 ;
     RECT  1.944 27.293 62.37 34.997 ;
     RECT  0.864 35.437 0.882 35.815 ;
     RECT  1.944 34.997 62.334 35.815 ;
     RECT  0.864 35.815 62.334 35.977 ;
     RECT  64.62 34.733 64.71 36.041 ;
     RECT  63.72 36.139 63.738 36.235 ;
     RECT  63.72 36.235 63.846 36.269 ;
     RECT  63.828 36.269 63.846 36.763 ;
     RECT  64.62 36.041 64.638 36.763 ;
     RECT  63.828 36.763 64.638 36.859 ;
     RECT  63.828 36.859 64.71 36.893 ;
     RECT  64.62 36.893 64.71 37.565 ;
     RECT  63.828 36.893 63.846 38.002 ;
     RECT  63.792 38.002 63.846 38.003 ;
     RECT  63.792 38.003 63.81 38.048 ;
     RECT  64.692 37.565 64.71 38.539 ;
     RECT  64.62 38.539 64.71 38.635 ;
     RECT  64.548 38.635 64.71 38.705 ;
     RECT  64.548 38.705 64.638 39.197 ;
     RECT  64.62 39.197 64.638 40.171 ;
     RECT  64.476 40.171 64.638 40.315 ;
     RECT  64.476 40.315 64.674 40.349 ;
     RECT  64.512 40.349 64.674 40.361 ;
     RECT  64.512 40.361 64.638 40.445 ;
     RECT  0.54 35.977 62.334 40.555 ;
     RECT  0.54 40.555 62.694 41.323 ;
     RECT  0.54 41.323 63.27 41.369 ;
     RECT  63.828 41.803 63.846 41.909 ;
     RECT  0.54 41.369 62.694 42.571 ;
     RECT  0.54 42.571 63.27 42.629 ;
     RECT  63.216 42.629 63.27 42.727 ;
     RECT  63.216 42.727 63.882 42.989 ;
     RECT  63.216 42.989 63.846 43.799 ;
     RECT  64.692 43.819 64.71 44.347 ;
     RECT  64.656 44.347 64.71 44.411 ;
     RECT  63.792 43.799 63.846 44.581 ;
     RECT  63.288 44.581 63.846 44.621 ;
     RECT  63.828 44.621 63.846 44.879 ;
     RECT  64.692 44.411 64.71 45.211 ;
     RECT  64.656 45.211 64.71 45.329 ;
     RECT  63.864 45.427 63.882 46.013 ;
     RECT  64.692 45.329 64.71 46.535 ;
     RECT  0.54 42.629 62.334 46.603 ;
     RECT  64.692 47.275 64.71 47.453 ;
     RECT  0.54 46.603 62.694 47.995 ;
     RECT  0.54 47.995 63.27 48.523 ;
     RECT  0.54 48.523 63.846 48.941 ;
     RECT  64.692 48.973 64.71 49.037 ;
     RECT  63.216 48.941 63.846 49.469 ;
     RECT  63.288 49.469 63.846 49.747 ;
     RECT  63.288 49.747 63.882 50.093 ;
     RECT  63.756 50.093 63.882 50.333 ;
     RECT  63.756 50.333 63.846 50.549 ;
     RECT  0.54 48.941 62.334 50.819 ;
     RECT  63.756 50.549 63.774 50.819 ;
     RECT  64.692 50.539 64.71 51.067 ;
     RECT  12.78 50.819 62.334 51.097 ;
     RECT  12.78 51.097 62.694 51.307 ;
     RECT  64.656 51.067 64.71 51.629 ;
     RECT  12.78 51.307 63.27 51.691 ;
     RECT  0.54 50.819 12.006 51.871 ;
     RECT  12.78 51.691 63.846 51.871 ;
     RECT  0.54 51.871 63.846 52.141 ;
     RECT  0.54 52.141 63.882 52.205 ;
     RECT  0.54 52.205 63.846 52.277 ;
     RECT  64.692 51.629 64.71 52.459 ;
     RECT  0.54 52.277 63.27 53.059 ;
     RECT  0.54 53.059 63.306 53.597 ;
     RECT  39.564 53.597 63.306 53.599 ;
     RECT  64.656 52.459 64.71 53.897 ;
     RECT  64.656 53.897 64.674 53.933 ;
     RECT  39.564 53.599 63.918 54.125 ;
     RECT  64.62 54.379 64.638 54.509 ;
     RECT  39.564 54.125 63.846 54.859 ;
     RECT  39.564 54.859 63.882 55.021 ;
     RECT  39.564 55.021 63.954 55.651 ;
     RECT  64.692 55.627 64.71 55.651 ;
     RECT  39.564 55.651 64.71 55.709 ;
     RECT  39.564 55.709 63.954 56.539 ;
     RECT  64.692 55.709 64.71 56.539 ;
     RECT  39.564 56.539 64.71 56.867 ;
     RECT  39.564 56.867 64.674 57.739 ;
     RECT  39.564 57.739 64.71 59.467 ;
     RECT  0.54 53.597 38.826 63.859 ;
     RECT  0.324 63.859 38.826 64.603 ;
     RECT  39.564 59.467 64.782 64.603 ;
     RECT  0.324 64.603 64.782 64.625 ;
     RECT  0.324 64.625 64.746 64.699 ;
     RECT  0.072 64.699 64.746 64.781 ;
    LAYER M4 ;
     RECT  0.044 64.704 0.131 64.728 ;
     RECT  0.181 2.256 0.421 2.28 ;
     RECT  0.421 2.064 0.661 2.28 ;
     RECT  0.661 2.064 0.881 2.904 ;
     RECT  0.181 46.128 0.892 46.152 ;
     RECT  0.892 46.128 0.893 46.2 ;
     RECT  0.881 2.064 0.965 2.952 ;
     RECT  1.189 0.72 1.429 0.744 ;
     RECT  1.429 41.472 1.669 41.496 ;
     RECT  0.965 2.064 1.925 2.904 ;
     RECT  1.925 1.728 2.009 2.904 ;
     RECT  2.009 2.064 2.197 2.904 ;
     RECT  2.197 2.064 2.245 3.72 ;
     RECT  2.197 6.912 2.285 6.936 ;
     RECT  2.285 6.288 2.293 6.936 ;
     RECT  1.909 38.688 2.293 38.712 ;
     RECT  2.197 40.176 2.293 40.2 ;
     RECT  2.245 2.064 2.408 4.536 ;
     RECT  2.293 6.288 2.408 7.656 ;
     RECT  2.329 12.528 2.408 12.552 ;
     RECT  0.085 34.656 2.408 34.68 ;
     RECT  0.661 36.384 2.408 36.408 ;
     RECT  2.293 38.688 2.408 40.2 ;
     RECT  1.669 41.472 2.408 41.784 ;
     RECT  0.893 46.176 2.408 46.2 ;
     RECT  1.189 47.472 2.408 47.496 ;
     RECT  1.429 0.576 2.437 0.744 ;
     RECT  2.408 2.064 2.512 62.652 ;
     RECT  2.437 0.576 2.677 0.888 ;
     RECT  2.512 2.064 2.704 62.382 ;
     RECT  2.677 0.096 3.041 0.888 ;
     RECT  2.704 2.064 3.041 12.552 ;
     RECT  2.704 34.656 3.155 36.552 ;
     RECT  3.041 0.096 3.341 12.552 ;
     RECT  0.421 64.656 3.445 64.68 ;
     RECT  3.341 0.096 3.521 3.432 ;
     RECT  3.341 4.512 3.521 12.552 ;
     RECT  3.445 64.608 3.635 64.68 ;
     RECT  2.704 49.008 3.673 49.032 ;
     RECT  2.704 13.584 3.733 15.144 ;
     RECT  3.521 9.888 3.877 12.552 ;
     RECT  3.733 13.536 3.877 15.144 ;
     RECT  3.797 31.92 3.881 31.944 ;
     RECT  3.884 47.904 3.971 47.928 ;
     RECT  3.685 46.656 3.989 46.68 ;
     RECT  3.521 0.576 4.025 3.432 ;
     RECT  3.155 34.656 4.237 35.592 ;
     RECT  4.237 34.656 4.321 35.928 ;
     RECT  4.025 0.576 4.355 0.6 ;
     RECT  3.877 9.888 4.385 15.144 ;
     RECT  4.213 31.344 4.385 31.368 ;
     RECT  4.32 39.264 4.429 39.288 ;
     RECT  4.025 1.728 4.46 3.432 ;
     RECT  3.521 4.512 4.46 8.76 ;
     RECT  4.46 1.728 4.561 8.76 ;
     RECT  4.561 1.728 4.741 8.856 ;
     RECT  4.385 9.888 4.741 14.664 ;
     RECT  4.741 1.728 4.787 14.664 ;
     RECT  4.787 1.728 4.828 13.8 ;
     RECT  4.828 2.88 4.883 13.8 ;
     RECT  4.556 38.736 4.979 38.76 ;
     RECT  4.883 3.936 5.105 13.8 ;
     RECT  4.321 34.656 5.365 35.352 ;
     RECT  5.317 36.432 5.365 36.456 ;
     RECT  5.365 34.656 5.401 36.456 ;
     RECT  5.105 3.936 5.459 13.656 ;
     RECT  5.401 34.656 5.465 35.928 ;
     RECT  5.459 3.984 5.507 13.656 ;
     RECT  3.635 64.656 5.569 64.68 ;
     RECT  5.557 50.112 5.643 50.136 ;
     RECT  5.643 50.064 5.644 50.136 ;
     RECT  5.644 50.064 5.653 50.088 ;
     RECT  5.507 5.664 5.681 13.656 ;
     RECT  5.569 64.608 5.701 64.68 ;
     RECT  4.828 1.728 5.893 1.8 ;
     RECT  4.883 2.88 5.893 2.952 ;
     RECT  5.653 49.584 5.933 50.088 ;
     RECT  5.701 64.512 6.131 64.68 ;
     RECT  6.092 55.008 6.133 55.032 ;
     RECT  6.073 37.008 6.157 37.032 ;
     RECT  5.965 44.976 6.179 45 ;
     RECT  6.133 54.72 6.179 55.032 ;
     RECT  5.933 49.584 6.227 49.608 ;
     RECT  5.465 34.656 6.265 35.352 ;
     RECT  6.179 54.72 6.293 54.744 ;
     RECT  5.893 1.728 6.301 2.952 ;
     RECT  5.681 5.664 6.364 13.272 ;
     RECT  5.507 3.984 6.365 4.68 ;
     RECT  6.301 2.832 6.445 2.952 ;
     RECT  6.325 42.048 6.473 42.072 ;
     RECT  6.365 3.984 6.563 4.008 ;
     RECT  6.364 5.664 6.572 12.408 ;
     RECT  6.469 0.096 6.581 0.12 ;
     RECT  6.325 53.04 6.653 53.064 ;
     RECT  6.265 34.656 6.803 34.824 ;
     RECT  6.937 38.16 7.148 38.184 ;
     RECT  6.997 3.408 7.441 3.432 ;
     RECT  6.301 1.728 7.477 1.752 ;
     RECT  7.441 2.832 7.477 3.432 ;
     RECT  7.148 38.16 7.477 38.472 ;
     RECT  7.477 38.16 7.621 39.336 ;
     RECT  7.477 1.728 7.808 3.432 ;
     RECT  6.572 5.088 7.808 12.408 ;
     RECT  6.803 34.656 7.808 34.68 ;
     RECT  7.621 37.44 7.808 39.336 ;
     RECT  7.621 50.832 7.808 50.856 ;
     RECT  7.808 1.728 7.912 62.652 ;
     RECT  6.131 64.656 7.957 64.68 ;
     RECT  7.912 1.728 8.104 62.382 ;
     RECT  8.104 50.832 8.165 52.488 ;
     RECT  8.165 51.264 8.243 52.488 ;
     RECT  7.957 64.416 8.243 64.68 ;
     RECT  8.104 38.736 8.291 39.336 ;
     RECT  8.104 43.152 8.339 43.176 ;
     RECT  8.104 53.568 8.339 54.12 ;
     RECT  8.104 1.728 8.381 3 ;
     RECT  8.339 53.568 8.381 53.592 ;
     RECT  8.381 1.728 8.531 2.904 ;
     RECT  8.104 46.176 8.572 46.2 ;
     RECT  8.104 40.416 8.771 40.44 ;
     RECT  8.243 64.464 8.813 64.68 ;
     RECT  8.243 51.888 8.921 52.488 ;
     RECT  8.813 64.56 9.059 64.68 ;
     RECT  8.921 51.888 9.073 52.44 ;
     RECT  9.059 64.656 9.281 64.68 ;
     RECT  8.104 4.704 9.389 12.36 ;
     RECT  9.073 51.888 9.425 51.912 ;
     RECT  8.291 38.736 9.452 39.048 ;
     RECT  9.452 38.736 9.539 39.096 ;
     RECT  9.539 38.736 9.673 38.856 ;
     RECT  9.673 38.256 9.779 38.856 ;
     RECT  8.531 2.88 9.965 2.904 ;
     RECT  9.389 4.704 10.001 12.264 ;
     RECT  9.779 38.832 10.019 38.856 ;
     RECT  10.213 40.992 10.361 41.016 ;
     RECT  10.261 0.096 10.505 0.12 ;
     RECT  8.531 1.728 10.717 1.752 ;
     RECT  10.709 64.656 10.834 64.68 ;
     RECT  10.717 1.728 10.835 1.848 ;
     RECT  10.501 39.312 10.94 39.336 ;
     RECT  10.925 40.416 10.94 40.44 ;
     RECT  10.001 5.232 10.969 12.264 ;
     RECT  10.933 51.984 10.981 52.008 ;
     RECT  10.834 64.608 10.981 64.68 ;
     RECT  10.94 39.312 11.009 40.44 ;
     RECT  10.933 52.992 11.017 53.016 ;
     RECT  10.981 51.888 11.077 52.008 ;
     RECT  11.009 39.312 11.18 39.912 ;
     RECT  10.969 4.992 11.185 12.264 ;
     RECT  11.185 4.224 11.365 12.264 ;
     RECT  10.981 64.512 11.501 64.68 ;
     RECT  11.077 51.888 11.509 52.44 ;
     RECT  11.501 63.888 11.516 64.68 ;
     RECT  11.18 38.736 11.555 39.912 ;
     RECT  11.029 2.88 11.603 2.904 ;
     RECT  11.516 63.744 11.603 64.68 ;
     RECT  11.603 63.84 11.657 64.68 ;
     RECT  11.509 51.312 11.729 52.44 ;
     RECT  11.657 64.512 11.842 64.68 ;
     RECT  11.842 64.512 11.939 64.728 ;
     RECT  11.365 4.224 11.977 12.312 ;
     RECT  11.977 4.224 12.085 12.552 ;
     RECT  11.939 64.512 12.593 64.68 ;
     RECT  11.555 39.072 12.725 39.912 ;
     RECT  12.085 4.128 12.913 12.552 ;
     RECT  12.725 39.072 13.093 40.056 ;
     RECT  10.835 1.728 13.208 1.752 ;
     RECT  12.913 4.128 13.208 13.08 ;
     RECT  8.104 34.656 13.208 34.68 ;
     RECT  13.093 39.072 13.208 40.2 ;
     RECT  11.729 51.888 13.208 52.44 ;
     RECT  13.208 1.728 13.312 62.652 ;
     RECT  13.312 1.728 13.504 62.382 ;
     RECT  13.504 1.728 13.619 14.136 ;
     RECT  13.619 1.728 13.637 1.8 ;
     RECT  13.619 3.36 13.637 14.136 ;
     RECT  13.504 40.176 14.051 40.2 ;
     RECT  13.637 3.984 14.465 14.136 ;
     RECT  14.605 40.416 14.689 41.016 ;
     RECT  12.037 0.096 14.867 0.12 ;
     RECT  13.637 1.728 15.001 1.752 ;
     RECT  15.001 1.104 15.107 1.752 ;
     RECT  14.689 40.416 15.229 40.44 ;
     RECT  12.593 64.656 15.253 64.68 ;
     RECT  15.107 1.728 15.365 1.752 ;
     RECT  15.253 64.416 15.365 64.68 ;
     RECT  14.465 4.224 15.505 14.136 ;
     RECT  15.505 3.84 15.509 14.136 ;
     RECT  15.509 3.84 15.589 13.368 ;
     RECT  15.589 2.88 15.653 13.368 ;
     RECT  15.577 41.568 15.661 41.592 ;
     RECT  15.653 2.88 15.725 12.552 ;
     RECT  15.365 64.608 16.049 64.68 ;
     RECT  16.124 41.52 16.22 41.544 ;
     RECT  16.22 41.232 16.307 41.544 ;
     RECT  15.725 3.84 16.481 12.552 ;
     RECT  16.307 41.52 16.589 41.544 ;
     RECT  16.069 0.096 16.697 0.12 ;
     RECT  16.357 1.728 16.729 1.752 ;
     RECT  16.481 11.136 16.732 12.552 ;
     RECT  16.732 11.232 16.801 12.552 ;
     RECT  16.801 11.232 16.805 13.128 ;
     RECT  16.049 64.608 16.841 64.632 ;
     RECT  16.729 1.728 16.883 2.28 ;
     RECT  16.883 1.728 16.981 2.184 ;
     RECT  16.481 3.84 16.981 10.104 ;
     RECT  16.981 3.408 17.021 10.104 ;
     RECT  16.988 41.76 17.075 42.072 ;
     RECT  16.805 13.104 17.125 13.128 ;
     RECT  17.075 41.76 17.171 41.784 ;
     RECT  16.369 16.656 17.237 16.68 ;
     RECT  17.021 3.408 17.309 4.248 ;
     RECT  17.021 5.424 17.773 10.104 ;
     RECT  16.805 11.232 17.773 11.736 ;
     RECT  16.981 1.152 17.804 2.184 ;
     RECT  17.804 1.104 17.891 2.184 ;
     RECT  17.309 3.936 18.025 4.248 ;
     RECT  17.773 5.424 18.025 11.736 ;
     RECT  18.025 3.936 18.097 11.736 ;
     RECT  17.125 13.104 18.097 13.32 ;
     RECT  18.017 45.552 18.236 45.576 ;
     RECT  17.891 2.016 18.469 2.184 ;
     RECT  17.125 64.656 18.569 64.68 ;
     RECT  18.469 2.016 18.608 2.808 ;
     RECT  18.097 3.936 18.608 13.32 ;
     RECT  18.025 17.712 18.608 17.736 ;
     RECT  13.504 34.656 18.608 34.68 ;
     RECT  17.509 43.296 18.608 43.32 ;
     RECT  18.236 45.024 18.608 45.576 ;
     RECT  18.608 2.016 18.659 62.652 ;
     RECT  18.659 2.148 18.712 62.652 ;
     RECT  18.712 2.304 18.904 62.382 ;
     RECT  18.805 64.608 19.043 64.632 ;
     RECT  18.853 0.096 19.073 0.12 ;
     RECT  18.904 16.896 19.109 16.92 ;
     RECT  18.904 45.024 19.145 45.576 ;
     RECT  18.904 2.304 19.253 2.328 ;
     RECT  18.904 13.152 19.253 13.176 ;
     RECT  18.904 18.384 19.901 18.792 ;
     RECT  19.349 0.576 19.937 0.6 ;
     RECT  19.853 1.728 20.06 1.752 ;
     RECT  20.06 1.104 20.147 1.752 ;
     RECT  18.904 3.888 20.189 11.736 ;
     RECT  20.005 14.976 20.333 15 ;
     RECT  20.189 3.888 20.389 4.248 ;
     RECT  20.492 58.704 20.579 58.728 ;
     RECT  20.147 1.728 20.869 1.752 ;
     RECT  20.869 1.728 20.981 1.8 ;
     RECT  20.981 1.776 21.089 1.8 ;
     RECT  21.02 43.296 21.107 43.32 ;
     RECT  20.389 3.264 21.157 4.248 ;
     RECT  21.157 2.88 21.233 4.248 ;
     RECT  20.833 20.64 21.233 20.664 ;
     RECT  21.233 2.88 21.305 2.904 ;
     RECT  21.233 4.224 21.409 4.248 ;
     RECT  20.189 5.472 21.409 11.736 ;
     RECT  21.397 0.576 21.521 0.6 ;
     RECT  21.409 4.224 21.557 11.736 ;
     RECT  21.637 0.096 21.845 0.168 ;
     RECT  19.145 45.024 22.057 45.048 ;
     RECT  21.845 0.144 22.097 0.168 ;
     RECT  22.057 45.024 22.595 45.576 ;
     RECT  22.165 1.728 22.645 1.752 ;
     RECT  21.557 4.224 22.741 4.248 ;
     RECT  22.633 18.768 22.745 18.792 ;
     RECT  22.633 14.832 22.781 14.856 ;
     RECT  21.557 5.472 22.885 11.736 ;
     RECT  22.813 20.592 22.961 20.616 ;
     RECT  22.885 0.096 23.069 0.12 ;
     RECT  22.741 3.984 23.101 4.248 ;
     RECT  22.885 5.424 23.101 11.736 ;
     RECT  22.645 1.728 23.173 1.8 ;
     RECT  23.101 3.792 23.269 11.736 ;
     RECT  23.372 0.528 23.459 0.552 ;
     RECT  23.173 1.728 23.857 2.328 ;
     RECT  23.269 3.696 23.857 11.736 ;
     RECT  23.857 1.728 24.008 11.736 ;
     RECT  23.533 14.448 24.008 14.472 ;
     RECT  23.353 23.28 24.008 23.304 ;
     RECT  18.904 34.656 24.008 34.68 ;
     RECT  22.595 45.024 24.008 45.048 ;
     RECT  24.008 1.728 24.304 62.652 ;
     RECT  24.181 0.144 24.419 0.168 ;
     RECT  24.304 3.024 24.419 11.736 ;
     RECT  24.304 16.224 24.437 17.064 ;
     RECT  24.304 23.808 24.437 23.928 ;
     RECT  24.325 62.736 24.437 62.76 ;
     RECT  24.304 48.48 24.467 49.032 ;
     RECT  24.437 23.808 24.473 23.88 ;
     RECT  24.437 17.04 24.761 17.064 ;
     RECT  23.785 64.656 24.947 64.68 ;
     RECT  24.473 23.856 25.193 23.88 ;
     RECT  24.304 1.728 25.369 1.752 ;
     RECT  24.304 45.552 25.379 45.576 ;
     RECT  24.419 3.264 25.445 11.736 ;
     RECT  25.369 1.728 25.475 2.28 ;
     RECT  25.445 3.264 25.517 4.248 ;
     RECT  24.467 49.008 25.532 49.032 ;
     RECT  25.445 5.28 26.057 11.736 ;
     RECT  25.532 48.48 26.147 49.032 ;
     RECT  26.017 14.832 26.237 14.856 ;
     RECT  26.057 5.28 26.273 10.632 ;
     RECT  25.945 27.312 26.413 27.336 ;
     RECT  25.475 1.728 26.677 1.752 ;
     RECT  26.677 1.728 26.777 1.8 ;
     RECT  26.413 26.352 26.813 27.336 ;
     RECT  26.273 5.28 27.101 10.104 ;
     RECT  26.147 49.008 27.109 49.032 ;
     RECT  26.813 26.352 27.209 27.192 ;
     RECT  25.517 4.224 27.277 4.248 ;
     RECT  27.101 5.28 27.277 6.168 ;
     RECT  26.777 1.728 27.353 1.752 ;
     RECT  27.445 1.152 27.533 1.176 ;
     RECT  27.101 7.2 27.601 10.104 ;
     RECT  27.109 48.48 27.649 49.032 ;
     RECT  27.277 4.224 27.965 6.168 ;
     RECT  27.965 5.472 28.069 6.168 ;
     RECT  27.601 7.2 28.069 10.632 ;
     RECT  27.973 2.88 28.109 2.904 ;
     RECT  27.649 48.48 28.837 48.504 ;
     RECT  27.965 4.224 28.861 4.248 ;
     RECT  28.421 1.728 28.897 1.752 ;
     RECT  28.897 1.104 29.027 1.752 ;
     RECT  28.861 3.888 29.081 4.248 ;
     RECT  29.081 3.84 29.113 4.248 ;
     RECT  29.027 1.728 29.269 1.752 ;
     RECT  29.113 3.84 29.269 4.344 ;
     RECT  28.837 48.48 29.269 48.552 ;
     RECT  29.221 64.56 29.269 64.584 ;
     RECT  25.513 0.096 29.297 0.12 ;
     RECT  29.269 1.728 29.408 1.8 ;
     RECT  29.269 3.312 29.408 4.344 ;
     RECT  28.069 5.472 29.408 10.632 ;
     RECT  26.057 11.712 29.408 11.736 ;
     RECT  27.209 27.168 29.408 27.192 ;
     RECT  24.304 34.656 29.408 34.68 ;
     RECT  29.269 48.48 29.408 48.696 ;
     RECT  29.221 52.272 29.408 52.296 ;
     RECT  29.408 1.728 29.512 62.652 ;
     RECT  29.269 64.56 29.651 64.68 ;
     RECT  29.512 1.728 29.704 62.382 ;
     RECT  29.704 27.168 29.801 27.336 ;
     RECT  29.704 3.84 29.837 4.248 ;
     RECT  29.704 61.248 29.873 61.272 ;
     RECT  29.837 3.888 29.945 4.248 ;
     RECT  29.704 1.728 30.125 2.76 ;
     RECT  29.704 29.28 30.269 29.592 ;
     RECT  29.704 48.48 30.457 49.032 ;
     RECT  30.269 29.568 30.701 29.592 ;
     RECT  30.457 48.48 30.737 48.504 ;
     RECT  29.801 27.312 30.805 27.336 ;
     RECT  30.757 0.096 30.899 0.12 ;
     RECT  29.704 5.472 30.949 10.632 ;
     RECT  30.805 26.832 30.953 27.336 ;
     RECT  30.125 2.304 31.057 2.76 ;
     RECT  29.945 4.224 31.057 4.248 ;
     RECT  31.057 2.304 31.165 4.248 ;
     RECT  30.949 5.424 31.165 10.632 ;
     RECT  29.704 11.712 31.165 11.736 ;
     RECT  31.165 2.304 31.229 11.736 ;
     RECT  31.229 1.728 31.241 11.736 ;
     RECT  31.241 3.264 31.313 11.736 ;
     RECT  31.313 11.184 31.385 11.736 ;
     RECT  29.704 34.656 31.385 34.68 ;
     RECT  31.129 49.536 31.484 49.56 ;
     RECT  31.445 0.576 31.529 0.6 ;
     RECT  31.484 48.816 31.571 49.56 ;
     RECT  31.571 49.056 31.907 49.56 ;
     RECT  31.241 1.728 32.245 1.752 ;
     RECT  31.313 4.224 32.425 10.104 ;
     RECT  32.245 1.248 32.429 1.752 ;
     RECT  30.953 27.312 32.437 27.336 ;
     RECT  32.425 4.224 32.465 10.728 ;
     RECT  32.437 27.12 32.483 27.336 ;
     RECT  32.425 34.224 32.509 34.248 ;
     RECT  32.465 5.472 32.533 10.728 ;
     RECT  31.385 11.712 32.533 11.736 ;
     RECT  31.813 31.824 32.537 31.848 ;
     RECT  29.651 64.656 32.645 64.68 ;
     RECT  32.429 1.728 32.773 1.752 ;
     RECT  32.773 1.728 32.929 1.8 ;
     RECT  31.907 49.536 32.941 49.56 ;
     RECT  32.929 1.728 33.037 2.088 ;
     RECT  33.037 1.728 33.059 3 ;
     RECT  33.059 2.976 33.293 3 ;
     RECT  32.533 5.472 33.329 11.736 ;
     RECT  32.569 52.464 33.397 52.488 ;
     RECT  32.465 4.224 33.541 4.248 ;
     RECT  33.329 5.472 33.541 9.048 ;
     RECT  33.397 52.416 33.596 52.488 ;
     RECT  33.596 52.416 33.617 52.536 ;
     RECT  33.253 18.816 33.757 18.84 ;
     RECT  33.617 52.464 33.857 52.536 ;
     RECT  33.757 18.816 33.965 18.936 ;
     RECT  33.757 0.096 34.067 0.12 ;
     RECT  33.541 4.224 34.081 9.048 ;
     RECT  33.685 20.688 34.117 20.712 ;
     RECT  33.059 1.728 34.261 1.752 ;
     RECT  34.081 4.176 34.405 9.048 ;
     RECT  34.261 1.68 34.441 1.752 ;
     RECT  34.405 4.032 34.549 9.048 ;
     RECT  33.329 10.08 34.549 11.736 ;
     RECT  34.549 4.032 34.585 11.736 ;
     RECT  34.585 3.936 34.621 11.736 ;
     RECT  34.441 1.68 34.765 2.28 ;
     RECT  34.765 1.2 34.808 2.28 ;
     RECT  34.621 3.84 34.808 11.736 ;
     RECT  33.965 18.816 34.808 19.08 ;
     RECT  34.117 20.64 34.808 20.712 ;
     RECT  34.405 21.696 34.808 21.72 ;
     RECT  32.483 27.12 34.808 27.144 ;
     RECT  33.829 33.456 34.808 33.48 ;
     RECT  33.857 52.464 34.808 53.016 ;
     RECT  34.808 1.2 34.912 62.652 ;
     RECT  34.912 1.2 35.104 62.382 ;
     RECT  34.885 64.608 35.125 64.632 ;
     RECT  35.125 64.512 35.219 64.632 ;
     RECT  35.219 64.512 35.267 64.536 ;
     RECT  35.104 1.2 35.381 11.4 ;
     RECT  35.381 1.2 35.669 11.304 ;
     RECT  35.104 52.464 35.705 53.016 ;
     RECT  35.669 1.2 35.777 11.256 ;
     RECT  35.104 23.04 35.777 23.064 ;
     RECT  35.777 1.2 36.173 4.056 ;
     RECT  35.777 5.088 36.425 11.256 ;
     RECT  36.565 0.096 36.785 0.12 ;
     RECT  36.425 5.088 36.817 11.016 ;
     RECT  36.817 4.992 37.372 11.016 ;
     RECT  35.104 27.12 37.433 27.144 ;
     RECT  37.372 10.224 37.537 11.016 ;
     RECT  37.537 10.224 37.933 11.352 ;
     RECT  36.173 1.2 38.005 4.008 ;
     RECT  37.372 4.992 38.005 9.24 ;
     RECT  35.705 52.464 38.108 52.488 ;
     RECT  37.933 10.224 38.365 11.4 ;
     RECT  38.005 1.2 38.401 9.24 ;
     RECT  38.365 10.224 38.401 11.688 ;
     RECT  38.108 51.936 38.485 52.488 ;
     RECT  38.492 27.072 38.533 27.096 ;
     RECT  38.485 39.888 38.572 39.912 ;
     RECT  38.533 26.784 38.579 27.096 ;
     RECT  38.485 51.888 38.693 52.488 ;
     RECT  38.693 52.464 38.725 52.488 ;
     RECT  38.221 36.864 38.729 36.888 ;
     RECT  38.579 26.784 38.771 26.808 ;
     RECT  38.401 1.2 38.797 11.784 ;
     RECT  38.797 1.2 38.821 11.832 ;
     RECT  38.725 52.464 38.917 52.536 ;
     RECT  37.669 64.656 39.049 64.68 ;
     RECT  38.684 40.416 39.059 40.44 ;
     RECT  39.077 40.896 39.116 40.92 ;
     RECT  38.917 52.464 39.157 53.016 ;
     RECT  39.049 64.608 39.157 64.68 ;
     RECT  39.116 40.896 39.161 41.016 ;
     RECT  39.161 40.992 39.203 41.016 ;
     RECT  39.157 52.464 39.229 53.064 ;
     RECT  39.157 64.512 39.26 64.68 ;
     RECT  39.26 64.512 39.299 64.728 ;
     RECT  39.299 64.56 39.347 64.728 ;
     RECT  38.821 0.576 39.373 11.832 ;
     RECT  39.373 0.576 39.661 12.264 ;
     RECT  39.337 41.568 39.685 41.592 ;
     RECT  39.661 0.576 39.805 12.888 ;
     RECT  39.805 0.576 40.021 13.608 ;
     RECT  40.021 0.528 40.208 13.608 ;
     RECT  39.625 25.296 40.208 25.32 ;
     RECT  39.685 41.568 40.208 42.36 ;
     RECT  39.229 52.464 40.208 53.592 ;
     RECT  38.533 59.712 40.208 59.736 ;
     RECT  39.347 64.56 40.211 64.68 ;
     RECT  40.208 0.528 40.312 62.652 ;
     RECT  40.312 0.528 40.504 62.382 ;
     RECT  40.504 0.528 40.597 12.888 ;
     RECT  40.504 52.992 40.643 54.168 ;
     RECT  40.211 64.656 40.643 64.68 ;
     RECT  40.643 53.376 40.979 54.168 ;
     RECT  40.979 53.568 41.221 54.168 ;
     RECT  40.504 14.736 41.429 14.856 ;
     RECT  40.504 15.984 41.497 16.536 ;
     RECT  40.504 40.512 41.573 40.584 ;
     RECT  40.597 0.096 41.605 12.888 ;
     RECT  41.605 0.096 41.609 13.608 ;
     RECT  41.221 54.096 41.641 54.168 ;
     RECT  41.641 54.096 41.645 54.216 ;
     RECT  41.573 40.512 41.681 40.536 ;
     RECT  41.497 15.984 41.965 16.968 ;
     RECT  41.645 54.144 42.028 54.216 ;
     RECT  40.504 39.264 42.037 39.288 ;
     RECT  41.965 15.984 42.073 17.208 ;
     RECT  42.037 39.264 42.145 39.528 ;
     RECT  41.785 41.76 42.325 41.784 ;
     RECT  42.253 54.384 42.337 54.696 ;
     RECT  40.504 25.296 42.437 25.32 ;
     RECT  42.577 18.768 42.649 18.792 ;
     RECT  42.325 41.76 42.721 42.024 ;
     RECT  42.181 64.656 42.725 64.68 ;
     RECT  41.609 0.096 42.793 10.728 ;
     RECT  41.609 11.712 42.793 13.608 ;
     RECT  42.337 54.384 42.833 54.504 ;
     RECT  42.757 28.08 42.905 28.104 ;
     RECT  42.721 41.712 42.977 42.024 ;
     RECT  42.833 54.48 43.235 54.504 ;
     RECT  42.949 55.872 43.397 55.896 ;
     RECT  42.977 41.712 43.553 41.736 ;
     RECT  42.793 0.096 43.841 13.608 ;
     RECT  43.405 25.248 44.273 25.272 ;
     RECT  43.841 0.192 44.869 13.608 ;
     RECT  44.869 0.096 45.608 13.608 ;
     RECT  41.429 14.736 45.608 14.76 ;
     RECT  42.073 15.792 45.608 17.688 ;
     RECT  42.649 18.768 45.608 19.32 ;
     RECT  43.945 21.456 45.608 21.48 ;
     RECT  44.341 26.64 45.608 26.664 ;
     RECT  40.504 38.16 45.608 38.184 ;
     RECT  42.145 39.264 45.608 39.816 ;
     RECT  43.397 55.872 45.608 56.424 ;
     RECT  40.504 59.712 45.608 59.736 ;
     RECT  45.445 64.656 45.733 64.68 ;
     RECT  45.608 0.096 45.904 62.652 ;
     RECT  45.904 0.096 45.937 13.608 ;
     RECT  45.904 62.16 46.019 62.652 ;
     RECT  45.904 56.352 46.067 56.376 ;
     RECT  45.733 64.608 46.067 64.68 ;
     RECT  45.904 26.256 46.397 27.912 ;
     RECT  46.067 64.656 46.541 64.68 ;
     RECT  45.904 61.008 46.787 61.032 ;
     RECT  46.397 27.12 46.901 27.912 ;
     RECT  46.901 27.312 46.933 27.912 ;
     RECT  45.904 31.488 46.973 31.512 ;
     RECT  46.933 27.312 47.261 28.2 ;
     RECT  45.937 0.192 47.401 13.608 ;
     RECT  47.401 0.096 47.485 13.608 ;
     RECT  47.261 27.888 47.693 27.912 ;
     RECT  47.869 30.528 47.941 30.552 ;
     RECT  45.904 14.736 48.049 14.76 ;
     RECT  47.485 0.192 48.161 13.608 ;
     RECT  48.049 14.736 48.161 14.808 ;
     RECT  46.205 62.688 48.188 62.712 ;
     RECT  47.941 30.528 48.269 30.6 ;
     RECT  48.188 62.16 48.275 62.712 ;
     RECT  48.269 30.528 48.629 30.552 ;
     RECT  48.275 62.64 48.809 62.712 ;
     RECT  48.481 31.68 49.025 31.704 ;
     RECT  48.661 47.712 49.025 47.736 ;
     RECT  48.956 64.656 49.043 64.68 ;
     RECT  49.813 50.16 50.137 50.184 ;
     RECT  48.161 0.192 50.417 10.728 ;
     RECT  48.809 62.64 50.677 62.664 ;
     RECT  50.677 62.64 50.781 62.712 ;
     RECT  50.781 62.64 50.821 62.664 ;
     RECT  50.821 64.56 50.869 64.584 ;
     RECT  50.417 0.096 51.008 10.728 ;
     RECT  48.161 11.712 51.008 13.608 ;
     RECT  48.161 14.736 51.008 14.76 ;
     RECT  45.904 15.792 51.008 17.688 ;
     RECT  45.904 18.768 51.008 19.32 ;
     RECT  45.904 21.456 51.008 21.48 ;
     RECT  50.281 26.784 51.008 26.808 ;
     RECT  50.533 27.936 51.008 27.96 ;
     RECT  50.137 30.72 51.008 30.744 ;
     RECT  49.957 34.896 51.008 34.92 ;
     RECT  45.904 38.16 51.008 38.184 ;
     RECT  45.904 39.264 51.008 39.816 ;
     RECT  50.137 50.16 51.008 50.28 ;
     RECT  45.904 59.712 51.008 59.736 ;
     RECT  50.821 62.16 51.008 62.664 ;
     RECT  51.008 0.096 51.011 62.664 ;
     RECT  50.869 64.56 51.059 64.68 ;
     RECT  51.059 64.56 51.299 64.584 ;
     RECT  51.011 0.192 51.304 62.664 ;
     RECT  51.304 29.568 51.689 29.592 ;
     RECT  51.304 0.192 52.229 13.608 ;
     RECT  51.304 38.16 52.621 38.184 ;
     RECT  52.621 38.112 52.769 38.184 ;
     RECT  51.304 51.312 52.949 51.912 ;
     RECT  51.304 39.264 53.053 39.816 ;
     RECT  51.304 62.16 53.128 62.664 ;
     RECT  53.128 62.16 53.273 62.76 ;
     RECT  52.949 51.888 53.309 51.912 ;
     RECT  53.053 39.216 53.417 39.816 ;
     RECT  52.801 32.016 53.453 32.04 ;
     RECT  53.273 62.16 54.109 62.664 ;
     RECT  54.025 53.904 54.605 53.928 ;
     RECT  51.304 59.712 54.709 59.736 ;
     RECT  52.229 0.192 54.745 11.4 ;
     RECT  54.709 59.712 54.749 59.832 ;
     RECT  54.745 0.096 54.829 11.4 ;
     RECT  54.601 32.4 54.965 32.424 ;
     RECT  54.781 26.784 55.073 26.808 ;
     RECT  55.244 63.264 55.331 63.288 ;
     RECT  55.285 28.416 55.753 28.44 ;
     RECT  55.753 28.272 55.825 28.44 ;
     RECT  55.825 28.224 55.969 28.44 ;
     RECT  54.829 0.192 56.005 11.4 ;
     RECT  56.185 31.68 56.221 31.704 ;
     RECT  54.109 62.16 56.252 62.184 ;
     RECT  56.252 62.16 56.339 62.664 ;
     RECT  56.005 0.096 56.408 11.4 ;
     RECT  52.229 12.48 56.408 13.608 ;
     RECT  51.304 14.736 56.408 14.76 ;
     RECT  51.304 15.792 56.408 17.688 ;
     RECT  51.304 18.768 56.408 19.32 ;
     RECT  51.304 21.456 56.408 21.48 ;
     RECT  56.077 26.784 56.408 26.808 ;
     RECT  55.969 28.224 56.408 29.016 ;
     RECT  56.221 31.44 56.408 31.704 ;
     RECT  52.769 38.112 56.408 38.136 ;
     RECT  53.417 39.216 56.408 39.768 ;
     RECT  55.213 55.152 56.408 55.176 ;
     RECT  54.749 59.808 56.408 59.832 ;
     RECT  56.339 62.16 56.408 62.652 ;
     RECT  56.408 0.096 56.512 62.652 ;
     RECT  56.512 0.096 56.704 62.616 ;
     RECT  56.704 55.152 56.801 55.176 ;
     RECT  56.533 64.608 56.867 64.632 ;
     RECT  56.704 56.256 56.873 57 ;
     RECT  56.873 56.544 56.981 57 ;
     RECT  56.981 56.544 57.341 56.568 ;
     RECT  56.704 0.096 57.644 11.4 ;
     RECT  56.704 28.224 57.697 33.624 ;
     RECT  57.644 0.048 57.731 11.4 ;
     RECT  56.704 62.16 58.309 62.616 ;
     RECT  58.309 62.16 58.421 62.76 ;
     RECT  57.697 28.224 58.453 34.392 ;
     RECT  58.381 58.128 58.489 58.152 ;
     RECT  56.704 59.808 58.525 60.648 ;
     RECT  58.421 62.16 58.525 62.664 ;
     RECT  58.453 28.224 58.669 34.488 ;
     RECT  58.525 59.808 58.673 62.664 ;
     RECT  58.669 28.128 58.741 34.488 ;
     RECT  58.673 59.808 58.835 61.608 ;
     RECT  58.741 52.368 59.069 52.392 ;
     RECT  57.731 0.096 59.105 11.4 ;
     RECT  59.105 0.192 59.209 11.4 ;
     RECT  56.704 12.48 59.209 13.608 ;
     RECT  58.741 28.128 59.209 34.92 ;
     RECT  59.065 56.256 59.209 56.28 ;
     RECT  59.209 55.968 59.245 56.28 ;
     RECT  58.489 57.696 59.245 58.152 ;
     RECT  56.704 15.792 59.281 17.688 ;
     RECT  56.704 18.768 59.281 19.32 ;
     RECT  59.209 28.128 59.281 35.496 ;
     RECT  59.245 55.968 59.281 58.152 ;
     RECT  58.835 59.808 59.281 61.32 ;
     RECT  59.281 28.128 59.461 35.784 ;
     RECT  58.673 62.64 59.797 62.664 ;
     RECT  59.281 15.792 59.857 19.32 ;
     RECT  59.461 28.128 59.893 36.264 ;
     RECT  56.704 38.112 59.893 38.136 ;
     RECT  56.704 39.216 59.893 39.768 ;
     RECT  59.281 55.968 59.996 61.32 ;
     RECT  59.797 62.592 59.996 62.664 ;
     RECT  59.996 55.968 60.001 62.664 ;
     RECT  59.893 28.128 60.217 36.312 ;
     RECT  60.001 55.248 60.253 62.664 ;
     RECT  60.217 28.128 60.289 36.6 ;
     RECT  60.289 28.128 60.325 36.888 ;
     RECT  59.893 38.112 60.325 39.768 ;
     RECT  59.857 15.792 60.397 20.328 ;
     RECT  56.704 21.456 60.397 21.48 ;
     RECT  60.253 54.816 60.433 62.664 ;
     RECT  60.037 63.84 60.611 63.864 ;
     RECT  60.793 23.664 60.865 23.688 ;
     RECT  60.433 54.72 60.865 62.664 ;
     RECT  60.865 23.616 60.937 23.688 ;
     RECT  60.325 28.128 60.973 39.768 ;
     RECT  60.865 54.336 60.973 62.664 ;
     RECT  60.973 54.096 61.045 62.664 ;
     RECT  59.209 0.192 61.189 13.608 ;
     RECT  61.045 54.096 61.189 62.712 ;
     RECT  61.189 53.52 61.369 62.712 ;
     RECT  60.397 15.792 61.441 21.48 ;
     RECT  60.433 22.512 61.441 22.536 ;
     RECT  60.973 28.128 61.441 40.056 ;
     RECT  61.441 15.792 61.513 22.536 ;
     RECT  60.937 23.568 61.513 23.688 ;
     RECT  60.937 26.88 61.513 26.904 ;
     RECT  61.513 26.64 61.549 26.904 ;
     RECT  61.441 28.128 61.549 40.44 ;
     RECT  60.433 47.616 61.585 47.64 ;
     RECT  61.369 52.8 61.621 62.712 ;
     RECT  61.189 0.096 61.633 13.608 ;
     RECT  61.549 26.64 61.729 40.44 ;
     RECT  61.669 64.656 61.729 64.68 ;
     RECT  61.633 0.192 61.808 13.608 ;
     RECT  56.704 14.736 61.808 14.76 ;
     RECT  61.513 15.792 61.808 23.688 ;
     RECT  56.704 25.248 61.808 25.512 ;
     RECT  61.729 26.64 61.808 40.968 ;
     RECT  61.585 47.616 61.808 47.928 ;
     RECT  61.621 52.8 61.808 63.096 ;
     RECT  61.808 0.192 62.104 63.096 ;
     RECT  62.104 61.056 62.125 63.096 ;
     RECT  61.729 64.08 62.125 64.68 ;
     RECT  62.104 51.936 62.129 60.072 ;
     RECT  62.125 61.056 62.156 64.68 ;
     RECT  62.129 52.944 62.237 60.072 ;
     RECT  62.104 15.792 62.243 42.84 ;
     RECT  62.104 0.192 62.597 13.608 ;
     RECT  62.243 15.888 63.205 42.84 ;
     RECT  62.104 46.128 63.205 48.936 ;
     RECT  62.597 12.48 63.241 13.608 ;
     RECT  62.104 14.736 63.241 14.76 ;
     RECT  62.104 50.688 63.241 50.808 ;
     RECT  62.129 51.936 63.241 51.96 ;
     RECT  62.237 52.944 63.241 59.688 ;
     RECT  62.104 44.976 63.277 45 ;
     RECT  63.205 46.128 63.277 49.32 ;
     RECT  63.241 50.688 63.277 59.688 ;
     RECT  62.156 61.056 63.277 64.728 ;
     RECT  63.205 15.888 63.781 43.608 ;
     RECT  63.277 44.592 63.781 45 ;
     RECT  62.597 0.192 63.853 11.352 ;
     RECT  63.241 12.48 63.853 14.76 ;
     RECT  63.781 15.888 63.853 45 ;
     RECT  63.277 46.128 63.853 64.728 ;
     RECT  63.853 0.192 64.681 64.728 ;
     RECT  64.681 0.048 64.764 64.728 ;
     RECT  64.764 59.472 64.793 59.496 ;
    LAYER M5 ;
     RECT  0.192 0.016 64.632 0.611 ;
     RECT  0.192 0.611 21.192 0.755 ;
     RECT  1.968 0.755 21.192 1.763 ;
     RECT  22.176 0.611 64.632 1.763 ;
     RECT  22.656 1.763 24.408 1.811 ;
     RECT  26.688 1.763 26.712 1.811 ;
     RECT  32.784 1.763 33.048 1.811 ;
     RECT  43.872 1.763 46.68 1.811 ;
     RECT  50.88 1.763 57.72 1.811 ;
     RECT  10.8 1.763 11.592 1.859 ;
     RECT  33.024 1.811 33.048 2.099 ;
     RECT  16.848 1.763 19.128 2.195 ;
     RECT  0.192 0.755 0.936 2.291 ;
     RECT  16.848 2.195 17.016 2.291 ;
     RECT  25.44 1.763 25.464 2.291 ;
     RECT  34.512 1.763 37.896 2.291 ;
     RECT  43.872 1.811 46.008 2.291 ;
     RECT  60.048 1.763 64.632 2.291 ;
     RECT  18.384 2.195 19.128 2.339 ;
     RECT  23.184 1.811 24.408 2.339 ;
     RECT  29.28 1.763 31.032 2.339 ;
     RECT  34.56 2.291 37.896 2.339 ;
     RECT  47.664 1.763 49.704 2.339 ;
     RECT  50.88 1.811 54.024 2.339 ;
     RECT  55.008 1.811 57.72 2.339 ;
     RECT  58.8 1.763 58.824 2.339 ;
     RECT  61.056 2.291 64.632 2.339 ;
     RECT  31.008 2.339 31.032 2.387 ;
     RECT  44.4 2.291 46.008 2.771 ;
     RECT  37.296 2.339 37.896 2.869 ;
     RECT  60.048 2.291 60.072 2.869 ;
     RECT  0.672 2.291 0.936 2.915 ;
     RECT  2.4 1.763 9.816 2.915 ;
     RECT  11.04 1.859 11.592 2.915 ;
     RECT  15.6 1.763 15.864 2.915 ;
     RECT  20.4 1.763 21.192 2.915 ;
     RECT  27.984 1.763 28.008 2.915 ;
     RECT  41.616 1.763 41.64 2.915 ;
     RECT  42.624 1.763 42.648 2.915 ;
     RECT  47.664 2.339 48.456 2.915 ;
     RECT  61.152 2.339 63.864 2.915 ;
     RECT  37.296 2.869 38.76 2.917 ;
     RECT  40.2 1.763 40.512 2.917 ;
     RECT  0.912 2.915 0.936 2.963 ;
     RECT  2.4 2.915 9.048 2.965 ;
     RECT  50.88 2.339 51.312 2.965 ;
     RECT  24 2.339 24.408 3.059 ;
     RECT  37.296 2.917 40.512 3.251 ;
     RECT  20.4 2.915 20.424 3.299 ;
     RECT  59.808 2.869 60.072 3.397 ;
     RECT  61.152 2.915 63.624 3.397 ;
     RECT  16.992 2.291 17.016 3.443 ;
     RECT  37.296 3.251 38.76 3.443 ;
     RECT  47.664 2.915 47.688 3.443 ;
     RECT  50.544 2.965 51.312 3.443 ;
     RECT  55.008 2.339 55.272 3.443 ;
     RECT  2.256 2.965 9.048 3.685 ;
     RECT  24 3.059 24.312 3.685 ;
     RECT  23.28 3.685 24.312 3.827 ;
     RECT  29.28 2.339 30.024 3.829 ;
     RECT  34.56 2.339 35.592 3.925 ;
     RECT  13.2 1.763 14.328 4.019 ;
     RECT  37.872 3.443 38.76 4.019 ;
     RECT  50.832 3.443 51.312 4.019 ;
     RECT  55.248 3.443 55.272 4.019 ;
     RECT  18.384 2.339 18.912 4.067 ;
     RECT  34.56 3.925 35.832 4.309 ;
     RECT  29.136 3.829 30.024 4.355 ;
     RECT  24 3.827 24.312 4.357 ;
     RECT  54 2.339 54.024 4.451 ;
     RECT  59.808 3.397 63.624 4.547 ;
     RECT  44.4 2.771 45.912 4.595 ;
     RECT  56.4 2.339 57.72 4.595 ;
     RECT  15.84 2.915 15.864 4.691 ;
     RECT  24 4.357 24.408 4.933 ;
     RECT  2.208 3.685 9.048 5.125 ;
     RECT  2.208 5.125 9.576 5.171 ;
     RECT  37.872 4.019 38.616 5.171 ;
     RECT  9.552 5.171 9.576 5.173 ;
     RECT  24 4.933 24.504 5.173 ;
     RECT  24 5.173 24.984 5.363 ;
     RECT  34.224 4.309 35.832 5.363 ;
     RECT  9.552 5.173 9.672 5.411 ;
     RECT  34.32 5.363 35.832 5.507 ;
     RECT  29.4 4.355 30.024 5.747 ;
     RECT  34.32 5.507 35.688 5.747 ;
     RECT  56.4 4.595 57.336 5.747 ;
     RECT  64.608 4.693 64.632 5.747 ;
     RECT  9.552 5.411 9.576 5.843 ;
     RECT  37.872 5.171 37.896 6.083 ;
     RECT  20.688 6.037 20.712 6.179 ;
     RECT  59.808 4.547 62.856 6.227 ;
     RECT  34.56 5.747 35.688 6.323 ;
     RECT  34.704 6.323 35.688 6.419 ;
     RECT  24 5.363 24.504 6.515 ;
     RECT  59.808 6.227 62.112 6.515 ;
     RECT  42.288 6.613 42.312 6.805 ;
     RECT  42.288 6.805 43.176 6.851 ;
     RECT  13.2 4.019 13.512 6.901 ;
     RECT  2.208 5.171 8.112 6.947 ;
     RECT  45.6 4.595 45.912 6.949 ;
     RECT  60.384 6.515 62.112 7.043 ;
     RECT  51 4.019 51.312 7.093 ;
     RECT  15.408 6.805 15.432 7.141 ;
     RECT  15.408 7.141 15.72 7.187 ;
     RECT  30.912 6.853 30.936 7.187 ;
     RECT  18.6 4.067 18.912 7.237 ;
     RECT  9.744 6.805 9.768 7.283 ;
     RECT  50.832 7.093 51.312 7.333 ;
     RECT  43.152 6.851 43.176 7.379 ;
     RECT  45.6 6.949 46.152 7.571 ;
     RECT  34.704 6.419 35.304 7.619 ;
     RECT  2.304 6.947 8.112 7.667 ;
     RECT  50.784 7.333 51.312 7.765 ;
     RECT  18.6 7.237 19.128 7.907 ;
     RECT  17.136 8.053 17.16 8.195 ;
     RECT  27.888 8.293 27.912 8.341 ;
     RECT  29.4 5.747 29.712 8.341 ;
     RECT  34.8 7.619 35.304 8.437 ;
     RECT  26.208 8.101 26.232 8.579 ;
     RECT  40.2 3.251 40.512 8.725 ;
     RECT  41.856 7.381 41.88 8.773 ;
     RECT  41.856 8.773 42.168 8.819 ;
     RECT  37.008 8.581 37.032 8.821 ;
     RECT  40.2 8.725 40.872 8.821 ;
     RECT  42.048 8.819 42.168 8.963 ;
     RECT  42.144 8.963 42.168 9.011 ;
     RECT  40.08 8.821 40.872 9.059 ;
     RECT  61.056 7.043 62.112 9.059 ;
     RECT  36.96 8.821 37.032 9.061 ;
     RECT  40.08 9.059 40.632 9.107 ;
     RECT  27.888 8.341 29.712 9.155 ;
     RECT  34.8 8.437 35.928 9.155 ;
     RECT  26.016 9.109 26.04 9.443 ;
     RECT  50.112 7.765 51.312 9.539 ;
     RECT  61.152 9.059 62.112 9.539 ;
     RECT  13.104 6.901 13.512 9.587 ;
     RECT  15.696 7.187 15.72 9.637 ;
     RECT  51 9.539 51.312 9.637 ;
     RECT  27.888 9.155 27.912 9.685 ;
     RECT  15.696 9.637 16.68 9.731 ;
     RECT  36.96 9.061 37.32 9.731 ;
     RECT  40.08 9.107 40.512 9.731 ;
     RECT  37.296 9.731 37.32 9.779 ;
     RECT  22.512 7.861 22.536 9.827 ;
     RECT  61.584 9.539 62.112 10.115 ;
     RECT  27.072 9.685 27.912 10.163 ;
     RECT  51 9.637 51.864 10.307 ;
     RECT  34.8 9.155 35.208 10.355 ;
     RECT  13.2 9.587 13.512 10.693 ;
     RECT  59.52 9.061 59.544 10.837 ;
     RECT  46.992 9.061 47.016 10.883 ;
     RECT  15.648 9.925 15.672 10.979 ;
     RECT  2.4 7.667 8.112 10.981 ;
     RECT  16.656 9.731 16.68 11.171 ;
     RECT  59.52 10.837 60.456 11.363 ;
     RECT  2.4 10.981 8.52 11.411 ;
     RECT  61.68 10.115 62.112 11.507 ;
     RECT  59.52 11.363 59.544 12.035 ;
     RECT  7.8 11.411 8.52 12.275 ;
     RECT  13.104 10.693 13.512 12.755 ;
     RECT  61.8 11.507 62.112 12.805 ;
     RECT  61.68 12.805 62.112 13.043 ;
     RECT  2.4 11.411 6.792 13.283 ;
     RECT  61.8 13.043 62.112 15.781 ;
     RECT  61.8 15.781 62.232 15.923 ;
     RECT  34.8 10.355 35.112 18.853 ;
     RECT  33.984 18.853 35.112 19.091 ;
     RECT  64.608 21.925 64.632 22.067 ;
     RECT  38.736 8.773 38.76 26.773 ;
     RECT  27.072 10.163 27.096 26.819 ;
     RECT  38.544 26.773 38.76 26.819 ;
     RECT  61.8 15.923 62.112 33.445 ;
     RECT  60.24 33.541 60.264 33.589 ;
     RECT  61.44 33.445 62.112 33.589 ;
     RECT  60.24 33.589 62.112 33.925 ;
     RECT  59.472 33.925 62.112 34.165 ;
     RECT  32.448 27.109 32.472 34.259 ;
     RECT  6.768 13.283 6.792 34.835 ;
     RECT  2.4 13.283 5.784 35.317 ;
     RECT  2.4 35.317 6.216 35.363 ;
     RECT  2.4 35.363 4.296 35.411 ;
     RECT  59.184 34.165 62.112 35.797 ;
     RECT  4.272 35.411 4.296 35.939 ;
     RECT  0.096 34.645 0.12 36.373 ;
     RECT  5.376 35.363 6.216 36.421 ;
     RECT  2.4 35.411 3.144 36.563 ;
     RECT  7.8 12.275 8.112 37.429 ;
     RECT  5.328 36.421 6.216 38.149 ;
     RECT  7.632 37.429 8.112 38.149 ;
     RECT  2.4 36.563 2.952 38.677 ;
     RECT  5.328 38.149 8.112 38.725 ;
     RECT  9.744 38.245 9.768 38.725 ;
     RECT  4.608 38.725 9.768 38.821 ;
     RECT  11.232 38.725 11.544 39.061 ;
     RECT  13.2 12.755 13.512 39.061 ;
     RECT  4.608 38.821 10.008 39.253 ;
     RECT  4.368 39.253 10.008 39.301 ;
     RECT  11.232 39.061 13.512 39.301 ;
     RECT  38.544 26.819 38.568 39.877 ;
     RECT  4.368 39.301 13.512 40.165 ;
     RECT  4.368 40.165 14.04 40.405 ;
     RECT  38.496 39.877 38.568 40.405 ;
     RECT  38.496 40.405 39.048 40.885 ;
     RECT  38.496 40.885 39.144 40.981 ;
     RECT  0.096 36.373 0.696 41.461 ;
     RECT  1.92 38.677 2.952 41.461 ;
     RECT  16.272 41.221 16.296 41.509 ;
     RECT  4.368 40.405 15.192 41.557 ;
     RECT  16.176 41.509 16.536 41.557 ;
     RECT  38.496 40.981 39.192 41.557 ;
     RECT  40.2 9.731 40.512 41.557 ;
     RECT  4.368 41.557 16.536 41.749 ;
     RECT  4.368 41.749 17.16 43.285 ;
     RECT  4.368 43.285 17.544 45.013 ;
     RECT  18.6 7.907 18.912 45.013 ;
     RECT  21.072 43.285 21.096 45.013 ;
     RECT  24 6.515 24.312 45.013 ;
     RECT  4.368 45.013 24.312 45.541 ;
     RECT  0.096 41.461 2.952 46.645 ;
     RECT  4.368 45.541 25.368 46.645 ;
     RECT  0.096 46.645 25.368 48.469 ;
     RECT  29.4 9.155 29.712 48.469 ;
     RECT  27.12 48.469 30.648 48.805 ;
     RECT  0.096 48.469 26.136 48.997 ;
     RECT  27.12 48.805 31.56 48.997 ;
     RECT  0.096 48.997 31.56 49.045 ;
     RECT  0.096 49.045 31.896 49.525 ;
     RECT  38.496 41.557 40.512 51.925 ;
     RECT  0.096 49.525 32.904 52.405 ;
     RECT  34.8 19.091 35.112 52.453 ;
     RECT  38.16 51.925 40.512 52.453 ;
     RECT  0.096 52.405 33.432 52.501 ;
     RECT  34.416 52.453 40.512 52.501 ;
     RECT  0.096 52.501 40.512 52.981 ;
     RECT  0.096 52.981 40.632 53.365 ;
     RECT  0.096 53.365 40.968 53.557 ;
     RECT  0.096 53.557 41.208 54.085 ;
     RECT  0.096 54.085 41.448 54.133 ;
     RECT  0.096 54.133 41.976 54.373 ;
     RECT  0.096 54.373 42.744 54.469 ;
     RECT  0.096 54.469 43.224 55.861 ;
     RECT  45.6 7.571 45.912 55.861 ;
     RECT  59.184 35.797 62.808 56.245 ;
     RECT  59.184 56.245 62.952 56.293 ;
     RECT  0.096 55.861 45.912 56.341 ;
     RECT  59.184 56.293 63.24 57.059 ;
     RECT  59.184 57.059 63.192 59.221 ;
     RECT  59.184 59.221 63.816 59.797 ;
     RECT  58.56 59.797 63.816 59.891 ;
     RECT  60.192 59.891 63.816 60.949 ;
     RECT  0.096 56.341 46.056 60.997 ;
     RECT  58.56 59.891 59.208 61.043 ;
     RECT  60.192 60.949 64.392 61.091 ;
     RECT  51 10.307 51.312 62.149 ;
     RECT  56.4 5.747 56.712 62.149 ;
     RECT  58.56 61.043 58.824 62.149 ;
     RECT  60.96 61.091 64.392 62.149 ;
     RECT  60.048 62.149 64.392 62.485 ;
     RECT  60.048 62.485 64.632 62.581 ;
     RECT  50.832 62.149 58.824 62.629 ;
     RECT  59.808 62.581 64.632 62.629 ;
     RECT  0.096 60.997 46.776 62.677 ;
     RECT  48.24 62.149 48.264 62.677 ;
     RECT  49.248 62.629 64.632 62.677 ;
     RECT  0.096 62.677 64.632 64.739 ;
     RECT  0.192 64.739 64.632 64.784 ;
     RECT  21.192 0.611 22.176 1.763 ;
     RECT  0.936 0.755 1.968 1.763 ;
     RECT  0.936 1.763 2.4 2.963 ;
     RECT  9.816 1.763 10.8 1.859 ;
     RECT  14.328 1.763 15.6 2.915 ;
     RECT  15.864 1.763 16.848 2.291 ;
     RECT  19.128 1.763 20.4 2.339 ;
     RECT  21.192 1.763 22.656 1.811 ;
     RECT  24.408 1.763 25.44 2.291 ;
     RECT  25.464 1.763 26.688 1.811 ;
     RECT  26.712 1.763 27.984 1.811 ;
     RECT  28.008 1.763 29.28 2.915 ;
     RECT  33.048 1.763 34.512 2.099 ;
     RECT  37.896 1.763 40.2 2.869 ;
     RECT  40.512 1.763 41.616 2.915 ;
     RECT  41.64 1.763 42.624 2.915 ;
     RECT  42.648 1.763 43.872 2.291 ;
     RECT  46.68 1.763 47.664 1.811 ;
     RECT  49.704 1.763 50.88 2.339 ;
     RECT  57.72 1.763 58.8 2.339 ;
     RECT  58.824 1.763 60.048 2.339 ;
     RECT  54.024 1.811 55.008 3.443 ;
     RECT  9.816 1.859 11.04 2.915 ;
     RECT  17.016 2.195 18.384 3.443 ;
     RECT  15.864 2.291 16.992 3.443 ;
     RECT  60.072 2.291 61.056 2.339 ;
     RECT  18.912 2.339 20.4 3.299 ;
     RECT  23.28 2.339 24 3.685 ;
     RECT  30.024 2.339 31.008 2.387 ;
     RECT  50.544 2.339 50.88 2.965 ;
     RECT  55.272 2.339 56.4 4.019 ;
     RECT  59.808 2.339 60.048 2.869 ;
     RECT  60.072 2.339 61.152 3.397 ;
     RECT  38.76 2.869 40.2 2.917 ;
     RECT  14.328 2.915 15.84 4.019 ;
     RECT  29.136 2.915 29.28 3.829 ;
     RECT  2.208 2.963 2.4 2.965 ;
     RECT  2.208 2.965 2.256 3.685 ;
     RECT  24.312 3.059 24.408 4.357 ;
     RECT  38.76 3.251 40.2 4.019 ;
     RECT  54.024 3.443 55.248 4.019 ;
     RECT  8.112 5.171 9.552 5.843 ;
     RECT  29.712 5.747 30.024 6.853 ;
     RECT  29.712 6.853 30.912 7.187 ;
     RECT  40.512 7.381 41.856 8.725 ;
     RECT  45.912 7.571 46.152 9.061 ;
     RECT  22.536 7.861 24 9.827 ;
     RECT  15.72 8.053 17.136 8.195 ;
     RECT  17.16 8.053 18.6 8.195 ;
     RECT  15.72 8.195 16.68 9.637 ;
     RECT  27.912 8.293 29.4 8.341 ;
     RECT  35.928 8.581 37.008 8.821 ;
     RECT  40.872 8.725 41.856 8.819 ;
     RECT  38.76 8.773 40.2 8.821 ;
     RECT  40.872 8.819 42.048 8.963 ;
     RECT  35.928 8.821 36.96 9.155 ;
     RECT  38.76 8.821 40.08 9.731 ;
     RECT  40.872 8.963 42.144 9.011 ;
     RECT  37.32 9.061 38.736 9.779 ;
     RECT  45.912 9.061 46.992 10.883 ;
     RECT  27.912 9.155 29.4 10.163 ;
     RECT  61.152 9.539 61.584 10.115 ;
     RECT  13.104 9.587 13.2 10.693 ;
     RECT  15.696 9.731 16.656 9.925 ;
     RECT  38.76 9.731 40.2 26.819 ;
     RECT  15.672 9.925 16.656 10.979 ;
     RECT  61.152 10.115 61.68 10.837 ;
     RECT  60.456 10.837 61.68 11.363 ;
     RECT  6.792 11.411 7.8 34.835 ;
     RECT  61.68 11.507 61.8 12.805 ;
     RECT  5.784 13.283 6.768 34.835 ;
     RECT  60.264 33.541 61.44 33.589 ;
     RECT  5.784 34.835 6.216 35.317 ;
     RECT  4.296 35.363 5.376 35.939 ;
     RECT  3.144 35.411 4.272 35.939 ;
     RECT  5.328 35.939 5.376 36.421 ;
     RECT  6.216 37.429 7.632 38.149 ;
     RECT  0.696 38.677 1.92 41.461 ;
     RECT  9.768 38.725 11.232 38.821 ;
     RECT  10.008 38.821 11.232 39.301 ;
     RECT  2.952 39.253 4.368 46.645 ;
     RECT  39.048 40.405 40.2 40.885 ;
     RECT  39.144 40.885 40.2 40.981 ;
     RECT  39.192 40.981 40.2 41.557 ;
     RECT  15.192 41.221 16.272 41.509 ;
     RECT  15.192 41.509 16.176 41.557 ;
     RECT  17.16 41.749 18.6 43.285 ;
     RECT  17.544 43.285 18.6 45.013 ;
     RECT  26.136 48.469 27.12 48.997 ;
     RECT  33.432 52.405 34.8 52.453 ;
     RECT  33.432 52.453 34.416 52.501 ;
     RECT  59.208 59.891 60.192 61.043 ;
     RECT  58.824 61.043 60.192 61.091 ;
     RECT  58.824 61.091 60.96 62.149 ;
     RECT  46.776 62.149 48.24 62.677 ;
     RECT  58.824 62.149 60.048 62.581 ;
     RECT  58.824 62.581 59.808 62.629 ;
     RECT  48.264 62.629 49.248 62.677 ;
  END
END ot_hgi_b2_dma_groupface
END LIBRARY
